VERSION 5.8 ;
BUSBITCHARS "[]" ;
DIVIDERCHAR "/" ;
UNITS
    DATABASE MICRONS 1000 ;
END UNITS

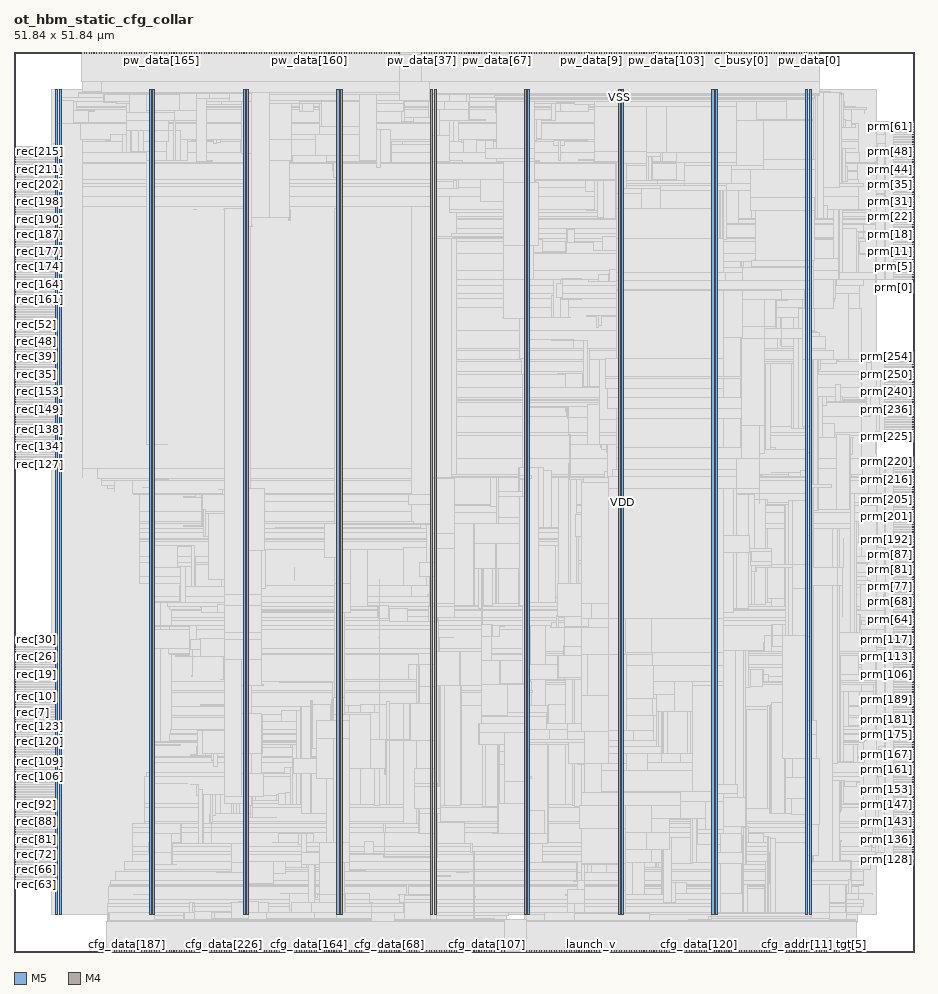
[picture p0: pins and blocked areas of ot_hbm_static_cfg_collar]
MACRO ot_hbm_static_cfg_collar
  FOREIGN ot_hbm_static_cfg_collar 0 0 ;
  CLASS BLOCK ;
  SIZE 51.84 BY 51.84 ;
  PIN active
    DIRECTION OUTPUT ;
    USE SIGNAL ;
    PORT
      LAYER M5 ;
        RECT  43.344 0 43.368 0.084 ;
    END
  END active
  PIN c_busy[0]
    DIRECTION INPUT ;
    USE SIGNAL ;
    PORT
      LAYER M5 ;
        RECT  41.904 51.756 41.928 51.84 ;
    END
  END c_busy[0]
  PIN c_busy[1]
    DIRECTION INPUT ;
    USE SIGNAL ;
    PORT
      LAYER M5 ;
        RECT  42.048 51.756 42.072 51.84 ;
    END
  END c_busy[1]
  PIN c_done
    DIRECTION INPUT ;
    USE SIGNAL ;
    PORT
      LAYER M5 ;
        RECT  42.192 51.756 42.216 51.84 ;
    END
  END c_done
  PIN c_fault[0]
    DIRECTION INPUT ;
    USE SIGNAL ;
    PORT
      LAYER M5 ;
        RECT  42.336 51.756 42.36 51.84 ;
    END
  END c_fault[0]
  PIN cfg_addr[0]
    DIRECTION INPUT ;
    USE SIGNAL ;
    PORT
      LAYER M5 ;
        RECT  43.488 0 43.512 0.084 ;
    END
  END cfg_addr[0]
  PIN cfg_addr[10]
    DIRECTION INPUT ;
    USE SIGNAL ;
    PORT
      LAYER M5 ;
        RECT  44.928 0 44.952 0.084 ;
    END
  END cfg_addr[10]
  PIN cfg_addr[11]
    DIRECTION INPUT ;
    USE SIGNAL ;
    PORT
      LAYER M5 ;
        RECT  45.072 0 45.096 0.084 ;
    END
  END cfg_addr[11]
  PIN cfg_addr[1]
    DIRECTION INPUT ;
    USE SIGNAL ;
    PORT
      LAYER M5 ;
        RECT  43.632 0 43.656 0.084 ;
    END
  END cfg_addr[1]
  PIN cfg_addr[2]
    DIRECTION INPUT ;
    USE SIGNAL ;
    PORT
      LAYER M5 ;
        RECT  43.776 0 43.8 0.084 ;
    END
  END cfg_addr[2]
  PIN cfg_addr[3]
    DIRECTION INPUT ;
    USE SIGNAL ;
    PORT
      LAYER M5 ;
        RECT  43.92 0 43.944 0.084 ;
    END
  END cfg_addr[3]
  PIN cfg_addr[4]
    DIRECTION INPUT ;
    USE SIGNAL ;
    PORT
      LAYER M5 ;
        RECT  44.064 0 44.088 0.084 ;
    END
  END cfg_addr[4]
  PIN cfg_addr[5]
    DIRECTION INPUT ;
    USE SIGNAL ;
    PORT
      LAYER M5 ;
        RECT  44.208 0 44.232 0.084 ;
    END
  END cfg_addr[5]
  PIN cfg_addr[6]
    DIRECTION INPUT ;
    USE SIGNAL ;
    PORT
      LAYER M5 ;
        RECT  44.352 0 44.376 0.084 ;
    END
  END cfg_addr[6]
  PIN cfg_addr[7]
    DIRECTION INPUT ;
    USE SIGNAL ;
    PORT
      LAYER M5 ;
        RECT  44.496 0 44.52 0.084 ;
    END
  END cfg_addr[7]
  PIN cfg_addr[8]
    DIRECTION INPUT ;
    USE SIGNAL ;
    PORT
      LAYER M5 ;
        RECT  44.64 0 44.664 0.084 ;
    END
  END cfg_addr[8]
  PIN cfg_addr[9]
    DIRECTION INPUT ;
    USE SIGNAL ;
    PORT
      LAYER M5 ;
        RECT  44.784 0 44.808 0.084 ;
    END
  END cfg_addr[9]
  PIN cfg_data[0]
    DIRECTION INPUT ;
    USE SIGNAL ;
    PORT
      LAYER M5 ;
        RECT  45.216 0 45.24 0.084 ;
    END
  END cfg_data[0]
  PIN cfg_data[100]
    DIRECTION INPUT ;
    USE SIGNAL ;
    PORT
      LAYER M5 ;
        RECT  26.208 0 26.232 0.084 ;
    END
  END cfg_data[100]
  PIN cfg_data[101]
    DIRECTION INPUT ;
    USE SIGNAL ;
    PORT
      LAYER M5 ;
        RECT  26.352 0 26.376 0.084 ;
    END
  END cfg_data[101]
  PIN cfg_data[102]
    DIRECTION INPUT ;
    USE SIGNAL ;
    PORT
      LAYER M5 ;
        RECT  26.496 0 26.52 0.084 ;
    END
  END cfg_data[102]
  PIN cfg_data[103]
    DIRECTION INPUT ;
    USE SIGNAL ;
    PORT
      LAYER M5 ;
        RECT  26.64 0 26.664 0.084 ;
    END
  END cfg_data[103]
  PIN cfg_data[104]
    DIRECTION INPUT ;
    USE SIGNAL ;
    PORT
      LAYER M5 ;
        RECT  26.784 0 26.808 0.084 ;
    END
  END cfg_data[104]
  PIN cfg_data[105]
    DIRECTION INPUT ;
    USE SIGNAL ;
    PORT
      LAYER M5 ;
        RECT  26.928 0 26.952 0.084 ;
    END
  END cfg_data[105]
  PIN cfg_data[106]
    DIRECTION INPUT ;
    USE SIGNAL ;
    PORT
      LAYER M5 ;
        RECT  27.072 0 27.096 0.084 ;
    END
  END cfg_data[106]
  PIN cfg_data[107]
    DIRECTION INPUT ;
    USE SIGNAL ;
    PORT
      LAYER M5 ;
        RECT  27.216 0 27.24 0.084 ;
    END
  END cfg_data[107]
  PIN cfg_data[108]
    DIRECTION INPUT ;
    USE SIGNAL ;
    PORT
      LAYER M5 ;
        RECT  27.36 0 27.384 0.084 ;
    END
  END cfg_data[108]
  PIN cfg_data[109]
    DIRECTION INPUT ;
    USE SIGNAL ;
    PORT
      LAYER M5 ;
        RECT  27.504 0 27.528 0.084 ;
    END
  END cfg_data[109]
  PIN cfg_data[10]
    DIRECTION INPUT ;
    USE SIGNAL ;
    PORT
      LAYER M5 ;
        RECT  46.656 0 46.68 0.084 ;
    END
  END cfg_data[10]
  PIN cfg_data[110]
    DIRECTION INPUT ;
    USE SIGNAL ;
    PORT
      LAYER M5 ;
        RECT  27.648 0 27.672 0.084 ;
    END
  END cfg_data[110]
  PIN cfg_data[111]
    DIRECTION INPUT ;
    USE SIGNAL ;
    PORT
      LAYER M5 ;
        RECT  27.792 0 27.816 0.084 ;
    END
  END cfg_data[111]
  PIN cfg_data[112]
    DIRECTION INPUT ;
    USE SIGNAL ;
    PORT
      LAYER M5 ;
        RECT  27.936 0 27.96 0.084 ;
    END
  END cfg_data[112]
  PIN cfg_data[113]
    DIRECTION INPUT ;
    USE SIGNAL ;
    PORT
      LAYER M5 ;
        RECT  28.08 0 28.104 0.084 ;
    END
  END cfg_data[113]
  PIN cfg_data[114]
    DIRECTION INPUT ;
    USE SIGNAL ;
    PORT
      LAYER M5 ;
        RECT  28.224 0 28.248 0.084 ;
    END
  END cfg_data[114]
  PIN cfg_data[115]
    DIRECTION INPUT ;
    USE SIGNAL ;
    PORT
      LAYER M5 ;
        RECT  38.736 0 38.76 0.084 ;
    END
  END cfg_data[115]
  PIN cfg_data[116]
    DIRECTION INPUT ;
    USE SIGNAL ;
    PORT
      LAYER M5 ;
        RECT  38.88 0 38.904 0.084 ;
    END
  END cfg_data[116]
  PIN cfg_data[117]
    DIRECTION INPUT ;
    USE SIGNAL ;
    PORT
      LAYER M5 ;
        RECT  39.024 0 39.048 0.084 ;
    END
  END cfg_data[117]
  PIN cfg_data[118]
    DIRECTION INPUT ;
    USE SIGNAL ;
    PORT
      LAYER M5 ;
        RECT  39.168 0 39.192 0.084 ;
    END
  END cfg_data[118]
  PIN cfg_data[119]
    DIRECTION INPUT ;
    USE SIGNAL ;
    PORT
      LAYER M5 ;
        RECT  39.312 0 39.336 0.084 ;
    END
  END cfg_data[119]
  PIN cfg_data[11]
    DIRECTION INPUT ;
    USE SIGNAL ;
    PORT
      LAYER M5 ;
        RECT  46.8 0 46.824 0.084 ;
    END
  END cfg_data[11]
  PIN cfg_data[120]
    DIRECTION INPUT ;
    USE SIGNAL ;
    PORT
      LAYER M5 ;
        RECT  39.456 0 39.48 0.084 ;
    END
  END cfg_data[120]
  PIN cfg_data[121]
    DIRECTION INPUT ;
    USE SIGNAL ;
    PORT
      LAYER M5 ;
        RECT  39.6 0 39.624 0.084 ;
    END
  END cfg_data[121]
  PIN cfg_data[122]
    DIRECTION INPUT ;
    USE SIGNAL ;
    PORT
      LAYER M5 ;
        RECT  39.744 0 39.768 0.084 ;
    END
  END cfg_data[122]
  PIN cfg_data[123]
    DIRECTION INPUT ;
    USE SIGNAL ;
    PORT
      LAYER M5 ;
        RECT  39.888 0 39.912 0.084 ;
    END
  END cfg_data[123]
  PIN cfg_data[124]
    DIRECTION INPUT ;
    USE SIGNAL ;
    PORT
      LAYER M5 ;
        RECT  40.032 0 40.056 0.084 ;
    END
  END cfg_data[124]
  PIN cfg_data[125]
    DIRECTION INPUT ;
    USE SIGNAL ;
    PORT
      LAYER M5 ;
        RECT  40.176 0 40.2 0.084 ;
    END
  END cfg_data[125]
  PIN cfg_data[126]
    DIRECTION INPUT ;
    USE SIGNAL ;
    PORT
      LAYER M5 ;
        RECT  40.32 0 40.344 0.084 ;
    END
  END cfg_data[126]
  PIN cfg_data[127]
    DIRECTION INPUT ;
    USE SIGNAL ;
    PORT
      LAYER M5 ;
        RECT  40.464 0 40.488 0.084 ;
    END
  END cfg_data[127]
  PIN cfg_data[128]
    DIRECTION INPUT ;
    USE SIGNAL ;
    PORT
      LAYER M5 ;
        RECT  40.608 0 40.632 0.084 ;
    END
  END cfg_data[128]
  PIN cfg_data[129]
    DIRECTION INPUT ;
    USE SIGNAL ;
    PORT
      LAYER M5 ;
        RECT  40.752 0 40.776 0.084 ;
    END
  END cfg_data[129]
  PIN cfg_data[12]
    DIRECTION INPUT ;
    USE SIGNAL ;
    PORT
      LAYER M5 ;
        RECT  46.944 0 46.968 0.084 ;
    END
  END cfg_data[12]
  PIN cfg_data[130]
    DIRECTION INPUT ;
    USE SIGNAL ;
    PORT
      LAYER M5 ;
        RECT  40.896 0 40.92 0.084 ;
    END
  END cfg_data[130]
  PIN cfg_data[131]
    DIRECTION INPUT ;
    USE SIGNAL ;
    PORT
      LAYER M5 ;
        RECT  41.04 0 41.064 0.084 ;
    END
  END cfg_data[131]
  PIN cfg_data[132]
    DIRECTION INPUT ;
    USE SIGNAL ;
    PORT
      LAYER M5 ;
        RECT  41.184 0 41.208 0.084 ;
    END
  END cfg_data[132]
  PIN cfg_data[133]
    DIRECTION INPUT ;
    USE SIGNAL ;
    PORT
      LAYER M5 ;
        RECT  41.328 0 41.352 0.084 ;
    END
  END cfg_data[133]
  PIN cfg_data[134]
    DIRECTION INPUT ;
    USE SIGNAL ;
    PORT
      LAYER M5 ;
        RECT  41.472 0 41.496 0.084 ;
    END
  END cfg_data[134]
  PIN cfg_data[135]
    DIRECTION INPUT ;
    USE SIGNAL ;
    PORT
      LAYER M5 ;
        RECT  41.616 0 41.64 0.084 ;
    END
  END cfg_data[135]
  PIN cfg_data[136]
    DIRECTION INPUT ;
    USE SIGNAL ;
    PORT
      LAYER M5 ;
        RECT  41.76 0 41.784 0.084 ;
    END
  END cfg_data[136]
  PIN cfg_data[137]
    DIRECTION INPUT ;
    USE SIGNAL ;
    PORT
      LAYER M5 ;
        RECT  41.904 0 41.928 0.084 ;
    END
  END cfg_data[137]
  PIN cfg_data[138]
    DIRECTION INPUT ;
    USE SIGNAL ;
    PORT
      LAYER M5 ;
        RECT  42.048 0 42.072 0.084 ;
    END
  END cfg_data[138]
  PIN cfg_data[139]
    DIRECTION INPUT ;
    USE SIGNAL ;
    PORT
      LAYER M5 ;
        RECT  42.192 0 42.216 0.084 ;
    END
  END cfg_data[139]
  PIN cfg_data[13]
    DIRECTION INPUT ;
    USE SIGNAL ;
    PORT
      LAYER M5 ;
        RECT  47.088 0 47.112 0.084 ;
    END
  END cfg_data[13]
  PIN cfg_data[140]
    DIRECTION INPUT ;
    USE SIGNAL ;
    PORT
      LAYER M5 ;
        RECT  42.336 0 42.36 0.084 ;
    END
  END cfg_data[140]
  PIN cfg_data[141]
    DIRECTION INPUT ;
    USE SIGNAL ;
    PORT
      LAYER M5 ;
        RECT  42.48 0 42.504 0.084 ;
    END
  END cfg_data[141]
  PIN cfg_data[142]
    DIRECTION INPUT ;
    USE SIGNAL ;
    PORT
      LAYER M5 ;
        RECT  42.624 0 42.648 0.084 ;
    END
  END cfg_data[142]
  PIN cfg_data[143]
    DIRECTION INPUT ;
    USE SIGNAL ;
    PORT
      LAYER M5 ;
        RECT  42.768 0 42.792 0.084 ;
    END
  END cfg_data[143]
  PIN cfg_data[144]
    DIRECTION INPUT ;
    USE SIGNAL ;
    PORT
      LAYER M5 ;
        RECT  42.912 0 42.936 0.084 ;
    END
  END cfg_data[144]
  PIN cfg_data[145]
    DIRECTION INPUT ;
    USE SIGNAL ;
    PORT
      LAYER M5 ;
        RECT  43.056 0 43.08 0.084 ;
    END
  END cfg_data[145]
  PIN cfg_data[146]
    DIRECTION INPUT ;
    USE SIGNAL ;
    PORT
      LAYER M5 ;
        RECT  43.2 0 43.224 0.084 ;
    END
  END cfg_data[146]
  PIN cfg_data[147]
    DIRECTION INPUT ;
    USE SIGNAL ;
    PORT
      LAYER M5 ;
        RECT  14.544 0 14.568 0.084 ;
    END
  END cfg_data[147]
  PIN cfg_data[148]
    DIRECTION INPUT ;
    USE SIGNAL ;
    PORT
      LAYER M5 ;
        RECT  14.688 0 14.712 0.084 ;
    END
  END cfg_data[148]
  PIN cfg_data[149]
    DIRECTION INPUT ;
    USE SIGNAL ;
    PORT
      LAYER M5 ;
        RECT  14.832 0 14.856 0.084 ;
    END
  END cfg_data[149]
  PIN cfg_data[14]
    DIRECTION INPUT ;
    USE SIGNAL ;
    PORT
      LAYER M5 ;
        RECT  47.232 0 47.256 0.084 ;
    END
  END cfg_data[14]
  PIN cfg_data[150]
    DIRECTION INPUT ;
    USE SIGNAL ;
    PORT
      LAYER M5 ;
        RECT  14.976 0 15 0.084 ;
    END
  END cfg_data[150]
  PIN cfg_data[151]
    DIRECTION INPUT ;
    USE SIGNAL ;
    PORT
      LAYER M5 ;
        RECT  15.12 0 15.144 0.084 ;
    END
  END cfg_data[151]
  PIN cfg_data[152]
    DIRECTION INPUT ;
    USE SIGNAL ;
    PORT
      LAYER M5 ;
        RECT  15.264 0 15.288 0.084 ;
    END
  END cfg_data[152]
  PIN cfg_data[153]
    DIRECTION INPUT ;
    USE SIGNAL ;
    PORT
      LAYER M5 ;
        RECT  15.408 0 15.432 0.084 ;
    END
  END cfg_data[153]
  PIN cfg_data[154]
    DIRECTION INPUT ;
    USE SIGNAL ;
    PORT
      LAYER M5 ;
        RECT  15.552 0 15.576 0.084 ;
    END
  END cfg_data[154]
  PIN cfg_data[155]
    DIRECTION INPUT ;
    USE SIGNAL ;
    PORT
      LAYER M5 ;
        RECT  15.696 0 15.72 0.084 ;
    END
  END cfg_data[155]
  PIN cfg_data[156]
    DIRECTION INPUT ;
    USE SIGNAL ;
    PORT
      LAYER M5 ;
        RECT  15.84 0 15.864 0.084 ;
    END
  END cfg_data[156]
  PIN cfg_data[157]
    DIRECTION INPUT ;
    USE SIGNAL ;
    PORT
      LAYER M5 ;
        RECT  15.984 0 16.008 0.084 ;
    END
  END cfg_data[157]
  PIN cfg_data[158]
    DIRECTION INPUT ;
    USE SIGNAL ;
    PORT
      LAYER M5 ;
        RECT  16.128 0 16.152 0.084 ;
    END
  END cfg_data[158]
  PIN cfg_data[159]
    DIRECTION INPUT ;
    USE SIGNAL ;
    PORT
      LAYER M5 ;
        RECT  16.272 0 16.296 0.084 ;
    END
  END cfg_data[159]
  PIN cfg_data[15]
    DIRECTION INPUT ;
    USE SIGNAL ;
    PORT
      LAYER M5 ;
        RECT  47.376 0 47.4 0.084 ;
    END
  END cfg_data[15]
  PIN cfg_data[160]
    DIRECTION INPUT ;
    USE SIGNAL ;
    PORT
      LAYER M5 ;
        RECT  16.416 0 16.44 0.084 ;
    END
  END cfg_data[160]
  PIN cfg_data[161]
    DIRECTION INPUT ;
    USE SIGNAL ;
    PORT
      LAYER M5 ;
        RECT  16.56 0 16.584 0.084 ;
    END
  END cfg_data[161]
  PIN cfg_data[162]
    DIRECTION INPUT ;
    USE SIGNAL ;
    PORT
      LAYER M5 ;
        RECT  16.704 0 16.728 0.084 ;
    END
  END cfg_data[162]
  PIN cfg_data[163]
    DIRECTION INPUT ;
    USE SIGNAL ;
    PORT
      LAYER M5 ;
        RECT  16.848 0 16.872 0.084 ;
    END
  END cfg_data[163]
  PIN cfg_data[164]
    DIRECTION INPUT ;
    USE SIGNAL ;
    PORT
      LAYER M5 ;
        RECT  16.992 0 17.016 0.084 ;
    END
  END cfg_data[164]
  PIN cfg_data[165]
    DIRECTION INPUT ;
    USE SIGNAL ;
    PORT
      LAYER M5 ;
        RECT  17.136 0 17.16 0.084 ;
    END
  END cfg_data[165]
  PIN cfg_data[166]
    DIRECTION INPUT ;
    USE SIGNAL ;
    PORT
      LAYER M5 ;
        RECT  17.28 0 17.304 0.084 ;
    END
  END cfg_data[166]
  PIN cfg_data[167]
    DIRECTION INPUT ;
    USE SIGNAL ;
    PORT
      LAYER M5 ;
        RECT  17.424 0 17.448 0.084 ;
    END
  END cfg_data[167]
  PIN cfg_data[168]
    DIRECTION INPUT ;
    USE SIGNAL ;
    PORT
      LAYER M5 ;
        RECT  17.568 0 17.592 0.084 ;
    END
  END cfg_data[168]
  PIN cfg_data[169]
    DIRECTION INPUT ;
    USE SIGNAL ;
    PORT
      LAYER M5 ;
        RECT  17.712 0 17.736 0.084 ;
    END
  END cfg_data[169]
  PIN cfg_data[16]
    DIRECTION INPUT ;
    USE SIGNAL ;
    PORT
      LAYER M5 ;
        RECT  47.52 0 47.544 0.084 ;
    END
  END cfg_data[16]
  PIN cfg_data[170]
    DIRECTION INPUT ;
    USE SIGNAL ;
    PORT
      LAYER M5 ;
        RECT  17.856 0 17.88 0.084 ;
    END
  END cfg_data[170]
  PIN cfg_data[171]
    DIRECTION INPUT ;
    USE SIGNAL ;
    PORT
      LAYER M5 ;
        RECT  18 0 18.024 0.084 ;
    END
  END cfg_data[171]
  PIN cfg_data[172]
    DIRECTION INPUT ;
    USE SIGNAL ;
    PORT
      LAYER M5 ;
        RECT  18.144 0 18.168 0.084 ;
    END
  END cfg_data[172]
  PIN cfg_data[173]
    DIRECTION INPUT ;
    USE SIGNAL ;
    PORT
      LAYER M5 ;
        RECT  18.288 0 18.312 0.084 ;
    END
  END cfg_data[173]
  PIN cfg_data[174]
    DIRECTION INPUT ;
    USE SIGNAL ;
    PORT
      LAYER M5 ;
        RECT  18.432 0 18.456 0.084 ;
    END
  END cfg_data[174]
  PIN cfg_data[175]
    DIRECTION INPUT ;
    USE SIGNAL ;
    PORT
      LAYER M5 ;
        RECT  18.576 0 18.6 0.084 ;
    END
  END cfg_data[175]
  PIN cfg_data[176]
    DIRECTION INPUT ;
    USE SIGNAL ;
    PORT
      LAYER M5 ;
        RECT  18.72 0 18.744 0.084 ;
    END
  END cfg_data[176]
  PIN cfg_data[177]
    DIRECTION INPUT ;
    USE SIGNAL ;
    PORT
      LAYER M5 ;
        RECT  18.864 0 18.888 0.084 ;
    END
  END cfg_data[177]
  PIN cfg_data[178]
    DIRECTION INPUT ;
    USE SIGNAL ;
    PORT
      LAYER M5 ;
        RECT  19.008 0 19.032 0.084 ;
    END
  END cfg_data[178]
  PIN cfg_data[179]
    DIRECTION INPUT ;
    USE SIGNAL ;
    PORT
      LAYER M5 ;
        RECT  5.328 0 5.352 0.084 ;
    END
  END cfg_data[179]
  PIN cfg_data[17]
    DIRECTION INPUT ;
    USE SIGNAL ;
    PORT
      LAYER M5 ;
        RECT  47.664 0 47.688 0.084 ;
    END
  END cfg_data[17]
  PIN cfg_data[180]
    DIRECTION INPUT ;
    USE SIGNAL ;
    PORT
      LAYER M5 ;
        RECT  5.472 0 5.496 0.084 ;
    END
  END cfg_data[180]
  PIN cfg_data[181]
    DIRECTION INPUT ;
    USE SIGNAL ;
    PORT
      LAYER M5 ;
        RECT  5.616 0 5.64 0.084 ;
    END
  END cfg_data[181]
  PIN cfg_data[182]
    DIRECTION INPUT ;
    USE SIGNAL ;
    PORT
      LAYER M5 ;
        RECT  5.76 0 5.784 0.084 ;
    END
  END cfg_data[182]
  PIN cfg_data[183]
    DIRECTION INPUT ;
    USE SIGNAL ;
    PORT
      LAYER M5 ;
        RECT  5.904 0 5.928 0.084 ;
    END
  END cfg_data[183]
  PIN cfg_data[184]
    DIRECTION INPUT ;
    USE SIGNAL ;
    PORT
      LAYER M5 ;
        RECT  6.048 0 6.072 0.084 ;
    END
  END cfg_data[184]
  PIN cfg_data[185]
    DIRECTION INPUT ;
    USE SIGNAL ;
    PORT
      LAYER M5 ;
        RECT  6.192 0 6.216 0.084 ;
    END
  END cfg_data[185]
  PIN cfg_data[186]
    DIRECTION INPUT ;
    USE SIGNAL ;
    PORT
      LAYER M5 ;
        RECT  6.336 0 6.36 0.084 ;
    END
  END cfg_data[186]
  PIN cfg_data[187]
    DIRECTION INPUT ;
    USE SIGNAL ;
    PORT
      LAYER M5 ;
        RECT  6.48 0 6.504 0.084 ;
    END
  END cfg_data[187]
  PIN cfg_data[188]
    DIRECTION INPUT ;
    USE SIGNAL ;
    PORT
      LAYER M5 ;
        RECT  6.624 0 6.648 0.084 ;
    END
  END cfg_data[188]
  PIN cfg_data[189]
    DIRECTION INPUT ;
    USE SIGNAL ;
    PORT
      LAYER M5 ;
        RECT  6.768 0 6.792 0.084 ;
    END
  END cfg_data[189]
  PIN cfg_data[18]
    DIRECTION INPUT ;
    USE SIGNAL ;
    PORT
      LAYER M5 ;
        RECT  47.808 0 47.832 0.084 ;
    END
  END cfg_data[18]
  PIN cfg_data[190]
    DIRECTION INPUT ;
    USE SIGNAL ;
    PORT
      LAYER M5 ;
        RECT  6.912 0 6.936 0.084 ;
    END
  END cfg_data[190]
  PIN cfg_data[191]
    DIRECTION INPUT ;
    USE SIGNAL ;
    PORT
      LAYER M5 ;
        RECT  7.056 0 7.08 0.084 ;
    END
  END cfg_data[191]
  PIN cfg_data[192]
    DIRECTION INPUT ;
    USE SIGNAL ;
    PORT
      LAYER M5 ;
        RECT  7.2 0 7.224 0.084 ;
    END
  END cfg_data[192]
  PIN cfg_data[193]
    DIRECTION INPUT ;
    USE SIGNAL ;
    PORT
      LAYER M5 ;
        RECT  7.344 0 7.368 0.084 ;
    END
  END cfg_data[193]
  PIN cfg_data[194]
    DIRECTION INPUT ;
    USE SIGNAL ;
    PORT
      LAYER M5 ;
        RECT  7.488 0 7.512 0.084 ;
    END
  END cfg_data[194]
  PIN cfg_data[195]
    DIRECTION INPUT ;
    USE SIGNAL ;
    PORT
      LAYER M5 ;
        RECT  7.632 0 7.656 0.084 ;
    END
  END cfg_data[195]
  PIN cfg_data[196]
    DIRECTION INPUT ;
    USE SIGNAL ;
    PORT
      LAYER M5 ;
        RECT  7.776 0 7.8 0.084 ;
    END
  END cfg_data[196]
  PIN cfg_data[197]
    DIRECTION INPUT ;
    USE SIGNAL ;
    PORT
      LAYER M5 ;
        RECT  7.92 0 7.944 0.084 ;
    END
  END cfg_data[197]
  PIN cfg_data[198]
    DIRECTION INPUT ;
    USE SIGNAL ;
    PORT
      LAYER M5 ;
        RECT  8.064 0 8.088 0.084 ;
    END
  END cfg_data[198]
  PIN cfg_data[199]
    DIRECTION INPUT ;
    USE SIGNAL ;
    PORT
      LAYER M5 ;
        RECT  8.208 0 8.232 0.084 ;
    END
  END cfg_data[199]
  PIN cfg_data[19]
    DIRECTION INPUT ;
    USE SIGNAL ;
    PORT
      LAYER M5 ;
        RECT  34.128 0 34.152 0.084 ;
    END
  END cfg_data[19]
  PIN cfg_data[1]
    DIRECTION INPUT ;
    USE SIGNAL ;
    PORT
      LAYER M5 ;
        RECT  45.36 0 45.384 0.084 ;
    END
  END cfg_data[1]
  PIN cfg_data[200]
    DIRECTION INPUT ;
    USE SIGNAL ;
    PORT
      LAYER M5 ;
        RECT  8.352 0 8.376 0.084 ;
    END
  END cfg_data[200]
  PIN cfg_data[201]
    DIRECTION INPUT ;
    USE SIGNAL ;
    PORT
      LAYER M5 ;
        RECT  8.496 0 8.52 0.084 ;
    END
  END cfg_data[201]
  PIN cfg_data[202]
    DIRECTION INPUT ;
    USE SIGNAL ;
    PORT
      LAYER M5 ;
        RECT  8.64 0 8.664 0.084 ;
    END
  END cfg_data[202]
  PIN cfg_data[203]
    DIRECTION INPUT ;
    USE SIGNAL ;
    PORT
      LAYER M5 ;
        RECT  8.784 0 8.808 0.084 ;
    END
  END cfg_data[203]
  PIN cfg_data[204]
    DIRECTION INPUT ;
    USE SIGNAL ;
    PORT
      LAYER M5 ;
        RECT  8.928 0 8.952 0.084 ;
    END
  END cfg_data[204]
  PIN cfg_data[205]
    DIRECTION INPUT ;
    USE SIGNAL ;
    PORT
      LAYER M5 ;
        RECT  9.072 0 9.096 0.084 ;
    END
  END cfg_data[205]
  PIN cfg_data[206]
    DIRECTION INPUT ;
    USE SIGNAL ;
    PORT
      LAYER M5 ;
        RECT  9.216 0 9.24 0.084 ;
    END
  END cfg_data[206]
  PIN cfg_data[207]
    DIRECTION INPUT ;
    USE SIGNAL ;
    PORT
      LAYER M5 ;
        RECT  9.36 0 9.384 0.084 ;
    END
  END cfg_data[207]
  PIN cfg_data[208]
    DIRECTION INPUT ;
    USE SIGNAL ;
    PORT
      LAYER M5 ;
        RECT  9.504 0 9.528 0.084 ;
    END
  END cfg_data[208]
  PIN cfg_data[209]
    DIRECTION INPUT ;
    USE SIGNAL ;
    PORT
      LAYER M5 ;
        RECT  9.648 0 9.672 0.084 ;
    END
  END cfg_data[209]
  PIN cfg_data[20]
    DIRECTION INPUT ;
    USE SIGNAL ;
    PORT
      LAYER M5 ;
        RECT  34.272 0 34.296 0.084 ;
    END
  END cfg_data[20]
  PIN cfg_data[210]
    DIRECTION INPUT ;
    USE SIGNAL ;
    PORT
      LAYER M5 ;
        RECT  9.792 0 9.816 0.084 ;
    END
  END cfg_data[210]
  PIN cfg_data[211]
    DIRECTION INPUT ;
    USE SIGNAL ;
    PORT
      LAYER M5 ;
        RECT  9.936 0 9.96 0.084 ;
    END
  END cfg_data[211]
  PIN cfg_data[212]
    DIRECTION INPUT ;
    USE SIGNAL ;
    PORT
      LAYER M5 ;
        RECT  10.08 0 10.104 0.084 ;
    END
  END cfg_data[212]
  PIN cfg_data[213]
    DIRECTION INPUT ;
    USE SIGNAL ;
    PORT
      LAYER M5 ;
        RECT  10.224 0 10.248 0.084 ;
    END
  END cfg_data[213]
  PIN cfg_data[214]
    DIRECTION INPUT ;
    USE SIGNAL ;
    PORT
      LAYER M5 ;
        RECT  10.368 0 10.392 0.084 ;
    END
  END cfg_data[214]
  PIN cfg_data[215]
    DIRECTION INPUT ;
    USE SIGNAL ;
    PORT
      LAYER M5 ;
        RECT  10.512 0 10.536 0.084 ;
    END
  END cfg_data[215]
  PIN cfg_data[216]
    DIRECTION INPUT ;
    USE SIGNAL ;
    PORT
      LAYER M5 ;
        RECT  10.656 0 10.68 0.084 ;
    END
  END cfg_data[216]
  PIN cfg_data[217]
    DIRECTION INPUT ;
    USE SIGNAL ;
    PORT
      LAYER M5 ;
        RECT  10.8 0 10.824 0.084 ;
    END
  END cfg_data[217]
  PIN cfg_data[218]
    DIRECTION INPUT ;
    USE SIGNAL ;
    PORT
      LAYER M5 ;
        RECT  10.944 0 10.968 0.084 ;
    END
  END cfg_data[218]
  PIN cfg_data[219]
    DIRECTION INPUT ;
    USE SIGNAL ;
    PORT
      LAYER M5 ;
        RECT  11.088 0 11.112 0.084 ;
    END
  END cfg_data[219]
  PIN cfg_data[21]
    DIRECTION INPUT ;
    USE SIGNAL ;
    PORT
      LAYER M5 ;
        RECT  34.416 0 34.44 0.084 ;
    END
  END cfg_data[21]
  PIN cfg_data[220]
    DIRECTION INPUT ;
    USE SIGNAL ;
    PORT
      LAYER M5 ;
        RECT  11.232 0 11.256 0.084 ;
    END
  END cfg_data[220]
  PIN cfg_data[221]
    DIRECTION INPUT ;
    USE SIGNAL ;
    PORT
      LAYER M5 ;
        RECT  11.376 0 11.4 0.084 ;
    END
  END cfg_data[221]
  PIN cfg_data[222]
    DIRECTION INPUT ;
    USE SIGNAL ;
    PORT
      LAYER M5 ;
        RECT  11.52 0 11.544 0.084 ;
    END
  END cfg_data[222]
  PIN cfg_data[223]
    DIRECTION INPUT ;
    USE SIGNAL ;
    PORT
      LAYER M5 ;
        RECT  11.664 0 11.688 0.084 ;
    END
  END cfg_data[223]
  PIN cfg_data[224]
    DIRECTION INPUT ;
    USE SIGNAL ;
    PORT
      LAYER M5 ;
        RECT  11.808 0 11.832 0.084 ;
    END
  END cfg_data[224]
  PIN cfg_data[225]
    DIRECTION INPUT ;
    USE SIGNAL ;
    PORT
      LAYER M5 ;
        RECT  11.952 0 11.976 0.084 ;
    END
  END cfg_data[225]
  PIN cfg_data[226]
    DIRECTION INPUT ;
    USE SIGNAL ;
    PORT
      LAYER M5 ;
        RECT  12.096 0 12.12 0.084 ;
    END
  END cfg_data[226]
  PIN cfg_data[227]
    DIRECTION INPUT ;
    USE SIGNAL ;
    PORT
      LAYER M5 ;
        RECT  12.24 0 12.264 0.084 ;
    END
  END cfg_data[227]
  PIN cfg_data[228]
    DIRECTION INPUT ;
    USE SIGNAL ;
    PORT
      LAYER M5 ;
        RECT  12.384 0 12.408 0.084 ;
    END
  END cfg_data[228]
  PIN cfg_data[229]
    DIRECTION INPUT ;
    USE SIGNAL ;
    PORT
      LAYER M5 ;
        RECT  12.528 0 12.552 0.084 ;
    END
  END cfg_data[229]
  PIN cfg_data[22]
    DIRECTION INPUT ;
    USE SIGNAL ;
    PORT
      LAYER M5 ;
        RECT  34.56 0 34.584 0.084 ;
    END
  END cfg_data[22]
  PIN cfg_data[230]
    DIRECTION INPUT ;
    USE SIGNAL ;
    PORT
      LAYER M5 ;
        RECT  12.672 0 12.696 0.084 ;
    END
  END cfg_data[230]
  PIN cfg_data[231]
    DIRECTION INPUT ;
    USE SIGNAL ;
    PORT
      LAYER M5 ;
        RECT  12.816 0 12.84 0.084 ;
    END
  END cfg_data[231]
  PIN cfg_data[232]
    DIRECTION INPUT ;
    USE SIGNAL ;
    PORT
      LAYER M5 ;
        RECT  12.96 0 12.984 0.084 ;
    END
  END cfg_data[232]
  PIN cfg_data[233]
    DIRECTION INPUT ;
    USE SIGNAL ;
    PORT
      LAYER M5 ;
        RECT  13.104 0 13.128 0.084 ;
    END
  END cfg_data[233]
  PIN cfg_data[234]
    DIRECTION INPUT ;
    USE SIGNAL ;
    PORT
      LAYER M5 ;
        RECT  13.248 0 13.272 0.084 ;
    END
  END cfg_data[234]
  PIN cfg_data[235]
    DIRECTION INPUT ;
    USE SIGNAL ;
    PORT
      LAYER M5 ;
        RECT  13.392 0 13.416 0.084 ;
    END
  END cfg_data[235]
  PIN cfg_data[236]
    DIRECTION INPUT ;
    USE SIGNAL ;
    PORT
      LAYER M5 ;
        RECT  13.536 0 13.56 0.084 ;
    END
  END cfg_data[236]
  PIN cfg_data[237]
    DIRECTION INPUT ;
    USE SIGNAL ;
    PORT
      LAYER M5 ;
        RECT  13.68 0 13.704 0.084 ;
    END
  END cfg_data[237]
  PIN cfg_data[238]
    DIRECTION INPUT ;
    USE SIGNAL ;
    PORT
      LAYER M5 ;
        RECT  13.824 0 13.848 0.084 ;
    END
  END cfg_data[238]
  PIN cfg_data[239]
    DIRECTION INPUT ;
    USE SIGNAL ;
    PORT
      LAYER M5 ;
        RECT  13.968 0 13.992 0.084 ;
    END
  END cfg_data[239]
  PIN cfg_data[23]
    DIRECTION INPUT ;
    USE SIGNAL ;
    PORT
      LAYER M5 ;
        RECT  34.704 0 34.728 0.084 ;
    END
  END cfg_data[23]
  PIN cfg_data[240]
    DIRECTION INPUT ;
    USE SIGNAL ;
    PORT
      LAYER M5 ;
        RECT  14.112 0 14.136 0.084 ;
    END
  END cfg_data[240]
  PIN cfg_data[241]
    DIRECTION INPUT ;
    USE SIGNAL ;
    PORT
      LAYER M5 ;
        RECT  14.256 0 14.28 0.084 ;
    END
  END cfg_data[241]
  PIN cfg_data[242]
    DIRECTION INPUT ;
    USE SIGNAL ;
    PORT
      LAYER M5 ;
        RECT  14.4 0 14.424 0.084 ;
    END
  END cfg_data[242]
  PIN cfg_data[243]
    DIRECTION INPUT ;
    USE SIGNAL ;
    PORT
      LAYER M5 ;
        RECT  29.52 0 29.544 0.084 ;
    END
  END cfg_data[243]
  PIN cfg_data[244]
    DIRECTION INPUT ;
    USE SIGNAL ;
    PORT
      LAYER M5 ;
        RECT  29.664 0 29.688 0.084 ;
    END
  END cfg_data[244]
  PIN cfg_data[245]
    DIRECTION INPUT ;
    USE SIGNAL ;
    PORT
      LAYER M5 ;
        RECT  29.808 0 29.832 0.084 ;
    END
  END cfg_data[245]
  PIN cfg_data[246]
    DIRECTION INPUT ;
    USE SIGNAL ;
    PORT
      LAYER M5 ;
        RECT  29.952 0 29.976 0.084 ;
    END
  END cfg_data[246]
  PIN cfg_data[247]
    DIRECTION INPUT ;
    USE SIGNAL ;
    PORT
      LAYER M5 ;
        RECT  30.096 0 30.12 0.084 ;
    END
  END cfg_data[247]
  PIN cfg_data[248]
    DIRECTION INPUT ;
    USE SIGNAL ;
    PORT
      LAYER M5 ;
        RECT  30.24 0 30.264 0.084 ;
    END
  END cfg_data[248]
  PIN cfg_data[249]
    DIRECTION INPUT ;
    USE SIGNAL ;
    PORT
      LAYER M5 ;
        RECT  30.384 0 30.408 0.084 ;
    END
  END cfg_data[249]
  PIN cfg_data[24]
    DIRECTION INPUT ;
    USE SIGNAL ;
    PORT
      LAYER M5 ;
        RECT  34.848 0 34.872 0.084 ;
    END
  END cfg_data[24]
  PIN cfg_data[250]
    DIRECTION INPUT ;
    USE SIGNAL ;
    PORT
      LAYER M5 ;
        RECT  30.528 0 30.552 0.084 ;
    END
  END cfg_data[250]
  PIN cfg_data[251]
    DIRECTION INPUT ;
    USE SIGNAL ;
    PORT
      LAYER M5 ;
        RECT  30.672 0 30.696 0.084 ;
    END
  END cfg_data[251]
  PIN cfg_data[252]
    DIRECTION INPUT ;
    USE SIGNAL ;
    PORT
      LAYER M5 ;
        RECT  30.816 0 30.84 0.084 ;
    END
  END cfg_data[252]
  PIN cfg_data[253]
    DIRECTION INPUT ;
    USE SIGNAL ;
    PORT
      LAYER M5 ;
        RECT  30.96 0 30.984 0.084 ;
    END
  END cfg_data[253]
  PIN cfg_data[254]
    DIRECTION INPUT ;
    USE SIGNAL ;
    PORT
      LAYER M5 ;
        RECT  31.104 0 31.128 0.084 ;
    END
  END cfg_data[254]
  PIN cfg_data[255]
    DIRECTION INPUT ;
    USE SIGNAL ;
    PORT
      LAYER M5 ;
        RECT  31.248 0 31.272 0.084 ;
    END
  END cfg_data[255]
  PIN cfg_data[25]
    DIRECTION INPUT ;
    USE SIGNAL ;
    PORT
      LAYER M5 ;
        RECT  34.992 0 35.016 0.084 ;
    END
  END cfg_data[25]
  PIN cfg_data[26]
    DIRECTION INPUT ;
    USE SIGNAL ;
    PORT
      LAYER M5 ;
        RECT  35.136 0 35.16 0.084 ;
    END
  END cfg_data[26]
  PIN cfg_data[27]
    DIRECTION INPUT ;
    USE SIGNAL ;
    PORT
      LAYER M5 ;
        RECT  35.28 0 35.304 0.084 ;
    END
  END cfg_data[27]
  PIN cfg_data[28]
    DIRECTION INPUT ;
    USE SIGNAL ;
    PORT
      LAYER M5 ;
        RECT  35.424 0 35.448 0.084 ;
    END
  END cfg_data[28]
  PIN cfg_data[29]
    DIRECTION INPUT ;
    USE SIGNAL ;
    PORT
      LAYER M5 ;
        RECT  35.568 0 35.592 0.084 ;
    END
  END cfg_data[29]
  PIN cfg_data[2]
    DIRECTION INPUT ;
    USE SIGNAL ;
    PORT
      LAYER M5 ;
        RECT  45.504 0 45.528 0.084 ;
    END
  END cfg_data[2]
  PIN cfg_data[30]
    DIRECTION INPUT ;
    USE SIGNAL ;
    PORT
      LAYER M5 ;
        RECT  35.712 0 35.736 0.084 ;
    END
  END cfg_data[30]
  PIN cfg_data[31]
    DIRECTION INPUT ;
    USE SIGNAL ;
    PORT
      LAYER M5 ;
        RECT  35.856 0 35.88 0.084 ;
    END
  END cfg_data[31]
  PIN cfg_data[32]
    DIRECTION INPUT ;
    USE SIGNAL ;
    PORT
      LAYER M5 ;
        RECT  36 0 36.024 0.084 ;
    END
  END cfg_data[32]
  PIN cfg_data[33]
    DIRECTION INPUT ;
    USE SIGNAL ;
    PORT
      LAYER M5 ;
        RECT  36.144 0 36.168 0.084 ;
    END
  END cfg_data[33]
  PIN cfg_data[34]
    DIRECTION INPUT ;
    USE SIGNAL ;
    PORT
      LAYER M5 ;
        RECT  36.288 0 36.312 0.084 ;
    END
  END cfg_data[34]
  PIN cfg_data[35]
    DIRECTION INPUT ;
    USE SIGNAL ;
    PORT
      LAYER M5 ;
        RECT  36.432 0 36.456 0.084 ;
    END
  END cfg_data[35]
  PIN cfg_data[36]
    DIRECTION INPUT ;
    USE SIGNAL ;
    PORT
      LAYER M5 ;
        RECT  36.576 0 36.6 0.084 ;
    END
  END cfg_data[36]
  PIN cfg_data[37]
    DIRECTION INPUT ;
    USE SIGNAL ;
    PORT
      LAYER M5 ;
        RECT  36.72 0 36.744 0.084 ;
    END
  END cfg_data[37]
  PIN cfg_data[38]
    DIRECTION INPUT ;
    USE SIGNAL ;
    PORT
      LAYER M5 ;
        RECT  36.864 0 36.888 0.084 ;
    END
  END cfg_data[38]
  PIN cfg_data[39]
    DIRECTION INPUT ;
    USE SIGNAL ;
    PORT
      LAYER M5 ;
        RECT  37.008 0 37.032 0.084 ;
    END
  END cfg_data[39]
  PIN cfg_data[3]
    DIRECTION INPUT ;
    USE SIGNAL ;
    PORT
      LAYER M5 ;
        RECT  45.648 0 45.672 0.084 ;
    END
  END cfg_data[3]
  PIN cfg_data[40]
    DIRECTION INPUT ;
    USE SIGNAL ;
    PORT
      LAYER M5 ;
        RECT  37.152 0 37.176 0.084 ;
    END
  END cfg_data[40]
  PIN cfg_data[41]
    DIRECTION INPUT ;
    USE SIGNAL ;
    PORT
      LAYER M5 ;
        RECT  37.296 0 37.32 0.084 ;
    END
  END cfg_data[41]
  PIN cfg_data[42]
    DIRECTION INPUT ;
    USE SIGNAL ;
    PORT
      LAYER M5 ;
        RECT  37.44 0 37.464 0.084 ;
    END
  END cfg_data[42]
  PIN cfg_data[43]
    DIRECTION INPUT ;
    USE SIGNAL ;
    PORT
      LAYER M5 ;
        RECT  37.584 0 37.608 0.084 ;
    END
  END cfg_data[43]
  PIN cfg_data[44]
    DIRECTION INPUT ;
    USE SIGNAL ;
    PORT
      LAYER M5 ;
        RECT  37.728 0 37.752 0.084 ;
    END
  END cfg_data[44]
  PIN cfg_data[45]
    DIRECTION INPUT ;
    USE SIGNAL ;
    PORT
      LAYER M5 ;
        RECT  37.872 0 37.896 0.084 ;
    END
  END cfg_data[45]
  PIN cfg_data[46]
    DIRECTION INPUT ;
    USE SIGNAL ;
    PORT
      LAYER M5 ;
        RECT  38.016 0 38.04 0.084 ;
    END
  END cfg_data[46]
  PIN cfg_data[47]
    DIRECTION INPUT ;
    USE SIGNAL ;
    PORT
      LAYER M5 ;
        RECT  38.16 0 38.184 0.084 ;
    END
  END cfg_data[47]
  PIN cfg_data[48]
    DIRECTION INPUT ;
    USE SIGNAL ;
    PORT
      LAYER M5 ;
        RECT  38.304 0 38.328 0.084 ;
    END
  END cfg_data[48]
  PIN cfg_data[49]
    DIRECTION INPUT ;
    USE SIGNAL ;
    PORT
      LAYER M5 ;
        RECT  38.448 0 38.472 0.084 ;
    END
  END cfg_data[49]
  PIN cfg_data[4]
    DIRECTION INPUT ;
    USE SIGNAL ;
    PORT
      LAYER M5 ;
        RECT  45.792 0 45.816 0.084 ;
    END
  END cfg_data[4]
  PIN cfg_data[50]
    DIRECTION INPUT ;
    USE SIGNAL ;
    PORT
      LAYER M5 ;
        RECT  38.592 0 38.616 0.084 ;
    END
  END cfg_data[50]
  PIN cfg_data[51]
    DIRECTION INPUT ;
    USE SIGNAL ;
    PORT
      LAYER M5 ;
        RECT  19.152 0 19.176 0.084 ;
    END
  END cfg_data[51]
  PIN cfg_data[52]
    DIRECTION INPUT ;
    USE SIGNAL ;
    PORT
      LAYER M5 ;
        RECT  19.296 0 19.32 0.084 ;
    END
  END cfg_data[52]
  PIN cfg_data[53]
    DIRECTION INPUT ;
    USE SIGNAL ;
    PORT
      LAYER M5 ;
        RECT  19.44 0 19.464 0.084 ;
    END
  END cfg_data[53]
  PIN cfg_data[54]
    DIRECTION INPUT ;
    USE SIGNAL ;
    PORT
      LAYER M5 ;
        RECT  19.584 0 19.608 0.084 ;
    END
  END cfg_data[54]
  PIN cfg_data[55]
    DIRECTION INPUT ;
    USE SIGNAL ;
    PORT
      LAYER M5 ;
        RECT  19.728 0 19.752 0.084 ;
    END
  END cfg_data[55]
  PIN cfg_data[56]
    DIRECTION INPUT ;
    USE SIGNAL ;
    PORT
      LAYER M5 ;
        RECT  19.872 0 19.896 0.084 ;
    END
  END cfg_data[56]
  PIN cfg_data[57]
    DIRECTION INPUT ;
    USE SIGNAL ;
    PORT
      LAYER M5 ;
        RECT  20.016 0 20.04 0.084 ;
    END
  END cfg_data[57]
  PIN cfg_data[58]
    DIRECTION INPUT ;
    USE SIGNAL ;
    PORT
      LAYER M5 ;
        RECT  20.16 0 20.184 0.084 ;
    END
  END cfg_data[58]
  PIN cfg_data[59]
    DIRECTION INPUT ;
    USE SIGNAL ;
    PORT
      LAYER M5 ;
        RECT  20.304 0 20.328 0.084 ;
    END
  END cfg_data[59]
  PIN cfg_data[5]
    DIRECTION INPUT ;
    USE SIGNAL ;
    PORT
      LAYER M5 ;
        RECT  45.936 0 45.96 0.084 ;
    END
  END cfg_data[5]
  PIN cfg_data[60]
    DIRECTION INPUT ;
    USE SIGNAL ;
    PORT
      LAYER M5 ;
        RECT  20.448 0 20.472 0.084 ;
    END
  END cfg_data[60]
  PIN cfg_data[61]
    DIRECTION INPUT ;
    USE SIGNAL ;
    PORT
      LAYER M5 ;
        RECT  20.592 0 20.616 0.084 ;
    END
  END cfg_data[61]
  PIN cfg_data[62]
    DIRECTION INPUT ;
    USE SIGNAL ;
    PORT
      LAYER M5 ;
        RECT  20.736 0 20.76 0.084 ;
    END
  END cfg_data[62]
  PIN cfg_data[63]
    DIRECTION INPUT ;
    USE SIGNAL ;
    PORT
      LAYER M5 ;
        RECT  20.88 0 20.904 0.084 ;
    END
  END cfg_data[63]
  PIN cfg_data[64]
    DIRECTION INPUT ;
    USE SIGNAL ;
    PORT
      LAYER M5 ;
        RECT  21.024 0 21.048 0.084 ;
    END
  END cfg_data[64]
  PIN cfg_data[65]
    DIRECTION INPUT ;
    USE SIGNAL ;
    PORT
      LAYER M5 ;
        RECT  21.168 0 21.192 0.084 ;
    END
  END cfg_data[65]
  PIN cfg_data[66]
    DIRECTION INPUT ;
    USE SIGNAL ;
    PORT
      LAYER M5 ;
        RECT  21.312 0 21.336 0.084 ;
    END
  END cfg_data[66]
  PIN cfg_data[67]
    DIRECTION INPUT ;
    USE SIGNAL ;
    PORT
      LAYER M5 ;
        RECT  21.456 0 21.48 0.084 ;
    END
  END cfg_data[67]
  PIN cfg_data[68]
    DIRECTION INPUT ;
    USE SIGNAL ;
    PORT
      LAYER M5 ;
        RECT  21.6 0 21.624 0.084 ;
    END
  END cfg_data[68]
  PIN cfg_data[69]
    DIRECTION INPUT ;
    USE SIGNAL ;
    PORT
      LAYER M5 ;
        RECT  21.744 0 21.768 0.084 ;
    END
  END cfg_data[69]
  PIN cfg_data[6]
    DIRECTION INPUT ;
    USE SIGNAL ;
    PORT
      LAYER M5 ;
        RECT  46.08 0 46.104 0.084 ;
    END
  END cfg_data[6]
  PIN cfg_data[70]
    DIRECTION INPUT ;
    USE SIGNAL ;
    PORT
      LAYER M5 ;
        RECT  21.888 0 21.912 0.084 ;
    END
  END cfg_data[70]
  PIN cfg_data[71]
    DIRECTION INPUT ;
    USE SIGNAL ;
    PORT
      LAYER M5 ;
        RECT  22.032 0 22.056 0.084 ;
    END
  END cfg_data[71]
  PIN cfg_data[72]
    DIRECTION INPUT ;
    USE SIGNAL ;
    PORT
      LAYER M5 ;
        RECT  22.176 0 22.2 0.084 ;
    END
  END cfg_data[72]
  PIN cfg_data[73]
    DIRECTION INPUT ;
    USE SIGNAL ;
    PORT
      LAYER M5 ;
        RECT  22.32 0 22.344 0.084 ;
    END
  END cfg_data[73]
  PIN cfg_data[74]
    DIRECTION INPUT ;
    USE SIGNAL ;
    PORT
      LAYER M5 ;
        RECT  22.464 0 22.488 0.084 ;
    END
  END cfg_data[74]
  PIN cfg_data[75]
    DIRECTION INPUT ;
    USE SIGNAL ;
    PORT
      LAYER M5 ;
        RECT  22.608 0 22.632 0.084 ;
    END
  END cfg_data[75]
  PIN cfg_data[76]
    DIRECTION INPUT ;
    USE SIGNAL ;
    PORT
      LAYER M5 ;
        RECT  22.752 0 22.776 0.084 ;
    END
  END cfg_data[76]
  PIN cfg_data[77]
    DIRECTION INPUT ;
    USE SIGNAL ;
    PORT
      LAYER M5 ;
        RECT  22.896 0 22.92 0.084 ;
    END
  END cfg_data[77]
  PIN cfg_data[78]
    DIRECTION INPUT ;
    USE SIGNAL ;
    PORT
      LAYER M5 ;
        RECT  23.04 0 23.064 0.084 ;
    END
  END cfg_data[78]
  PIN cfg_data[79]
    DIRECTION INPUT ;
    USE SIGNAL ;
    PORT
      LAYER M5 ;
        RECT  23.184 0 23.208 0.084 ;
    END
  END cfg_data[79]
  PIN cfg_data[7]
    DIRECTION INPUT ;
    USE SIGNAL ;
    PORT
      LAYER M5 ;
        RECT  46.224 0 46.248 0.084 ;
    END
  END cfg_data[7]
  PIN cfg_data[80]
    DIRECTION INPUT ;
    USE SIGNAL ;
    PORT
      LAYER M5 ;
        RECT  23.328 0 23.352 0.084 ;
    END
  END cfg_data[80]
  PIN cfg_data[81]
    DIRECTION INPUT ;
    USE SIGNAL ;
    PORT
      LAYER M5 ;
        RECT  23.472 0 23.496 0.084 ;
    END
  END cfg_data[81]
  PIN cfg_data[82]
    DIRECTION INPUT ;
    USE SIGNAL ;
    PORT
      LAYER M5 ;
        RECT  23.616 0 23.64 0.084 ;
    END
  END cfg_data[82]
  PIN cfg_data[83]
    DIRECTION INPUT ;
    USE SIGNAL ;
    PORT
      LAYER M5 ;
        RECT  23.76 0 23.784 0.084 ;
    END
  END cfg_data[83]
  PIN cfg_data[84]
    DIRECTION INPUT ;
    USE SIGNAL ;
    PORT
      LAYER M5 ;
        RECT  23.904 0 23.928 0.084 ;
    END
  END cfg_data[84]
  PIN cfg_data[85]
    DIRECTION INPUT ;
    USE SIGNAL ;
    PORT
      LAYER M5 ;
        RECT  24.048 0 24.072 0.084 ;
    END
  END cfg_data[85]
  PIN cfg_data[86]
    DIRECTION INPUT ;
    USE SIGNAL ;
    PORT
      LAYER M5 ;
        RECT  24.192 0 24.216 0.084 ;
    END
  END cfg_data[86]
  PIN cfg_data[87]
    DIRECTION INPUT ;
    USE SIGNAL ;
    PORT
      LAYER M5 ;
        RECT  24.336 0 24.36 0.084 ;
    END
  END cfg_data[87]
  PIN cfg_data[88]
    DIRECTION INPUT ;
    USE SIGNAL ;
    PORT
      LAYER M5 ;
        RECT  24.48 0 24.504 0.084 ;
    END
  END cfg_data[88]
  PIN cfg_data[89]
    DIRECTION INPUT ;
    USE SIGNAL ;
    PORT
      LAYER M5 ;
        RECT  24.624 0 24.648 0.084 ;
    END
  END cfg_data[89]
  PIN cfg_data[8]
    DIRECTION INPUT ;
    USE SIGNAL ;
    PORT
      LAYER M5 ;
        RECT  46.368 0 46.392 0.084 ;
    END
  END cfg_data[8]
  PIN cfg_data[90]
    DIRECTION INPUT ;
    USE SIGNAL ;
    PORT
      LAYER M5 ;
        RECT  24.768 0 24.792 0.084 ;
    END
  END cfg_data[90]
  PIN cfg_data[91]
    DIRECTION INPUT ;
    USE SIGNAL ;
    PORT
      LAYER M5 ;
        RECT  24.912 0 24.936 0.084 ;
    END
  END cfg_data[91]
  PIN cfg_data[92]
    DIRECTION INPUT ;
    USE SIGNAL ;
    PORT
      LAYER M5 ;
        RECT  25.056 0 25.08 0.084 ;
    END
  END cfg_data[92]
  PIN cfg_data[93]
    DIRECTION INPUT ;
    USE SIGNAL ;
    PORT
      LAYER M5 ;
        RECT  25.2 0 25.224 0.084 ;
    END
  END cfg_data[93]
  PIN cfg_data[94]
    DIRECTION INPUT ;
    USE SIGNAL ;
    PORT
      LAYER M5 ;
        RECT  25.344 0 25.368 0.084 ;
    END
  END cfg_data[94]
  PIN cfg_data[95]
    DIRECTION INPUT ;
    USE SIGNAL ;
    PORT
      LAYER M5 ;
        RECT  25.488 0 25.512 0.084 ;
    END
  END cfg_data[95]
  PIN cfg_data[96]
    DIRECTION INPUT ;
    USE SIGNAL ;
    PORT
      LAYER M5 ;
        RECT  25.632 0 25.656 0.084 ;
    END
  END cfg_data[96]
  PIN cfg_data[97]
    DIRECTION INPUT ;
    USE SIGNAL ;
    PORT
      LAYER M5 ;
        RECT  25.776 0 25.8 0.084 ;
    END
  END cfg_data[97]
  PIN cfg_data[98]
    DIRECTION INPUT ;
    USE SIGNAL ;
    PORT
      LAYER M5 ;
        RECT  25.92 0 25.944 0.084 ;
    END
  END cfg_data[98]
  PIN cfg_data[99]
    DIRECTION INPUT ;
    USE SIGNAL ;
    PORT
      LAYER M5 ;
        RECT  26.064 0 26.088 0.084 ;
    END
  END cfg_data[99]
  PIN cfg_data[9]
    DIRECTION INPUT ;
    USE SIGNAL ;
    PORT
      LAYER M5 ;
        RECT  46.512 0 46.536 0.084 ;
    END
  END cfg_data[9]
  PIN cfg_target[0]
    DIRECTION INPUT ;
    USE SIGNAL ;
    PORT
      LAYER M5 ;
        RECT  31.392 0 31.416 0.084 ;
    END
  END cfg_target[0]
  PIN cfg_target[1]
    DIRECTION INPUT ;
    USE SIGNAL ;
    PORT
      LAYER M5 ;
        RECT  31.536 0 31.56 0.084 ;
    END
  END cfg_target[1]
  PIN cfg_target[2]
    DIRECTION INPUT ;
    USE SIGNAL ;
    PORT
      LAYER M5 ;
        RECT  31.68 0 31.704 0.084 ;
    END
  END cfg_target[2]
  PIN cfg_target[3]
    DIRECTION INPUT ;
    USE SIGNAL ;
    PORT
      LAYER M5 ;
        RECT  31.824 0 31.848 0.084 ;
    END
  END cfg_target[3]
  PIN cfg_target[4]
    DIRECTION INPUT ;
    USE SIGNAL ;
    PORT
      LAYER M5 ;
        RECT  31.968 0 31.992 0.084 ;
    END
  END cfg_target[4]
  PIN cfg_target[5]
    DIRECTION INPUT ;
    USE SIGNAL ;
    PORT
      LAYER M5 ;
        RECT  32.112 0 32.136 0.084 ;
    END
  END cfg_target[5]
  PIN cfg_target[6]
    DIRECTION INPUT ;
    USE SIGNAL ;
    PORT
      LAYER M5 ;
        RECT  32.256 0 32.28 0.084 ;
    END
  END cfg_target[6]
  PIN cfg_target[7]
    DIRECTION INPUT ;
    USE SIGNAL ;
    PORT
      LAYER M5 ;
        RECT  32.4 0 32.424 0.084 ;
    END
  END cfg_target[7]
  PIN cfg_v
    DIRECTION INPUT ;
    USE SIGNAL ;
    PORT
      LAYER M5 ;
        RECT  32.544 0 32.568 0.084 ;
    END
  END cfg_v
  PIN clk
    DIRECTION INPUT ;
    USE SIGNAL ;
    PORT
      LAYER M5 ;
        RECT  32.688 0 32.712 0.084 ;
    END
  END clk
  PIN clk_in
    DIRECTION INPUT ;
    USE SIGNAL ;
    PORT
      LAYER M5 ;
        RECT  32.832 0 32.856 0.084 ;
    END
  END clk_in
  PIN desc_v
    DIRECTION INPUT ;
    USE SIGNAL ;
    PORT
      LAYER M5 ;
        RECT  32.976 0 33 0.084 ;
    END
  END desc_v
  PIN fault
    DIRECTION OUTPUT ;
    USE SIGNAL ;
    PORT
      LAYER M5 ;
        RECT  33.12 0 33.144 0.084 ;
    END
  END fault
  PIN go[0]
    DIRECTION OUTPUT ;
    USE SIGNAL ;
    PORT
      LAYER M4 ;
        RECT  0 13.104 0.084 13.128 ;
    END
  END go[0]
  PIN launch_v
    DIRECTION INPUT ;
    USE SIGNAL ;
    PORT
      LAYER M5 ;
        RECT  33.264 0 33.288 0.084 ;
    END
  END launch_v
  PIN prm[0]
    DIRECTION OUTPUT ;
    USE SIGNAL ;
    PORT
      LAYER M4 ;
        RECT  51.756 38.736 51.84 38.76 ;
    END
  END prm[0]
  PIN prm[100]
    DIRECTION OUTPUT ;
    USE SIGNAL ;
    PORT
      LAYER M4 ;
        RECT  51.756 15.12 51.84 15.144 ;
    END
  END prm[100]
  PIN prm[101]
    DIRECTION OUTPUT ;
    USE SIGNAL ;
    PORT
      LAYER M4 ;
        RECT  51.756 15.264 51.84 15.288 ;
    END
  END prm[101]
  PIN prm[102]
    DIRECTION OUTPUT ;
    USE SIGNAL ;
    PORT
      LAYER M4 ;
        RECT  51.756 15.408 51.84 15.432 ;
    END
  END prm[102]
  PIN prm[103]
    DIRECTION OUTPUT ;
    USE SIGNAL ;
    PORT
      LAYER M4 ;
        RECT  51.756 15.552 51.84 15.576 ;
    END
  END prm[103]
  PIN prm[104]
    DIRECTION OUTPUT ;
    USE SIGNAL ;
    PORT
      LAYER M4 ;
        RECT  51.756 15.696 51.84 15.72 ;
    END
  END prm[104]
  PIN prm[105]
    DIRECTION OUTPUT ;
    USE SIGNAL ;
    PORT
      LAYER M4 ;
        RECT  51.756 15.84 51.84 15.864 ;
    END
  END prm[105]
  PIN prm[106]
    DIRECTION OUTPUT ;
    USE SIGNAL ;
    PORT
      LAYER M4 ;
        RECT  51.756 15.984 51.84 16.008 ;
    END
  END prm[106]
  PIN prm[107]
    DIRECTION OUTPUT ;
    USE SIGNAL ;
    PORT
      LAYER M4 ;
        RECT  51.756 16.128 51.84 16.152 ;
    END
  END prm[107]
  PIN prm[108]
    DIRECTION OUTPUT ;
    USE SIGNAL ;
    PORT
      LAYER M4 ;
        RECT  51.756 16.272 51.84 16.296 ;
    END
  END prm[108]
  PIN prm[109]
    DIRECTION OUTPUT ;
    USE SIGNAL ;
    PORT
      LAYER M4 ;
        RECT  51.756 16.416 51.84 16.44 ;
    END
  END prm[109]
  PIN prm[10]
    DIRECTION OUTPUT ;
    USE SIGNAL ;
    PORT
      LAYER M4 ;
        RECT  51.756 40.176 51.84 40.2 ;
    END
  END prm[10]
  PIN prm[110]
    DIRECTION OUTPUT ;
    USE SIGNAL ;
    PORT
      LAYER M4 ;
        RECT  51.756 16.56 51.84 16.584 ;
    END
  END prm[110]
  PIN prm[111]
    DIRECTION OUTPUT ;
    USE SIGNAL ;
    PORT
      LAYER M4 ;
        RECT  51.756 16.704 51.84 16.728 ;
    END
  END prm[111]
  PIN prm[112]
    DIRECTION OUTPUT ;
    USE SIGNAL ;
    PORT
      LAYER M4 ;
        RECT  51.756 16.848 51.84 16.872 ;
    END
  END prm[112]
  PIN prm[113]
    DIRECTION OUTPUT ;
    USE SIGNAL ;
    PORT
      LAYER M4 ;
        RECT  51.756 16.992 51.84 17.016 ;
    END
  END prm[113]
  PIN prm[114]
    DIRECTION OUTPUT ;
    USE SIGNAL ;
    PORT
      LAYER M4 ;
        RECT  51.756 17.136 51.84 17.16 ;
    END
  END prm[114]
  PIN prm[115]
    DIRECTION OUTPUT ;
    USE SIGNAL ;
    PORT
      LAYER M4 ;
        RECT  51.756 17.28 51.84 17.304 ;
    END
  END prm[115]
  PIN prm[116]
    DIRECTION OUTPUT ;
    USE SIGNAL ;
    PORT
      LAYER M4 ;
        RECT  51.756 17.424 51.84 17.448 ;
    END
  END prm[116]
  PIN prm[117]
    DIRECTION OUTPUT ;
    USE SIGNAL ;
    PORT
      LAYER M4 ;
        RECT  51.756 17.568 51.84 17.592 ;
    END
  END prm[117]
  PIN prm[118]
    DIRECTION OUTPUT ;
    USE SIGNAL ;
    PORT
      LAYER M4 ;
        RECT  51.756 17.712 51.84 17.736 ;
    END
  END prm[118]
  PIN prm[119]
    DIRECTION OUTPUT ;
    USE SIGNAL ;
    PORT
      LAYER M4 ;
        RECT  51.756 17.856 51.84 17.88 ;
    END
  END prm[119]
  PIN prm[11]
    DIRECTION OUTPUT ;
    USE SIGNAL ;
    PORT
      LAYER M4 ;
        RECT  51.756 40.32 51.84 40.344 ;
    END
  END prm[11]
  PIN prm[120]
    DIRECTION OUTPUT ;
    USE SIGNAL ;
    PORT
      LAYER M4 ;
        RECT  51.756 18 51.84 18.024 ;
    END
  END prm[120]
  PIN prm[121]
    DIRECTION OUTPUT ;
    USE SIGNAL ;
    PORT
      LAYER M4 ;
        RECT  51.756 18.144 51.84 18.168 ;
    END
  END prm[121]
  PIN prm[122]
    DIRECTION OUTPUT ;
    USE SIGNAL ;
    PORT
      LAYER M4 ;
        RECT  51.756 18.288 51.84 18.312 ;
    END
  END prm[122]
  PIN prm[123]
    DIRECTION OUTPUT ;
    USE SIGNAL ;
    PORT
      LAYER M4 ;
        RECT  51.756 18.432 51.84 18.456 ;
    END
  END prm[123]
  PIN prm[124]
    DIRECTION OUTPUT ;
    USE SIGNAL ;
    PORT
      LAYER M4 ;
        RECT  51.756 18.576 51.84 18.6 ;
    END
  END prm[124]
  PIN prm[125]
    DIRECTION OUTPUT ;
    USE SIGNAL ;
    PORT
      LAYER M4 ;
        RECT  51.756 18.72 51.84 18.744 ;
    END
  END prm[125]
  PIN prm[126]
    DIRECTION OUTPUT ;
    USE SIGNAL ;
    PORT
      LAYER M4 ;
        RECT  51.756 18.864 51.84 18.888 ;
    END
  END prm[126]
  PIN prm[127]
    DIRECTION OUTPUT ;
    USE SIGNAL ;
    PORT
      LAYER M4 ;
        RECT  51.756 19.008 51.84 19.032 ;
    END
  END prm[127]
  PIN prm[128]
    DIRECTION OUTPUT ;
    USE SIGNAL ;
    PORT
      LAYER M4 ;
        RECT  51.756 5.328 51.84 5.352 ;
    END
  END prm[128]
  PIN prm[129]
    DIRECTION OUTPUT ;
    USE SIGNAL ;
    PORT
      LAYER M4 ;
        RECT  51.756 5.472 51.84 5.496 ;
    END
  END prm[129]
  PIN prm[12]
    DIRECTION OUTPUT ;
    USE SIGNAL ;
    PORT
      LAYER M4 ;
        RECT  51.756 40.464 51.84 40.488 ;
    END
  END prm[12]
  PIN prm[130]
    DIRECTION OUTPUT ;
    USE SIGNAL ;
    PORT
      LAYER M4 ;
        RECT  51.756 5.616 51.84 5.64 ;
    END
  END prm[130]
  PIN prm[131]
    DIRECTION OUTPUT ;
    USE SIGNAL ;
    PORT
      LAYER M4 ;
        RECT  51.756 5.76 51.84 5.784 ;
    END
  END prm[131]
  PIN prm[132]
    DIRECTION OUTPUT ;
    USE SIGNAL ;
    PORT
      LAYER M4 ;
        RECT  51.756 5.904 51.84 5.928 ;
    END
  END prm[132]
  PIN prm[133]
    DIRECTION OUTPUT ;
    USE SIGNAL ;
    PORT
      LAYER M4 ;
        RECT  51.756 6.048 51.84 6.072 ;
    END
  END prm[133]
  PIN prm[134]
    DIRECTION OUTPUT ;
    USE SIGNAL ;
    PORT
      LAYER M4 ;
        RECT  51.756 6.192 51.84 6.216 ;
    END
  END prm[134]
  PIN prm[135]
    DIRECTION OUTPUT ;
    USE SIGNAL ;
    PORT
      LAYER M4 ;
        RECT  51.756 6.336 51.84 6.36 ;
    END
  END prm[135]
  PIN prm[136]
    DIRECTION OUTPUT ;
    USE SIGNAL ;
    PORT
      LAYER M4 ;
        RECT  51.756 6.48 51.84 6.504 ;
    END
  END prm[136]
  PIN prm[137]
    DIRECTION OUTPUT ;
    USE SIGNAL ;
    PORT
      LAYER M4 ;
        RECT  51.756 6.624 51.84 6.648 ;
    END
  END prm[137]
  PIN prm[138]
    DIRECTION OUTPUT ;
    USE SIGNAL ;
    PORT
      LAYER M4 ;
        RECT  51.756 6.768 51.84 6.792 ;
    END
  END prm[138]
  PIN prm[139]
    DIRECTION OUTPUT ;
    USE SIGNAL ;
    PORT
      LAYER M4 ;
        RECT  51.756 6.912 51.84 6.936 ;
    END
  END prm[139]
  PIN prm[13]
    DIRECTION OUTPUT ;
    USE SIGNAL ;
    PORT
      LAYER M4 ;
        RECT  51.756 40.608 51.84 40.632 ;
    END
  END prm[13]
  PIN prm[140]
    DIRECTION OUTPUT ;
    USE SIGNAL ;
    PORT
      LAYER M4 ;
        RECT  51.756 7.056 51.84 7.08 ;
    END
  END prm[140]
  PIN prm[141]
    DIRECTION OUTPUT ;
    USE SIGNAL ;
    PORT
      LAYER M4 ;
        RECT  51.756 7.2 51.84 7.224 ;
    END
  END prm[141]
  PIN prm[142]
    DIRECTION OUTPUT ;
    USE SIGNAL ;
    PORT
      LAYER M4 ;
        RECT  51.756 7.344 51.84 7.368 ;
    END
  END prm[142]
  PIN prm[143]
    DIRECTION OUTPUT ;
    USE SIGNAL ;
    PORT
      LAYER M4 ;
        RECT  51.756 7.488 51.84 7.512 ;
    END
  END prm[143]
  PIN prm[144]
    DIRECTION OUTPUT ;
    USE SIGNAL ;
    PORT
      LAYER M4 ;
        RECT  51.756 7.632 51.84 7.656 ;
    END
  END prm[144]
  PIN prm[145]
    DIRECTION OUTPUT ;
    USE SIGNAL ;
    PORT
      LAYER M4 ;
        RECT  51.756 7.776 51.84 7.8 ;
    END
  END prm[145]
  PIN prm[146]
    DIRECTION OUTPUT ;
    USE SIGNAL ;
    PORT
      LAYER M4 ;
        RECT  51.756 7.92 51.84 7.944 ;
    END
  END prm[146]
  PIN prm[147]
    DIRECTION OUTPUT ;
    USE SIGNAL ;
    PORT
      LAYER M4 ;
        RECT  51.756 8.064 51.84 8.088 ;
    END
  END prm[147]
  PIN prm[148]
    DIRECTION OUTPUT ;
    USE SIGNAL ;
    PORT
      LAYER M4 ;
        RECT  51.756 8.208 51.84 8.232 ;
    END
  END prm[148]
  PIN prm[149]
    DIRECTION OUTPUT ;
    USE SIGNAL ;
    PORT
      LAYER M4 ;
        RECT  51.756 8.352 51.84 8.376 ;
    END
  END prm[149]
  PIN prm[14]
    DIRECTION OUTPUT ;
    USE SIGNAL ;
    PORT
      LAYER M4 ;
        RECT  51.756 40.752 51.84 40.776 ;
    END
  END prm[14]
  PIN prm[150]
    DIRECTION OUTPUT ;
    USE SIGNAL ;
    PORT
      LAYER M4 ;
        RECT  51.756 8.496 51.84 8.52 ;
    END
  END prm[150]
  PIN prm[151]
    DIRECTION OUTPUT ;
    USE SIGNAL ;
    PORT
      LAYER M4 ;
        RECT  51.756 8.64 51.84 8.664 ;
    END
  END prm[151]
  PIN prm[152]
    DIRECTION OUTPUT ;
    USE SIGNAL ;
    PORT
      LAYER M4 ;
        RECT  51.756 8.784 51.84 8.808 ;
    END
  END prm[152]
  PIN prm[153]
    DIRECTION OUTPUT ;
    USE SIGNAL ;
    PORT
      LAYER M4 ;
        RECT  51.756 8.928 51.84 8.952 ;
    END
  END prm[153]
  PIN prm[154]
    DIRECTION OUTPUT ;
    USE SIGNAL ;
    PORT
      LAYER M4 ;
        RECT  51.756 9.072 51.84 9.096 ;
    END
  END prm[154]
  PIN prm[155]
    DIRECTION OUTPUT ;
    USE SIGNAL ;
    PORT
      LAYER M4 ;
        RECT  51.756 9.216 51.84 9.24 ;
    END
  END prm[155]
  PIN prm[156]
    DIRECTION OUTPUT ;
    USE SIGNAL ;
    PORT
      LAYER M4 ;
        RECT  51.756 9.36 51.84 9.384 ;
    END
  END prm[156]
  PIN prm[157]
    DIRECTION OUTPUT ;
    USE SIGNAL ;
    PORT
      LAYER M4 ;
        RECT  51.756 9.504 51.84 9.528 ;
    END
  END prm[157]
  PIN prm[158]
    DIRECTION OUTPUT ;
    USE SIGNAL ;
    PORT
      LAYER M4 ;
        RECT  51.756 9.648 51.84 9.672 ;
    END
  END prm[158]
  PIN prm[159]
    DIRECTION OUTPUT ;
    USE SIGNAL ;
    PORT
      LAYER M4 ;
        RECT  51.756 9.792 51.84 9.816 ;
    END
  END prm[159]
  PIN prm[15]
    DIRECTION OUTPUT ;
    USE SIGNAL ;
    PORT
      LAYER M4 ;
        RECT  51.756 40.896 51.84 40.92 ;
    END
  END prm[15]
  PIN prm[160]
    DIRECTION OUTPUT ;
    USE SIGNAL ;
    PORT
      LAYER M4 ;
        RECT  51.756 9.936 51.84 9.96 ;
    END
  END prm[160]
  PIN prm[161]
    DIRECTION OUTPUT ;
    USE SIGNAL ;
    PORT
      LAYER M4 ;
        RECT  51.756 10.08 51.84 10.104 ;
    END
  END prm[161]
  PIN prm[162]
    DIRECTION OUTPUT ;
    USE SIGNAL ;
    PORT
      LAYER M4 ;
        RECT  51.756 10.224 51.84 10.248 ;
    END
  END prm[162]
  PIN prm[163]
    DIRECTION OUTPUT ;
    USE SIGNAL ;
    PORT
      LAYER M4 ;
        RECT  51.756 10.368 51.84 10.392 ;
    END
  END prm[163]
  PIN prm[164]
    DIRECTION OUTPUT ;
    USE SIGNAL ;
    PORT
      LAYER M4 ;
        RECT  51.756 10.512 51.84 10.536 ;
    END
  END prm[164]
  PIN prm[165]
    DIRECTION OUTPUT ;
    USE SIGNAL ;
    PORT
      LAYER M4 ;
        RECT  51.756 10.656 51.84 10.68 ;
    END
  END prm[165]
  PIN prm[166]
    DIRECTION OUTPUT ;
    USE SIGNAL ;
    PORT
      LAYER M4 ;
        RECT  51.756 10.8 51.84 10.824 ;
    END
  END prm[166]
  PIN prm[167]
    DIRECTION OUTPUT ;
    USE SIGNAL ;
    PORT
      LAYER M4 ;
        RECT  51.756 10.944 51.84 10.968 ;
    END
  END prm[167]
  PIN prm[168]
    DIRECTION OUTPUT ;
    USE SIGNAL ;
    PORT
      LAYER M4 ;
        RECT  51.756 11.088 51.84 11.112 ;
    END
  END prm[168]
  PIN prm[169]
    DIRECTION OUTPUT ;
    USE SIGNAL ;
    PORT
      LAYER M4 ;
        RECT  51.756 11.232 51.84 11.256 ;
    END
  END prm[169]
  PIN prm[16]
    DIRECTION OUTPUT ;
    USE SIGNAL ;
    PORT
      LAYER M4 ;
        RECT  51.756 41.04 51.84 41.064 ;
    END
  END prm[16]
  PIN prm[170]
    DIRECTION OUTPUT ;
    USE SIGNAL ;
    PORT
      LAYER M4 ;
        RECT  51.756 11.376 51.84 11.4 ;
    END
  END prm[170]
  PIN prm[171]
    DIRECTION OUTPUT ;
    USE SIGNAL ;
    PORT
      LAYER M4 ;
        RECT  51.756 11.52 51.84 11.544 ;
    END
  END prm[171]
  PIN prm[172]
    DIRECTION OUTPUT ;
    USE SIGNAL ;
    PORT
      LAYER M4 ;
        RECT  51.756 11.664 51.84 11.688 ;
    END
  END prm[172]
  PIN prm[173]
    DIRECTION OUTPUT ;
    USE SIGNAL ;
    PORT
      LAYER M4 ;
        RECT  51.756 11.808 51.84 11.832 ;
    END
  END prm[173]
  PIN prm[174]
    DIRECTION OUTPUT ;
    USE SIGNAL ;
    PORT
      LAYER M4 ;
        RECT  51.756 11.952 51.84 11.976 ;
    END
  END prm[174]
  PIN prm[175]
    DIRECTION OUTPUT ;
    USE SIGNAL ;
    PORT
      LAYER M4 ;
        RECT  51.756 12.096 51.84 12.12 ;
    END
  END prm[175]
  PIN prm[176]
    DIRECTION OUTPUT ;
    USE SIGNAL ;
    PORT
      LAYER M4 ;
        RECT  51.756 12.24 51.84 12.264 ;
    END
  END prm[176]
  PIN prm[177]
    DIRECTION OUTPUT ;
    USE SIGNAL ;
    PORT
      LAYER M4 ;
        RECT  51.756 12.384 51.84 12.408 ;
    END
  END prm[177]
  PIN prm[178]
    DIRECTION OUTPUT ;
    USE SIGNAL ;
    PORT
      LAYER M4 ;
        RECT  51.756 12.528 51.84 12.552 ;
    END
  END prm[178]
  PIN prm[179]
    DIRECTION OUTPUT ;
    USE SIGNAL ;
    PORT
      LAYER M4 ;
        RECT  51.756 12.672 51.84 12.696 ;
    END
  END prm[179]
  PIN prm[17]
    DIRECTION OUTPUT ;
    USE SIGNAL ;
    PORT
      LAYER M4 ;
        RECT  51.756 41.184 51.84 41.208 ;
    END
  END prm[17]
  PIN prm[180]
    DIRECTION OUTPUT ;
    USE SIGNAL ;
    PORT
      LAYER M4 ;
        RECT  51.756 12.816 51.84 12.84 ;
    END
  END prm[180]
  PIN prm[181]
    DIRECTION OUTPUT ;
    USE SIGNAL ;
    PORT
      LAYER M4 ;
        RECT  51.756 12.96 51.84 12.984 ;
    END
  END prm[181]
  PIN prm[182]
    DIRECTION OUTPUT ;
    USE SIGNAL ;
    PORT
      LAYER M4 ;
        RECT  51.756 13.104 51.84 13.128 ;
    END
  END prm[182]
  PIN prm[183]
    DIRECTION OUTPUT ;
    USE SIGNAL ;
    PORT
      LAYER M4 ;
        RECT  51.756 13.248 51.84 13.272 ;
    END
  END prm[183]
  PIN prm[184]
    DIRECTION OUTPUT ;
    USE SIGNAL ;
    PORT
      LAYER M4 ;
        RECT  51.756 13.392 51.84 13.416 ;
    END
  END prm[184]
  PIN prm[185]
    DIRECTION OUTPUT ;
    USE SIGNAL ;
    PORT
      LAYER M4 ;
        RECT  51.756 13.536 51.84 13.56 ;
    END
  END prm[185]
  PIN prm[186]
    DIRECTION OUTPUT ;
    USE SIGNAL ;
    PORT
      LAYER M4 ;
        RECT  51.756 13.68 51.84 13.704 ;
    END
  END prm[186]
  PIN prm[187]
    DIRECTION OUTPUT ;
    USE SIGNAL ;
    PORT
      LAYER M4 ;
        RECT  51.756 13.824 51.84 13.848 ;
    END
  END prm[187]
  PIN prm[188]
    DIRECTION OUTPUT ;
    USE SIGNAL ;
    PORT
      LAYER M4 ;
        RECT  51.756 13.968 51.84 13.992 ;
    END
  END prm[188]
  PIN prm[189]
    DIRECTION OUTPUT ;
    USE SIGNAL ;
    PORT
      LAYER M4 ;
        RECT  51.756 14.112 51.84 14.136 ;
    END
  END prm[189]
  PIN prm[18]
    DIRECTION OUTPUT ;
    USE SIGNAL ;
    PORT
      LAYER M4 ;
        RECT  51.756 41.328 51.84 41.352 ;
    END
  END prm[18]
  PIN prm[190]
    DIRECTION OUTPUT ;
    USE SIGNAL ;
    PORT
      LAYER M4 ;
        RECT  51.756 14.256 51.84 14.28 ;
    END
  END prm[190]
  PIN prm[191]
    DIRECTION OUTPUT ;
    USE SIGNAL ;
    PORT
      LAYER M4 ;
        RECT  51.756 14.4 51.84 14.424 ;
    END
  END prm[191]
  PIN prm[192]
    DIRECTION OUTPUT ;
    USE SIGNAL ;
    PORT
      LAYER M4 ;
        RECT  51.756 23.76 51.84 23.784 ;
    END
  END prm[192]
  PIN prm[193]
    DIRECTION OUTPUT ;
    USE SIGNAL ;
    PORT
      LAYER M4 ;
        RECT  51.756 23.904 51.84 23.928 ;
    END
  END prm[193]
  PIN prm[194]
    DIRECTION OUTPUT ;
    USE SIGNAL ;
    PORT
      LAYER M4 ;
        RECT  51.756 24.048 51.84 24.072 ;
    END
  END prm[194]
  PIN prm[195]
    DIRECTION OUTPUT ;
    USE SIGNAL ;
    PORT
      LAYER M4 ;
        RECT  51.756 24.192 51.84 24.216 ;
    END
  END prm[195]
  PIN prm[196]
    DIRECTION OUTPUT ;
    USE SIGNAL ;
    PORT
      LAYER M4 ;
        RECT  51.756 24.336 51.84 24.36 ;
    END
  END prm[196]
  PIN prm[197]
    DIRECTION OUTPUT ;
    USE SIGNAL ;
    PORT
      LAYER M4 ;
        RECT  51.756 24.48 51.84 24.504 ;
    END
  END prm[197]
  PIN prm[198]
    DIRECTION OUTPUT ;
    USE SIGNAL ;
    PORT
      LAYER M4 ;
        RECT  51.756 24.624 51.84 24.648 ;
    END
  END prm[198]
  PIN prm[199]
    DIRECTION OUTPUT ;
    USE SIGNAL ;
    PORT
      LAYER M4 ;
        RECT  51.756 24.768 51.84 24.792 ;
    END
  END prm[199]
  PIN prm[19]
    DIRECTION OUTPUT ;
    USE SIGNAL ;
    PORT
      LAYER M4 ;
        RECT  51.756 41.472 51.84 41.496 ;
    END
  END prm[19]
  PIN prm[1]
    DIRECTION OUTPUT ;
    USE SIGNAL ;
    PORT
      LAYER M4 ;
        RECT  51.756 38.88 51.84 38.904 ;
    END
  END prm[1]
  PIN prm[200]
    DIRECTION OUTPUT ;
    USE SIGNAL ;
    PORT
      LAYER M4 ;
        RECT  51.756 24.912 51.84 24.936 ;
    END
  END prm[200]
  PIN prm[201]
    DIRECTION OUTPUT ;
    USE SIGNAL ;
    PORT
      LAYER M4 ;
        RECT  51.756 25.056 51.84 25.08 ;
    END
  END prm[201]
  PIN prm[202]
    DIRECTION OUTPUT ;
    USE SIGNAL ;
    PORT
      LAYER M4 ;
        RECT  51.756 25.2 51.84 25.224 ;
    END
  END prm[202]
  PIN prm[203]
    DIRECTION OUTPUT ;
    USE SIGNAL ;
    PORT
      LAYER M4 ;
        RECT  51.756 25.344 51.84 25.368 ;
    END
  END prm[203]
  PIN prm[204]
    DIRECTION OUTPUT ;
    USE SIGNAL ;
    PORT
      LAYER M4 ;
        RECT  51.756 25.488 51.84 25.512 ;
    END
  END prm[204]
  PIN prm[205]
    DIRECTION OUTPUT ;
    USE SIGNAL ;
    PORT
      LAYER M4 ;
        RECT  51.756 25.632 51.84 25.656 ;
    END
  END prm[205]
  PIN prm[206]
    DIRECTION OUTPUT ;
    USE SIGNAL ;
    PORT
      LAYER M4 ;
        RECT  51.756 25.776 51.84 25.8 ;
    END
  END prm[206]
  PIN prm[207]
    DIRECTION OUTPUT ;
    USE SIGNAL ;
    PORT
      LAYER M4 ;
        RECT  51.756 25.92 51.84 25.944 ;
    END
  END prm[207]
  PIN prm[208]
    DIRECTION OUTPUT ;
    USE SIGNAL ;
    PORT
      LAYER M4 ;
        RECT  51.756 26.064 51.84 26.088 ;
    END
  END prm[208]
  PIN prm[209]
    DIRECTION OUTPUT ;
    USE SIGNAL ;
    PORT
      LAYER M4 ;
        RECT  51.756 26.208 51.84 26.232 ;
    END
  END prm[209]
  PIN prm[20]
    DIRECTION OUTPUT ;
    USE SIGNAL ;
    PORT
      LAYER M4 ;
        RECT  51.756 41.616 51.84 41.64 ;
    END
  END prm[20]
  PIN prm[210]
    DIRECTION OUTPUT ;
    USE SIGNAL ;
    PORT
      LAYER M4 ;
        RECT  51.756 26.352 51.84 26.376 ;
    END
  END prm[210]
  PIN prm[211]
    DIRECTION OUTPUT ;
    USE SIGNAL ;
    PORT
      LAYER M4 ;
        RECT  51.756 26.496 51.84 26.52 ;
    END
  END prm[211]
  PIN prm[212]
    DIRECTION OUTPUT ;
    USE SIGNAL ;
    PORT
      LAYER M4 ;
        RECT  51.756 26.64 51.84 26.664 ;
    END
  END prm[212]
  PIN prm[213]
    DIRECTION OUTPUT ;
    USE SIGNAL ;
    PORT
      LAYER M4 ;
        RECT  51.756 26.784 51.84 26.808 ;
    END
  END prm[213]
  PIN prm[214]
    DIRECTION OUTPUT ;
    USE SIGNAL ;
    PORT
      LAYER M4 ;
        RECT  51.756 26.928 51.84 26.952 ;
    END
  END prm[214]
  PIN prm[215]
    DIRECTION OUTPUT ;
    USE SIGNAL ;
    PORT
      LAYER M4 ;
        RECT  51.756 27.072 51.84 27.096 ;
    END
  END prm[215]
  PIN prm[216]
    DIRECTION OUTPUT ;
    USE SIGNAL ;
    PORT
      LAYER M4 ;
        RECT  51.756 27.216 51.84 27.24 ;
    END
  END prm[216]
  PIN prm[217]
    DIRECTION OUTPUT ;
    USE SIGNAL ;
    PORT
      LAYER M4 ;
        RECT  51.756 27.36 51.84 27.384 ;
    END
  END prm[217]
  PIN prm[218]
    DIRECTION OUTPUT ;
    USE SIGNAL ;
    PORT
      LAYER M4 ;
        RECT  51.756 27.504 51.84 27.528 ;
    END
  END prm[218]
  PIN prm[219]
    DIRECTION OUTPUT ;
    USE SIGNAL ;
    PORT
      LAYER M4 ;
        RECT  51.756 27.648 51.84 27.672 ;
    END
  END prm[219]
  PIN prm[21]
    DIRECTION OUTPUT ;
    USE SIGNAL ;
    PORT
      LAYER M4 ;
        RECT  51.756 41.76 51.84 41.784 ;
    END
  END prm[21]
  PIN prm[220]
    DIRECTION OUTPUT ;
    USE SIGNAL ;
    PORT
      LAYER M4 ;
        RECT  51.756 27.792 51.84 27.816 ;
    END
  END prm[220]
  PIN prm[221]
    DIRECTION OUTPUT ;
    USE SIGNAL ;
    PORT
      LAYER M4 ;
        RECT  51.756 27.936 51.84 27.96 ;
    END
  END prm[221]
  PIN prm[222]
    DIRECTION OUTPUT ;
    USE SIGNAL ;
    PORT
      LAYER M4 ;
        RECT  51.756 28.08 51.84 28.104 ;
    END
  END prm[222]
  PIN prm[223]
    DIRECTION OUTPUT ;
    USE SIGNAL ;
    PORT
      LAYER M4 ;
        RECT  51.756 28.224 51.84 28.248 ;
    END
  END prm[223]
  PIN prm[224]
    DIRECTION OUTPUT ;
    USE SIGNAL ;
    PORT
      LAYER M4 ;
        RECT  51.756 29.52 51.84 29.544 ;
    END
  END prm[224]
  PIN prm[225]
    DIRECTION OUTPUT ;
    USE SIGNAL ;
    PORT
      LAYER M4 ;
        RECT  51.756 29.664 51.84 29.688 ;
    END
  END prm[225]
  PIN prm[226]
    DIRECTION OUTPUT ;
    USE SIGNAL ;
    PORT
      LAYER M4 ;
        RECT  51.756 29.808 51.84 29.832 ;
    END
  END prm[226]
  PIN prm[227]
    DIRECTION OUTPUT ;
    USE SIGNAL ;
    PORT
      LAYER M4 ;
        RECT  51.756 29.952 51.84 29.976 ;
    END
  END prm[227]
  PIN prm[228]
    DIRECTION OUTPUT ;
    USE SIGNAL ;
    PORT
      LAYER M4 ;
        RECT  51.756 30.096 51.84 30.12 ;
    END
  END prm[228]
  PIN prm[229]
    DIRECTION OUTPUT ;
    USE SIGNAL ;
    PORT
      LAYER M4 ;
        RECT  51.756 30.24 51.84 30.264 ;
    END
  END prm[229]
  PIN prm[22]
    DIRECTION OUTPUT ;
    USE SIGNAL ;
    PORT
      LAYER M4 ;
        RECT  51.756 41.904 51.84 41.928 ;
    END
  END prm[22]
  PIN prm[230]
    DIRECTION OUTPUT ;
    USE SIGNAL ;
    PORT
      LAYER M4 ;
        RECT  51.756 30.384 51.84 30.408 ;
    END
  END prm[230]
  PIN prm[231]
    DIRECTION OUTPUT ;
    USE SIGNAL ;
    PORT
      LAYER M4 ;
        RECT  51.756 30.528 51.84 30.552 ;
    END
  END prm[231]
  PIN prm[232]
    DIRECTION OUTPUT ;
    USE SIGNAL ;
    PORT
      LAYER M4 ;
        RECT  51.756 30.672 51.84 30.696 ;
    END
  END prm[232]
  PIN prm[233]
    DIRECTION OUTPUT ;
    USE SIGNAL ;
    PORT
      LAYER M4 ;
        RECT  51.756 30.816 51.84 30.84 ;
    END
  END prm[233]
  PIN prm[234]
    DIRECTION OUTPUT ;
    USE SIGNAL ;
    PORT
      LAYER M4 ;
        RECT  51.756 30.96 51.84 30.984 ;
    END
  END prm[234]
  PIN prm[235]
    DIRECTION OUTPUT ;
    USE SIGNAL ;
    PORT
      LAYER M4 ;
        RECT  51.756 31.104 51.84 31.128 ;
    END
  END prm[235]
  PIN prm[236]
    DIRECTION OUTPUT ;
    USE SIGNAL ;
    PORT
      LAYER M4 ;
        RECT  51.756 31.248 51.84 31.272 ;
    END
  END prm[236]
  PIN prm[237]
    DIRECTION OUTPUT ;
    USE SIGNAL ;
    PORT
      LAYER M4 ;
        RECT  51.756 31.392 51.84 31.416 ;
    END
  END prm[237]
  PIN prm[238]
    DIRECTION OUTPUT ;
    USE SIGNAL ;
    PORT
      LAYER M4 ;
        RECT  51.756 31.536 51.84 31.56 ;
    END
  END prm[238]
  PIN prm[239]
    DIRECTION OUTPUT ;
    USE SIGNAL ;
    PORT
      LAYER M4 ;
        RECT  51.756 31.68 51.84 31.704 ;
    END
  END prm[239]
  PIN prm[23]
    DIRECTION OUTPUT ;
    USE SIGNAL ;
    PORT
      LAYER M4 ;
        RECT  51.756 42.048 51.84 42.072 ;
    END
  END prm[23]
  PIN prm[240]
    DIRECTION OUTPUT ;
    USE SIGNAL ;
    PORT
      LAYER M4 ;
        RECT  51.756 31.824 51.84 31.848 ;
    END
  END prm[240]
  PIN prm[241]
    DIRECTION OUTPUT ;
    USE SIGNAL ;
    PORT
      LAYER M4 ;
        RECT  51.756 31.968 51.84 31.992 ;
    END
  END prm[241]
  PIN prm[242]
    DIRECTION OUTPUT ;
    USE SIGNAL ;
    PORT
      LAYER M4 ;
        RECT  51.756 32.112 51.84 32.136 ;
    END
  END prm[242]
  PIN prm[243]
    DIRECTION OUTPUT ;
    USE SIGNAL ;
    PORT
      LAYER M4 ;
        RECT  51.756 32.256 51.84 32.28 ;
    END
  END prm[243]
  PIN prm[244]
    DIRECTION OUTPUT ;
    USE SIGNAL ;
    PORT
      LAYER M4 ;
        RECT  51.756 32.4 51.84 32.424 ;
    END
  END prm[244]
  PIN prm[245]
    DIRECTION OUTPUT ;
    USE SIGNAL ;
    PORT
      LAYER M4 ;
        RECT  51.756 32.544 51.84 32.568 ;
    END
  END prm[245]
  PIN prm[246]
    DIRECTION OUTPUT ;
    USE SIGNAL ;
    PORT
      LAYER M4 ;
        RECT  51.756 32.688 51.84 32.712 ;
    END
  END prm[246]
  PIN prm[247]
    DIRECTION OUTPUT ;
    USE SIGNAL ;
    PORT
      LAYER M4 ;
        RECT  51.756 32.832 51.84 32.856 ;
    END
  END prm[247]
  PIN prm[248]
    DIRECTION OUTPUT ;
    USE SIGNAL ;
    PORT
      LAYER M4 ;
        RECT  51.756 32.976 51.84 33 ;
    END
  END prm[248]
  PIN prm[249]
    DIRECTION OUTPUT ;
    USE SIGNAL ;
    PORT
      LAYER M4 ;
        RECT  51.756 33.12 51.84 33.144 ;
    END
  END prm[249]
  PIN prm[24]
    DIRECTION OUTPUT ;
    USE SIGNAL ;
    PORT
      LAYER M4 ;
        RECT  51.756 42.192 51.84 42.216 ;
    END
  END prm[24]
  PIN prm[250]
    DIRECTION OUTPUT ;
    USE SIGNAL ;
    PORT
      LAYER M4 ;
        RECT  51.756 33.264 51.84 33.288 ;
    END
  END prm[250]
  PIN prm[251]
    DIRECTION OUTPUT ;
    USE SIGNAL ;
    PORT
      LAYER M4 ;
        RECT  51.756 33.408 51.84 33.432 ;
    END
  END prm[251]
  PIN prm[252]
    DIRECTION OUTPUT ;
    USE SIGNAL ;
    PORT
      LAYER M4 ;
        RECT  51.756 33.552 51.84 33.576 ;
    END
  END prm[252]
  PIN prm[253]
    DIRECTION OUTPUT ;
    USE SIGNAL ;
    PORT
      LAYER M4 ;
        RECT  51.756 33.696 51.84 33.72 ;
    END
  END prm[253]
  PIN prm[254]
    DIRECTION OUTPUT ;
    USE SIGNAL ;
    PORT
      LAYER M4 ;
        RECT  51.756 33.84 51.84 33.864 ;
    END
  END prm[254]
  PIN prm[255]
    DIRECTION OUTPUT ;
    USE SIGNAL ;
    PORT
      LAYER M4 ;
        RECT  51.756 33.984 51.84 34.008 ;
    END
  END prm[255]
  PIN prm[25]
    DIRECTION OUTPUT ;
    USE SIGNAL ;
    PORT
      LAYER M4 ;
        RECT  51.756 42.336 51.84 42.36 ;
    END
  END prm[25]
  PIN prm[26]
    DIRECTION OUTPUT ;
    USE SIGNAL ;
    PORT
      LAYER M4 ;
        RECT  51.756 42.48 51.84 42.504 ;
    END
  END prm[26]
  PIN prm[27]
    DIRECTION OUTPUT ;
    USE SIGNAL ;
    PORT
      LAYER M4 ;
        RECT  51.756 42.624 51.84 42.648 ;
    END
  END prm[27]
  PIN prm[28]
    DIRECTION OUTPUT ;
    USE SIGNAL ;
    PORT
      LAYER M4 ;
        RECT  51.756 42.768 51.84 42.792 ;
    END
  END prm[28]
  PIN prm[29]
    DIRECTION OUTPUT ;
    USE SIGNAL ;
    PORT
      LAYER M4 ;
        RECT  51.756 42.912 51.84 42.936 ;
    END
  END prm[29]
  PIN prm[2]
    DIRECTION OUTPUT ;
    USE SIGNAL ;
    PORT
      LAYER M4 ;
        RECT  51.756 39.024 51.84 39.048 ;
    END
  END prm[2]
  PIN prm[30]
    DIRECTION OUTPUT ;
    USE SIGNAL ;
    PORT
      LAYER M4 ;
        RECT  51.756 43.056 51.84 43.08 ;
    END
  END prm[30]
  PIN prm[31]
    DIRECTION OUTPUT ;
    USE SIGNAL ;
    PORT
      LAYER M4 ;
        RECT  51.756 43.2 51.84 43.224 ;
    END
  END prm[31]
  PIN prm[32]
    DIRECTION OUTPUT ;
    USE SIGNAL ;
    PORT
      LAYER M4 ;
        RECT  51.756 43.344 51.84 43.368 ;
    END
  END prm[32]
  PIN prm[33]
    DIRECTION OUTPUT ;
    USE SIGNAL ;
    PORT
      LAYER M4 ;
        RECT  51.756 43.488 51.84 43.512 ;
    END
  END prm[33]
  PIN prm[34]
    DIRECTION OUTPUT ;
    USE SIGNAL ;
    PORT
      LAYER M4 ;
        RECT  51.756 43.632 51.84 43.656 ;
    END
  END prm[34]
  PIN prm[35]
    DIRECTION OUTPUT ;
    USE SIGNAL ;
    PORT
      LAYER M4 ;
        RECT  51.756 43.776 51.84 43.8 ;
    END
  END prm[35]
  PIN prm[36]
    DIRECTION OUTPUT ;
    USE SIGNAL ;
    PORT
      LAYER M4 ;
        RECT  51.756 43.92 51.84 43.944 ;
    END
  END prm[36]
  PIN prm[37]
    DIRECTION OUTPUT ;
    USE SIGNAL ;
    PORT
      LAYER M4 ;
        RECT  51.756 44.064 51.84 44.088 ;
    END
  END prm[37]
  PIN prm[38]
    DIRECTION OUTPUT ;
    USE SIGNAL ;
    PORT
      LAYER M4 ;
        RECT  51.756 44.208 51.84 44.232 ;
    END
  END prm[38]
  PIN prm[39]
    DIRECTION OUTPUT ;
    USE SIGNAL ;
    PORT
      LAYER M4 ;
        RECT  51.756 44.352 51.84 44.376 ;
    END
  END prm[39]
  PIN prm[3]
    DIRECTION OUTPUT ;
    USE SIGNAL ;
    PORT
      LAYER M4 ;
        RECT  51.756 39.168 51.84 39.192 ;
    END
  END prm[3]
  PIN prm[40]
    DIRECTION OUTPUT ;
    USE SIGNAL ;
    PORT
      LAYER M4 ;
        RECT  51.756 44.496 51.84 44.52 ;
    END
  END prm[40]
  PIN prm[41]
    DIRECTION OUTPUT ;
    USE SIGNAL ;
    PORT
      LAYER M4 ;
        RECT  51.756 44.64 51.84 44.664 ;
    END
  END prm[41]
  PIN prm[42]
    DIRECTION OUTPUT ;
    USE SIGNAL ;
    PORT
      LAYER M4 ;
        RECT  51.756 44.784 51.84 44.808 ;
    END
  END prm[42]
  PIN prm[43]
    DIRECTION OUTPUT ;
    USE SIGNAL ;
    PORT
      LAYER M4 ;
        RECT  51.756 44.928 51.84 44.952 ;
    END
  END prm[43]
  PIN prm[44]
    DIRECTION OUTPUT ;
    USE SIGNAL ;
    PORT
      LAYER M4 ;
        RECT  51.756 45.072 51.84 45.096 ;
    END
  END prm[44]
  PIN prm[45]
    DIRECTION OUTPUT ;
    USE SIGNAL ;
    PORT
      LAYER M4 ;
        RECT  51.756 45.216 51.84 45.24 ;
    END
  END prm[45]
  PIN prm[46]
    DIRECTION OUTPUT ;
    USE SIGNAL ;
    PORT
      LAYER M4 ;
        RECT  51.756 45.36 51.84 45.384 ;
    END
  END prm[46]
  PIN prm[47]
    DIRECTION OUTPUT ;
    USE SIGNAL ;
    PORT
      LAYER M4 ;
        RECT  51.756 45.504 51.84 45.528 ;
    END
  END prm[47]
  PIN prm[48]
    DIRECTION OUTPUT ;
    USE SIGNAL ;
    PORT
      LAYER M4 ;
        RECT  51.756 45.648 51.84 45.672 ;
    END
  END prm[48]
  PIN prm[49]
    DIRECTION OUTPUT ;
    USE SIGNAL ;
    PORT
      LAYER M4 ;
        RECT  51.756 45.792 51.84 45.816 ;
    END
  END prm[49]
  PIN prm[4]
    DIRECTION OUTPUT ;
    USE SIGNAL ;
    PORT
      LAYER M4 ;
        RECT  51.756 39.312 51.84 39.336 ;
    END
  END prm[4]
  PIN prm[50]
    DIRECTION OUTPUT ;
    USE SIGNAL ;
    PORT
      LAYER M4 ;
        RECT  51.756 45.936 51.84 45.96 ;
    END
  END prm[50]
  PIN prm[51]
    DIRECTION OUTPUT ;
    USE SIGNAL ;
    PORT
      LAYER M4 ;
        RECT  51.756 46.08 51.84 46.104 ;
    END
  END prm[51]
  PIN prm[52]
    DIRECTION OUTPUT ;
    USE SIGNAL ;
    PORT
      LAYER M4 ;
        RECT  51.756 46.224 51.84 46.248 ;
    END
  END prm[52]
  PIN prm[53]
    DIRECTION OUTPUT ;
    USE SIGNAL ;
    PORT
      LAYER M4 ;
        RECT  51.756 46.368 51.84 46.392 ;
    END
  END prm[53]
  PIN prm[54]
    DIRECTION OUTPUT ;
    USE SIGNAL ;
    PORT
      LAYER M4 ;
        RECT  51.756 46.512 51.84 46.536 ;
    END
  END prm[54]
  PIN prm[55]
    DIRECTION OUTPUT ;
    USE SIGNAL ;
    PORT
      LAYER M4 ;
        RECT  51.756 46.656 51.84 46.68 ;
    END
  END prm[55]
  PIN prm[56]
    DIRECTION OUTPUT ;
    USE SIGNAL ;
    PORT
      LAYER M4 ;
        RECT  51.756 46.8 51.84 46.824 ;
    END
  END prm[56]
  PIN prm[57]
    DIRECTION OUTPUT ;
    USE SIGNAL ;
    PORT
      LAYER M4 ;
        RECT  51.756 46.944 51.84 46.968 ;
    END
  END prm[57]
  PIN prm[58]
    DIRECTION OUTPUT ;
    USE SIGNAL ;
    PORT
      LAYER M4 ;
        RECT  51.756 47.088 51.84 47.112 ;
    END
  END prm[58]
  PIN prm[59]
    DIRECTION OUTPUT ;
    USE SIGNAL ;
    PORT
      LAYER M4 ;
        RECT  51.756 47.232 51.84 47.256 ;
    END
  END prm[59]
  PIN prm[5]
    DIRECTION OUTPUT ;
    USE SIGNAL ;
    PORT
      LAYER M4 ;
        RECT  51.756 39.456 51.84 39.48 ;
    END
  END prm[5]
  PIN prm[60]
    DIRECTION OUTPUT ;
    USE SIGNAL ;
    PORT
      LAYER M4 ;
        RECT  51.756 47.376 51.84 47.4 ;
    END
  END prm[60]
  PIN prm[61]
    DIRECTION OUTPUT ;
    USE SIGNAL ;
    PORT
      LAYER M4 ;
        RECT  51.756 47.52 51.84 47.544 ;
    END
  END prm[61]
  PIN prm[62]
    DIRECTION OUTPUT ;
    USE SIGNAL ;
    PORT
      LAYER M4 ;
        RECT  51.756 47.664 51.84 47.688 ;
    END
  END prm[62]
  PIN prm[63]
    DIRECTION OUTPUT ;
    USE SIGNAL ;
    PORT
      LAYER M4 ;
        RECT  51.756 47.808 51.84 47.832 ;
    END
  END prm[63]
  PIN prm[64]
    DIRECTION OUTPUT ;
    USE SIGNAL ;
    PORT
      LAYER M4 ;
        RECT  51.756 19.152 51.84 19.176 ;
    END
  END prm[64]
  PIN prm[65]
    DIRECTION OUTPUT ;
    USE SIGNAL ;
    PORT
      LAYER M4 ;
        RECT  51.756 19.296 51.84 19.32 ;
    END
  END prm[65]
  PIN prm[66]
    DIRECTION OUTPUT ;
    USE SIGNAL ;
    PORT
      LAYER M4 ;
        RECT  51.756 19.44 51.84 19.464 ;
    END
  END prm[66]
  PIN prm[67]
    DIRECTION OUTPUT ;
    USE SIGNAL ;
    PORT
      LAYER M4 ;
        RECT  51.756 19.584 51.84 19.608 ;
    END
  END prm[67]
  PIN prm[68]
    DIRECTION OUTPUT ;
    USE SIGNAL ;
    PORT
      LAYER M4 ;
        RECT  51.756 19.728 51.84 19.752 ;
    END
  END prm[68]
  PIN prm[69]
    DIRECTION OUTPUT ;
    USE SIGNAL ;
    PORT
      LAYER M4 ;
        RECT  51.756 19.872 51.84 19.896 ;
    END
  END prm[69]
  PIN prm[6]
    DIRECTION OUTPUT ;
    USE SIGNAL ;
    PORT
      LAYER M4 ;
        RECT  51.756 39.6 51.84 39.624 ;
    END
  END prm[6]
  PIN prm[70]
    DIRECTION OUTPUT ;
    USE SIGNAL ;
    PORT
      LAYER M4 ;
        RECT  51.756 20.016 51.84 20.04 ;
    END
  END prm[70]
  PIN prm[71]
    DIRECTION OUTPUT ;
    USE SIGNAL ;
    PORT
      LAYER M4 ;
        RECT  51.756 20.16 51.84 20.184 ;
    END
  END prm[71]
  PIN prm[72]
    DIRECTION OUTPUT ;
    USE SIGNAL ;
    PORT
      LAYER M4 ;
        RECT  51.756 20.304 51.84 20.328 ;
    END
  END prm[72]
  PIN prm[73]
    DIRECTION OUTPUT ;
    USE SIGNAL ;
    PORT
      LAYER M4 ;
        RECT  51.756 20.448 51.84 20.472 ;
    END
  END prm[73]
  PIN prm[74]
    DIRECTION OUTPUT ;
    USE SIGNAL ;
    PORT
      LAYER M4 ;
        RECT  51.756 20.592 51.84 20.616 ;
    END
  END prm[74]
  PIN prm[75]
    DIRECTION OUTPUT ;
    USE SIGNAL ;
    PORT
      LAYER M4 ;
        RECT  51.756 20.736 51.84 20.76 ;
    END
  END prm[75]
  PIN prm[76]
    DIRECTION OUTPUT ;
    USE SIGNAL ;
    PORT
      LAYER M4 ;
        RECT  51.756 20.88 51.84 20.904 ;
    END
  END prm[76]
  PIN prm[77]
    DIRECTION OUTPUT ;
    USE SIGNAL ;
    PORT
      LAYER M4 ;
        RECT  51.756 21.024 51.84 21.048 ;
    END
  END prm[77]
  PIN prm[78]
    DIRECTION OUTPUT ;
    USE SIGNAL ;
    PORT
      LAYER M4 ;
        RECT  51.756 21.168 51.84 21.192 ;
    END
  END prm[78]
  PIN prm[79]
    DIRECTION OUTPUT ;
    USE SIGNAL ;
    PORT
      LAYER M4 ;
        RECT  51.756 21.312 51.84 21.336 ;
    END
  END prm[79]
  PIN prm[7]
    DIRECTION OUTPUT ;
    USE SIGNAL ;
    PORT
      LAYER M4 ;
        RECT  51.756 39.744 51.84 39.768 ;
    END
  END prm[7]
  PIN prm[80]
    DIRECTION OUTPUT ;
    USE SIGNAL ;
    PORT
      LAYER M4 ;
        RECT  51.756 21.456 51.84 21.48 ;
    END
  END prm[80]
  PIN prm[81]
    DIRECTION OUTPUT ;
    USE SIGNAL ;
    PORT
      LAYER M4 ;
        RECT  51.756 21.6 51.84 21.624 ;
    END
  END prm[81]
  PIN prm[82]
    DIRECTION OUTPUT ;
    USE SIGNAL ;
    PORT
      LAYER M4 ;
        RECT  51.756 21.744 51.84 21.768 ;
    END
  END prm[82]
  PIN prm[83]
    DIRECTION OUTPUT ;
    USE SIGNAL ;
    PORT
      LAYER M4 ;
        RECT  51.756 21.888 51.84 21.912 ;
    END
  END prm[83]
  PIN prm[84]
    DIRECTION OUTPUT ;
    USE SIGNAL ;
    PORT
      LAYER M4 ;
        RECT  51.756 22.032 51.84 22.056 ;
    END
  END prm[84]
  PIN prm[85]
    DIRECTION OUTPUT ;
    USE SIGNAL ;
    PORT
      LAYER M4 ;
        RECT  51.756 22.176 51.84 22.2 ;
    END
  END prm[85]
  PIN prm[86]
    DIRECTION OUTPUT ;
    USE SIGNAL ;
    PORT
      LAYER M4 ;
        RECT  51.756 22.32 51.84 22.344 ;
    END
  END prm[86]
  PIN prm[87]
    DIRECTION OUTPUT ;
    USE SIGNAL ;
    PORT
      LAYER M4 ;
        RECT  51.756 22.464 51.84 22.488 ;
    END
  END prm[87]
  PIN prm[88]
    DIRECTION OUTPUT ;
    USE SIGNAL ;
    PORT
      LAYER M4 ;
        RECT  51.756 22.608 51.84 22.632 ;
    END
  END prm[88]
  PIN prm[89]
    DIRECTION OUTPUT ;
    USE SIGNAL ;
    PORT
      LAYER M4 ;
        RECT  51.756 22.752 51.84 22.776 ;
    END
  END prm[89]
  PIN prm[8]
    DIRECTION OUTPUT ;
    USE SIGNAL ;
    PORT
      LAYER M4 ;
        RECT  51.756 39.888 51.84 39.912 ;
    END
  END prm[8]
  PIN prm[90]
    DIRECTION OUTPUT ;
    USE SIGNAL ;
    PORT
      LAYER M4 ;
        RECT  51.756 22.896 51.84 22.92 ;
    END
  END prm[90]
  PIN prm[91]
    DIRECTION OUTPUT ;
    USE SIGNAL ;
    PORT
      LAYER M4 ;
        RECT  51.756 23.04 51.84 23.064 ;
    END
  END prm[91]
  PIN prm[92]
    DIRECTION OUTPUT ;
    USE SIGNAL ;
    PORT
      LAYER M4 ;
        RECT  51.756 23.184 51.84 23.208 ;
    END
  END prm[92]
  PIN prm[93]
    DIRECTION OUTPUT ;
    USE SIGNAL ;
    PORT
      LAYER M4 ;
        RECT  51.756 23.328 51.84 23.352 ;
    END
  END prm[93]
  PIN prm[94]
    DIRECTION OUTPUT ;
    USE SIGNAL ;
    PORT
      LAYER M4 ;
        RECT  51.756 23.472 51.84 23.496 ;
    END
  END prm[94]
  PIN prm[95]
    DIRECTION OUTPUT ;
    USE SIGNAL ;
    PORT
      LAYER M4 ;
        RECT  51.756 23.616 51.84 23.64 ;
    END
  END prm[95]
  PIN prm[96]
    DIRECTION OUTPUT ;
    USE SIGNAL ;
    PORT
      LAYER M4 ;
        RECT  51.756 14.544 51.84 14.568 ;
    END
  END prm[96]
  PIN prm[97]
    DIRECTION OUTPUT ;
    USE SIGNAL ;
    PORT
      LAYER M4 ;
        RECT  51.756 14.688 51.84 14.712 ;
    END
  END prm[97]
  PIN prm[98]
    DIRECTION OUTPUT ;
    USE SIGNAL ;
    PORT
      LAYER M4 ;
        RECT  51.756 14.832 51.84 14.856 ;
    END
  END prm[98]
  PIN prm[99]
    DIRECTION OUTPUT ;
    USE SIGNAL ;
    PORT
      LAYER M4 ;
        RECT  51.756 14.976 51.84 15 ;
    END
  END prm[99]
  PIN prm[9]
    DIRECTION OUTPUT ;
    USE SIGNAL ;
    PORT
      LAYER M4 ;
        RECT  51.756 40.032 51.84 40.056 ;
    END
  END prm[9]
  PIN pw_addr[0]
    DIRECTION OUTPUT ;
    USE SIGNAL ;
    PORT
      LAYER M5 ;
        RECT  42.48 51.756 42.504 51.84 ;
    END
  END pw_addr[0]
  PIN pw_addr[10]
    DIRECTION OUTPUT ;
    USE SIGNAL ;
    PORT
      LAYER M5 ;
        RECT  43.92 51.756 43.944 51.84 ;
    END
  END pw_addr[10]
  PIN pw_addr[11]
    DIRECTION OUTPUT ;
    USE SIGNAL ;
    PORT
      LAYER M5 ;
        RECT  44.064 51.756 44.088 51.84 ;
    END
  END pw_addr[11]
  PIN pw_addr[12]
    DIRECTION OUTPUT ;
    USE SIGNAL ;
    PORT
      LAYER M5 ;
        RECT  44.208 51.756 44.232 51.84 ;
    END
  END pw_addr[12]
  PIN pw_addr[13]
    DIRECTION OUTPUT ;
    USE SIGNAL ;
    PORT
      LAYER M5 ;
        RECT  44.352 51.756 44.376 51.84 ;
    END
  END pw_addr[13]
  PIN pw_addr[14]
    DIRECTION OUTPUT ;
    USE SIGNAL ;
    PORT
      LAYER M5 ;
        RECT  44.496 51.756 44.52 51.84 ;
    END
  END pw_addr[14]
  PIN pw_addr[15]
    DIRECTION OUTPUT ;
    USE SIGNAL ;
    PORT
      LAYER M5 ;
        RECT  44.64 51.756 44.664 51.84 ;
    END
  END pw_addr[15]
  PIN pw_addr[16]
    DIRECTION OUTPUT ;
    USE SIGNAL ;
    PORT
      LAYER M5 ;
        RECT  44.784 51.756 44.808 51.84 ;
    END
  END pw_addr[16]
  PIN pw_addr[17]
    DIRECTION OUTPUT ;
    USE SIGNAL ;
    PORT
      LAYER M5 ;
        RECT  44.928 51.756 44.952 51.84 ;
    END
  END pw_addr[17]
  PIN pw_addr[18]
    DIRECTION OUTPUT ;
    USE SIGNAL ;
    PORT
      LAYER M5 ;
        RECT  45.072 51.756 45.096 51.84 ;
    END
  END pw_addr[18]
  PIN pw_addr[19]
    DIRECTION OUTPUT ;
    USE SIGNAL ;
    PORT
      LAYER M5 ;
        RECT  45.216 51.756 45.24 51.84 ;
    END
  END pw_addr[19]
  PIN pw_addr[1]
    DIRECTION OUTPUT ;
    USE SIGNAL ;
    PORT
      LAYER M5 ;
        RECT  42.624 51.756 42.648 51.84 ;
    END
  END pw_addr[1]
  PIN pw_addr[20]
    DIRECTION OUTPUT ;
    USE SIGNAL ;
    PORT
      LAYER M5 ;
        RECT  45.36 51.756 45.384 51.84 ;
    END
  END pw_addr[20]
  PIN pw_addr[21]
    DIRECTION OUTPUT ;
    USE SIGNAL ;
    PORT
      LAYER M5 ;
        RECT  45.504 51.756 45.528 51.84 ;
    END
  END pw_addr[21]
  PIN pw_addr[22]
    DIRECTION OUTPUT ;
    USE SIGNAL ;
    PORT
      LAYER M5 ;
        RECT  45.648 51.756 45.672 51.84 ;
    END
  END pw_addr[22]
  PIN pw_addr[2]
    DIRECTION OUTPUT ;
    USE SIGNAL ;
    PORT
      LAYER M5 ;
        RECT  42.768 51.756 42.792 51.84 ;
    END
  END pw_addr[2]
  PIN pw_addr[3]
    DIRECTION OUTPUT ;
    USE SIGNAL ;
    PORT
      LAYER M5 ;
        RECT  42.912 51.756 42.936 51.84 ;
    END
  END pw_addr[3]
  PIN pw_addr[4]
    DIRECTION OUTPUT ;
    USE SIGNAL ;
    PORT
      LAYER M5 ;
        RECT  43.056 51.756 43.08 51.84 ;
    END
  END pw_addr[4]
  PIN pw_addr[5]
    DIRECTION OUTPUT ;
    USE SIGNAL ;
    PORT
      LAYER M5 ;
        RECT  43.2 51.756 43.224 51.84 ;
    END
  END pw_addr[5]
  PIN pw_addr[6]
    DIRECTION OUTPUT ;
    USE SIGNAL ;
    PORT
      LAYER M5 ;
        RECT  43.344 51.756 43.368 51.84 ;
    END
  END pw_addr[6]
  PIN pw_addr[7]
    DIRECTION OUTPUT ;
    USE SIGNAL ;
    PORT
      LAYER M5 ;
        RECT  43.488 51.756 43.512 51.84 ;
    END
  END pw_addr[7]
  PIN pw_addr[8]
    DIRECTION OUTPUT ;
    USE SIGNAL ;
    PORT
      LAYER M5 ;
        RECT  43.632 51.756 43.656 51.84 ;
    END
  END pw_addr[8]
  PIN pw_addr[9]
    DIRECTION OUTPUT ;
    USE SIGNAL ;
    PORT
      LAYER M5 ;
        RECT  43.776 51.756 43.8 51.84 ;
    END
  END pw_addr[9]
  PIN pw_data[0]
    DIRECTION OUTPUT ;
    USE SIGNAL ;
    PORT
      LAYER M5 ;
        RECT  45.792 51.756 45.816 51.84 ;
    END
  END pw_data[0]
  PIN pw_data[100]
    DIRECTION OUTPUT ;
    USE SIGNAL ;
    PORT
      LAYER M5 ;
        RECT  22.176 51.756 22.2 51.84 ;
    END
  END pw_data[100]
  PIN pw_data[101]
    DIRECTION OUTPUT ;
    USE SIGNAL ;
    PORT
      LAYER M5 ;
        RECT  37.296 51.756 37.32 51.84 ;
    END
  END pw_data[101]
  PIN pw_data[102]
    DIRECTION OUTPUT ;
    USE SIGNAL ;
    PORT
      LAYER M5 ;
        RECT  37.44 51.756 37.464 51.84 ;
    END
  END pw_data[102]
  PIN pw_data[103]
    DIRECTION OUTPUT ;
    USE SIGNAL ;
    PORT
      LAYER M5 ;
        RECT  37.584 51.756 37.608 51.84 ;
    END
  END pw_data[103]
  PIN pw_data[104]
    DIRECTION OUTPUT ;
    USE SIGNAL ;
    PORT
      LAYER M5 ;
        RECT  37.728 51.756 37.752 51.84 ;
    END
  END pw_data[104]
  PIN pw_data[105]
    DIRECTION OUTPUT ;
    USE SIGNAL ;
    PORT
      LAYER M5 ;
        RECT  37.872 51.756 37.896 51.84 ;
    END
  END pw_data[105]
  PIN pw_data[106]
    DIRECTION OUTPUT ;
    USE SIGNAL ;
    PORT
      LAYER M5 ;
        RECT  38.016 51.756 38.04 51.84 ;
    END
  END pw_data[106]
  PIN pw_data[107]
    DIRECTION OUTPUT ;
    USE SIGNAL ;
    PORT
      LAYER M5 ;
        RECT  38.16 51.756 38.184 51.84 ;
    END
  END pw_data[107]
  PIN pw_data[108]
    DIRECTION OUTPUT ;
    USE SIGNAL ;
    PORT
      LAYER M5 ;
        RECT  38.304 51.756 38.328 51.84 ;
    END
  END pw_data[108]
  PIN pw_data[109]
    DIRECTION OUTPUT ;
    USE SIGNAL ;
    PORT
      LAYER M5 ;
        RECT  38.448 51.756 38.472 51.84 ;
    END
  END pw_data[109]
  PIN pw_data[10]
    DIRECTION OUTPUT ;
    USE SIGNAL ;
    PORT
      LAYER M5 ;
        RECT  33.408 51.756 33.432 51.84 ;
    END
  END pw_data[10]
  PIN pw_data[110]
    DIRECTION OUTPUT ;
    USE SIGNAL ;
    PORT
      LAYER M5 ;
        RECT  38.592 51.756 38.616 51.84 ;
    END
  END pw_data[110]
  PIN pw_data[111]
    DIRECTION OUTPUT ;
    USE SIGNAL ;
    PORT
      LAYER M5 ;
        RECT  38.736 51.756 38.76 51.84 ;
    END
  END pw_data[111]
  PIN pw_data[112]
    DIRECTION OUTPUT ;
    USE SIGNAL ;
    PORT
      LAYER M5 ;
        RECT  38.88 51.756 38.904 51.84 ;
    END
  END pw_data[112]
  PIN pw_data[113]
    DIRECTION OUTPUT ;
    USE SIGNAL ;
    PORT
      LAYER M5 ;
        RECT  39.024 51.756 39.048 51.84 ;
    END
  END pw_data[113]
  PIN pw_data[114]
    DIRECTION OUTPUT ;
    USE SIGNAL ;
    PORT
      LAYER M5 ;
        RECT  39.168 51.756 39.192 51.84 ;
    END
  END pw_data[114]
  PIN pw_data[115]
    DIRECTION OUTPUT ;
    USE SIGNAL ;
    PORT
      LAYER M5 ;
        RECT  39.312 51.756 39.336 51.84 ;
    END
  END pw_data[115]
  PIN pw_data[116]
    DIRECTION OUTPUT ;
    USE SIGNAL ;
    PORT
      LAYER M5 ;
        RECT  39.456 51.756 39.48 51.84 ;
    END
  END pw_data[116]
  PIN pw_data[117]
    DIRECTION OUTPUT ;
    USE SIGNAL ;
    PORT
      LAYER M5 ;
        RECT  39.6 51.756 39.624 51.84 ;
    END
  END pw_data[117]
  PIN pw_data[118]
    DIRECTION OUTPUT ;
    USE SIGNAL ;
    PORT
      LAYER M5 ;
        RECT  39.744 51.756 39.768 51.84 ;
    END
  END pw_data[118]
  PIN pw_data[119]
    DIRECTION OUTPUT ;
    USE SIGNAL ;
    PORT
      LAYER M5 ;
        RECT  39.888 51.756 39.912 51.84 ;
    END
  END pw_data[119]
  PIN pw_data[11]
    DIRECTION OUTPUT ;
    USE SIGNAL ;
    PORT
      LAYER M5 ;
        RECT  33.552 51.756 33.576 51.84 ;
    END
  END pw_data[11]
  PIN pw_data[120]
    DIRECTION OUTPUT ;
    USE SIGNAL ;
    PORT
      LAYER M5 ;
        RECT  40.032 51.756 40.056 51.84 ;
    END
  END pw_data[120]
  PIN pw_data[121]
    DIRECTION OUTPUT ;
    USE SIGNAL ;
    PORT
      LAYER M5 ;
        RECT  40.176 51.756 40.2 51.84 ;
    END
  END pw_data[121]
  PIN pw_data[122]
    DIRECTION OUTPUT ;
    USE SIGNAL ;
    PORT
      LAYER M5 ;
        RECT  40.32 51.756 40.344 51.84 ;
    END
  END pw_data[122]
  PIN pw_data[123]
    DIRECTION OUTPUT ;
    USE SIGNAL ;
    PORT
      LAYER M5 ;
        RECT  40.464 51.756 40.488 51.84 ;
    END
  END pw_data[123]
  PIN pw_data[124]
    DIRECTION OUTPUT ;
    USE SIGNAL ;
    PORT
      LAYER M5 ;
        RECT  40.608 51.756 40.632 51.84 ;
    END
  END pw_data[124]
  PIN pw_data[125]
    DIRECTION OUTPUT ;
    USE SIGNAL ;
    PORT
      LAYER M5 ;
        RECT  40.752 51.756 40.776 51.84 ;
    END
  END pw_data[125]
  PIN pw_data[126]
    DIRECTION OUTPUT ;
    USE SIGNAL ;
    PORT
      LAYER M5 ;
        RECT  40.896 51.756 40.92 51.84 ;
    END
  END pw_data[126]
  PIN pw_data[127]
    DIRECTION OUTPUT ;
    USE SIGNAL ;
    PORT
      LAYER M5 ;
        RECT  41.04 51.756 41.064 51.84 ;
    END
  END pw_data[127]
  PIN pw_data[128]
    DIRECTION OUTPUT ;
    USE SIGNAL ;
    PORT
      LAYER M5 ;
        RECT  41.184 51.756 41.208 51.84 ;
    END
  END pw_data[128]
  PIN pw_data[129]
    DIRECTION OUTPUT ;
    USE SIGNAL ;
    PORT
      LAYER M5 ;
        RECT  41.328 51.756 41.352 51.84 ;
    END
  END pw_data[129]
  PIN pw_data[12]
    DIRECTION OUTPUT ;
    USE SIGNAL ;
    PORT
      LAYER M5 ;
        RECT  33.696 51.756 33.72 51.84 ;
    END
  END pw_data[12]
  PIN pw_data[130]
    DIRECTION OUTPUT ;
    USE SIGNAL ;
    PORT
      LAYER M5 ;
        RECT  41.472 51.756 41.496 51.84 ;
    END
  END pw_data[130]
  PIN pw_data[131]
    DIRECTION OUTPUT ;
    USE SIGNAL ;
    PORT
      LAYER M5 ;
        RECT  41.616 51.756 41.64 51.84 ;
    END
  END pw_data[131]
  PIN pw_data[132]
    DIRECTION OUTPUT ;
    USE SIGNAL ;
    PORT
      LAYER M5 ;
        RECT  41.76 51.756 41.784 51.84 ;
    END
  END pw_data[132]
  PIN pw_data[133]
    DIRECTION OUTPUT ;
    USE SIGNAL ;
    PORT
      LAYER M5 ;
        RECT  13.104 51.756 13.128 51.84 ;
    END
  END pw_data[133]
  PIN pw_data[134]
    DIRECTION OUTPUT ;
    USE SIGNAL ;
    PORT
      LAYER M5 ;
        RECT  13.248 51.756 13.272 51.84 ;
    END
  END pw_data[134]
  PIN pw_data[135]
    DIRECTION OUTPUT ;
    USE SIGNAL ;
    PORT
      LAYER M5 ;
        RECT  13.392 51.756 13.416 51.84 ;
    END
  END pw_data[135]
  PIN pw_data[136]
    DIRECTION OUTPUT ;
    USE SIGNAL ;
    PORT
      LAYER M5 ;
        RECT  13.536 51.756 13.56 51.84 ;
    END
  END pw_data[136]
  PIN pw_data[137]
    DIRECTION OUTPUT ;
    USE SIGNAL ;
    PORT
      LAYER M5 ;
        RECT  13.68 51.756 13.704 51.84 ;
    END
  END pw_data[137]
  PIN pw_data[138]
    DIRECTION OUTPUT ;
    USE SIGNAL ;
    PORT
      LAYER M5 ;
        RECT  13.824 51.756 13.848 51.84 ;
    END
  END pw_data[138]
  PIN pw_data[139]
    DIRECTION OUTPUT ;
    USE SIGNAL ;
    PORT
      LAYER M5 ;
        RECT  13.968 51.756 13.992 51.84 ;
    END
  END pw_data[139]
  PIN pw_data[13]
    DIRECTION OUTPUT ;
    USE SIGNAL ;
    PORT
      LAYER M5 ;
        RECT  33.84 51.756 33.864 51.84 ;
    END
  END pw_data[13]
  PIN pw_data[140]
    DIRECTION OUTPUT ;
    USE SIGNAL ;
    PORT
      LAYER M5 ;
        RECT  14.112 51.756 14.136 51.84 ;
    END
  END pw_data[140]
  PIN pw_data[141]
    DIRECTION OUTPUT ;
    USE SIGNAL ;
    PORT
      LAYER M5 ;
        RECT  14.256 51.756 14.28 51.84 ;
    END
  END pw_data[141]
  PIN pw_data[142]
    DIRECTION OUTPUT ;
    USE SIGNAL ;
    PORT
      LAYER M5 ;
        RECT  14.4 51.756 14.424 51.84 ;
    END
  END pw_data[142]
  PIN pw_data[143]
    DIRECTION OUTPUT ;
    USE SIGNAL ;
    PORT
      LAYER M5 ;
        RECT  14.544 51.756 14.568 51.84 ;
    END
  END pw_data[143]
  PIN pw_data[144]
    DIRECTION OUTPUT ;
    USE SIGNAL ;
    PORT
      LAYER M5 ;
        RECT  14.688 51.756 14.712 51.84 ;
    END
  END pw_data[144]
  PIN pw_data[145]
    DIRECTION OUTPUT ;
    USE SIGNAL ;
    PORT
      LAYER M5 ;
        RECT  14.832 51.756 14.856 51.84 ;
    END
  END pw_data[145]
  PIN pw_data[146]
    DIRECTION OUTPUT ;
    USE SIGNAL ;
    PORT
      LAYER M5 ;
        RECT  14.976 51.756 15 51.84 ;
    END
  END pw_data[146]
  PIN pw_data[147]
    DIRECTION OUTPUT ;
    USE SIGNAL ;
    PORT
      LAYER M5 ;
        RECT  15.12 51.756 15.144 51.84 ;
    END
  END pw_data[147]
  PIN pw_data[148]
    DIRECTION OUTPUT ;
    USE SIGNAL ;
    PORT
      LAYER M5 ;
        RECT  15.264 51.756 15.288 51.84 ;
    END
  END pw_data[148]
  PIN pw_data[149]
    DIRECTION OUTPUT ;
    USE SIGNAL ;
    PORT
      LAYER M5 ;
        RECT  15.408 51.756 15.432 51.84 ;
    END
  END pw_data[149]
  PIN pw_data[14]
    DIRECTION OUTPUT ;
    USE SIGNAL ;
    PORT
      LAYER M5 ;
        RECT  33.984 51.756 34.008 51.84 ;
    END
  END pw_data[14]
  PIN pw_data[150]
    DIRECTION OUTPUT ;
    USE SIGNAL ;
    PORT
      LAYER M5 ;
        RECT  15.552 51.756 15.576 51.84 ;
    END
  END pw_data[150]
  PIN pw_data[151]
    DIRECTION OUTPUT ;
    USE SIGNAL ;
    PORT
      LAYER M5 ;
        RECT  15.696 51.756 15.72 51.84 ;
    END
  END pw_data[151]
  PIN pw_data[152]
    DIRECTION OUTPUT ;
    USE SIGNAL ;
    PORT
      LAYER M5 ;
        RECT  15.84 51.756 15.864 51.84 ;
    END
  END pw_data[152]
  PIN pw_data[153]
    DIRECTION OUTPUT ;
    USE SIGNAL ;
    PORT
      LAYER M5 ;
        RECT  15.984 51.756 16.008 51.84 ;
    END
  END pw_data[153]
  PIN pw_data[154]
    DIRECTION OUTPUT ;
    USE SIGNAL ;
    PORT
      LAYER M5 ;
        RECT  16.128 51.756 16.152 51.84 ;
    END
  END pw_data[154]
  PIN pw_data[155]
    DIRECTION OUTPUT ;
    USE SIGNAL ;
    PORT
      LAYER M5 ;
        RECT  16.272 51.756 16.296 51.84 ;
    END
  END pw_data[155]
  PIN pw_data[156]
    DIRECTION OUTPUT ;
    USE SIGNAL ;
    PORT
      LAYER M5 ;
        RECT  16.416 51.756 16.44 51.84 ;
    END
  END pw_data[156]
  PIN pw_data[157]
    DIRECTION OUTPUT ;
    USE SIGNAL ;
    PORT
      LAYER M5 ;
        RECT  16.56 51.756 16.584 51.84 ;
    END
  END pw_data[157]
  PIN pw_data[158]
    DIRECTION OUTPUT ;
    USE SIGNAL ;
    PORT
      LAYER M5 ;
        RECT  16.704 51.756 16.728 51.84 ;
    END
  END pw_data[158]
  PIN pw_data[159]
    DIRECTION OUTPUT ;
    USE SIGNAL ;
    PORT
      LAYER M5 ;
        RECT  16.848 51.756 16.872 51.84 ;
    END
  END pw_data[159]
  PIN pw_data[15]
    DIRECTION OUTPUT ;
    USE SIGNAL ;
    PORT
      LAYER M5 ;
        RECT  34.128 51.756 34.152 51.84 ;
    END
  END pw_data[15]
  PIN pw_data[160]
    DIRECTION OUTPUT ;
    USE SIGNAL ;
    PORT
      LAYER M5 ;
        RECT  16.992 51.756 17.016 51.84 ;
    END
  END pw_data[160]
  PIN pw_data[161]
    DIRECTION OUTPUT ;
    USE SIGNAL ;
    PORT
      LAYER M5 ;
        RECT  17.136 51.756 17.16 51.84 ;
    END
  END pw_data[161]
  PIN pw_data[162]
    DIRECTION OUTPUT ;
    USE SIGNAL ;
    PORT
      LAYER M5 ;
        RECT  17.28 51.756 17.304 51.84 ;
    END
  END pw_data[162]
  PIN pw_data[163]
    DIRECTION OUTPUT ;
    USE SIGNAL ;
    PORT
      LAYER M5 ;
        RECT  17.424 51.756 17.448 51.84 ;
    END
  END pw_data[163]
  PIN pw_data[164]
    DIRECTION OUTPUT ;
    USE SIGNAL ;
    PORT
      LAYER M5 ;
        RECT  17.568 51.756 17.592 51.84 ;
    END
  END pw_data[164]
  PIN pw_data[165]
    DIRECTION OUTPUT ;
    USE SIGNAL ;
    PORT
      LAYER M5 ;
        RECT  8.496 51.756 8.52 51.84 ;
    END
  END pw_data[165]
  PIN pw_data[166]
    DIRECTION OUTPUT ;
    USE SIGNAL ;
    PORT
      LAYER M5 ;
        RECT  8.64 51.756 8.664 51.84 ;
    END
  END pw_data[166]
  PIN pw_data[167]
    DIRECTION OUTPUT ;
    USE SIGNAL ;
    PORT
      LAYER M5 ;
        RECT  8.784 51.756 8.808 51.84 ;
    END
  END pw_data[167]
  PIN pw_data[168]
    DIRECTION OUTPUT ;
    USE SIGNAL ;
    PORT
      LAYER M5 ;
        RECT  8.928 51.756 8.952 51.84 ;
    END
  END pw_data[168]
  PIN pw_data[169]
    DIRECTION OUTPUT ;
    USE SIGNAL ;
    PORT
      LAYER M5 ;
        RECT  9.072 51.756 9.096 51.84 ;
    END
  END pw_data[169]
  PIN pw_data[16]
    DIRECTION OUTPUT ;
    USE SIGNAL ;
    PORT
      LAYER M5 ;
        RECT  34.272 51.756 34.296 51.84 ;
    END
  END pw_data[16]
  PIN pw_data[170]
    DIRECTION OUTPUT ;
    USE SIGNAL ;
    PORT
      LAYER M5 ;
        RECT  9.216 51.756 9.24 51.84 ;
    END
  END pw_data[170]
  PIN pw_data[171]
    DIRECTION OUTPUT ;
    USE SIGNAL ;
    PORT
      LAYER M5 ;
        RECT  9.36 51.756 9.384 51.84 ;
    END
  END pw_data[171]
  PIN pw_data[172]
    DIRECTION OUTPUT ;
    USE SIGNAL ;
    PORT
      LAYER M5 ;
        RECT  9.504 51.756 9.528 51.84 ;
    END
  END pw_data[172]
  PIN pw_data[173]
    DIRECTION OUTPUT ;
    USE SIGNAL ;
    PORT
      LAYER M5 ;
        RECT  9.648 51.756 9.672 51.84 ;
    END
  END pw_data[173]
  PIN pw_data[174]
    DIRECTION OUTPUT ;
    USE SIGNAL ;
    PORT
      LAYER M5 ;
        RECT  9.792 51.756 9.816 51.84 ;
    END
  END pw_data[174]
  PIN pw_data[175]
    DIRECTION OUTPUT ;
    USE SIGNAL ;
    PORT
      LAYER M5 ;
        RECT  9.936 51.756 9.96 51.84 ;
    END
  END pw_data[175]
  PIN pw_data[176]
    DIRECTION OUTPUT ;
    USE SIGNAL ;
    PORT
      LAYER M5 ;
        RECT  10.08 51.756 10.104 51.84 ;
    END
  END pw_data[176]
  PIN pw_data[177]
    DIRECTION OUTPUT ;
    USE SIGNAL ;
    PORT
      LAYER M5 ;
        RECT  10.224 51.756 10.248 51.84 ;
    END
  END pw_data[177]
  PIN pw_data[178]
    DIRECTION OUTPUT ;
    USE SIGNAL ;
    PORT
      LAYER M5 ;
        RECT  10.368 51.756 10.392 51.84 ;
    END
  END pw_data[178]
  PIN pw_data[179]
    DIRECTION OUTPUT ;
    USE SIGNAL ;
    PORT
      LAYER M5 ;
        RECT  10.512 51.756 10.536 51.84 ;
    END
  END pw_data[179]
  PIN pw_data[17]
    DIRECTION OUTPUT ;
    USE SIGNAL ;
    PORT
      LAYER M5 ;
        RECT  34.416 51.756 34.44 51.84 ;
    END
  END pw_data[17]
  PIN pw_data[180]
    DIRECTION OUTPUT ;
    USE SIGNAL ;
    PORT
      LAYER M5 ;
        RECT  10.656 51.756 10.68 51.84 ;
    END
  END pw_data[180]
  PIN pw_data[181]
    DIRECTION OUTPUT ;
    USE SIGNAL ;
    PORT
      LAYER M5 ;
        RECT  10.8 51.756 10.824 51.84 ;
    END
  END pw_data[181]
  PIN pw_data[182]
    DIRECTION OUTPUT ;
    USE SIGNAL ;
    PORT
      LAYER M5 ;
        RECT  10.944 51.756 10.968 51.84 ;
    END
  END pw_data[182]
  PIN pw_data[183]
    DIRECTION OUTPUT ;
    USE SIGNAL ;
    PORT
      LAYER M5 ;
        RECT  11.088 51.756 11.112 51.84 ;
    END
  END pw_data[183]
  PIN pw_data[184]
    DIRECTION OUTPUT ;
    USE SIGNAL ;
    PORT
      LAYER M5 ;
        RECT  11.232 51.756 11.256 51.84 ;
    END
  END pw_data[184]
  PIN pw_data[185]
    DIRECTION OUTPUT ;
    USE SIGNAL ;
    PORT
      LAYER M5 ;
        RECT  11.376 51.756 11.4 51.84 ;
    END
  END pw_data[185]
  PIN pw_data[186]
    DIRECTION OUTPUT ;
    USE SIGNAL ;
    PORT
      LAYER M5 ;
        RECT  11.52 51.756 11.544 51.84 ;
    END
  END pw_data[186]
  PIN pw_data[187]
    DIRECTION OUTPUT ;
    USE SIGNAL ;
    PORT
      LAYER M5 ;
        RECT  11.664 51.756 11.688 51.84 ;
    END
  END pw_data[187]
  PIN pw_data[188]
    DIRECTION OUTPUT ;
    USE SIGNAL ;
    PORT
      LAYER M5 ;
        RECT  11.808 51.756 11.832 51.84 ;
    END
  END pw_data[188]
  PIN pw_data[189]
    DIRECTION OUTPUT ;
    USE SIGNAL ;
    PORT
      LAYER M5 ;
        RECT  11.952 51.756 11.976 51.84 ;
    END
  END pw_data[189]
  PIN pw_data[18]
    DIRECTION OUTPUT ;
    USE SIGNAL ;
    PORT
      LAYER M5 ;
        RECT  34.56 51.756 34.584 51.84 ;
    END
  END pw_data[18]
  PIN pw_data[190]
    DIRECTION OUTPUT ;
    USE SIGNAL ;
    PORT
      LAYER M5 ;
        RECT  12.096 51.756 12.12 51.84 ;
    END
  END pw_data[190]
  PIN pw_data[191]
    DIRECTION OUTPUT ;
    USE SIGNAL ;
    PORT
      LAYER M5 ;
        RECT  12.24 51.756 12.264 51.84 ;
    END
  END pw_data[191]
  PIN pw_data[192]
    DIRECTION OUTPUT ;
    USE SIGNAL ;
    PORT
      LAYER M5 ;
        RECT  12.384 51.756 12.408 51.84 ;
    END
  END pw_data[192]
  PIN pw_data[193]
    DIRECTION OUTPUT ;
    USE SIGNAL ;
    PORT
      LAYER M5 ;
        RECT  12.528 51.756 12.552 51.84 ;
    END
  END pw_data[193]
  PIN pw_data[194]
    DIRECTION OUTPUT ;
    USE SIGNAL ;
    PORT
      LAYER M5 ;
        RECT  12.672 51.756 12.696 51.84 ;
    END
  END pw_data[194]
  PIN pw_data[195]
    DIRECTION OUTPUT ;
    USE SIGNAL ;
    PORT
      LAYER M5 ;
        RECT  12.816 51.756 12.84 51.84 ;
    END
  END pw_data[195]
  PIN pw_data[196]
    DIRECTION OUTPUT ;
    USE SIGNAL ;
    PORT
      LAYER M5 ;
        RECT  12.96 51.756 12.984 51.84 ;
    END
  END pw_data[196]
  PIN pw_data[197]
    DIRECTION OUTPUT ;
    USE SIGNAL ;
    PORT
      LAYER M5 ;
        RECT  3.888 51.756 3.912 51.84 ;
    END
  END pw_data[197]
  PIN pw_data[198]
    DIRECTION OUTPUT ;
    USE SIGNAL ;
    PORT
      LAYER M5 ;
        RECT  4.032 51.756 4.056 51.84 ;
    END
  END pw_data[198]
  PIN pw_data[199]
    DIRECTION OUTPUT ;
    USE SIGNAL ;
    PORT
      LAYER M5 ;
        RECT  4.176 51.756 4.2 51.84 ;
    END
  END pw_data[199]
  PIN pw_data[19]
    DIRECTION OUTPUT ;
    USE SIGNAL ;
    PORT
      LAYER M5 ;
        RECT  34.704 51.756 34.728 51.84 ;
    END
  END pw_data[19]
  PIN pw_data[1]
    DIRECTION OUTPUT ;
    USE SIGNAL ;
    PORT
      LAYER M5 ;
        RECT  45.936 51.756 45.96 51.84 ;
    END
  END pw_data[1]
  PIN pw_data[200]
    DIRECTION OUTPUT ;
    USE SIGNAL ;
    PORT
      LAYER M5 ;
        RECT  4.32 51.756 4.344 51.84 ;
    END
  END pw_data[200]
  PIN pw_data[201]
    DIRECTION OUTPUT ;
    USE SIGNAL ;
    PORT
      LAYER M5 ;
        RECT  4.464 51.756 4.488 51.84 ;
    END
  END pw_data[201]
  PIN pw_data[202]
    DIRECTION OUTPUT ;
    USE SIGNAL ;
    PORT
      LAYER M5 ;
        RECT  4.608 51.756 4.632 51.84 ;
    END
  END pw_data[202]
  PIN pw_data[203]
    DIRECTION OUTPUT ;
    USE SIGNAL ;
    PORT
      LAYER M5 ;
        RECT  4.752 51.756 4.776 51.84 ;
    END
  END pw_data[203]
  PIN pw_data[204]
    DIRECTION OUTPUT ;
    USE SIGNAL ;
    PORT
      LAYER M5 ;
        RECT  4.896 51.756 4.92 51.84 ;
    END
  END pw_data[204]
  PIN pw_data[205]
    DIRECTION OUTPUT ;
    USE SIGNAL ;
    PORT
      LAYER M5 ;
        RECT  5.04 51.756 5.064 51.84 ;
    END
  END pw_data[205]
  PIN pw_data[206]
    DIRECTION OUTPUT ;
    USE SIGNAL ;
    PORT
      LAYER M5 ;
        RECT  5.184 51.756 5.208 51.84 ;
    END
  END pw_data[206]
  PIN pw_data[207]
    DIRECTION OUTPUT ;
    USE SIGNAL ;
    PORT
      LAYER M5 ;
        RECT  5.328 51.756 5.352 51.84 ;
    END
  END pw_data[207]
  PIN pw_data[208]
    DIRECTION OUTPUT ;
    USE SIGNAL ;
    PORT
      LAYER M5 ;
        RECT  5.472 51.756 5.496 51.84 ;
    END
  END pw_data[208]
  PIN pw_data[209]
    DIRECTION OUTPUT ;
    USE SIGNAL ;
    PORT
      LAYER M5 ;
        RECT  5.616 51.756 5.64 51.84 ;
    END
  END pw_data[209]
  PIN pw_data[20]
    DIRECTION OUTPUT ;
    USE SIGNAL ;
    PORT
      LAYER M5 ;
        RECT  34.848 51.756 34.872 51.84 ;
    END
  END pw_data[20]
  PIN pw_data[210]
    DIRECTION OUTPUT ;
    USE SIGNAL ;
    PORT
      LAYER M5 ;
        RECT  5.76 51.756 5.784 51.84 ;
    END
  END pw_data[210]
  PIN pw_data[211]
    DIRECTION OUTPUT ;
    USE SIGNAL ;
    PORT
      LAYER M5 ;
        RECT  5.904 51.756 5.928 51.84 ;
    END
  END pw_data[211]
  PIN pw_data[212]
    DIRECTION OUTPUT ;
    USE SIGNAL ;
    PORT
      LAYER M5 ;
        RECT  6.048 51.756 6.072 51.84 ;
    END
  END pw_data[212]
  PIN pw_data[213]
    DIRECTION OUTPUT ;
    USE SIGNAL ;
    PORT
      LAYER M5 ;
        RECT  6.192 51.756 6.216 51.84 ;
    END
  END pw_data[213]
  PIN pw_data[214]
    DIRECTION OUTPUT ;
    USE SIGNAL ;
    PORT
      LAYER M5 ;
        RECT  6.336 51.756 6.36 51.84 ;
    END
  END pw_data[214]
  PIN pw_data[215]
    DIRECTION OUTPUT ;
    USE SIGNAL ;
    PORT
      LAYER M5 ;
        RECT  6.48 51.756 6.504 51.84 ;
    END
  END pw_data[215]
  PIN pw_data[216]
    DIRECTION OUTPUT ;
    USE SIGNAL ;
    PORT
      LAYER M5 ;
        RECT  6.624 51.756 6.648 51.84 ;
    END
  END pw_data[216]
  PIN pw_data[217]
    DIRECTION OUTPUT ;
    USE SIGNAL ;
    PORT
      LAYER M5 ;
        RECT  6.768 51.756 6.792 51.84 ;
    END
  END pw_data[217]
  PIN pw_data[218]
    DIRECTION OUTPUT ;
    USE SIGNAL ;
    PORT
      LAYER M5 ;
        RECT  6.912 51.756 6.936 51.84 ;
    END
  END pw_data[218]
  PIN pw_data[219]
    DIRECTION OUTPUT ;
    USE SIGNAL ;
    PORT
      LAYER M5 ;
        RECT  7.056 51.756 7.08 51.84 ;
    END
  END pw_data[219]
  PIN pw_data[21]
    DIRECTION OUTPUT ;
    USE SIGNAL ;
    PORT
      LAYER M5 ;
        RECT  34.992 51.756 35.016 51.84 ;
    END
  END pw_data[21]
  PIN pw_data[220]
    DIRECTION OUTPUT ;
    USE SIGNAL ;
    PORT
      LAYER M5 ;
        RECT  7.2 51.756 7.224 51.84 ;
    END
  END pw_data[220]
  PIN pw_data[221]
    DIRECTION OUTPUT ;
    USE SIGNAL ;
    PORT
      LAYER M5 ;
        RECT  7.344 51.756 7.368 51.84 ;
    END
  END pw_data[221]
  PIN pw_data[222]
    DIRECTION OUTPUT ;
    USE SIGNAL ;
    PORT
      LAYER M5 ;
        RECT  7.488 51.756 7.512 51.84 ;
    END
  END pw_data[222]
  PIN pw_data[223]
    DIRECTION OUTPUT ;
    USE SIGNAL ;
    PORT
      LAYER M5 ;
        RECT  7.632 51.756 7.656 51.84 ;
    END
  END pw_data[223]
  PIN pw_data[224]
    DIRECTION OUTPUT ;
    USE SIGNAL ;
    PORT
      LAYER M5 ;
        RECT  7.776 51.756 7.8 51.84 ;
    END
  END pw_data[224]
  PIN pw_data[225]
    DIRECTION OUTPUT ;
    USE SIGNAL ;
    PORT
      LAYER M5 ;
        RECT  7.92 51.756 7.944 51.84 ;
    END
  END pw_data[225]
  PIN pw_data[226]
    DIRECTION OUTPUT ;
    USE SIGNAL ;
    PORT
      LAYER M5 ;
        RECT  8.064 51.756 8.088 51.84 ;
    END
  END pw_data[226]
  PIN pw_data[227]
    DIRECTION OUTPUT ;
    USE SIGNAL ;
    PORT
      LAYER M5 ;
        RECT  8.208 51.756 8.232 51.84 ;
    END
  END pw_data[227]
  PIN pw_data[228]
    DIRECTION OUTPUT ;
    USE SIGNAL ;
    PORT
      LAYER M5 ;
        RECT  8.352 51.756 8.376 51.84 ;
    END
  END pw_data[228]
  PIN pw_data[229]
    DIRECTION OUTPUT ;
    USE SIGNAL ;
    PORT
      LAYER M5 ;
        RECT  28.512 51.756 28.536 51.84 ;
    END
  END pw_data[229]
  PIN pw_data[22]
    DIRECTION OUTPUT ;
    USE SIGNAL ;
    PORT
      LAYER M5 ;
        RECT  35.136 51.756 35.16 51.84 ;
    END
  END pw_data[22]
  PIN pw_data[230]
    DIRECTION OUTPUT ;
    USE SIGNAL ;
    PORT
      LAYER M5 ;
        RECT  28.656 51.756 28.68 51.84 ;
    END
  END pw_data[230]
  PIN pw_data[231]
    DIRECTION OUTPUT ;
    USE SIGNAL ;
    PORT
      LAYER M5 ;
        RECT  28.8 51.756 28.824 51.84 ;
    END
  END pw_data[231]
  PIN pw_data[232]
    DIRECTION OUTPUT ;
    USE SIGNAL ;
    PORT
      LAYER M5 ;
        RECT  28.944 51.756 28.968 51.84 ;
    END
  END pw_data[232]
  PIN pw_data[233]
    DIRECTION OUTPUT ;
    USE SIGNAL ;
    PORT
      LAYER M5 ;
        RECT  29.088 51.756 29.112 51.84 ;
    END
  END pw_data[233]
  PIN pw_data[234]
    DIRECTION OUTPUT ;
    USE SIGNAL ;
    PORT
      LAYER M5 ;
        RECT  29.232 51.756 29.256 51.84 ;
    END
  END pw_data[234]
  PIN pw_data[235]
    DIRECTION OUTPUT ;
    USE SIGNAL ;
    PORT
      LAYER M5 ;
        RECT  29.376 51.756 29.4 51.84 ;
    END
  END pw_data[235]
  PIN pw_data[236]
    DIRECTION OUTPUT ;
    USE SIGNAL ;
    PORT
      LAYER M5 ;
        RECT  29.52 51.756 29.544 51.84 ;
    END
  END pw_data[236]
  PIN pw_data[237]
    DIRECTION OUTPUT ;
    USE SIGNAL ;
    PORT
      LAYER M5 ;
        RECT  29.664 51.756 29.688 51.84 ;
    END
  END pw_data[237]
  PIN pw_data[238]
    DIRECTION OUTPUT ;
    USE SIGNAL ;
    PORT
      LAYER M5 ;
        RECT  29.808 51.756 29.832 51.84 ;
    END
  END pw_data[238]
  PIN pw_data[239]
    DIRECTION OUTPUT ;
    USE SIGNAL ;
    PORT
      LAYER M5 ;
        RECT  29.952 51.756 29.976 51.84 ;
    END
  END pw_data[239]
  PIN pw_data[23]
    DIRECTION OUTPUT ;
    USE SIGNAL ;
    PORT
      LAYER M5 ;
        RECT  35.28 51.756 35.304 51.84 ;
    END
  END pw_data[23]
  PIN pw_data[240]
    DIRECTION OUTPUT ;
    USE SIGNAL ;
    PORT
      LAYER M5 ;
        RECT  30.096 51.756 30.12 51.84 ;
    END
  END pw_data[240]
  PIN pw_data[241]
    DIRECTION OUTPUT ;
    USE SIGNAL ;
    PORT
      LAYER M5 ;
        RECT  30.24 51.756 30.264 51.84 ;
    END
  END pw_data[241]
  PIN pw_data[242]
    DIRECTION OUTPUT ;
    USE SIGNAL ;
    PORT
      LAYER M5 ;
        RECT  30.384 51.756 30.408 51.84 ;
    END
  END pw_data[242]
  PIN pw_data[243]
    DIRECTION OUTPUT ;
    USE SIGNAL ;
    PORT
      LAYER M5 ;
        RECT  30.528 51.756 30.552 51.84 ;
    END
  END pw_data[243]
  PIN pw_data[244]
    DIRECTION OUTPUT ;
    USE SIGNAL ;
    PORT
      LAYER M5 ;
        RECT  30.672 51.756 30.696 51.84 ;
    END
  END pw_data[244]
  PIN pw_data[245]
    DIRECTION OUTPUT ;
    USE SIGNAL ;
    PORT
      LAYER M5 ;
        RECT  30.816 51.756 30.84 51.84 ;
    END
  END pw_data[245]
  PIN pw_data[246]
    DIRECTION OUTPUT ;
    USE SIGNAL ;
    PORT
      LAYER M5 ;
        RECT  30.96 51.756 30.984 51.84 ;
    END
  END pw_data[246]
  PIN pw_data[247]
    DIRECTION OUTPUT ;
    USE SIGNAL ;
    PORT
      LAYER M5 ;
        RECT  31.104 51.756 31.128 51.84 ;
    END
  END pw_data[247]
  PIN pw_data[248]
    DIRECTION OUTPUT ;
    USE SIGNAL ;
    PORT
      LAYER M5 ;
        RECT  31.248 51.756 31.272 51.84 ;
    END
  END pw_data[248]
  PIN pw_data[249]
    DIRECTION OUTPUT ;
    USE SIGNAL ;
    PORT
      LAYER M5 ;
        RECT  31.392 51.756 31.416 51.84 ;
    END
  END pw_data[249]
  PIN pw_data[24]
    DIRECTION OUTPUT ;
    USE SIGNAL ;
    PORT
      LAYER M5 ;
        RECT  35.424 51.756 35.448 51.84 ;
    END
  END pw_data[24]
  PIN pw_data[250]
    DIRECTION OUTPUT ;
    USE SIGNAL ;
    PORT
      LAYER M5 ;
        RECT  31.536 51.756 31.56 51.84 ;
    END
  END pw_data[250]
  PIN pw_data[251]
    DIRECTION OUTPUT ;
    USE SIGNAL ;
    PORT
      LAYER M5 ;
        RECT  31.68 51.756 31.704 51.84 ;
    END
  END pw_data[251]
  PIN pw_data[252]
    DIRECTION OUTPUT ;
    USE SIGNAL ;
    PORT
      LAYER M5 ;
        RECT  31.824 51.756 31.848 51.84 ;
    END
  END pw_data[252]
  PIN pw_data[253]
    DIRECTION OUTPUT ;
    USE SIGNAL ;
    PORT
      LAYER M5 ;
        RECT  31.968 51.756 31.992 51.84 ;
    END
  END pw_data[253]
  PIN pw_data[254]
    DIRECTION OUTPUT ;
    USE SIGNAL ;
    PORT
      LAYER M5 ;
        RECT  32.112 51.756 32.136 51.84 ;
    END
  END pw_data[254]
  PIN pw_data[255]
    DIRECTION OUTPUT ;
    USE SIGNAL ;
    PORT
      LAYER M5 ;
        RECT  32.256 51.756 32.28 51.84 ;
    END
  END pw_data[255]
  PIN pw_data[25]
    DIRECTION OUTPUT ;
    USE SIGNAL ;
    PORT
      LAYER M5 ;
        RECT  35.568 51.756 35.592 51.84 ;
    END
  END pw_data[25]
  PIN pw_data[26]
    DIRECTION OUTPUT ;
    USE SIGNAL ;
    PORT
      LAYER M5 ;
        RECT  35.712 51.756 35.736 51.84 ;
    END
  END pw_data[26]
  PIN pw_data[27]
    DIRECTION OUTPUT ;
    USE SIGNAL ;
    PORT
      LAYER M5 ;
        RECT  35.856 51.756 35.88 51.84 ;
    END
  END pw_data[27]
  PIN pw_data[28]
    DIRECTION OUTPUT ;
    USE SIGNAL ;
    PORT
      LAYER M5 ;
        RECT  36 51.756 36.024 51.84 ;
    END
  END pw_data[28]
  PIN pw_data[29]
    DIRECTION OUTPUT ;
    USE SIGNAL ;
    PORT
      LAYER M5 ;
        RECT  36.144 51.756 36.168 51.84 ;
    END
  END pw_data[29]
  PIN pw_data[2]
    DIRECTION OUTPUT ;
    USE SIGNAL ;
    PORT
      LAYER M5 ;
        RECT  46.08 51.756 46.104 51.84 ;
    END
  END pw_data[2]
  PIN pw_data[30]
    DIRECTION OUTPUT ;
    USE SIGNAL ;
    PORT
      LAYER M5 ;
        RECT  36.288 51.756 36.312 51.84 ;
    END
  END pw_data[30]
  PIN pw_data[31]
    DIRECTION OUTPUT ;
    USE SIGNAL ;
    PORT
      LAYER M5 ;
        RECT  36.432 51.756 36.456 51.84 ;
    END
  END pw_data[31]
  PIN pw_data[32]
    DIRECTION OUTPUT ;
    USE SIGNAL ;
    PORT
      LAYER M5 ;
        RECT  36.576 51.756 36.6 51.84 ;
    END
  END pw_data[32]
  PIN pw_data[33]
    DIRECTION OUTPUT ;
    USE SIGNAL ;
    PORT
      LAYER M5 ;
        RECT  36.72 51.756 36.744 51.84 ;
    END
  END pw_data[33]
  PIN pw_data[34]
    DIRECTION OUTPUT ;
    USE SIGNAL ;
    PORT
      LAYER M5 ;
        RECT  36.864 51.756 36.888 51.84 ;
    END
  END pw_data[34]
  PIN pw_data[35]
    DIRECTION OUTPUT ;
    USE SIGNAL ;
    PORT
      LAYER M5 ;
        RECT  37.008 51.756 37.032 51.84 ;
    END
  END pw_data[35]
  PIN pw_data[36]
    DIRECTION OUTPUT ;
    USE SIGNAL ;
    PORT
      LAYER M5 ;
        RECT  37.152 51.756 37.176 51.84 ;
    END
  END pw_data[36]
  PIN pw_data[37]
    DIRECTION OUTPUT ;
    USE SIGNAL ;
    PORT
      LAYER M5 ;
        RECT  23.472 51.756 23.496 51.84 ;
    END
  END pw_data[37]
  PIN pw_data[38]
    DIRECTION OUTPUT ;
    USE SIGNAL ;
    PORT
      LAYER M5 ;
        RECT  23.616 51.756 23.64 51.84 ;
    END
  END pw_data[38]
  PIN pw_data[39]
    DIRECTION OUTPUT ;
    USE SIGNAL ;
    PORT
      LAYER M5 ;
        RECT  23.76 51.756 23.784 51.84 ;
    END
  END pw_data[39]
  PIN pw_data[3]
    DIRECTION OUTPUT ;
    USE SIGNAL ;
    PORT
      LAYER M5 ;
        RECT  46.224 51.756 46.248 51.84 ;
    END
  END pw_data[3]
  PIN pw_data[40]
    DIRECTION OUTPUT ;
    USE SIGNAL ;
    PORT
      LAYER M5 ;
        RECT  23.904 51.756 23.928 51.84 ;
    END
  END pw_data[40]
  PIN pw_data[41]
    DIRECTION OUTPUT ;
    USE SIGNAL ;
    PORT
      LAYER M5 ;
        RECT  24.048 51.756 24.072 51.84 ;
    END
  END pw_data[41]
  PIN pw_data[42]
    DIRECTION OUTPUT ;
    USE SIGNAL ;
    PORT
      LAYER M5 ;
        RECT  24.192 51.756 24.216 51.84 ;
    END
  END pw_data[42]
  PIN pw_data[43]
    DIRECTION OUTPUT ;
    USE SIGNAL ;
    PORT
      LAYER M5 ;
        RECT  24.336 51.756 24.36 51.84 ;
    END
  END pw_data[43]
  PIN pw_data[44]
    DIRECTION OUTPUT ;
    USE SIGNAL ;
    PORT
      LAYER M5 ;
        RECT  24.48 51.756 24.504 51.84 ;
    END
  END pw_data[44]
  PIN pw_data[45]
    DIRECTION OUTPUT ;
    USE SIGNAL ;
    PORT
      LAYER M5 ;
        RECT  24.624 51.756 24.648 51.84 ;
    END
  END pw_data[45]
  PIN pw_data[46]
    DIRECTION OUTPUT ;
    USE SIGNAL ;
    PORT
      LAYER M5 ;
        RECT  24.768 51.756 24.792 51.84 ;
    END
  END pw_data[46]
  PIN pw_data[47]
    DIRECTION OUTPUT ;
    USE SIGNAL ;
    PORT
      LAYER M5 ;
        RECT  24.912 51.756 24.936 51.84 ;
    END
  END pw_data[47]
  PIN pw_data[48]
    DIRECTION OUTPUT ;
    USE SIGNAL ;
    PORT
      LAYER M5 ;
        RECT  25.056 51.756 25.08 51.84 ;
    END
  END pw_data[48]
  PIN pw_data[49]
    DIRECTION OUTPUT ;
    USE SIGNAL ;
    PORT
      LAYER M5 ;
        RECT  25.2 51.756 25.224 51.84 ;
    END
  END pw_data[49]
  PIN pw_data[4]
    DIRECTION OUTPUT ;
    USE SIGNAL ;
    PORT
      LAYER M5 ;
        RECT  46.368 51.756 46.392 51.84 ;
    END
  END pw_data[4]
  PIN pw_data[50]
    DIRECTION OUTPUT ;
    USE SIGNAL ;
    PORT
      LAYER M5 ;
        RECT  25.344 51.756 25.368 51.84 ;
    END
  END pw_data[50]
  PIN pw_data[51]
    DIRECTION OUTPUT ;
    USE SIGNAL ;
    PORT
      LAYER M5 ;
        RECT  25.488 51.756 25.512 51.84 ;
    END
  END pw_data[51]
  PIN pw_data[52]
    DIRECTION OUTPUT ;
    USE SIGNAL ;
    PORT
      LAYER M5 ;
        RECT  25.632 51.756 25.656 51.84 ;
    END
  END pw_data[52]
  PIN pw_data[53]
    DIRECTION OUTPUT ;
    USE SIGNAL ;
    PORT
      LAYER M5 ;
        RECT  25.776 51.756 25.8 51.84 ;
    END
  END pw_data[53]
  PIN pw_data[54]
    DIRECTION OUTPUT ;
    USE SIGNAL ;
    PORT
      LAYER M5 ;
        RECT  25.92 51.756 25.944 51.84 ;
    END
  END pw_data[54]
  PIN pw_data[55]
    DIRECTION OUTPUT ;
    USE SIGNAL ;
    PORT
      LAYER M5 ;
        RECT  26.064 51.756 26.088 51.84 ;
    END
  END pw_data[55]
  PIN pw_data[56]
    DIRECTION OUTPUT ;
    USE SIGNAL ;
    PORT
      LAYER M5 ;
        RECT  26.208 51.756 26.232 51.84 ;
    END
  END pw_data[56]
  PIN pw_data[57]
    DIRECTION OUTPUT ;
    USE SIGNAL ;
    PORT
      LAYER M5 ;
        RECT  26.352 51.756 26.376 51.84 ;
    END
  END pw_data[57]
  PIN pw_data[58]
    DIRECTION OUTPUT ;
    USE SIGNAL ;
    PORT
      LAYER M5 ;
        RECT  26.496 51.756 26.52 51.84 ;
    END
  END pw_data[58]
  PIN pw_data[59]
    DIRECTION OUTPUT ;
    USE SIGNAL ;
    PORT
      LAYER M5 ;
        RECT  26.64 51.756 26.664 51.84 ;
    END
  END pw_data[59]
  PIN pw_data[5]
    DIRECTION OUTPUT ;
    USE SIGNAL ;
    PORT
      LAYER M5 ;
        RECT  32.688 51.756 32.712 51.84 ;
    END
  END pw_data[5]
  PIN pw_data[60]
    DIRECTION OUTPUT ;
    USE SIGNAL ;
    PORT
      LAYER M5 ;
        RECT  26.784 51.756 26.808 51.84 ;
    END
  END pw_data[60]
  PIN pw_data[61]
    DIRECTION OUTPUT ;
    USE SIGNAL ;
    PORT
      LAYER M5 ;
        RECT  26.928 51.756 26.952 51.84 ;
    END
  END pw_data[61]
  PIN pw_data[62]
    DIRECTION OUTPUT ;
    USE SIGNAL ;
    PORT
      LAYER M5 ;
        RECT  27.072 51.756 27.096 51.84 ;
    END
  END pw_data[62]
  PIN pw_data[63]
    DIRECTION OUTPUT ;
    USE SIGNAL ;
    PORT
      LAYER M5 ;
        RECT  27.216 51.756 27.24 51.84 ;
    END
  END pw_data[63]
  PIN pw_data[64]
    DIRECTION OUTPUT ;
    USE SIGNAL ;
    PORT
      LAYER M5 ;
        RECT  27.36 51.756 27.384 51.84 ;
    END
  END pw_data[64]
  PIN pw_data[65]
    DIRECTION OUTPUT ;
    USE SIGNAL ;
    PORT
      LAYER M5 ;
        RECT  27.504 51.756 27.528 51.84 ;
    END
  END pw_data[65]
  PIN pw_data[66]
    DIRECTION OUTPUT ;
    USE SIGNAL ;
    PORT
      LAYER M5 ;
        RECT  27.648 51.756 27.672 51.84 ;
    END
  END pw_data[66]
  PIN pw_data[67]
    DIRECTION OUTPUT ;
    USE SIGNAL ;
    PORT
      LAYER M5 ;
        RECT  27.792 51.756 27.816 51.84 ;
    END
  END pw_data[67]
  PIN pw_data[68]
    DIRECTION OUTPUT ;
    USE SIGNAL ;
    PORT
      LAYER M5 ;
        RECT  27.936 51.756 27.96 51.84 ;
    END
  END pw_data[68]
  PIN pw_data[69]
    DIRECTION OUTPUT ;
    USE SIGNAL ;
    PORT
      LAYER M5 ;
        RECT  17.712 51.756 17.736 51.84 ;
    END
  END pw_data[69]
  PIN pw_data[6]
    DIRECTION OUTPUT ;
    USE SIGNAL ;
    PORT
      LAYER M5 ;
        RECT  32.832 51.756 32.856 51.84 ;
    END
  END pw_data[6]
  PIN pw_data[70]
    DIRECTION OUTPUT ;
    USE SIGNAL ;
    PORT
      LAYER M5 ;
        RECT  17.856 51.756 17.88 51.84 ;
    END
  END pw_data[70]
  PIN pw_data[71]
    DIRECTION OUTPUT ;
    USE SIGNAL ;
    PORT
      LAYER M5 ;
        RECT  18 51.756 18.024 51.84 ;
    END
  END pw_data[71]
  PIN pw_data[72]
    DIRECTION OUTPUT ;
    USE SIGNAL ;
    PORT
      LAYER M5 ;
        RECT  18.144 51.756 18.168 51.84 ;
    END
  END pw_data[72]
  PIN pw_data[73]
    DIRECTION OUTPUT ;
    USE SIGNAL ;
    PORT
      LAYER M5 ;
        RECT  18.288 51.756 18.312 51.84 ;
    END
  END pw_data[73]
  PIN pw_data[74]
    DIRECTION OUTPUT ;
    USE SIGNAL ;
    PORT
      LAYER M5 ;
        RECT  18.432 51.756 18.456 51.84 ;
    END
  END pw_data[74]
  PIN pw_data[75]
    DIRECTION OUTPUT ;
    USE SIGNAL ;
    PORT
      LAYER M5 ;
        RECT  18.576 51.756 18.6 51.84 ;
    END
  END pw_data[75]
  PIN pw_data[76]
    DIRECTION OUTPUT ;
    USE SIGNAL ;
    PORT
      LAYER M5 ;
        RECT  18.72 51.756 18.744 51.84 ;
    END
  END pw_data[76]
  PIN pw_data[77]
    DIRECTION OUTPUT ;
    USE SIGNAL ;
    PORT
      LAYER M5 ;
        RECT  18.864 51.756 18.888 51.84 ;
    END
  END pw_data[77]
  PIN pw_data[78]
    DIRECTION OUTPUT ;
    USE SIGNAL ;
    PORT
      LAYER M5 ;
        RECT  19.008 51.756 19.032 51.84 ;
    END
  END pw_data[78]
  PIN pw_data[79]
    DIRECTION OUTPUT ;
    USE SIGNAL ;
    PORT
      LAYER M5 ;
        RECT  19.152 51.756 19.176 51.84 ;
    END
  END pw_data[79]
  PIN pw_data[7]
    DIRECTION OUTPUT ;
    USE SIGNAL ;
    PORT
      LAYER M5 ;
        RECT  32.976 51.756 33 51.84 ;
    END
  END pw_data[7]
  PIN pw_data[80]
    DIRECTION OUTPUT ;
    USE SIGNAL ;
    PORT
      LAYER M5 ;
        RECT  19.296 51.756 19.32 51.84 ;
    END
  END pw_data[80]
  PIN pw_data[81]
    DIRECTION OUTPUT ;
    USE SIGNAL ;
    PORT
      LAYER M5 ;
        RECT  19.44 51.756 19.464 51.84 ;
    END
  END pw_data[81]
  PIN pw_data[82]
    DIRECTION OUTPUT ;
    USE SIGNAL ;
    PORT
      LAYER M5 ;
        RECT  19.584 51.756 19.608 51.84 ;
    END
  END pw_data[82]
  PIN pw_data[83]
    DIRECTION OUTPUT ;
    USE SIGNAL ;
    PORT
      LAYER M5 ;
        RECT  19.728 51.756 19.752 51.84 ;
    END
  END pw_data[83]
  PIN pw_data[84]
    DIRECTION OUTPUT ;
    USE SIGNAL ;
    PORT
      LAYER M5 ;
        RECT  19.872 51.756 19.896 51.84 ;
    END
  END pw_data[84]
  PIN pw_data[85]
    DIRECTION OUTPUT ;
    USE SIGNAL ;
    PORT
      LAYER M5 ;
        RECT  20.016 51.756 20.04 51.84 ;
    END
  END pw_data[85]
  PIN pw_data[86]
    DIRECTION OUTPUT ;
    USE SIGNAL ;
    PORT
      LAYER M5 ;
        RECT  20.16 51.756 20.184 51.84 ;
    END
  END pw_data[86]
  PIN pw_data[87]
    DIRECTION OUTPUT ;
    USE SIGNAL ;
    PORT
      LAYER M5 ;
        RECT  20.304 51.756 20.328 51.84 ;
    END
  END pw_data[87]
  PIN pw_data[88]
    DIRECTION OUTPUT ;
    USE SIGNAL ;
    PORT
      LAYER M5 ;
        RECT  20.448 51.756 20.472 51.84 ;
    END
  END pw_data[88]
  PIN pw_data[89]
    DIRECTION OUTPUT ;
    USE SIGNAL ;
    PORT
      LAYER M5 ;
        RECT  20.592 51.756 20.616 51.84 ;
    END
  END pw_data[89]
  PIN pw_data[8]
    DIRECTION OUTPUT ;
    USE SIGNAL ;
    PORT
      LAYER M5 ;
        RECT  33.12 51.756 33.144 51.84 ;
    END
  END pw_data[8]
  PIN pw_data[90]
    DIRECTION OUTPUT ;
    USE SIGNAL ;
    PORT
      LAYER M5 ;
        RECT  20.736 51.756 20.76 51.84 ;
    END
  END pw_data[90]
  PIN pw_data[91]
    DIRECTION OUTPUT ;
    USE SIGNAL ;
    PORT
      LAYER M5 ;
        RECT  20.88 51.756 20.904 51.84 ;
    END
  END pw_data[91]
  PIN pw_data[92]
    DIRECTION OUTPUT ;
    USE SIGNAL ;
    PORT
      LAYER M5 ;
        RECT  21.024 51.756 21.048 51.84 ;
    END
  END pw_data[92]
  PIN pw_data[93]
    DIRECTION OUTPUT ;
    USE SIGNAL ;
    PORT
      LAYER M5 ;
        RECT  21.168 51.756 21.192 51.84 ;
    END
  END pw_data[93]
  PIN pw_data[94]
    DIRECTION OUTPUT ;
    USE SIGNAL ;
    PORT
      LAYER M5 ;
        RECT  21.312 51.756 21.336 51.84 ;
    END
  END pw_data[94]
  PIN pw_data[95]
    DIRECTION OUTPUT ;
    USE SIGNAL ;
    PORT
      LAYER M5 ;
        RECT  21.456 51.756 21.48 51.84 ;
    END
  END pw_data[95]
  PIN pw_data[96]
    DIRECTION OUTPUT ;
    USE SIGNAL ;
    PORT
      LAYER M5 ;
        RECT  21.6 51.756 21.624 51.84 ;
    END
  END pw_data[96]
  PIN pw_data[97]
    DIRECTION OUTPUT ;
    USE SIGNAL ;
    PORT
      LAYER M5 ;
        RECT  21.744 51.756 21.768 51.84 ;
    END
  END pw_data[97]
  PIN pw_data[98]
    DIRECTION OUTPUT ;
    USE SIGNAL ;
    PORT
      LAYER M5 ;
        RECT  21.888 51.756 21.912 51.84 ;
    END
  END pw_data[98]
  PIN pw_data[99]
    DIRECTION OUTPUT ;
    USE SIGNAL ;
    PORT
      LAYER M5 ;
        RECT  22.032 51.756 22.056 51.84 ;
    END
  END pw_data[99]
  PIN pw_data[9]
    DIRECTION OUTPUT ;
    USE SIGNAL ;
    PORT
      LAYER M5 ;
        RECT  33.264 51.756 33.288 51.84 ;
    END
  END pw_data[9]
  PIN pw_we[0]
    DIRECTION OUTPUT ;
    USE SIGNAL ;
    PORT
      LAYER M5 ;
        RECT  32.4 51.756 32.424 51.84 ;
    END
  END pw_we[0]
  PIN ready
    DIRECTION OUTPUT ;
    USE SIGNAL ;
    PORT
      LAYER M5 ;
        RECT  33.408 0 33.432 0.084 ;
    END
  END ready
  PIN rec[0]
    DIRECTION OUTPUT ;
    USE SIGNAL ;
    PORT
      LAYER M4 ;
        RECT  0 13.248 0.084 13.272 ;
    END
  END rec[0]
  PIN rec[100]
    DIRECTION OUTPUT ;
    USE SIGNAL ;
    PORT
      LAYER M4 ;
        RECT  0 9.216 0.084 9.24 ;
    END
  END rec[100]
  PIN rec[101]
    DIRECTION OUTPUT ;
    USE SIGNAL ;
    PORT
      LAYER M4 ;
        RECT  0 9.36 0.084 9.384 ;
    END
  END rec[101]
  PIN rec[102]
    DIRECTION OUTPUT ;
    USE SIGNAL ;
    PORT
      LAYER M4 ;
        RECT  0 9.504 0.084 9.528 ;
    END
  END rec[102]
  PIN rec[103]
    DIRECTION OUTPUT ;
    USE SIGNAL ;
    PORT
      LAYER M4 ;
        RECT  0 9.648 0.084 9.672 ;
    END
  END rec[103]
  PIN rec[104]
    DIRECTION OUTPUT ;
    USE SIGNAL ;
    PORT
      LAYER M4 ;
        RECT  0 9.792 0.084 9.816 ;
    END
  END rec[104]
  PIN rec[105]
    DIRECTION OUTPUT ;
    USE SIGNAL ;
    PORT
      LAYER M4 ;
        RECT  0 9.936 0.084 9.96 ;
    END
  END rec[105]
  PIN rec[106]
    DIRECTION OUTPUT ;
    USE SIGNAL ;
    PORT
      LAYER M4 ;
        RECT  0 10.08 0.084 10.104 ;
    END
  END rec[106]
  PIN rec[107]
    DIRECTION OUTPUT ;
    USE SIGNAL ;
    PORT
      LAYER M4 ;
        RECT  0 10.224 0.084 10.248 ;
    END
  END rec[107]
  PIN rec[108]
    DIRECTION OUTPUT ;
    USE SIGNAL ;
    PORT
      LAYER M4 ;
        RECT  0 10.368 0.084 10.392 ;
    END
  END rec[108]
  PIN rec[109]
    DIRECTION OUTPUT ;
    USE SIGNAL ;
    PORT
      LAYER M4 ;
        RECT  0 10.512 0.084 10.536 ;
    END
  END rec[109]
  PIN rec[10]
    DIRECTION OUTPUT ;
    USE SIGNAL ;
    PORT
      LAYER M4 ;
        RECT  0 14.688 0.084 14.712 ;
    END
  END rec[10]
  PIN rec[110]
    DIRECTION OUTPUT ;
    USE SIGNAL ;
    PORT
      LAYER M4 ;
        RECT  0 10.656 0.084 10.68 ;
    END
  END rec[110]
  PIN rec[111]
    DIRECTION OUTPUT ;
    USE SIGNAL ;
    PORT
      LAYER M4 ;
        RECT  0 10.8 0.084 10.824 ;
    END
  END rec[111]
  PIN rec[112]
    DIRECTION OUTPUT ;
    USE SIGNAL ;
    PORT
      LAYER M4 ;
        RECT  0 10.944 0.084 10.968 ;
    END
  END rec[112]
  PIN rec[113]
    DIRECTION OUTPUT ;
    USE SIGNAL ;
    PORT
      LAYER M4 ;
        RECT  0 11.088 0.084 11.112 ;
    END
  END rec[113]
  PIN rec[114]
    DIRECTION OUTPUT ;
    USE SIGNAL ;
    PORT
      LAYER M4 ;
        RECT  0 11.232 0.084 11.256 ;
    END
  END rec[114]
  PIN rec[115]
    DIRECTION OUTPUT ;
    USE SIGNAL ;
    PORT
      LAYER M4 ;
        RECT  0 11.376 0.084 11.4 ;
    END
  END rec[115]
  PIN rec[116]
    DIRECTION OUTPUT ;
    USE SIGNAL ;
    PORT
      LAYER M4 ;
        RECT  0 11.52 0.084 11.544 ;
    END
  END rec[116]
  PIN rec[117]
    DIRECTION OUTPUT ;
    USE SIGNAL ;
    PORT
      LAYER M4 ;
        RECT  0 11.664 0.084 11.688 ;
    END
  END rec[117]
  PIN rec[118]
    DIRECTION OUTPUT ;
    USE SIGNAL ;
    PORT
      LAYER M4 ;
        RECT  0 11.808 0.084 11.832 ;
    END
  END rec[118]
  PIN rec[119]
    DIRECTION OUTPUT ;
    USE SIGNAL ;
    PORT
      LAYER M4 ;
        RECT  0 11.952 0.084 11.976 ;
    END
  END rec[119]
  PIN rec[11]
    DIRECTION OUTPUT ;
    USE SIGNAL ;
    PORT
      LAYER M4 ;
        RECT  0 14.832 0.084 14.856 ;
    END
  END rec[11]
  PIN rec[120]
    DIRECTION OUTPUT ;
    USE SIGNAL ;
    PORT
      LAYER M4 ;
        RECT  0 12.096 0.084 12.12 ;
    END
  END rec[120]
  PIN rec[121]
    DIRECTION OUTPUT ;
    USE SIGNAL ;
    PORT
      LAYER M4 ;
        RECT  0 12.24 0.084 12.264 ;
    END
  END rec[121]
  PIN rec[122]
    DIRECTION OUTPUT ;
    USE SIGNAL ;
    PORT
      LAYER M4 ;
        RECT  0 12.384 0.084 12.408 ;
    END
  END rec[122]
  PIN rec[123]
    DIRECTION OUTPUT ;
    USE SIGNAL ;
    PORT
      LAYER M4 ;
        RECT  0 12.528 0.084 12.552 ;
    END
  END rec[123]
  PIN rec[124]
    DIRECTION OUTPUT ;
    USE SIGNAL ;
    PORT
      LAYER M4 ;
        RECT  0 12.672 0.084 12.696 ;
    END
  END rec[124]
  PIN rec[125]
    DIRECTION OUTPUT ;
    USE SIGNAL ;
    PORT
      LAYER M4 ;
        RECT  0 12.816 0.084 12.84 ;
    END
  END rec[125]
  PIN rec[126]
    DIRECTION OUTPUT ;
    USE SIGNAL ;
    PORT
      LAYER M4 ;
        RECT  0 12.96 0.084 12.984 ;
    END
  END rec[126]
  PIN rec[127]
    DIRECTION OUTPUT ;
    USE SIGNAL ;
    PORT
      LAYER M4 ;
        RECT  0 28.08 0.084 28.104 ;
    END
  END rec[127]
  PIN rec[128]
    DIRECTION OUTPUT ;
    USE SIGNAL ;
    PORT
      LAYER M4 ;
        RECT  0 28.224 0.084 28.248 ;
    END
  END rec[128]
  PIN rec[129]
    DIRECTION OUTPUT ;
    USE SIGNAL ;
    PORT
      LAYER M4 ;
        RECT  0 28.368 0.084 28.392 ;
    END
  END rec[129]
  PIN rec[12]
    DIRECTION OUTPUT ;
    USE SIGNAL ;
    PORT
      LAYER M4 ;
        RECT  0 14.976 0.084 15 ;
    END
  END rec[12]
  PIN rec[130]
    DIRECTION OUTPUT ;
    USE SIGNAL ;
    PORT
      LAYER M4 ;
        RECT  0 28.512 0.084 28.536 ;
    END
  END rec[130]
  PIN rec[131]
    DIRECTION OUTPUT ;
    USE SIGNAL ;
    PORT
      LAYER M4 ;
        RECT  0 28.656 0.084 28.68 ;
    END
  END rec[131]
  PIN rec[132]
    DIRECTION OUTPUT ;
    USE SIGNAL ;
    PORT
      LAYER M4 ;
        RECT  0 28.8 0.084 28.824 ;
    END
  END rec[132]
  PIN rec[133]
    DIRECTION OUTPUT ;
    USE SIGNAL ;
    PORT
      LAYER M4 ;
        RECT  0 28.944 0.084 28.968 ;
    END
  END rec[133]
  PIN rec[134]
    DIRECTION OUTPUT ;
    USE SIGNAL ;
    PORT
      LAYER M4 ;
        RECT  0 29.088 0.084 29.112 ;
    END
  END rec[134]
  PIN rec[135]
    DIRECTION OUTPUT ;
    USE SIGNAL ;
    PORT
      LAYER M4 ;
        RECT  0 29.232 0.084 29.256 ;
    END
  END rec[135]
  PIN rec[136]
    DIRECTION OUTPUT ;
    USE SIGNAL ;
    PORT
      LAYER M4 ;
        RECT  0 29.376 0.084 29.4 ;
    END
  END rec[136]
  PIN rec[137]
    DIRECTION OUTPUT ;
    USE SIGNAL ;
    PORT
      LAYER M4 ;
        RECT  0 29.52 0.084 29.544 ;
    END
  END rec[137]
  PIN rec[138]
    DIRECTION OUTPUT ;
    USE SIGNAL ;
    PORT
      LAYER M4 ;
        RECT  0 29.664 0.084 29.688 ;
    END
  END rec[138]
  PIN rec[139]
    DIRECTION OUTPUT ;
    USE SIGNAL ;
    PORT
      LAYER M4 ;
        RECT  0 29.808 0.084 29.832 ;
    END
  END rec[139]
  PIN rec[13]
    DIRECTION OUTPUT ;
    USE SIGNAL ;
    PORT
      LAYER M4 ;
        RECT  0 15.12 0.084 15.144 ;
    END
  END rec[13]
  PIN rec[140]
    DIRECTION OUTPUT ;
    USE SIGNAL ;
    PORT
      LAYER M4 ;
        RECT  0 29.952 0.084 29.976 ;
    END
  END rec[140]
  PIN rec[141]
    DIRECTION OUTPUT ;
    USE SIGNAL ;
    PORT
      LAYER M4 ;
        RECT  0 30.096 0.084 30.12 ;
    END
  END rec[141]
  PIN rec[142]
    DIRECTION OUTPUT ;
    USE SIGNAL ;
    PORT
      LAYER M4 ;
        RECT  0 30.24 0.084 30.264 ;
    END
  END rec[142]
  PIN rec[143]
    DIRECTION OUTPUT ;
    USE SIGNAL ;
    PORT
      LAYER M4 ;
        RECT  0 30.384 0.084 30.408 ;
    END
  END rec[143]
  PIN rec[144]
    DIRECTION OUTPUT ;
    USE SIGNAL ;
    PORT
      LAYER M4 ;
        RECT  0 30.528 0.084 30.552 ;
    END
  END rec[144]
  PIN rec[145]
    DIRECTION OUTPUT ;
    USE SIGNAL ;
    PORT
      LAYER M4 ;
        RECT  0 30.672 0.084 30.696 ;
    END
  END rec[145]
  PIN rec[146]
    DIRECTION OUTPUT ;
    USE SIGNAL ;
    PORT
      LAYER M4 ;
        RECT  0 30.816 0.084 30.84 ;
    END
  END rec[146]
  PIN rec[147]
    DIRECTION OUTPUT ;
    USE SIGNAL ;
    PORT
      LAYER M4 ;
        RECT  0 30.96 0.084 30.984 ;
    END
  END rec[147]
  PIN rec[148]
    DIRECTION OUTPUT ;
    USE SIGNAL ;
    PORT
      LAYER M4 ;
        RECT  0 31.104 0.084 31.128 ;
    END
  END rec[148]
  PIN rec[149]
    DIRECTION OUTPUT ;
    USE SIGNAL ;
    PORT
      LAYER M4 ;
        RECT  0 31.248 0.084 31.272 ;
    END
  END rec[149]
  PIN rec[14]
    DIRECTION OUTPUT ;
    USE SIGNAL ;
    PORT
      LAYER M4 ;
        RECT  0 15.264 0.084 15.288 ;
    END
  END rec[14]
  PIN rec[150]
    DIRECTION OUTPUT ;
    USE SIGNAL ;
    PORT
      LAYER M4 ;
        RECT  0 31.392 0.084 31.416 ;
    END
  END rec[150]
  PIN rec[151]
    DIRECTION OUTPUT ;
    USE SIGNAL ;
    PORT
      LAYER M4 ;
        RECT  0 31.536 0.084 31.56 ;
    END
  END rec[151]
  PIN rec[152]
    DIRECTION OUTPUT ;
    USE SIGNAL ;
    PORT
      LAYER M4 ;
        RECT  0 31.68 0.084 31.704 ;
    END
  END rec[152]
  PIN rec[153]
    DIRECTION OUTPUT ;
    USE SIGNAL ;
    PORT
      LAYER M4 ;
        RECT  0 31.824 0.084 31.848 ;
    END
  END rec[153]
  PIN rec[154]
    DIRECTION OUTPUT ;
    USE SIGNAL ;
    PORT
      LAYER M4 ;
        RECT  0 31.968 0.084 31.992 ;
    END
  END rec[154]
  PIN rec[155]
    DIRECTION OUTPUT ;
    USE SIGNAL ;
    PORT
      LAYER M4 ;
        RECT  0 32.112 0.084 32.136 ;
    END
  END rec[155]
  PIN rec[156]
    DIRECTION OUTPUT ;
    USE SIGNAL ;
    PORT
      LAYER M4 ;
        RECT  0 32.256 0.084 32.28 ;
    END
  END rec[156]
  PIN rec[157]
    DIRECTION OUTPUT ;
    USE SIGNAL ;
    PORT
      LAYER M4 ;
        RECT  0 32.4 0.084 32.424 ;
    END
  END rec[157]
  PIN rec[158]
    DIRECTION OUTPUT ;
    USE SIGNAL ;
    PORT
      LAYER M4 ;
        RECT  0 32.544 0.084 32.568 ;
    END
  END rec[158]
  PIN rec[159]
    DIRECTION OUTPUT ;
    USE SIGNAL ;
    PORT
      LAYER M4 ;
        RECT  0 37.296 0.084 37.32 ;
    END
  END rec[159]
  PIN rec[15]
    DIRECTION OUTPUT ;
    USE SIGNAL ;
    PORT
      LAYER M4 ;
        RECT  0 15.408 0.084 15.432 ;
    END
  END rec[15]
  PIN rec[160]
    DIRECTION OUTPUT ;
    USE SIGNAL ;
    PORT
      LAYER M4 ;
        RECT  0 37.44 0.084 37.464 ;
    END
  END rec[160]
  PIN rec[161]
    DIRECTION OUTPUT ;
    USE SIGNAL ;
    PORT
      LAYER M4 ;
        RECT  0 37.584 0.084 37.608 ;
    END
  END rec[161]
  PIN rec[162]
    DIRECTION OUTPUT ;
    USE SIGNAL ;
    PORT
      LAYER M4 ;
        RECT  0 37.728 0.084 37.752 ;
    END
  END rec[162]
  PIN rec[163]
    DIRECTION OUTPUT ;
    USE SIGNAL ;
    PORT
      LAYER M4 ;
        RECT  0 37.872 0.084 37.896 ;
    END
  END rec[163]
  PIN rec[164]
    DIRECTION OUTPUT ;
    USE SIGNAL ;
    PORT
      LAYER M4 ;
        RECT  0 38.016 0.084 38.04 ;
    END
  END rec[164]
  PIN rec[165]
    DIRECTION OUTPUT ;
    USE SIGNAL ;
    PORT
      LAYER M4 ;
        RECT  0 38.16 0.084 38.184 ;
    END
  END rec[165]
  PIN rec[166]
    DIRECTION OUTPUT ;
    USE SIGNAL ;
    PORT
      LAYER M4 ;
        RECT  0 38.304 0.084 38.328 ;
    END
  END rec[166]
  PIN rec[167]
    DIRECTION OUTPUT ;
    USE SIGNAL ;
    PORT
      LAYER M4 ;
        RECT  0 38.448 0.084 38.472 ;
    END
  END rec[167]
  PIN rec[168]
    DIRECTION OUTPUT ;
    USE SIGNAL ;
    PORT
      LAYER M4 ;
        RECT  0 38.592 0.084 38.616 ;
    END
  END rec[168]
  PIN rec[169]
    DIRECTION OUTPUT ;
    USE SIGNAL ;
    PORT
      LAYER M4 ;
        RECT  0 38.736 0.084 38.76 ;
    END
  END rec[169]
  PIN rec[16]
    DIRECTION OUTPUT ;
    USE SIGNAL ;
    PORT
      LAYER M4 ;
        RECT  0 15.552 0.084 15.576 ;
    END
  END rec[16]
  PIN rec[170]
    DIRECTION OUTPUT ;
    USE SIGNAL ;
    PORT
      LAYER M4 ;
        RECT  0 38.88 0.084 38.904 ;
    END
  END rec[170]
  PIN rec[171]
    DIRECTION OUTPUT ;
    USE SIGNAL ;
    PORT
      LAYER M4 ;
        RECT  0 39.024 0.084 39.048 ;
    END
  END rec[171]
  PIN rec[172]
    DIRECTION OUTPUT ;
    USE SIGNAL ;
    PORT
      LAYER M4 ;
        RECT  0 39.168 0.084 39.192 ;
    END
  END rec[172]
  PIN rec[173]
    DIRECTION OUTPUT ;
    USE SIGNAL ;
    PORT
      LAYER M4 ;
        RECT  0 39.312 0.084 39.336 ;
    END
  END rec[173]
  PIN rec[174]
    DIRECTION OUTPUT ;
    USE SIGNAL ;
    PORT
      LAYER M4 ;
        RECT  0 39.456 0.084 39.48 ;
    END
  END rec[174]
  PIN rec[175]
    DIRECTION OUTPUT ;
    USE SIGNAL ;
    PORT
      LAYER M4 ;
        RECT  0 39.6 0.084 39.624 ;
    END
  END rec[175]
  PIN rec[176]
    DIRECTION OUTPUT ;
    USE SIGNAL ;
    PORT
      LAYER M4 ;
        RECT  0 39.744 0.084 39.768 ;
    END
  END rec[176]
  PIN rec[177]
    DIRECTION OUTPUT ;
    USE SIGNAL ;
    PORT
      LAYER M4 ;
        RECT  0 39.888 0.084 39.912 ;
    END
  END rec[177]
  PIN rec[178]
    DIRECTION OUTPUT ;
    USE SIGNAL ;
    PORT
      LAYER M4 ;
        RECT  0 40.032 0.084 40.056 ;
    END
  END rec[178]
  PIN rec[179]
    DIRECTION OUTPUT ;
    USE SIGNAL ;
    PORT
      LAYER M4 ;
        RECT  0 40.176 0.084 40.2 ;
    END
  END rec[179]
  PIN rec[17]
    DIRECTION OUTPUT ;
    USE SIGNAL ;
    PORT
      LAYER M4 ;
        RECT  0 15.696 0.084 15.72 ;
    END
  END rec[17]
  PIN rec[180]
    DIRECTION OUTPUT ;
    USE SIGNAL ;
    PORT
      LAYER M4 ;
        RECT  0 40.32 0.084 40.344 ;
    END
  END rec[180]
  PIN rec[181]
    DIRECTION OUTPUT ;
    USE SIGNAL ;
    PORT
      LAYER M4 ;
        RECT  0 40.464 0.084 40.488 ;
    END
  END rec[181]
  PIN rec[182]
    DIRECTION OUTPUT ;
    USE SIGNAL ;
    PORT
      LAYER M4 ;
        RECT  0 40.608 0.084 40.632 ;
    END
  END rec[182]
  PIN rec[183]
    DIRECTION OUTPUT ;
    USE SIGNAL ;
    PORT
      LAYER M4 ;
        RECT  0 40.752 0.084 40.776 ;
    END
  END rec[183]
  PIN rec[184]
    DIRECTION OUTPUT ;
    USE SIGNAL ;
    PORT
      LAYER M4 ;
        RECT  0 40.896 0.084 40.92 ;
    END
  END rec[184]
  PIN rec[185]
    DIRECTION OUTPUT ;
    USE SIGNAL ;
    PORT
      LAYER M4 ;
        RECT  0 41.04 0.084 41.064 ;
    END
  END rec[185]
  PIN rec[186]
    DIRECTION OUTPUT ;
    USE SIGNAL ;
    PORT
      LAYER M4 ;
        RECT  0 41.184 0.084 41.208 ;
    END
  END rec[186]
  PIN rec[187]
    DIRECTION OUTPUT ;
    USE SIGNAL ;
    PORT
      LAYER M4 ;
        RECT  0 41.328 0.084 41.352 ;
    END
  END rec[187]
  PIN rec[188]
    DIRECTION OUTPUT ;
    USE SIGNAL ;
    PORT
      LAYER M4 ;
        RECT  0 41.472 0.084 41.496 ;
    END
  END rec[188]
  PIN rec[189]
    DIRECTION OUTPUT ;
    USE SIGNAL ;
    PORT
      LAYER M4 ;
        RECT  0 41.616 0.084 41.64 ;
    END
  END rec[189]
  PIN rec[18]
    DIRECTION OUTPUT ;
    USE SIGNAL ;
    PORT
      LAYER M4 ;
        RECT  0 15.84 0.084 15.864 ;
    END
  END rec[18]
  PIN rec[190]
    DIRECTION OUTPUT ;
    USE SIGNAL ;
    PORT
      LAYER M4 ;
        RECT  0 41.76 0.084 41.784 ;
    END
  END rec[190]
  PIN rec[191]
    DIRECTION OUTPUT ;
    USE SIGNAL ;
    PORT
      LAYER M4 ;
        RECT  0 42.192 0.084 42.216 ;
    END
  END rec[191]
  PIN rec[192]
    DIRECTION OUTPUT ;
    USE SIGNAL ;
    PORT
      LAYER M4 ;
        RECT  0 42.336 0.084 42.36 ;
    END
  END rec[192]
  PIN rec[193]
    DIRECTION OUTPUT ;
    USE SIGNAL ;
    PORT
      LAYER M4 ;
        RECT  0 42.48 0.084 42.504 ;
    END
  END rec[193]
  PIN rec[194]
    DIRECTION OUTPUT ;
    USE SIGNAL ;
    PORT
      LAYER M4 ;
        RECT  0 42.624 0.084 42.648 ;
    END
  END rec[194]
  PIN rec[195]
    DIRECTION OUTPUT ;
    USE SIGNAL ;
    PORT
      LAYER M4 ;
        RECT  0 42.768 0.084 42.792 ;
    END
  END rec[195]
  PIN rec[196]
    DIRECTION OUTPUT ;
    USE SIGNAL ;
    PORT
      LAYER M4 ;
        RECT  0 42.912 0.084 42.936 ;
    END
  END rec[196]
  PIN rec[197]
    DIRECTION OUTPUT ;
    USE SIGNAL ;
    PORT
      LAYER M4 ;
        RECT  0 43.056 0.084 43.08 ;
    END
  END rec[197]
  PIN rec[198]
    DIRECTION OUTPUT ;
    USE SIGNAL ;
    PORT
      LAYER M4 ;
        RECT  0 43.2 0.084 43.224 ;
    END
  END rec[198]
  PIN rec[199]
    DIRECTION OUTPUT ;
    USE SIGNAL ;
    PORT
      LAYER M4 ;
        RECT  0 43.344 0.084 43.368 ;
    END
  END rec[199]
  PIN rec[19]
    DIRECTION OUTPUT ;
    USE SIGNAL ;
    PORT
      LAYER M4 ;
        RECT  0 15.984 0.084 16.008 ;
    END
  END rec[19]
  PIN rec[1]
    DIRECTION OUTPUT ;
    USE SIGNAL ;
    PORT
      LAYER M4 ;
        RECT  0 13.392 0.084 13.416 ;
    END
  END rec[1]
  PIN rec[200]
    DIRECTION OUTPUT ;
    USE SIGNAL ;
    PORT
      LAYER M4 ;
        RECT  0 43.488 0.084 43.512 ;
    END
  END rec[200]
  PIN rec[201]
    DIRECTION OUTPUT ;
    USE SIGNAL ;
    PORT
      LAYER M4 ;
        RECT  0 43.632 0.084 43.656 ;
    END
  END rec[201]
  PIN rec[202]
    DIRECTION OUTPUT ;
    USE SIGNAL ;
    PORT
      LAYER M4 ;
        RECT  0 43.776 0.084 43.8 ;
    END
  END rec[202]
  PIN rec[203]
    DIRECTION OUTPUT ;
    USE SIGNAL ;
    PORT
      LAYER M4 ;
        RECT  0 43.92 0.084 43.944 ;
    END
  END rec[203]
  PIN rec[204]
    DIRECTION OUTPUT ;
    USE SIGNAL ;
    PORT
      LAYER M4 ;
        RECT  0 44.064 0.084 44.088 ;
    END
  END rec[204]
  PIN rec[205]
    DIRECTION OUTPUT ;
    USE SIGNAL ;
    PORT
      LAYER M4 ;
        RECT  0 44.208 0.084 44.232 ;
    END
  END rec[205]
  PIN rec[206]
    DIRECTION OUTPUT ;
    USE SIGNAL ;
    PORT
      LAYER M4 ;
        RECT  0 44.352 0.084 44.376 ;
    END
  END rec[206]
  PIN rec[207]
    DIRECTION OUTPUT ;
    USE SIGNAL ;
    PORT
      LAYER M4 ;
        RECT  0 44.496 0.084 44.52 ;
    END
  END rec[207]
  PIN rec[208]
    DIRECTION OUTPUT ;
    USE SIGNAL ;
    PORT
      LAYER M4 ;
        RECT  0 44.64 0.084 44.664 ;
    END
  END rec[208]
  PIN rec[209]
    DIRECTION OUTPUT ;
    USE SIGNAL ;
    PORT
      LAYER M4 ;
        RECT  0 44.784 0.084 44.808 ;
    END
  END rec[209]
  PIN rec[20]
    DIRECTION OUTPUT ;
    USE SIGNAL ;
    PORT
      LAYER M4 ;
        RECT  0 16.128 0.084 16.152 ;
    END
  END rec[20]
  PIN rec[210]
    DIRECTION OUTPUT ;
    USE SIGNAL ;
    PORT
      LAYER M4 ;
        RECT  0 44.928 0.084 44.952 ;
    END
  END rec[210]
  PIN rec[211]
    DIRECTION OUTPUT ;
    USE SIGNAL ;
    PORT
      LAYER M4 ;
        RECT  0 45.072 0.084 45.096 ;
    END
  END rec[211]
  PIN rec[212]
    DIRECTION OUTPUT ;
    USE SIGNAL ;
    PORT
      LAYER M4 ;
        RECT  0 45.216 0.084 45.24 ;
    END
  END rec[212]
  PIN rec[213]
    DIRECTION OUTPUT ;
    USE SIGNAL ;
    PORT
      LAYER M4 ;
        RECT  0 45.36 0.084 45.384 ;
    END
  END rec[213]
  PIN rec[214]
    DIRECTION OUTPUT ;
    USE SIGNAL ;
    PORT
      LAYER M4 ;
        RECT  0 45.504 0.084 45.528 ;
    END
  END rec[214]
  PIN rec[215]
    DIRECTION OUTPUT ;
    USE SIGNAL ;
    PORT
      LAYER M4 ;
        RECT  0 45.648 0.084 45.672 ;
    END
  END rec[215]
  PIN rec[216]
    DIRECTION OUTPUT ;
    USE SIGNAL ;
    PORT
      LAYER M4 ;
        RECT  0 45.792 0.084 45.816 ;
    END
  END rec[216]
  PIN rec[217]
    DIRECTION OUTPUT ;
    USE SIGNAL ;
    PORT
      LAYER M4 ;
        RECT  0 45.936 0.084 45.96 ;
    END
  END rec[217]
  PIN rec[218]
    DIRECTION OUTPUT ;
    USE SIGNAL ;
    PORT
      LAYER M4 ;
        RECT  0 46.08 0.084 46.104 ;
    END
  END rec[218]
  PIN rec[219]
    DIRECTION OUTPUT ;
    USE SIGNAL ;
    PORT
      LAYER M4 ;
        RECT  0 46.224 0.084 46.248 ;
    END
  END rec[219]
  PIN rec[21]
    DIRECTION OUTPUT ;
    USE SIGNAL ;
    PORT
      LAYER M4 ;
        RECT  0 16.272 0.084 16.296 ;
    END
  END rec[21]
  PIN rec[220]
    DIRECTION OUTPUT ;
    USE SIGNAL ;
    PORT
      LAYER M4 ;
        RECT  0 46.368 0.084 46.392 ;
    END
  END rec[220]
  PIN rec[22]
    DIRECTION OUTPUT ;
    USE SIGNAL ;
    PORT
      LAYER M4 ;
        RECT  0 16.416 0.084 16.44 ;
    END
  END rec[22]
  PIN rec[23]
    DIRECTION OUTPUT ;
    USE SIGNAL ;
    PORT
      LAYER M4 ;
        RECT  0 16.56 0.084 16.584 ;
    END
  END rec[23]
  PIN rec[24]
    DIRECTION OUTPUT ;
    USE SIGNAL ;
    PORT
      LAYER M4 ;
        RECT  0 16.704 0.084 16.728 ;
    END
  END rec[24]
  PIN rec[25]
    DIRECTION OUTPUT ;
    USE SIGNAL ;
    PORT
      LAYER M4 ;
        RECT  0 16.848 0.084 16.872 ;
    END
  END rec[25]
  PIN rec[26]
    DIRECTION OUTPUT ;
    USE SIGNAL ;
    PORT
      LAYER M4 ;
        RECT  0 16.992 0.084 17.016 ;
    END
  END rec[26]
  PIN rec[27]
    DIRECTION OUTPUT ;
    USE SIGNAL ;
    PORT
      LAYER M4 ;
        RECT  0 17.136 0.084 17.16 ;
    END
  END rec[27]
  PIN rec[28]
    DIRECTION OUTPUT ;
    USE SIGNAL ;
    PORT
      LAYER M4 ;
        RECT  0 17.28 0.084 17.304 ;
    END
  END rec[28]
  PIN rec[29]
    DIRECTION OUTPUT ;
    USE SIGNAL ;
    PORT
      LAYER M4 ;
        RECT  0 17.424 0.084 17.448 ;
    END
  END rec[29]
  PIN rec[2]
    DIRECTION OUTPUT ;
    USE SIGNAL ;
    PORT
      LAYER M4 ;
        RECT  0 13.536 0.084 13.56 ;
    END
  END rec[2]
  PIN rec[30]
    DIRECTION OUTPUT ;
    USE SIGNAL ;
    PORT
      LAYER M4 ;
        RECT  0 17.568 0.084 17.592 ;
    END
  END rec[30]
  PIN rec[31]
    DIRECTION OUTPUT ;
    USE SIGNAL ;
    PORT
      LAYER M4 ;
        RECT  0 32.688 0.084 32.712 ;
    END
  END rec[31]
  PIN rec[32]
    DIRECTION OUTPUT ;
    USE SIGNAL ;
    PORT
      LAYER M4 ;
        RECT  0 32.832 0.084 32.856 ;
    END
  END rec[32]
  PIN rec[33]
    DIRECTION OUTPUT ;
    USE SIGNAL ;
    PORT
      LAYER M4 ;
        RECT  0 32.976 0.084 33 ;
    END
  END rec[33]
  PIN rec[34]
    DIRECTION OUTPUT ;
    USE SIGNAL ;
    PORT
      LAYER M4 ;
        RECT  0 33.12 0.084 33.144 ;
    END
  END rec[34]
  PIN rec[35]
    DIRECTION OUTPUT ;
    USE SIGNAL ;
    PORT
      LAYER M4 ;
        RECT  0 33.264 0.084 33.288 ;
    END
  END rec[35]
  PIN rec[36]
    DIRECTION OUTPUT ;
    USE SIGNAL ;
    PORT
      LAYER M4 ;
        RECT  0 33.408 0.084 33.432 ;
    END
  END rec[36]
  PIN rec[37]
    DIRECTION OUTPUT ;
    USE SIGNAL ;
    PORT
      LAYER M4 ;
        RECT  0 33.552 0.084 33.576 ;
    END
  END rec[37]
  PIN rec[38]
    DIRECTION OUTPUT ;
    USE SIGNAL ;
    PORT
      LAYER M4 ;
        RECT  0 33.696 0.084 33.72 ;
    END
  END rec[38]
  PIN rec[39]
    DIRECTION OUTPUT ;
    USE SIGNAL ;
    PORT
      LAYER M4 ;
        RECT  0 33.84 0.084 33.864 ;
    END
  END rec[39]
  PIN rec[3]
    DIRECTION OUTPUT ;
    USE SIGNAL ;
    PORT
      LAYER M4 ;
        RECT  0 13.68 0.084 13.704 ;
    END
  END rec[3]
  PIN rec[40]
    DIRECTION OUTPUT ;
    USE SIGNAL ;
    PORT
      LAYER M4 ;
        RECT  0 33.984 0.084 34.008 ;
    END
  END rec[40]
  PIN rec[41]
    DIRECTION OUTPUT ;
    USE SIGNAL ;
    PORT
      LAYER M4 ;
        RECT  0 34.128 0.084 34.152 ;
    END
  END rec[41]
  PIN rec[42]
    DIRECTION OUTPUT ;
    USE SIGNAL ;
    PORT
      LAYER M4 ;
        RECT  0 34.272 0.084 34.296 ;
    END
  END rec[42]
  PIN rec[43]
    DIRECTION OUTPUT ;
    USE SIGNAL ;
    PORT
      LAYER M4 ;
        RECT  0 34.416 0.084 34.44 ;
    END
  END rec[43]
  PIN rec[44]
    DIRECTION OUTPUT ;
    USE SIGNAL ;
    PORT
      LAYER M4 ;
        RECT  0 34.56 0.084 34.584 ;
    END
  END rec[44]
  PIN rec[45]
    DIRECTION OUTPUT ;
    USE SIGNAL ;
    PORT
      LAYER M4 ;
        RECT  0 34.704 0.084 34.728 ;
    END
  END rec[45]
  PIN rec[46]
    DIRECTION OUTPUT ;
    USE SIGNAL ;
    PORT
      LAYER M4 ;
        RECT  0 34.848 0.084 34.872 ;
    END
  END rec[46]
  PIN rec[47]
    DIRECTION OUTPUT ;
    USE SIGNAL ;
    PORT
      LAYER M4 ;
        RECT  0 34.992 0.084 35.016 ;
    END
  END rec[47]
  PIN rec[48]
    DIRECTION OUTPUT ;
    USE SIGNAL ;
    PORT
      LAYER M4 ;
        RECT  0 35.136 0.084 35.16 ;
    END
  END rec[48]
  PIN rec[49]
    DIRECTION OUTPUT ;
    USE SIGNAL ;
    PORT
      LAYER M4 ;
        RECT  0 35.28 0.084 35.304 ;
    END
  END rec[49]
  PIN rec[4]
    DIRECTION OUTPUT ;
    USE SIGNAL ;
    PORT
      LAYER M4 ;
        RECT  0 13.824 0.084 13.848 ;
    END
  END rec[4]
  PIN rec[50]
    DIRECTION OUTPUT ;
    USE SIGNAL ;
    PORT
      LAYER M4 ;
        RECT  0 35.424 0.084 35.448 ;
    END
  END rec[50]
  PIN rec[51]
    DIRECTION OUTPUT ;
    USE SIGNAL ;
    PORT
      LAYER M4 ;
        RECT  0 35.568 0.084 35.592 ;
    END
  END rec[51]
  PIN rec[52]
    DIRECTION OUTPUT ;
    USE SIGNAL ;
    PORT
      LAYER M4 ;
        RECT  0 35.712 0.084 35.736 ;
    END
  END rec[52]
  PIN rec[53]
    DIRECTION OUTPUT ;
    USE SIGNAL ;
    PORT
      LAYER M4 ;
        RECT  0 35.856 0.084 35.88 ;
    END
  END rec[53]
  PIN rec[54]
    DIRECTION OUTPUT ;
    USE SIGNAL ;
    PORT
      LAYER M4 ;
        RECT  0 36 0.084 36.024 ;
    END
  END rec[54]
  PIN rec[55]
    DIRECTION OUTPUT ;
    USE SIGNAL ;
    PORT
      LAYER M4 ;
        RECT  0 36.144 0.084 36.168 ;
    END
  END rec[55]
  PIN rec[56]
    DIRECTION OUTPUT ;
    USE SIGNAL ;
    PORT
      LAYER M4 ;
        RECT  0 36.288 0.084 36.312 ;
    END
  END rec[56]
  PIN rec[57]
    DIRECTION OUTPUT ;
    USE SIGNAL ;
    PORT
      LAYER M4 ;
        RECT  0 36.432 0.084 36.456 ;
    END
  END rec[57]
  PIN rec[58]
    DIRECTION OUTPUT ;
    USE SIGNAL ;
    PORT
      LAYER M4 ;
        RECT  0 36.576 0.084 36.6 ;
    END
  END rec[58]
  PIN rec[59]
    DIRECTION OUTPUT ;
    USE SIGNAL ;
    PORT
      LAYER M4 ;
        RECT  0 36.72 0.084 36.744 ;
    END
  END rec[59]
  PIN rec[5]
    DIRECTION OUTPUT ;
    USE SIGNAL ;
    PORT
      LAYER M4 ;
        RECT  0 13.968 0.084 13.992 ;
    END
  END rec[5]
  PIN rec[60]
    DIRECTION OUTPUT ;
    USE SIGNAL ;
    PORT
      LAYER M4 ;
        RECT  0 36.864 0.084 36.888 ;
    END
  END rec[60]
  PIN rec[61]
    DIRECTION OUTPUT ;
    USE SIGNAL ;
    PORT
      LAYER M4 ;
        RECT  0 37.008 0.084 37.032 ;
    END
  END rec[61]
  PIN rec[62]
    DIRECTION OUTPUT ;
    USE SIGNAL ;
    PORT
      LAYER M4 ;
        RECT  0 37.152 0.084 37.176 ;
    END
  END rec[62]
  PIN rec[63]
    DIRECTION OUTPUT ;
    USE SIGNAL ;
    PORT
      LAYER M4 ;
        RECT  0 3.888 0.084 3.912 ;
    END
  END rec[63]
  PIN rec[64]
    DIRECTION OUTPUT ;
    USE SIGNAL ;
    PORT
      LAYER M4 ;
        RECT  0 4.032 0.084 4.056 ;
    END
  END rec[64]
  PIN rec[65]
    DIRECTION OUTPUT ;
    USE SIGNAL ;
    PORT
      LAYER M4 ;
        RECT  0 4.176 0.084 4.2 ;
    END
  END rec[65]
  PIN rec[66]
    DIRECTION OUTPUT ;
    USE SIGNAL ;
    PORT
      LAYER M4 ;
        RECT  0 4.32 0.084 4.344 ;
    END
  END rec[66]
  PIN rec[67]
    DIRECTION OUTPUT ;
    USE SIGNAL ;
    PORT
      LAYER M4 ;
        RECT  0 4.464 0.084 4.488 ;
    END
  END rec[67]
  PIN rec[68]
    DIRECTION OUTPUT ;
    USE SIGNAL ;
    PORT
      LAYER M4 ;
        RECT  0 4.608 0.084 4.632 ;
    END
  END rec[68]
  PIN rec[69]
    DIRECTION OUTPUT ;
    USE SIGNAL ;
    PORT
      LAYER M4 ;
        RECT  0 4.752 0.084 4.776 ;
    END
  END rec[69]
  PIN rec[6]
    DIRECTION OUTPUT ;
    USE SIGNAL ;
    PORT
      LAYER M4 ;
        RECT  0 14.112 0.084 14.136 ;
    END
  END rec[6]
  PIN rec[70]
    DIRECTION OUTPUT ;
    USE SIGNAL ;
    PORT
      LAYER M4 ;
        RECT  0 4.896 0.084 4.92 ;
    END
  END rec[70]
  PIN rec[71]
    DIRECTION OUTPUT ;
    USE SIGNAL ;
    PORT
      LAYER M4 ;
        RECT  0 5.04 0.084 5.064 ;
    END
  END rec[71]
  PIN rec[72]
    DIRECTION OUTPUT ;
    USE SIGNAL ;
    PORT
      LAYER M4 ;
        RECT  0 5.184 0.084 5.208 ;
    END
  END rec[72]
  PIN rec[73]
    DIRECTION OUTPUT ;
    USE SIGNAL ;
    PORT
      LAYER M4 ;
        RECT  0 5.328 0.084 5.352 ;
    END
  END rec[73]
  PIN rec[74]
    DIRECTION OUTPUT ;
    USE SIGNAL ;
    PORT
      LAYER M4 ;
        RECT  0 5.472 0.084 5.496 ;
    END
  END rec[74]
  PIN rec[75]
    DIRECTION OUTPUT ;
    USE SIGNAL ;
    PORT
      LAYER M4 ;
        RECT  0 5.616 0.084 5.64 ;
    END
  END rec[75]
  PIN rec[76]
    DIRECTION OUTPUT ;
    USE SIGNAL ;
    PORT
      LAYER M4 ;
        RECT  0 5.76 0.084 5.784 ;
    END
  END rec[76]
  PIN rec[77]
    DIRECTION OUTPUT ;
    USE SIGNAL ;
    PORT
      LAYER M4 ;
        RECT  0 5.904 0.084 5.928 ;
    END
  END rec[77]
  PIN rec[78]
    DIRECTION OUTPUT ;
    USE SIGNAL ;
    PORT
      LAYER M4 ;
        RECT  0 6.048 0.084 6.072 ;
    END
  END rec[78]
  PIN rec[79]
    DIRECTION OUTPUT ;
    USE SIGNAL ;
    PORT
      LAYER M4 ;
        RECT  0 6.192 0.084 6.216 ;
    END
  END rec[79]
  PIN rec[7]
    DIRECTION OUTPUT ;
    USE SIGNAL ;
    PORT
      LAYER M4 ;
        RECT  0 14.256 0.084 14.28 ;
    END
  END rec[7]
  PIN rec[80]
    DIRECTION OUTPUT ;
    USE SIGNAL ;
    PORT
      LAYER M4 ;
        RECT  0 6.336 0.084 6.36 ;
    END
  END rec[80]
  PIN rec[81]
    DIRECTION OUTPUT ;
    USE SIGNAL ;
    PORT
      LAYER M4 ;
        RECT  0 6.48 0.084 6.504 ;
    END
  END rec[81]
  PIN rec[82]
    DIRECTION OUTPUT ;
    USE SIGNAL ;
    PORT
      LAYER M4 ;
        RECT  0 6.624 0.084 6.648 ;
    END
  END rec[82]
  PIN rec[83]
    DIRECTION OUTPUT ;
    USE SIGNAL ;
    PORT
      LAYER M4 ;
        RECT  0 6.768 0.084 6.792 ;
    END
  END rec[83]
  PIN rec[84]
    DIRECTION OUTPUT ;
    USE SIGNAL ;
    PORT
      LAYER M4 ;
        RECT  0 6.912 0.084 6.936 ;
    END
  END rec[84]
  PIN rec[85]
    DIRECTION OUTPUT ;
    USE SIGNAL ;
    PORT
      LAYER M4 ;
        RECT  0 7.056 0.084 7.08 ;
    END
  END rec[85]
  PIN rec[86]
    DIRECTION OUTPUT ;
    USE SIGNAL ;
    PORT
      LAYER M4 ;
        RECT  0 7.2 0.084 7.224 ;
    END
  END rec[86]
  PIN rec[87]
    DIRECTION OUTPUT ;
    USE SIGNAL ;
    PORT
      LAYER M4 ;
        RECT  0 7.344 0.084 7.368 ;
    END
  END rec[87]
  PIN rec[88]
    DIRECTION OUTPUT ;
    USE SIGNAL ;
    PORT
      LAYER M4 ;
        RECT  0 7.488 0.084 7.512 ;
    END
  END rec[88]
  PIN rec[89]
    DIRECTION OUTPUT ;
    USE SIGNAL ;
    PORT
      LAYER M4 ;
        RECT  0 7.632 0.084 7.656 ;
    END
  END rec[89]
  PIN rec[8]
    DIRECTION OUTPUT ;
    USE SIGNAL ;
    PORT
      LAYER M4 ;
        RECT  0 14.4 0.084 14.424 ;
    END
  END rec[8]
  PIN rec[90]
    DIRECTION OUTPUT ;
    USE SIGNAL ;
    PORT
      LAYER M4 ;
        RECT  0 7.776 0.084 7.8 ;
    END
  END rec[90]
  PIN rec[91]
    DIRECTION OUTPUT ;
    USE SIGNAL ;
    PORT
      LAYER M4 ;
        RECT  0 7.92 0.084 7.944 ;
    END
  END rec[91]
  PIN rec[92]
    DIRECTION OUTPUT ;
    USE SIGNAL ;
    PORT
      LAYER M4 ;
        RECT  0 8.064 0.084 8.088 ;
    END
  END rec[92]
  PIN rec[93]
    DIRECTION OUTPUT ;
    USE SIGNAL ;
    PORT
      LAYER M4 ;
        RECT  0 8.208 0.084 8.232 ;
    END
  END rec[93]
  PIN rec[94]
    DIRECTION OUTPUT ;
    USE SIGNAL ;
    PORT
      LAYER M4 ;
        RECT  0 8.352 0.084 8.376 ;
    END
  END rec[94]
  PIN rec[95]
    DIRECTION OUTPUT ;
    USE SIGNAL ;
    PORT
      LAYER M4 ;
        RECT  0 8.496 0.084 8.52 ;
    END
  END rec[95]
  PIN rec[96]
    DIRECTION OUTPUT ;
    USE SIGNAL ;
    PORT
      LAYER M4 ;
        RECT  0 8.64 0.084 8.664 ;
    END
  END rec[96]
  PIN rec[97]
    DIRECTION OUTPUT ;
    USE SIGNAL ;
    PORT
      LAYER M4 ;
        RECT  0 8.784 0.084 8.808 ;
    END
  END rec[97]
  PIN rec[98]
    DIRECTION OUTPUT ;
    USE SIGNAL ;
    PORT
      LAYER M4 ;
        RECT  0 8.928 0.084 8.952 ;
    END
  END rec[98]
  PIN rec[99]
    DIRECTION OUTPUT ;
    USE SIGNAL ;
    PORT
      LAYER M4 ;
        RECT  0 9.072 0.084 9.096 ;
    END
  END rec[99]
  PIN rec[9]
    DIRECTION OUTPUT ;
    USE SIGNAL ;
    PORT
      LAYER M4 ;
        RECT  0 14.544 0.084 14.568 ;
    END
  END rec[9]
  PIN rst_n
    DIRECTION INPUT ;
    USE SIGNAL ;
    PORT
      LAYER M5 ;
        RECT  33.552 0 33.576 0.084 ;
    END
  END rst_n
  PIN start_v
    DIRECTION OUTPUT ;
    USE SIGNAL ;
    PORT
      LAYER M5 ;
        RECT  32.544 51.756 32.568 51.84 ;
    END
  END start_v
  PIN tgt[0]
    DIRECTION INPUT ;
    USE SIGNAL ;
    PORT
      LAYER M5 ;
        RECT  33.696 0 33.72 0.084 ;
    END
  END tgt[0]
  PIN tgt[1]
    DIRECTION INPUT ;
    USE SIGNAL ;
    PORT
      LAYER M5 ;
        RECT  33.84 0 33.864 0.084 ;
    END
  END tgt[1]
  PIN tgt[2]
    DIRECTION INPUT ;
    USE SIGNAL ;
    PORT
      LAYER M5 ;
        RECT  33.984 0 34.008 0.084 ;
    END
  END tgt[2]
  PIN tgt[3]
    DIRECTION INPUT ;
    USE SIGNAL ;
    PORT
      LAYER M5 ;
        RECT  47.952 0 47.976 0.084 ;
    END
  END tgt[3]
  PIN tgt[4]
    DIRECTION INPUT ;
    USE SIGNAL ;
    PORT
      LAYER M5 ;
        RECT  48.096 0 48.12 0.084 ;
    END
  END tgt[4]
  PIN tgt[5]
    DIRECTION INPUT ;
    USE SIGNAL ;
    PORT
      LAYER M5 ;
        RECT  48.24 0 48.264 0.084 ;
    END
  END tgt[5]
  PIN tgt[6]
    DIRECTION INPUT ;
    USE SIGNAL ;
    PORT
      LAYER M5 ;
        RECT  48.384 0 48.408 0.084 ;
    END
  END tgt[6]
  PIN tgt[7]
    DIRECTION INPUT ;
    USE SIGNAL ;
    PORT
      LAYER M5 ;
        RECT  48.528 0 48.552 0.084 ;
    END
  END tgt[7]
  PIN VDD
    DIRECTION INOUT ;
    USE POWER ;
    PORT
      LAYER M5 ;
        RECT  45.792 2.151 45.912 49.689 ;
        RECT  40.392 2.151 40.512 49.689 ;
        RECT  34.992 2.151 35.112 49.689 ;
        RECT  29.592 2.151 29.712 49.689 ;
        RECT  24.192 2.151 24.312 49.689 ;
        RECT  18.792 2.151 18.912 49.689 ;
        RECT  13.392 2.151 13.512 49.689 ;
        RECT  7.992 2.151 8.112 49.689 ;
        RECT  2.592 2.151 2.712 49.689 ;
    END
  END VDD
  PIN VSS
    DIRECTION INOUT ;
    USE GROUND ;
    PORT
      LAYER M5 ;
        RECT  45.6 2.137 45.72 49.703 ;
        RECT  40.2 2.137 40.32 49.703 ;
        RECT  34.8 2.137 34.92 49.703 ;
        RECT  29.4 2.137 29.52 49.703 ;
        RECT  24 2.137 24.12 49.703 ;
        RECT  18.6 2.137 18.72 49.703 ;
        RECT  13.2 2.137 13.32 49.703 ;
        RECT  7.8 2.137 7.92 49.703 ;
        RECT  2.4 2.137 2.52 49.703 ;
    END
  END VSS
  # OT_OBS_CLOSED layer=M5 d_um=1.536 added=184
  OBS
    LAYER RVTN ;
     RECT  2.16 2.16 49.68 2.295 ;
     RECT  2.16 2.565 49.68 2.835 ;
     RECT  2.16 3.105 49.68 3.375 ;
     RECT  2.16 3.645 49.68 3.915 ;
     RECT  2.16 4.185 49.68 4.455 ;
     RECT  2.16 4.725 49.68 4.995 ;
     RECT  2.16 5.265 49.68 5.535 ;
     RECT  2.16 5.805 49.68 6.075 ;
     RECT  2.16 6.345 49.68 6.615 ;
     RECT  2.16 6.885 49.68 7.155 ;
     RECT  2.16 7.425 49.68 7.695 ;
     RECT  2.16 7.965 49.68 8.235 ;
     RECT  2.16 8.505 49.68 8.775 ;
     RECT  2.16 9.045 49.68 9.315 ;
     RECT  2.16 9.585 49.68 9.855 ;
     RECT  2.16 10.125 49.68 10.395 ;
     RECT  2.16 10.665 49.68 10.935 ;
     RECT  2.16 11.205 49.68 11.475 ;
     RECT  2.16 11.745 49.68 12.015 ;
     RECT  2.16 12.285 49.68 12.555 ;
     RECT  2.16 12.825 49.68 13.095 ;
     RECT  2.16 13.365 49.68 13.635 ;
     RECT  2.16 13.905 49.68 14.175 ;
     RECT  2.16 14.445 49.68 14.715 ;
     RECT  2.16 14.985 49.68 15.255 ;
     RECT  2.16 15.525 49.68 15.795 ;
     RECT  2.16 16.065 49.68 16.335 ;
     RECT  2.16 16.605 49.68 16.875 ;
     RECT  2.16 17.145 49.68 17.415 ;
     RECT  2.16 17.685 49.68 17.955 ;
     RECT  2.16 18.225 49.68 18.495 ;
     RECT  2.16 18.765 49.68 19.035 ;
     RECT  2.16 19.305 49.68 19.575 ;
     RECT  2.16 19.845 49.68 20.115 ;
     RECT  2.16 20.385 49.68 20.655 ;
     RECT  2.16 20.925 49.68 21.195 ;
     RECT  2.16 21.465 49.68 21.735 ;
     RECT  2.16 22.005 49.68 22.275 ;
     RECT  2.16 22.545 49.68 22.815 ;
     RECT  2.16 23.085 49.68 23.355 ;
     RECT  2.16 23.625 49.68 23.895 ;
     RECT  2.16 24.165 49.68 24.435 ;
     RECT  2.16 24.705 49.68 24.975 ;
     RECT  2.16 25.245 49.68 25.515 ;
     RECT  2.16 25.785 49.68 26.055 ;
     RECT  2.16 26.325 49.68 26.595 ;
     RECT  2.16 26.865 49.68 27.135 ;
     RECT  2.16 27.405 49.68 27.675 ;
     RECT  2.16 27.945 49.68 28.215 ;
     RECT  2.16 28.485 49.68 28.755 ;
     RECT  2.16 29.025 49.68 29.295 ;
     RECT  2.16 29.565 49.68 29.835 ;
     RECT  2.16 30.105 49.68 30.375 ;
     RECT  2.16 30.645 49.68 30.915 ;
     RECT  2.16 31.185 49.68 31.455 ;
     RECT  2.16 31.725 49.68 31.995 ;
     RECT  2.16 32.265 49.68 32.535 ;
     RECT  2.16 32.805 49.68 33.075 ;
     RECT  2.16 33.345 49.68 33.615 ;
     RECT  2.16 33.885 49.68 34.155 ;
     RECT  2.16 34.425 49.68 34.695 ;
     RECT  2.16 34.965 49.68 35.235 ;
     RECT  2.16 35.505 49.68 35.775 ;
     RECT  2.16 36.045 49.68 36.315 ;
     RECT  2.16 36.585 49.68 36.855 ;
     RECT  2.16 37.125 49.68 37.395 ;
     RECT  2.16 37.665 49.68 37.935 ;
     RECT  2.16 38.205 49.68 38.475 ;
     RECT  2.16 38.745 49.68 39.015 ;
     RECT  2.16 39.285 49.68 39.555 ;
     RECT  2.16 39.825 49.68 40.095 ;
     RECT  2.16 40.365 49.68 40.635 ;
     RECT  2.16 40.905 49.68 41.175 ;
     RECT  2.16 41.445 49.68 41.715 ;
     RECT  2.16 41.985 49.68 42.255 ;
     RECT  2.16 42.525 49.68 42.795 ;
     RECT  2.16 43.065 49.68 43.335 ;
     RECT  2.16 43.605 49.68 43.875 ;
     RECT  2.16 44.145 49.68 44.415 ;
     RECT  2.16 44.685 49.68 44.955 ;
     RECT  2.16 45.225 49.68 45.495 ;
     RECT  2.16 45.765 49.68 46.035 ;
     RECT  2.16 46.305 49.68 46.575 ;
     RECT  2.16 46.845 49.68 47.115 ;
     RECT  2.16 47.385 49.68 47.655 ;
     RECT  2.16 47.925 49.68 48.195 ;
     RECT  2.16 48.465 49.68 48.735 ;
     RECT  2.16 49.005 49.68 49.275 ;
     RECT  2.16 49.545 49.68 49.68 ;
    LAYER RVTP ;
     RECT  2.16 2.295 49.68 2.565 ;
     RECT  2.16 2.835 49.68 3.105 ;
     RECT  2.16 3.375 49.68 3.645 ;
     RECT  2.16 3.915 49.68 4.185 ;
     RECT  2.16 4.455 49.68 4.725 ;
     RECT  2.16 4.995 49.68 5.265 ;
     RECT  2.16 5.535 49.68 5.805 ;
     RECT  2.16 6.075 49.68 6.345 ;
     RECT  2.16 6.615 49.68 6.885 ;
     RECT  2.16 7.155 49.68 7.425 ;
     RECT  2.16 7.695 49.68 7.965 ;
     RECT  2.16 8.235 49.68 8.505 ;
     RECT  2.16 8.775 49.68 9.045 ;
     RECT  2.16 9.315 49.68 9.585 ;
     RECT  2.16 9.855 49.68 10.125 ;
     RECT  2.16 10.395 49.68 10.665 ;
     RECT  2.16 10.935 49.68 11.205 ;
     RECT  2.16 11.475 49.68 11.745 ;
     RECT  2.16 12.015 49.68 12.285 ;
     RECT  2.16 12.555 49.68 12.825 ;
     RECT  2.16 13.095 49.68 13.365 ;
     RECT  2.16 13.635 49.68 13.905 ;
     RECT  2.16 14.175 49.68 14.445 ;
     RECT  2.16 14.715 49.68 14.985 ;
     RECT  2.16 15.255 49.68 15.525 ;
     RECT  2.16 15.795 49.68 16.065 ;
     RECT  2.16 16.335 49.68 16.605 ;
     RECT  2.16 16.875 49.68 17.145 ;
     RECT  2.16 17.415 49.68 17.685 ;
     RECT  2.16 17.955 49.68 18.225 ;
     RECT  2.16 18.495 49.68 18.765 ;
     RECT  2.16 19.035 49.68 19.305 ;
     RECT  2.16 19.575 49.68 19.845 ;
     RECT  2.16 20.115 49.68 20.385 ;
     RECT  2.16 20.655 49.68 20.925 ;
     RECT  2.16 21.195 49.68 21.465 ;
     RECT  2.16 21.735 49.68 22.005 ;
     RECT  2.16 22.275 49.68 22.545 ;
     RECT  2.16 22.815 49.68 23.085 ;
     RECT  2.16 23.355 49.68 23.625 ;
     RECT  2.16 23.895 49.68 24.165 ;
     RECT  2.16 24.435 49.68 24.705 ;
     RECT  2.16 24.975 49.68 25.245 ;
     RECT  2.16 25.515 49.68 25.785 ;
     RECT  2.16 26.055 49.68 26.325 ;
     RECT  2.16 26.595 49.68 26.865 ;
     RECT  2.16 27.135 49.68 27.405 ;
     RECT  2.16 27.675 49.68 27.945 ;
     RECT  2.16 28.215 49.68 28.485 ;
     RECT  2.16 28.755 49.68 29.025 ;
     RECT  2.16 29.295 49.68 29.565 ;
     RECT  2.16 29.835 49.68 30.105 ;
     RECT  2.16 30.375 49.68 30.645 ;
     RECT  2.16 30.915 49.68 31.185 ;
     RECT  2.16 31.455 49.68 31.725 ;
     RECT  2.16 31.995 49.68 32.265 ;
     RECT  2.16 32.535 49.68 32.805 ;
     RECT  2.16 33.075 49.68 33.345 ;
     RECT  2.16 33.615 49.68 33.885 ;
     RECT  2.16 34.155 49.68 34.425 ;
     RECT  2.16 34.695 49.68 34.965 ;
     RECT  2.16 35.235 49.68 35.505 ;
     RECT  2.16 35.775 49.68 36.045 ;
     RECT  2.16 36.315 49.68 36.585 ;
     RECT  2.16 36.855 49.68 37.125 ;
     RECT  2.16 37.395 49.68 37.665 ;
     RECT  2.16 37.935 49.68 38.205 ;
     RECT  2.16 38.475 49.68 38.745 ;
     RECT  2.16 39.015 49.68 39.285 ;
     RECT  2.16 39.555 49.68 39.825 ;
     RECT  2.16 40.095 49.68 40.365 ;
     RECT  2.16 40.635 49.68 40.905 ;
     RECT  2.16 41.175 49.68 41.445 ;
     RECT  2.16 41.715 49.68 41.985 ;
     RECT  2.16 42.255 49.68 42.525 ;
     RECT  2.16 42.795 49.68 43.065 ;
     RECT  2.16 43.335 49.68 43.605 ;
     RECT  2.16 43.875 49.68 44.145 ;
     RECT  2.16 44.415 49.68 44.685 ;
     RECT  2.16 44.955 49.68 45.225 ;
     RECT  2.16 45.495 49.68 45.765 ;
     RECT  2.16 46.035 49.68 46.305 ;
     RECT  2.16 46.575 49.68 46.845 ;
     RECT  2.16 47.115 49.68 47.385 ;
     RECT  2.16 47.655 49.68 47.925 ;
     RECT  2.16 48.195 49.68 48.465 ;
     RECT  2.16 48.735 49.68 49.005 ;
     RECT  2.16 49.275 49.68 49.545 ;
    LAYER M1 ;
     RECT  2.16 2.151 49.68 49.689 ;
    LAYER M2 ;
     RECT  0.103 31.662 0.139 31.68 ;
     RECT  0.103 32.436 0.139 33.534 ;
     RECT  0.103 29.034 0.535 29.52 ;
     RECT  0.103 42.156 0.535 44.334 ;
     RECT  0.103 3.96 2.16 3.978 ;
     RECT  0.103 6.822 2.16 8.532 ;
     RECT  0.103 9.522 2.16 9.54 ;
     RECT  0.103 11.376 2.16 14.238 ;
     RECT  0.103 15.84 2.16 17.1 ;
     RECT  0.535 28.296 2.16 29.52 ;
     RECT  0.139 31.662 2.16 33.534 ;
     RECT  0.103 37.602 2.16 37.854 ;
     RECT  0.103 39.222 2.16 40.464 ;
     RECT  0.535 42.066 2.16 44.334 ;
     RECT  2.16 2.151 8.095 49.689 ;
     RECT  8.095 2.106 8.411 49.689 ;
     RECT  8.995 50.706 9.095 50.724 ;
     RECT  8.411 2.151 13.963 49.689 ;
     RECT  13.963 2.106 14.711 49.689 ;
     RECT  14.711 2.151 19.039 49.689 ;
     RECT  19.039 2.106 19.463 49.689 ;
     RECT  19.463 2.151 22.135 49.689 ;
     RECT  22.135 2.106 22.631 49.689 ;
     RECT  23.791 50.706 23.891 50.724 ;
     RECT  22.631 2.151 27.643 49.689 ;
     RECT  27.643 2.106 28.499 49.689 ;
     RECT  28.499 2.151 49.68 49.689 ;
     RECT  49.68 29.466 49.883 33.984 ;
     RECT  49.68 5.436 50.171 28.404 ;
     RECT  49.883 29.466 50.171 33.804 ;
     RECT  49.68 38.718 50.171 47.844 ;
     RECT  50.171 7.866 50.207 24.354 ;
     RECT  50.171 29.736 50.207 33.804 ;
     RECT  50.171 38.718 50.207 47.754 ;
     RECT  50.207 17.73 50.243 22.644 ;
     RECT  50.171 5.544 50.711 7.074 ;
     RECT  50.207 7.866 50.711 16.794 ;
     RECT  50.243 18.126 50.711 22.464 ;
     RECT  50.207 23.526 50.711 24.354 ;
     RECT  50.171 25.416 50.711 28.134 ;
     RECT  50.207 29.736 50.711 32.904 ;
     RECT  50.207 33.786 50.711 33.804 ;
     RECT  50.207 38.718 50.711 42.984 ;
     RECT  50.207 43.848 50.711 47.754 ;
     RECT  50.711 8.01 50.747 8.604 ;
     RECT  50.711 12.06 50.747 12.078 ;
     RECT  50.711 13.41 50.747 13.734 ;
     RECT  50.711 14.49 50.747 15.282 ;
     RECT  50.711 16.038 50.747 16.524 ;
     RECT  50.711 18.936 50.747 19.638 ;
     RECT  50.711 20.628 50.747 21.528 ;
     RECT  50.711 22.356 50.747 22.374 ;
     RECT  50.711 26.226 50.747 27.234 ;
     RECT  50.711 31.77 50.747 31.788 ;
     RECT  50.711 38.718 50.747 41.004 ;
     RECT  50.711 41.994 50.747 42.984 ;
     RECT  50.711 44.316 50.747 45.594 ;
     RECT  50.711 46.656 50.747 47.304 ;
     RECT  50.747 8.442 50.783 8.46 ;
     RECT  50.747 14.49 50.783 15.084 ;
     RECT  50.747 39.996 50.783 40.392 ;
     RECT  50.747 42.534 50.783 42.75 ;
     RECT  50.783 39.996 51.719 40.284 ;
     RECT  50.711 5.544 51.755 5.904 ;
     RECT  50.711 9.936 51.755 11.034 ;
     RECT  50.747 13.41 51.755 13.428 ;
     RECT  50.783 14.49 51.755 14.508 ;
     RECT  50.747 16.074 51.755 16.092 ;
     RECT  50.747 19.62 51.755 19.638 ;
     RECT  50.747 21.096 51.755 21.528 ;
     RECT  50.747 26.226 51.755 26.784 ;
     RECT  50.711 32.886 51.755 32.904 ;
     RECT  50.747 38.718 51.755 38.736 ;
     RECT  51.719 39.996 51.755 40.014 ;
     RECT  50.783 42.732 51.755 42.75 ;
    LAYER M3 ;
     RECT  42.156 0.091 42.174 0.571 ;
     RECT  33.516 0.091 33.534 1.099 ;
     RECT  14.688 0.571 14.706 1.723 ;
     RECT  19.44 0.571 19.458 1.723 ;
     RECT  22.608 0.571 22.626 1.723 ;
     RECT  32.508 0.571 32.526 1.723 ;
     RECT  33.408 1.099 33.534 1.723 ;
     RECT  42.156 0.571 42.822 1.723 ;
     RECT  43.668 0.091 43.686 1.723 ;
     RECT  5.364 1.723 28.242 1.819 ;
     RECT  5.364 1.819 28.386 2.101 ;
     RECT  29.556 1.723 48.582 2.143 ;
     RECT  5.364 2.101 28.494 2.263 ;
     RECT  29.415 2.143 48.582 2.263 ;
     RECT  2.415 2.143 2.505 2.413 ;
     RECT  5.364 2.263 48.798 2.641 ;
     RECT  5.364 2.641 48.906 2.795 ;
     RECT  5.436 2.795 48.906 3.029 ;
     RECT  49.428 3.307 49.446 3.389 ;
     RECT  5.436 3.029 48.618 3.749 ;
     RECT  5.508 3.749 48.618 3.847 ;
     RECT  5.508 3.847 48.906 3.875 ;
     RECT  0.108 3.955 0.126 4.061 ;
     RECT  5.544 3.875 48.906 4.145 ;
     RECT  2.415 2.413 2.697 4.315 ;
     RECT  5.868 4.145 48.906 4.649 ;
     RECT  2.304 4.315 2.697 4.747 ;
     RECT  6.372 4.649 48.906 4.765 ;
     RECT  2.304 4.747 2.718 4.829 ;
     RECT  6.372 4.765 49.338 5.225 ;
     RECT  50.148 5.323 50.166 5.459 ;
     RECT  6.804 5.225 49.338 5.611 ;
     RECT  6.804 5.611 49.626 5.789 ;
     RECT  51.732 5.467 51.75 5.909 ;
     RECT  6.804 5.789 49.41 6.077 ;
     RECT  50.688 5.809 50.742 6.187 ;
     RECT  50.148 6.187 50.742 6.269 ;
     RECT  50.688 6.269 50.742 6.365 ;
     RECT  6.804 6.077 49.338 6.907 ;
     RECT  50.688 6.365 50.706 7.088 ;
     RECT  6.804 6.907 49.626 7.195 ;
     RECT  6.804 7.195 50.166 7.385 ;
     RECT  7.488 7.385 50.166 7.517 ;
     RECT  2.304 4.829 2.697 7.805 ;
     RECT  50.148 7.517 50.166 7.808 ;
     RECT  50.688 7.861 50.706 8.005 ;
     RECT  7.488 7.517 49.05 8.347 ;
     RECT  50.688 8.005 50.742 8.437 ;
     RECT  7.488 8.347 49.806 8.537 ;
     RECT  0.108 6.817 0.126 8.669 ;
     RECT  2.34 7.805 2.697 9.211 ;
     RECT  50.688 8.437 50.778 9.245 ;
     RECT  49.788 8.537 49.806 9.781 ;
     RECT  50.688 9.245 50.706 9.781 ;
     RECT  0.108 9.517 0.126 9.821 ;
     RECT  49.788 9.781 50.706 10.075 ;
     RECT  7.488 8.537 48.906 10.121 ;
     RECT  49.716 10.075 50.706 10.229 ;
     RECT  7.632 10.121 48.906 10.355 ;
     RECT  50.148 10.229 50.706 10.589 ;
     RECT  50.688 10.589 50.706 10.795 ;
     RECT  7.815 10.355 48.906 10.891 ;
     RECT  50.688 10.795 50.742 10.967 ;
     RECT  51.732 9.643 51.75 11.039 ;
     RECT  7.815 10.891 48.978 11.209 ;
     RECT  7.815 11.209 49.59 11.261 ;
     RECT  2.304 9.211 2.697 11.371 ;
     RECT  50.688 10.967 50.706 11.371 ;
     RECT  2.232 11.371 2.697 11.471 ;
     RECT  49.788 11.371 50.706 11.849 ;
     RECT  50.148 11.849 50.706 11.981 ;
     RECT  50.184 11.981 50.706 12.055 ;
     RECT  7.815 11.261 48.906 12.091 ;
     RECT  7.815 12.091 49.014 12.119 ;
     RECT  50.184 12.055 50.742 12.125 ;
     RECT  8.928 12.119 49.014 12.181 ;
     RECT  8.928 12.181 49.122 12.515 ;
     RECT  0.108 11.371 0.126 12.523 ;
     RECT  50.184 12.125 50.706 12.557 ;
     RECT  9 12.515 49.122 12.587 ;
     RECT  9 12.587 48.834 12.821 ;
     RECT  49.608 12.901 49.626 13.133 ;
     RECT  0.108 12.523 0.162 13.277 ;
     RECT  50.688 12.557 50.706 13.387 ;
     RECT  51.732 12.667 51.75 13.433 ;
     RECT  9.072 12.821 48.834 13.531 ;
     RECT  9.072 13.531 49.158 13.631 ;
     RECT  50.652 13.387 50.706 13.711 ;
     RECT  50.652 13.711 50.742 13.801 ;
     RECT  50.184 13.801 50.742 13.853 ;
     RECT  50.184 13.853 50.706 13.963 ;
     RECT  9.072 13.631 48.834 14.141 ;
     RECT  0.108 13.277 0.126 14.285 ;
     RECT  50.148 13.963 50.706 14.285 ;
     RECT  50.148 14.285 50.166 14.449 ;
     RECT  51.732 14.395 51.75 14.513 ;
     RECT  49.608 14.449 50.166 14.639 ;
     RECT  49.608 14.639 49.626 14.683 ;
     RECT  9.072 14.141 29.79 14.953 ;
     RECT  9.072 14.953 29.862 15.053 ;
     RECT  30.636 14.141 48.834 15.403 ;
     RECT  49.572 14.683 49.626 15.403 ;
     RECT  30.636 15.403 49.626 15.529 ;
     RECT  50.688 15.061 50.778 15.529 ;
     RECT  9.072 15.053 29.79 15.593 ;
     RECT  30.636 15.529 50.778 15.629 ;
     RECT  51.732 15.835 51.75 16.097 ;
     RECT  49.608 15.629 50.778 16.157 ;
     RECT  2.304 11.471 2.697 16.231 ;
     RECT  2.304 16.231 2.718 16.301 ;
     RECT  49.608 16.157 50.742 16.301 ;
     RECT  30.636 15.629 48.834 16.411 ;
     RECT  30.564 16.411 48.834 16.541 ;
     RECT  50.688 16.301 50.742 16.589 ;
     RECT  50.688 16.589 50.706 16.877 ;
     RECT  49.608 16.301 49.662 16.915 ;
     RECT  30.636 16.541 48.834 17.083 ;
     RECT  49.572 16.915 49.662 17.083 ;
     RECT  9.072 15.593 29.754 17.149 ;
     RECT  0.108 15.835 0.126 17.165 ;
     RECT  8.964 17.149 29.754 17.221 ;
     RECT  30.636 17.083 49.662 17.221 ;
     RECT  30.636 17.221 50.202 17.309 ;
     RECT  2.304 16.301 2.697 17.419 ;
     RECT  2.304 17.419 2.754 17.483 ;
     RECT  7.815 12.119 8.097 17.491 ;
     RECT  8.892 17.221 29.754 17.491 ;
     RECT  49.68 17.309 50.202 17.519 ;
     RECT  2.304 17.483 2.697 17.645 ;
     RECT  50.148 17.519 50.202 17.725 ;
     RECT  50.148 17.725 50.238 18.121 ;
     RECT  50.148 18.121 50.706 18.461 ;
     RECT  7.815 17.491 29.754 18.599 ;
     RECT  8.964 18.599 29.754 18.797 ;
     RECT  9.072 18.797 29.754 18.805 ;
     RECT  30.636 17.309 48.834 18.805 ;
     RECT  50.688 18.461 50.706 18.931 ;
     RECT  50.688 18.931 50.742 19.037 ;
     RECT  9.072 18.805 48.834 19.111 ;
     RECT  49.608 18.565 49.626 19.111 ;
     RECT  9.072 19.111 49.626 19.273 ;
     RECT  50.688 19.037 50.706 19.273 ;
     RECT  9.072 19.273 50.706 19.643 ;
     RECT  51.732 19.579 51.75 19.643 ;
     RECT  9.072 19.643 48.762 19.741 ;
     RECT  8.964 19.741 48.762 19.877 ;
     RECT  8.964 19.877 43.614 19.921 ;
     RECT  49.608 19.643 50.706 20.045 ;
     RECT  7.815 18.599 8.097 20.155 ;
     RECT  8.82 19.921 43.614 20.155 ;
     RECT  7.815 20.155 43.614 20.453 ;
     RECT  23.832 20.453 43.614 20.579 ;
     RECT  50.112 20.045 50.706 20.623 ;
     RECT  50.112 20.623 50.742 20.651 ;
     RECT  50.148 20.651 50.742 20.909 ;
     RECT  23.904 20.579 43.614 21.001 ;
     RECT  44.388 19.877 48.762 21.001 ;
     RECT  23.904 21.001 48.762 21.163 ;
     RECT  7.815 20.453 22.914 21.235 ;
     RECT  23.904 21.163 49.338 21.389 ;
     RECT  51.732 21.019 51.75 21.533 ;
     RECT  7.2 21.235 22.914 21.643 ;
     RECT  23.904 21.389 49.158 21.643 ;
     RECT  50.184 20.909 50.742 22.171 ;
     RECT  7.2 21.643 49.158 22.441 ;
     RECT  50.148 22.171 50.742 22.493 ;
     RECT  7.2 22.441 49.302 22.775 ;
     RECT  50.148 22.493 50.238 23.279 ;
     RECT  7.2 22.775 48.798 23.656 ;
     RECT  7.2 23.656 48.834 23.755 ;
     RECT  7.2 23.755 49.014 23.791 ;
     RECT  49.752 23.323 49.77 23.791 ;
     RECT  7.2 23.791 49.77 24.187 ;
     RECT  50.688 23.467 50.706 24.187 ;
     RECT  7.2 24.187 50.706 24.368 ;
     RECT  7.2 24.368 50.166 24.665 ;
     RECT  7.2 24.665 22.986 24.809 ;
     RECT  24.015 24.665 50.166 25.339 ;
     RECT  7.2 24.809 22.914 25.349 ;
     RECT  24.015 25.339 50.706 25.709 ;
     RECT  24.015 25.709 50.166 25.889 ;
     RECT  24.015 25.889 24.462 25.951 ;
     RECT  23.904 25.951 24.462 25.997 ;
     RECT  7.2 25.349 22.878 26.329 ;
     RECT  6.876 26.329 22.878 26.401 ;
     RECT  25.488 25.889 50.166 26.429 ;
     RECT  50.148 26.429 50.166 26.485 ;
     RECT  5.76 26.527 5.778 26.671 ;
     RECT  51.732 26.059 51.75 26.813 ;
     RECT  5.4 26.671 5.778 26.869 ;
     RECT  24.015 25.997 24.462 26.897 ;
     RECT  25.488 26.429 49.194 27.131 ;
     RECT  6.804 26.401 22.878 27.139 ;
     RECT  5.04 26.869 5.778 27.175 ;
     RECT  6.552 27.139 22.878 27.175 ;
     RECT  5.04 27.175 22.878 27.301 ;
     RECT  25.488 27.131 49.122 27.329 ;
     RECT  50.148 26.485 50.742 27.389 ;
     RECT  25.488 27.329 48.87 27.409 ;
     RECT  50.148 27.389 50.706 27.499 ;
     RECT  25.092 27.409 48.87 27.509 ;
     RECT  3.924 27.337 3.942 27.841 ;
     RECT  4.788 27.301 22.878 27.841 ;
     RECT  2.415 17.645 2.697 28.075 ;
     RECT  49.86 27.499 50.706 28.075 ;
     RECT  49.824 28.075 50.706 28.139 ;
     RECT  49.824 28.139 50.166 28.409 ;
     RECT  25.488 27.509 48.87 28.445 ;
     RECT  0.54 28.291 0.558 28.541 ;
     RECT  2.304 28.075 2.697 29.405 ;
     RECT  49.608 28.723 49.626 29.461 ;
     RECT  49.608 29.461 50.166 29.549 ;
     RECT  0.108 29.029 0.126 29.693 ;
     RECT  25.488 28.445 48.834 29.767 ;
     RECT  49.608 29.549 49.662 29.767 ;
     RECT  25.488 29.767 49.662 29.939 ;
     RECT  49.644 29.939 49.662 29.981 ;
     RECT  2.34 29.405 2.697 30.235 ;
     RECT  49.86 30.379 49.878 30.667 ;
     RECT  50.688 29.731 50.706 30.667 ;
     RECT  49.86 30.667 50.706 30.713 ;
     RECT  25.488 29.939 48.798 30.847 ;
     RECT  25.488 30.847 49.338 31.675 ;
     RECT  50.112 30.713 50.706 31.675 ;
     RECT  25.488 31.675 50.706 31.765 ;
     RECT  25.488 31.765 50.742 31.829 ;
     RECT  0.108 31.657 0.126 31.891 ;
     RECT  25.488 31.829 49.41 31.919 ;
     RECT  0.108 31.891 0.162 32.141 ;
     RECT  50.184 31.829 50.742 32.141 ;
     RECT  50.184 32.141 50.706 32.459 ;
     RECT  25.488 31.919 49.194 32.495 ;
     RECT  50.184 32.459 50.202 32.573 ;
     RECT  51.732 32.827 51.75 32.909 ;
     RECT  2.304 30.235 2.697 32.971 ;
     RECT  0.108 32.141 0.126 33.007 ;
     RECT  2.304 32.971 2.718 33.008 ;
     RECT  2.34 33.008 2.718 33.071 ;
     RECT  25.488 32.495 48.798 33.259 ;
     RECT  50.148 32.683 50.166 33.403 ;
     RECT  0.108 33.007 0.162 33.437 ;
     RECT  25.488 33.259 49.41 33.449 ;
     RECT  50.148 33.403 50.202 33.611 ;
     RECT  0.108 33.437 0.126 33.725 ;
     RECT  50.688 33.691 50.706 33.809 ;
     RECT  2.34 33.071 2.697 33.961 ;
     RECT  49.86 33.835 49.878 33.989 ;
     RECT  25.488 33.449 49.122 34.013 ;
     RECT  25.488 34.013 48.798 34.115 ;
     RECT  25.488 34.115 47.214 34.619 ;
     RECT  25.488 34.619 47.07 34.655 ;
     RECT  25.488 34.655 46.746 34.763 ;
     RECT  43.956 34.763 46.746 35.429 ;
     RECT  43.956 35.429 46.386 35.699 ;
     RECT  43.956 35.699 46.242 35.735 ;
     RECT  25.488 34.763 43.146 35.815 ;
     RECT  43.956 35.735 46.134 35.815 ;
     RECT  48.06 34.115 48.798 37.085 ;
     RECT  25.488 35.815 46.134 37.129 ;
     RECT  47.16 37.051 47.178 37.471 ;
     RECT  47.088 37.471 47.286 37.627 ;
     RECT  25.488 37.129 46.242 37.633 ;
     RECT  47.088 37.627 47.322 37.633 ;
     RECT  25.488 37.633 47.322 37.939 ;
     RECT  48.06 37.085 48.69 37.939 ;
     RECT  2.304 33.961 2.697 38.045 ;
     RECT  0.108 37.597 0.126 38.333 ;
     RECT  25.488 37.939 48.69 38.371 ;
     RECT  25.488 38.371 48.906 38.749 ;
     RECT  49.644 38.551 49.662 38.749 ;
     RECT  2.34 38.045 2.697 38.875 ;
     RECT  25.488 38.749 49.662 39.253 ;
     RECT  50.724 39.181 50.742 39.253 ;
     RECT  25.488 39.253 50.742 39.281 ;
     RECT  50.148 39.281 50.742 39.341 ;
     RECT  2.304 38.875 2.697 39.551 ;
     RECT  51.732 38.713 51.75 39.739 ;
     RECT  51.696 39.739 51.75 40.019 ;
     RECT  25.488 39.281 49.374 40.205 ;
     RECT  51.696 40.019 51.714 40.289 ;
     RECT  50.724 39.341 50.742 40.369 ;
     RECT  49.716 40.315 49.734 40.469 ;
     RECT  0.108 39.217 0.126 40.493 ;
     RECT  50.724 40.369 50.778 40.637 ;
     RECT  50.724 40.637 50.742 40.711 ;
     RECT  50.148 40.711 50.742 40.781 ;
     RECT  25.488 40.205 48.69 40.925 ;
     RECT  25.488 40.925 35.622 40.937 ;
     RECT  36.648 40.925 48.69 40.945 ;
     RECT  2.34 39.551 2.697 41.035 ;
     RECT  50.184 40.781 50.742 41.069 ;
     RECT  25.488 40.937 35.334 41.071 ;
     RECT  36.648 40.945 49.05 41.099 ;
     RECT  36.648 41.099 48.906 41.135 ;
     RECT  25.2 41.071 35.334 41.369 ;
     RECT  25.488 41.369 35.334 41.683 ;
     RECT  2.304 41.035 2.697 41.711 ;
     RECT  2.34 41.711 2.697 41.755 ;
     RECT  50.184 41.069 50.706 41.755 ;
     RECT  2.34 41.755 2.79 41.792 ;
     RECT  36.72 41.135 48.906 41.917 ;
     RECT  50.148 41.755 50.706 41.917 ;
     RECT  36.72 41.917 50.706 41.989 ;
     RECT  0.54 42.061 0.558 42.151 ;
     RECT  25.488 41.683 35.478 42.187 ;
     RECT  36.72 41.989 50.742 42.187 ;
     RECT  25.488 42.187 35.658 42.223 ;
     RECT  25.488 42.223 35.694 42.235 ;
     RECT  36.684 42.187 50.742 42.235 ;
     RECT  25.488 42.235 50.742 42.365 ;
     RECT  0.108 42.151 0.558 42.509 ;
     RECT  50.184 42.365 50.742 42.529 ;
     RECT  2.34 41.792 2.697 42.601 ;
     RECT  25.488 42.365 49.338 42.601 ;
     RECT  25.092 42.601 49.338 42.755 ;
     RECT  51.732 42.727 51.75 42.797 ;
     RECT  50.184 42.529 50.778 42.941 ;
     RECT  3.924 27.841 22.878 42.961 ;
     RECT  24.015 26.897 24.297 42.961 ;
     RECT  50.184 42.941 50.742 43.229 ;
     RECT  50.184 43.229 50.706 43.231 ;
     RECT  3.924 42.961 24.297 43.537 ;
     RECT  25.092 42.755 48.654 43.537 ;
     RECT  50.148 43.231 50.706 43.627 ;
     RECT  49.68 43.627 50.706 43.709 ;
     RECT  2.304 42.601 2.697 43.771 ;
     RECT  0.108 42.509 0.126 43.807 ;
     RECT  2.304 43.771 2.718 43.871 ;
     RECT  0.108 43.807 0.162 44.093 ;
     RECT  3.924 43.537 48.654 44.113 ;
     RECT  3.924 44.113 48.942 44.249 ;
     RECT  50.148 43.709 50.706 44.311 ;
     RECT  49.392 44.311 49.41 44.411 ;
     RECT  3.924 44.249 48.654 44.519 ;
     RECT  0.108 44.093 0.126 44.525 ;
     RECT  50.148 44.311 50.742 44.779 ;
     RECT  49.752 44.779 50.742 45.301 ;
     RECT  3.924 44.519 48.582 45.391 ;
     RECT  49.608 45.301 50.742 45.391 ;
     RECT  3.924 45.391 50.742 45.491 ;
     RECT  49.608 45.491 50.742 45.533 ;
     RECT  49.68 45.533 50.742 45.677 ;
     RECT  49.68 45.677 50.706 45.869 ;
     RECT  3.924 45.491 48.69 46.067 ;
     RECT  49.752 45.869 50.706 46.541 ;
     RECT  2.304 43.871 2.697 46.571 ;
     RECT  50.688 46.541 50.706 46.651 ;
     RECT  3.924 46.067 48.654 46.679 ;
     RECT  3.924 46.679 48.618 46.813 ;
     RECT  49.68 47.083 49.698 47.155 ;
     RECT  49.644 47.155 49.698 47.261 ;
     RECT  50.688 46.651 50.742 47.405 ;
     RECT  50.688 47.405 50.706 47.515 ;
     RECT  3.816 46.813 48.618 47.723 ;
     RECT  2.415 46.571 2.697 47.731 ;
     RECT  3.816 47.723 48.222 47.731 ;
     RECT  2.415 47.731 48.222 47.789 ;
     RECT  50.148 47.515 50.706 47.837 ;
     RECT  50.148 47.837 50.166 47.849 ;
     RECT  2.415 47.789 2.862 48.119 ;
     RECT  3.6 47.789 48.222 48.541 ;
     RECT  48.996 48.271 49.014 48.541 ;
     RECT  3.6 48.541 49.086 48.659 ;
     RECT  3.6 48.659 48.474 48.695 ;
     RECT  3.6 48.695 47.826 49.001 ;
     RECT  2.415 48.119 2.697 49.003 ;
     RECT  3.6 49.001 47.79 49.003 ;
     RECT  2.415 49.003 47.79 49.199 ;
     RECT  2.415 49.199 2.97 49.235 ;
     RECT  2.415 49.235 2.697 49.427 ;
     RECT  3.708 49.199 47.79 49.469 ;
     RECT  3.708 49.469 47.682 49.505 ;
     RECT  3.924 49.505 21.618 49.517 ;
     RECT  23.364 49.505 47.538 49.517 ;
     RECT  3.924 49.517 19.638 49.565 ;
     RECT  20.376 49.517 21.618 49.565 ;
     RECT  23.364 49.517 47.034 49.565 ;
     RECT  7.056 49.565 19.638 49.577 ;
     RECT  42.3 49.565 47.034 49.577 ;
     RECT  7.056 49.577 17.514 49.613 ;
     RECT  20.376 49.565 20.394 49.613 ;
     RECT  2.415 49.427 2.505 49.697 ;
     RECT  23.724 49.565 41.418 49.697 ;
     RECT  42.3 49.577 46.17 49.697 ;
     RECT  18.504 49.577 19.638 49.805 ;
     RECT  18.504 49.805 18.594 49.853 ;
     RECT  7.2 49.613 17.262 50.141 ;
     RECT  23.724 49.697 34.326 50.141 ;
     RECT  35.136 49.697 41.418 50.141 ;
     RECT  3.924 49.565 6.174 50.189 ;
     RECT  7.2 50.141 16.182 50.189 ;
     RECT  16.992 50.141 17.262 50.189 ;
     RECT  19.62 49.805 19.638 50.189 ;
     RECT  23.724 50.141 25.326 50.189 ;
     RECT  26.064 50.141 30.978 50.189 ;
     RECT  35.136 50.141 35.586 50.189 ;
     RECT  36.432 50.141 41.418 50.189 ;
     RECT  42.3 49.697 45.018 50.189 ;
     RECT  46.152 49.697 46.17 50.189 ;
     RECT  27.072 50.189 30.978 50.237 ;
     RECT  40.356 50.189 41.31 50.237 ;
     RECT  29.844 50.237 30.978 50.621 ;
     RECT  5.796 50.189 5.814 50.717 ;
     RECT  8.856 50.189 16.182 50.717 ;
     RECT  18.504 49.853 18.522 50.717 ;
     RECT  23.796 50.189 25.326 50.717 ;
     RECT  26.064 50.189 26.082 50.717 ;
     RECT  27.072 50.237 29.07 50.717 ;
     RECT  29.844 50.621 30.942 50.717 ;
     RECT  31.896 50.141 33.822 50.717 ;
     RECT  35.568 50.189 35.586 50.717 ;
     RECT  36.756 50.189 36.882 50.717 ;
     RECT  37.836 50.189 38.466 50.717 ;
     RECT  42.3 50.189 42.39 50.717 ;
     RECT  43.308 50.189 43.326 50.717 ;
     RECT  44.064 50.189 45.018 50.717 ;
     RECT  8.856 50.717 9.09 50.729 ;
     RECT  4.14 50.189 4.986 50.765 ;
     RECT  7.2 50.189 7.218 50.765 ;
     RECT  9.972 50.717 10.602 50.765 ;
     RECT  12.06 50.717 12.69 50.765 ;
     RECT  13.716 50.717 14.418 50.765 ;
     RECT  15.264 50.717 15.282 50.765 ;
     RECT  23.796 50.717 25.218 50.765 ;
     RECT  29.052 50.717 29.07 50.765 ;
     RECT  29.844 50.717 30.042 50.765 ;
     RECT  33.804 50.717 33.822 50.765 ;
     RECT  37.836 50.717 37.854 50.765 ;
     RECT  39.528 50.189 39.546 50.765 ;
     RECT  42.372 50.717 42.39 50.765 ;
     RECT  9.972 50.765 9.99 50.813 ;
     RECT  14.4 50.765 14.418 50.813 ;
     RECT  16.128 50.717 16.146 50.813 ;
     RECT  12.06 50.765 12.078 50.861 ;
     RECT  8.856 50.729 9.018 51.677 ;
     RECT  23.796 50.765 25.038 51.677 ;
     RECT  29.844 50.765 29.97 51.677 ;
     RECT  35.28 51.547 35.298 51.677 ;
     RECT  4.464 50.765 4.986 51.725 ;
     RECT  8.856 51.677 8.874 51.725 ;
     RECT  16.992 50.189 17.01 51.725 ;
     RECT  23.796 51.677 24.858 51.725 ;
     RECT  27.72 50.717 28.314 51.725 ;
     RECT  29.952 51.677 29.97 51.725 ;
     RECT  31.896 50.717 31.914 51.725 ;
     RECT  32.652 50.717 32.886 51.725 ;
     RECT  36.864 50.717 36.882 51.725 ;
     RECT  40.356 50.237 40.77 51.725 ;
     RECT  45 50.717 45.018 51.725 ;
    LAYER M4 ;
     RECT  0.084 3.888 2.408 3.912 ;
     RECT  0.06 3.912 2.408 4.032 ;
     RECT  0.084 4.032 2.408 4.056 ;
     RECT  0.06 4.056 2.408 4.176 ;
     RECT  0.084 4.176 2.408 4.2 ;
     RECT  0.06 4.2 2.408 4.32 ;
     RECT  0.084 4.32 2.408 4.344 ;
     RECT  0.06 4.344 2.408 4.464 ;
     RECT  0.084 4.464 2.408 4.488 ;
     RECT  0.06 4.488 2.408 4.608 ;
     RECT  0.084 4.608 2.408 4.632 ;
     RECT  0.06 4.632 2.408 4.752 ;
     RECT  0.084 4.752 2.408 4.776 ;
     RECT  0.06 4.776 2.408 4.896 ;
     RECT  0.084 4.896 2.408 4.92 ;
     RECT  0.06 4.92 2.408 5.04 ;
     RECT  0.084 5.04 2.408 5.064 ;
     RECT  0.06 5.064 2.408 5.184 ;
     RECT  0.084 5.184 2.408 5.208 ;
     RECT  0.06 5.208 2.408 5.328 ;
     RECT  0.084 5.328 2.408 5.352 ;
     RECT  0.06 5.352 2.408 5.472 ;
     RECT  0.084 5.472 2.408 5.496 ;
     RECT  0.06 5.496 2.408 5.616 ;
     RECT  0.084 5.616 2.408 5.64 ;
     RECT  0.06 5.64 2.408 5.76 ;
     RECT  0.084 5.76 2.408 5.784 ;
     RECT  0.06 5.784 2.408 5.904 ;
     RECT  0.084 5.904 2.408 5.928 ;
     RECT  0.06 5.928 2.408 6.048 ;
     RECT  0.084 6.048 2.408 6.072 ;
     RECT  0.06 6.072 2.408 6.192 ;
     RECT  0.084 6.192 2.408 6.216 ;
     RECT  0.06 6.216 2.408 6.336 ;
     RECT  0.084 6.336 2.408 6.36 ;
     RECT  0.06 6.36 2.408 6.48 ;
     RECT  0.084 6.48 2.408 6.504 ;
     RECT  0.06 6.504 2.408 6.624 ;
     RECT  0.084 6.624 2.408 6.648 ;
     RECT  0.06 6.648 2.408 6.768 ;
     RECT  0.084 6.768 2.408 6.792 ;
     RECT  0.06 6.792 2.408 6.912 ;
     RECT  0.084 6.912 2.408 6.936 ;
     RECT  0.06 6.936 2.408 7.056 ;
     RECT  0.084 7.056 2.408 7.08 ;
     RECT  0.06 7.08 2.408 7.2 ;
     RECT  0.084 7.2 2.408 7.224 ;
     RECT  0.06 7.224 2.408 7.344 ;
     RECT  0.084 7.344 2.408 7.368 ;
     RECT  0.06 7.368 2.408 7.488 ;
     RECT  0.084 7.488 2.408 7.512 ;
     RECT  0.06 7.512 2.408 7.632 ;
     RECT  0.084 7.632 2.408 7.656 ;
     RECT  0.06 7.656 2.408 7.776 ;
     RECT  0.084 7.776 2.408 7.8 ;
     RECT  0.06 7.8 2.408 7.92 ;
     RECT  0.084 7.92 2.408 7.944 ;
     RECT  0.06 7.944 2.408 8.064 ;
     RECT  0.084 8.064 2.408 8.088 ;
     RECT  0.06 8.088 2.408 8.208 ;
     RECT  0.084 8.208 2.408 8.232 ;
     RECT  0.06 8.232 2.408 8.352 ;
     RECT  0.084 8.352 2.408 8.376 ;
     RECT  0.06 8.376 2.408 8.496 ;
     RECT  0.084 8.496 2.408 8.52 ;
     RECT  0.06 8.52 2.408 8.64 ;
     RECT  0.084 8.64 2.408 8.664 ;
     RECT  0.06 8.664 2.408 8.784 ;
     RECT  0.084 8.784 2.408 8.808 ;
     RECT  0.06 8.808 2.408 8.928 ;
     RECT  0.084 8.928 2.408 8.952 ;
     RECT  0.06 8.952 2.408 9.072 ;
     RECT  0.084 9.072 2.408 9.096 ;
     RECT  0.06 9.096 2.408 9.216 ;
     RECT  0.084 9.216 2.408 9.24 ;
     RECT  0.06 9.24 2.408 9.36 ;
     RECT  0.084 9.36 2.408 9.384 ;
     RECT  0.06 9.384 2.408 9.504 ;
     RECT  0.084 9.504 2.408 9.528 ;
     RECT  0.06 9.528 2.408 9.648 ;
     RECT  0.084 9.648 2.408 9.672 ;
     RECT  0.06 9.672 2.408 9.792 ;
     RECT  0.084 9.792 2.408 9.816 ;
     RECT  0.06 9.816 2.408 9.936 ;
     RECT  0.084 9.936 2.408 9.96 ;
     RECT  0.06 9.96 2.408 10.08 ;
     RECT  0.084 10.08 2.408 10.104 ;
     RECT  0.06 10.104 2.408 10.224 ;
     RECT  0.084 10.224 2.408 10.248 ;
     RECT  0.06 10.248 2.408 10.368 ;
     RECT  0.084 10.368 2.408 10.392 ;
     RECT  0.06 10.392 2.408 10.512 ;
     RECT  0.084 10.512 2.408 10.536 ;
     RECT  0.06 10.536 2.408 10.656 ;
     RECT  0.084 10.656 2.408 10.68 ;
     RECT  0.06 10.68 2.408 10.8 ;
     RECT  0.084 10.8 2.408 10.824 ;
     RECT  0.06 10.824 2.408 10.944 ;
     RECT  0.084 10.944 2.408 10.968 ;
     RECT  0.06 10.968 2.408 11.088 ;
     RECT  0.084 11.088 2.408 11.112 ;
     RECT  0.06 11.112 2.408 11.232 ;
     RECT  0.084 11.232 2.408 11.256 ;
     RECT  0.06 11.256 2.408 11.376 ;
     RECT  0.084 11.376 2.408 11.4 ;
     RECT  0.06 11.4 2.408 11.52 ;
     RECT  0.084 11.52 2.408 11.544 ;
     RECT  0.06 11.544 2.408 11.664 ;
     RECT  0.084 11.664 2.408 11.688 ;
     RECT  0.06 11.688 2.408 11.808 ;
     RECT  0.084 11.808 2.408 11.832 ;
     RECT  0.06 11.832 2.408 11.952 ;
     RECT  0.084 11.952 2.408 11.976 ;
     RECT  0.06 11.976 2.408 12.096 ;
     RECT  0.084 12.096 2.408 12.12 ;
     RECT  0.06 12.12 2.408 12.24 ;
     RECT  0.084 12.24 2.408 12.264 ;
     RECT  0.06 12.264 2.408 12.384 ;
     RECT  0.084 12.384 2.408 12.408 ;
     RECT  0.06 12.408 2.408 12.528 ;
     RECT  0.084 12.528 2.408 12.552 ;
     RECT  0.06 12.552 2.408 12.672 ;
     RECT  0.084 12.672 2.408 12.696 ;
     RECT  0.06 12.696 2.408 12.816 ;
     RECT  0.084 12.816 2.408 12.84 ;
     RECT  0.06 12.84 2.408 12.96 ;
     RECT  0.084 12.96 2.408 12.984 ;
     RECT  0.06 12.984 2.408 13.104 ;
     RECT  0.084 13.104 2.408 13.128 ;
     RECT  0.06 13.128 2.408 13.248 ;
     RECT  0.084 13.248 2.408 13.272 ;
     RECT  0.06 13.272 2.408 13.392 ;
     RECT  0.084 13.392 2.408 13.416 ;
     RECT  0.06 13.416 2.408 13.536 ;
     RECT  0.084 13.536 2.408 13.56 ;
     RECT  0.06 13.56 2.408 13.68 ;
     RECT  0.084 13.68 2.408 13.704 ;
     RECT  0.06 13.704 2.408 13.824 ;
     RECT  0.084 13.824 2.408 13.848 ;
     RECT  0.06 13.848 2.408 13.968 ;
     RECT  0.084 13.968 2.408 13.992 ;
     RECT  0.06 13.992 2.408 14.112 ;
     RECT  0.084 14.112 2.408 14.136 ;
     RECT  0.06 14.136 2.408 14.256 ;
     RECT  0.084 14.256 2.408 14.28 ;
     RECT  0.06 14.28 2.408 14.4 ;
     RECT  0.084 14.4 2.408 14.424 ;
     RECT  0.06 14.424 2.408 14.544 ;
     RECT  0.084 14.544 2.408 14.568 ;
     RECT  0.06 14.568 2.408 14.688 ;
     RECT  0.084 14.688 2.408 14.712 ;
     RECT  0.06 14.712 2.408 14.832 ;
     RECT  0.084 14.832 2.408 14.856 ;
     RECT  0.06 14.856 2.408 14.976 ;
     RECT  0.084 14.976 2.408 15 ;
     RECT  0.06 15 2.408 15.12 ;
     RECT  0.084 15.12 2.408 15.144 ;
     RECT  0.06 15.144 2.408 15.264 ;
     RECT  0.084 15.264 2.408 15.288 ;
     RECT  0.06 15.288 2.408 15.408 ;
     RECT  0.084 15.408 2.408 15.432 ;
     RECT  0.06 15.432 2.408 15.552 ;
     RECT  0.084 15.552 2.408 15.576 ;
     RECT  0.06 15.576 2.408 15.696 ;
     RECT  0.084 15.696 2.408 15.72 ;
     RECT  0.06 15.72 2.408 15.84 ;
     RECT  0.084 15.84 2.408 15.864 ;
     RECT  0.06 15.864 2.408 15.984 ;
     RECT  0.084 15.984 2.408 16.008 ;
     RECT  0.06 16.008 2.408 16.128 ;
     RECT  0.084 16.128 2.408 16.152 ;
     RECT  0.06 16.152 2.408 16.272 ;
     RECT  0.084 16.272 2.408 16.296 ;
     RECT  0.06 16.296 2.408 16.416 ;
     RECT  0.084 16.416 2.408 16.44 ;
     RECT  0.06 16.44 2.408 16.56 ;
     RECT  0.084 16.56 2.408 16.584 ;
     RECT  0.06 16.584 2.408 16.704 ;
     RECT  0.084 16.704 2.408 16.728 ;
     RECT  0.06 16.728 2.408 16.848 ;
     RECT  0.084 16.848 2.408 16.872 ;
     RECT  0.06 16.872 2.408 16.992 ;
     RECT  0.084 16.992 2.408 17.016 ;
     RECT  0.06 17.016 2.408 17.136 ;
     RECT  0.084 17.136 2.408 17.16 ;
     RECT  0.06 17.16 2.408 17.28 ;
     RECT  0.084 17.28 2.408 17.304 ;
     RECT  0.06 17.304 2.408 17.424 ;
     RECT  0.084 17.424 2.408 17.448 ;
     RECT  0.06 17.448 2.408 17.568 ;
     RECT  0.084 17.568 2.408 17.592 ;
     RECT  0.084 28.08 2.408 28.104 ;
     RECT  0.06 28.104 2.408 28.224 ;
     RECT  0.084 28.224 2.408 28.248 ;
     RECT  0.06 28.248 2.408 28.368 ;
     RECT  0.084 28.368 2.408 28.392 ;
     RECT  0.06 28.392 2.408 28.512 ;
     RECT  0.084 28.512 2.408 28.536 ;
     RECT  0.06 28.536 2.408 28.656 ;
     RECT  0.084 28.656 2.408 28.68 ;
     RECT  0.06 28.68 2.408 28.8 ;
     RECT  0.084 28.8 2.408 28.824 ;
     RECT  0.06 28.824 2.408 28.944 ;
     RECT  0.084 28.944 2.408 28.968 ;
     RECT  0.06 28.968 2.408 29.088 ;
     RECT  0.084 29.088 2.408 29.112 ;
     RECT  0.06 29.112 2.408 29.232 ;
     RECT  0.084 29.232 2.408 29.256 ;
     RECT  0.06 29.256 2.408 29.376 ;
     RECT  0.084 29.376 2.408 29.4 ;
     RECT  0.06 29.4 2.408 29.52 ;
     RECT  0.084 29.52 2.408 29.544 ;
     RECT  0.06 29.544 2.408 29.664 ;
     RECT  0.084 29.664 2.408 29.688 ;
     RECT  0.06 29.688 2.408 29.808 ;
     RECT  0.084 29.808 2.408 29.832 ;
     RECT  0.06 29.832 2.408 29.952 ;
     RECT  0.084 29.952 2.408 29.976 ;
     RECT  0.06 29.976 2.408 30.096 ;
     RECT  0.084 30.096 2.408 30.12 ;
     RECT  0.06 30.12 2.408 30.24 ;
     RECT  0.084 30.24 2.408 30.264 ;
     RECT  0.06 30.264 2.408 30.384 ;
     RECT  0.084 30.384 2.408 30.408 ;
     RECT  0.06 30.408 2.408 30.528 ;
     RECT  0.084 30.528 2.408 30.552 ;
     RECT  0.06 30.552 2.408 30.672 ;
     RECT  0.084 30.672 2.408 30.696 ;
     RECT  0.06 30.696 2.408 30.816 ;
     RECT  0.084 30.816 2.408 30.84 ;
     RECT  0.06 30.84 2.408 30.96 ;
     RECT  0.084 30.96 2.408 30.984 ;
     RECT  0.06 30.984 2.408 31.104 ;
     RECT  0.084 31.104 2.408 31.128 ;
     RECT  0.06 31.128 2.408 31.248 ;
     RECT  0.084 31.248 2.408 31.272 ;
     RECT  0.06 31.272 2.408 31.392 ;
     RECT  0.084 31.392 2.408 31.416 ;
     RECT  0.06 31.416 2.408 31.536 ;
     RECT  0.084 31.536 2.408 31.56 ;
     RECT  0.06 31.56 2.408 31.68 ;
     RECT  0.084 31.68 2.408 31.704 ;
     RECT  0.06 31.704 2.408 31.824 ;
     RECT  0.084 31.824 2.408 31.848 ;
     RECT  0.06 31.848 2.408 31.968 ;
     RECT  0.084 31.968 2.408 31.992 ;
     RECT  0.06 31.992 2.408 32.112 ;
     RECT  0.084 32.112 2.408 32.136 ;
     RECT  0.06 32.136 2.408 32.256 ;
     RECT  0.084 32.256 2.408 32.28 ;
     RECT  0.06 32.28 2.408 32.4 ;
     RECT  0.084 32.4 2.408 32.424 ;
     RECT  0.06 32.424 2.408 32.544 ;
     RECT  0.084 32.544 2.408 32.568 ;
     RECT  0.06 32.568 2.408 32.688 ;
     RECT  0.084 32.688 2.408 32.712 ;
     RECT  0.06 32.712 2.408 32.832 ;
     RECT  0.084 32.832 2.408 32.856 ;
     RECT  0.06 32.856 2.408 32.976 ;
     RECT  0.084 32.976 2.408 33 ;
     RECT  0.06 33 2.408 33.12 ;
     RECT  0.084 33.12 2.408 33.144 ;
     RECT  0.06 33.144 2.408 33.264 ;
     RECT  0.084 33.264 2.408 33.288 ;
     RECT  0.06 33.288 2.408 33.408 ;
     RECT  0.084 33.408 2.408 33.432 ;
     RECT  0.06 33.432 2.408 33.552 ;
     RECT  0.084 33.552 2.408 33.576 ;
     RECT  0.06 33.576 2.408 33.696 ;
     RECT  0.084 33.696 2.408 33.72 ;
     RECT  0.06 33.72 2.408 33.84 ;
     RECT  0.084 33.84 2.408 33.864 ;
     RECT  0.06 33.864 2.408 33.984 ;
     RECT  0.084 33.984 2.408 34.008 ;
     RECT  0.06 34.008 2.408 34.128 ;
     RECT  0.084 34.128 2.408 34.152 ;
     RECT  0.06 34.152 2.408 34.272 ;
     RECT  0.084 34.272 2.408 34.296 ;
     RECT  0.06 34.296 2.408 34.416 ;
     RECT  0.084 34.416 2.408 34.44 ;
     RECT  0.06 34.44 2.408 34.56 ;
     RECT  0.084 34.56 2.408 34.584 ;
     RECT  0.06 34.584 2.408 34.704 ;
     RECT  0.084 34.704 2.408 34.728 ;
     RECT  0.06 34.728 2.408 34.848 ;
     RECT  0.084 34.848 2.408 34.872 ;
     RECT  0.06 34.872 2.408 34.992 ;
     RECT  0.084 34.992 2.408 35.016 ;
     RECT  0.06 35.016 2.408 35.136 ;
     RECT  0.084 35.136 2.408 35.16 ;
     RECT  0.06 35.16 2.408 35.28 ;
     RECT  0.084 35.28 2.408 35.304 ;
     RECT  0.06 35.304 2.408 35.424 ;
     RECT  0.084 35.424 2.408 35.448 ;
     RECT  0.06 35.448 2.408 35.568 ;
     RECT  0.084 35.568 2.408 35.592 ;
     RECT  0.06 35.592 2.408 35.712 ;
     RECT  0.084 35.712 2.408 35.736 ;
     RECT  0.06 35.736 2.408 35.856 ;
     RECT  0.084 35.856 2.408 35.88 ;
     RECT  0.06 35.88 2.408 36 ;
     RECT  0.084 36 2.408 36.024 ;
     RECT  0.06 36.024 2.408 36.144 ;
     RECT  0.084 36.144 2.408 36.168 ;
     RECT  0.06 36.168 2.408 36.288 ;
     RECT  0.084 36.288 2.408 36.312 ;
     RECT  0.06 36.312 2.408 36.432 ;
     RECT  0.084 36.432 2.408 36.456 ;
     RECT  0.06 36.456 2.408 36.576 ;
     RECT  0.084 36.576 2.408 36.6 ;
     RECT  0.06 36.6 2.408 36.72 ;
     RECT  0.084 36.72 2.408 36.744 ;
     RECT  0.06 36.744 2.408 36.864 ;
     RECT  0.084 36.864 2.408 36.888 ;
     RECT  0.06 36.888 2.408 37.008 ;
     RECT  0.084 37.008 2.408 37.032 ;
     RECT  0.06 37.032 2.408 37.152 ;
     RECT  0.084 37.152 2.408 37.176 ;
     RECT  0.06 37.176 2.408 37.296 ;
     RECT  0.084 37.296 2.408 37.32 ;
     RECT  0.06 37.32 2.408 37.44 ;
     RECT  0.084 37.44 2.408 37.464 ;
     RECT  0.06 37.464 2.408 37.584 ;
     RECT  0.084 37.584 2.408 37.608 ;
     RECT  0.06 37.608 2.408 37.728 ;
     RECT  0.084 37.728 2.408 37.752 ;
     RECT  0.06 37.752 2.408 37.872 ;
     RECT  0.084 37.872 2.408 37.896 ;
     RECT  0.06 37.896 2.408 38.016 ;
     RECT  0.084 38.016 2.408 38.04 ;
     RECT  0.06 38.04 2.408 38.16 ;
     RECT  0.084 38.16 2.408 38.184 ;
     RECT  0.06 38.184 2.408 38.304 ;
     RECT  0.084 38.304 2.408 38.328 ;
     RECT  0.06 38.328 2.408 38.448 ;
     RECT  0.084 38.448 2.408 38.472 ;
     RECT  0.06 38.472 2.408 38.592 ;
     RECT  0.084 38.592 2.408 38.616 ;
     RECT  0.06 38.616 2.408 38.736 ;
     RECT  0.084 38.736 2.408 38.76 ;
     RECT  0.06 38.76 2.408 38.88 ;
     RECT  0.084 38.88 2.408 38.904 ;
     RECT  0.06 38.904 2.408 39.024 ;
     RECT  0.084 39.024 2.408 39.048 ;
     RECT  0.06 39.048 2.408 39.168 ;
     RECT  0.084 39.168 2.408 39.192 ;
     RECT  0.06 39.192 2.408 39.312 ;
     RECT  0.084 39.312 2.408 39.336 ;
     RECT  0.06 39.336 2.408 39.456 ;
     RECT  0.084 39.456 2.408 39.48 ;
     RECT  0.06 39.48 2.408 39.6 ;
     RECT  0.084 39.6 2.408 39.624 ;
     RECT  0.06 39.624 2.408 39.744 ;
     RECT  0.084 39.744 2.408 39.768 ;
     RECT  0.06 39.768 2.408 39.888 ;
     RECT  0.084 39.888 2.408 39.912 ;
     RECT  0.06 39.912 2.408 40.032 ;
     RECT  0.084 40.032 2.408 40.056 ;
     RECT  0.06 40.056 2.408 40.176 ;
     RECT  0.084 40.176 2.408 40.2 ;
     RECT  0.06 40.2 2.408 40.32 ;
     RECT  0.084 40.32 2.408 40.344 ;
     RECT  0.06 40.344 2.408 40.464 ;
     RECT  0.084 40.464 2.408 40.488 ;
     RECT  0.06 40.488 2.408 40.608 ;
     RECT  0.084 40.608 2.408 40.632 ;
     RECT  0.06 40.632 2.408 40.752 ;
     RECT  0.084 40.752 2.408 40.776 ;
     RECT  0.06 40.776 2.408 40.896 ;
     RECT  0.084 40.896 2.408 40.92 ;
     RECT  0.06 40.92 2.408 41.04 ;
     RECT  0.084 41.04 2.408 41.064 ;
     RECT  0.06 41.064 2.408 41.184 ;
     RECT  0.084 41.184 2.408 41.208 ;
     RECT  0.06 41.208 2.408 41.328 ;
     RECT  0.084 41.328 2.408 41.352 ;
     RECT  0.06 41.352 2.408 41.472 ;
     RECT  0.084 41.472 2.408 41.496 ;
     RECT  0.06 41.496 2.408 41.616 ;
     RECT  0.084 41.616 2.408 41.64 ;
     RECT  0.06 41.64 2.408 41.76 ;
     RECT  0.084 41.76 2.408 41.784 ;
     RECT  0.06 41.784 2.408 42.192 ;
     RECT  0.084 42.192 2.408 42.216 ;
     RECT  0.06 42.216 2.408 42.336 ;
     RECT  0.084 42.336 2.408 42.36 ;
     RECT  0.06 42.36 2.408 42.48 ;
     RECT  0.084 42.48 2.408 42.504 ;
     RECT  0.06 42.504 2.408 42.624 ;
     RECT  0.084 42.624 2.408 42.648 ;
     RECT  0.06 42.648 2.408 42.768 ;
     RECT  0.084 42.768 2.408 42.792 ;
     RECT  0.06 42.792 2.408 42.912 ;
     RECT  0.084 42.912 2.408 42.936 ;
     RECT  0.06 42.936 2.408 43.056 ;
     RECT  0.084 43.056 2.408 43.08 ;
     RECT  0.06 43.08 2.408 43.2 ;
     RECT  0.084 43.2 2.408 43.224 ;
     RECT  0.06 43.224 2.408 43.344 ;
     RECT  0.084 43.344 2.408 43.368 ;
     RECT  0.06 43.368 2.408 43.488 ;
     RECT  0.084 43.488 2.408 43.512 ;
     RECT  0.06 43.512 2.408 43.632 ;
     RECT  0.084 43.632 2.408 43.656 ;
     RECT  0.06 43.656 2.408 43.776 ;
     RECT  0.084 43.776 2.408 43.8 ;
     RECT  0.06 43.8 2.408 43.92 ;
     RECT  0.084 43.92 2.408 43.944 ;
     RECT  0.06 43.944 2.408 44.064 ;
     RECT  0.084 44.064 2.408 44.088 ;
     RECT  0.06 44.088 2.408 44.208 ;
     RECT  0.084 44.208 2.408 44.232 ;
     RECT  0.06 44.232 2.408 44.352 ;
     RECT  0.084 44.352 2.408 44.376 ;
     RECT  0.06 44.376 2.408 44.496 ;
     RECT  0.084 44.496 2.408 44.52 ;
     RECT  0.06 44.52 2.408 44.64 ;
     RECT  0.084 44.64 2.408 44.664 ;
     RECT  0.06 44.664 2.408 44.784 ;
     RECT  0.084 44.784 2.408 44.808 ;
     RECT  0.06 44.808 2.408 44.928 ;
     RECT  0.084 44.928 2.408 44.952 ;
     RECT  0.06 44.952 2.408 45.072 ;
     RECT  0.084 45.072 2.408 45.096 ;
     RECT  0.06 45.096 2.408 45.216 ;
     RECT  0.084 45.216 2.408 45.24 ;
     RECT  0.06 45.24 2.408 45.36 ;
     RECT  0.084 45.36 2.408 45.384 ;
     RECT  0.06 45.384 2.408 45.504 ;
     RECT  0.084 45.504 2.408 45.528 ;
     RECT  0.06 45.528 2.408 45.648 ;
     RECT  0.084 45.648 2.408 45.672 ;
     RECT  0.06 45.672 2.408 45.792 ;
     RECT  0.084 45.792 2.408 45.816 ;
     RECT  0.06 45.816 2.408 45.936 ;
     RECT  0.084 45.936 2.408 45.96 ;
     RECT  0.06 45.96 2.408 46.08 ;
     RECT  0.084 46.08 2.408 46.104 ;
     RECT  0.06 46.104 2.408 46.224 ;
     RECT  0.084 46.224 2.408 46.248 ;
     RECT  0.06 46.248 2.408 46.368 ;
     RECT  0.084 46.368 2.408 46.392 ;
     RECT  2.408 2.148 2.512 49.692 ;
     RECT  2.512 2.418 2.704 49.422 ;
     RECT  2.704 4.752 2.729 4.776 ;
     RECT  2.704 16.272 2.729 16.296 ;
     RECT  2.704 17.424 2.765 17.448 ;
     RECT  2.704 41.76 2.801 41.784 ;
     RECT  2.704 47.76 3.443 49.032 ;
     RECT  3.877 50.16 4.124 50.184 ;
     RECT  4.124 50.16 4.309 50.76 ;
     RECT  3.443 47.76 4.313 48.456 ;
     RECT  4.313 48.432 4.637 48.456 ;
     RECT  4.309 50.16 4.787 51.72 ;
     RECT  4.787 51.696 4.997 51.72 ;
     RECT  4.787 50.16 5.029 50.712 ;
     RECT  5.029 49.488 5.132 50.712 ;
     RECT  5.309 1.728 5.42 1.752 ;
     RECT  5.281 46.704 5.533 46.728 ;
     RECT  5.132 48.96 5.825 50.712 ;
     RECT  5.825 48.96 5.893 50.184 ;
     RECT  5.893 48.864 6.221 50.184 ;
     RECT  6.221 48.96 6.227 50.184 ;
     RECT  5.533 46.704 6.253 47.064 ;
     RECT  6.253 46.08 6.469 47.064 ;
     RECT  6.469 46.08 6.685 47.352 ;
     RECT  6.685 46.08 6.761 47.592 ;
     RECT  6.761 46.128 7.196 47.592 ;
     RECT  6.227 48.96 7.196 49.608 ;
     RECT  7.148 50.736 7.235 50.76 ;
     RECT  7.196 46.128 7.477 49.608 ;
     RECT  7.729 5.76 7.765 5.784 ;
     RECT  5.42 1.728 7.808 2.28 ;
     RECT  6.865 3.312 7.808 3.336 ;
     RECT  7.765 5.76 7.808 6.312 ;
     RECT  7.405 26.736 7.808 26.76 ;
     RECT  7.621 29.232 7.808 29.256 ;
     RECT  7.477 46.128 7.808 50.184 ;
     RECT  7.808 1.728 8.104 50.184 ;
     RECT  8.104 48.384 8.453 50.184 ;
     RECT  8.453 48.384 8.533 49.56 ;
     RECT  8.533 48.384 8.633 49.224 ;
     RECT  8.104 29.232 8.849 29.256 ;
     RECT  8.629 51.696 8.884 51.72 ;
     RECT  8.884 51.648 8.885 51.72 ;
     RECT  8.104 27.168 8.921 27.192 ;
     RECT  8.885 51.648 9.029 51.672 ;
     RECT  8.104 5.04 9.107 6.312 ;
     RECT  8.633 48.384 9.148 49.032 ;
     RECT  8.104 45.6 9.205 47.304 ;
     RECT  9.148 48.384 9.205 48.504 ;
     RECT  9.205 45.6 9.292 48.504 ;
     RECT  9.107 5.04 9.353 5.064 ;
     RECT  8.104 1.728 9.457 1.8 ;
     RECT  8.104 20.16 9.529 20.184 ;
     RECT  9.292 48.384 9.539 48.504 ;
     RECT  9.107 6.24 9.565 6.312 ;
     RECT  8.104 7.392 9.565 7.416 ;
     RECT  9.529 20.16 9.565 21.096 ;
     RECT  9.377 22.176 9.565 22.2 ;
     RECT  8.104 11.904 9.569 11.928 ;
     RECT  9.292 45.6 9.605 47.304 ;
     RECT  9.565 6.24 9.649 7.416 ;
     RECT  9.457 1.728 9.74 1.848 ;
     RECT  9.539 48.384 9.785 48.408 ;
     RECT  9.565 20.16 9.857 22.2 ;
     RECT  9.605 45.6 9.965 46.776 ;
     RECT  9.637 50.688 9.965 50.808 ;
     RECT  8.104 9.696 10.001 9.72 ;
     RECT  9.965 45.6 10.001 45.72 ;
     RECT  9.74 1.728 10.105 2.28 ;
     RECT  9.965 50.736 10.115 50.808 ;
     RECT  9.277 17.04 10.133 17.064 ;
     RECT  8.104 18.768 10.133 18.792 ;
     RECT  9.925 49.536 10.213 49.56 ;
     RECT  9.965 46.704 10.217 46.776 ;
     RECT  9.857 21.072 10.249 22.2 ;
     RECT  9.397 23.376 10.249 23.4 ;
     RECT  10.105 1.728 10.259 2.856 ;
     RECT  10.22 15.888 10.307 15.912 ;
     RECT  10.249 21.072 10.397 23.4 ;
     RECT  10.259 2.832 10.403 2.856 ;
     RECT  9.745 26.208 10.465 26.232 ;
     RECT  10.397 21.072 10.469 22.776 ;
     RECT  10.133 17.04 10.505 18.792 ;
     RECT  10.357 42.768 10.505 42.792 ;
     RECT  10.177 9.648 10.537 9.672 ;
     RECT  10.177 11.328 10.537 11.352 ;
     RECT  10.537 11.328 10.573 11.832 ;
     RECT  9.649 7.392 10.609 7.416 ;
     RECT  10.537 9.024 10.609 9.672 ;
     RECT  9.649 6.24 10.645 6.264 ;
     RECT  10.609 7.392 10.645 9.672 ;
     RECT  10.645 6.24 10.649 9.672 ;
     RECT  10.213 49.44 10.681 49.56 ;
     RECT  10.115 50.736 10.691 50.76 ;
     RECT  10.717 19.872 10.789 19.896 ;
     RECT  9.745 24.528 10.825 24.552 ;
     RECT  10.465 26.208 10.825 26.328 ;
     RECT  10.649 6.24 10.829 9.336 ;
     RECT  10.825 24.528 10.829 26.328 ;
     RECT  10.829 24.528 10.897 25.464 ;
     RECT  10.829 6.24 10.901 9.048 ;
     RECT  10.505 17.04 10.937 18.024 ;
     RECT  10.573 11.328 11.009 12.744 ;
     RECT  10.897 23.952 11.009 25.464 ;
     RECT  10.681 48.528 11.009 49.56 ;
     RECT  11.009 23.952 11.267 25.272 ;
     RECT  10.901 7.392 11.315 9.048 ;
     RECT  10.259 1.728 11.324 1.848 ;
     RECT  11.009 11.328 11.401 12.216 ;
     RECT  11.324 1.728 11.411 2.328 ;
     RECT  11.315 7.44 11.411 9.048 ;
     RECT  11.267 23.952 11.441 24.552 ;
     RECT  10.501 45.552 11.441 45.576 ;
     RECT  11.401 11.04 11.473 12.216 ;
     RECT  10.217 46.752 11.473 46.776 ;
     RECT  11.441 23.952 11.549 23.976 ;
     RECT  11.411 7.872 11.585 9.048 ;
     RECT  11.473 46.56 11.657 46.776 ;
     RECT  11.473 10.704 11.693 12.216 ;
     RECT  10.789 19.584 11.725 19.896 ;
     RECT  11.585 7.968 11.905 9.048 ;
     RECT  11.657 46.656 11.909 46.776 ;
     RECT  11.009 48.816 11.941 49.56 ;
     RECT  11.693 11.424 11.981 12.216 ;
     RECT  10.469 21.072 11.987 22.344 ;
     RECT  11.411 1.728 11.989 2.28 ;
     RECT  11.981 11.808 12.013 12.216 ;
     RECT  11.761 26.64 12.013 26.664 ;
     RECT  10.933 50.688 12.044 50.712 ;
     RECT  11.869 15.696 12.049 15.72 ;
     RECT  12.044 50.688 12.049 50.76 ;
     RECT  12.049 15.696 12.085 16.104 ;
     RECT  10.937 17.136 12.085 18.024 ;
     RECT  12.049 42.768 12.133 42.792 ;
     RECT  12.049 50.688 12.275 50.856 ;
     RECT  12.013 11.808 12.301 12.552 ;
     RECT  12.013 26.352 12.337 26.664 ;
     RECT  11.653 4.56 12.517 4.584 ;
     RECT  12.085 15.696 12.517 18.024 ;
     RECT  11.905 7.968 12.553 9.096 ;
     RECT  12.553 7.968 12.661 9.384 ;
     RECT  12.301 11.808 12.733 12.936 ;
     RECT  12.661 7.968 12.841 10.056 ;
     RECT  12.733 11.808 12.841 13.08 ;
     RECT  11.987 21.12 12.841 22.344 ;
     RECT  12.373 23.328 12.841 23.352 ;
     RECT  12.841 11.808 12.877 13.128 ;
     RECT  10.717 14.208 12.877 14.232 ;
     RECT  12.445 2.832 12.913 2.856 ;
     RECT  12.841 7.968 12.985 10.44 ;
     RECT  12.877 11.808 12.985 14.232 ;
     RECT  11.725 19.584 13.013 19.992 ;
     RECT  12.841 21.12 13.013 23.352 ;
     RECT  11.909 46.704 13.052 46.776 ;
     RECT  12.517 15.696 13.057 18.408 ;
     RECT  13.013 19.584 13.057 23.352 ;
     RECT  13.052 46.032 13.093 46.776 ;
     RECT  11.941 48.816 13.093 49.656 ;
     RECT  12.275 50.688 13.093 50.76 ;
     RECT  11.989 1.728 13.208 1.8 ;
     RECT  12.913 2.832 13.208 2.904 ;
     RECT  12.517 4.56 13.208 5.208 ;
     RECT  10.901 6.24 13.208 6.264 ;
     RECT  12.985 7.968 13.208 14.232 ;
     RECT  13.057 15.696 13.208 23.352 ;
     RECT  12.337 25.2 13.208 25.224 ;
     RECT  12.337 26.208 13.208 26.664 ;
     RECT  13.093 46.032 13.208 47.736 ;
     RECT  13.093 48.816 13.208 50.76 ;
     RECT  13.208 1.728 13.504 50.76 ;
     RECT  13.504 7.728 13.619 13.752 ;
     RECT  13.504 15.36 13.637 16.008 ;
     RECT  13.504 41.616 13.645 41.832 ;
     RECT  13.504 19.392 13.667 19.608 ;
     RECT  13.645 41.808 13.709 41.832 ;
     RECT  13.619 7.728 13.745 10.296 ;
     RECT  13.619 11.424 13.745 13.752 ;
     RECT  13.504 45.312 13.889 45.48 ;
     RECT  13.745 8.736 13.925 10.296 ;
     RECT  13.504 24.672 13.925 26.664 ;
     RECT  13.504 20.928 13.997 23.256 ;
     RECT  13.925 25.2 13.997 26.664 ;
     RECT  13.504 1.728 14.105 2.904 ;
     RECT  13.504 49.008 14.141 50.76 ;
     RECT  13.745 11.424 14.291 13.704 ;
     RECT  14.141 50.16 14.348 50.76 ;
     RECT  13.637 15.36 14.393 15.384 ;
     RECT  13.997 25.968 14.435 26.664 ;
     RECT  14.348 50.16 14.435 50.808 ;
     RECT  13.997 20.928 14.465 23.16 ;
     RECT  14.141 49.008 14.497 49.176 ;
     RECT  14.435 50.16 14.579 50.76 ;
     RECT  14.105 1.728 14.681 2.856 ;
     RECT  14.677 0.576 14.761 0.6 ;
     RECT  13.889 45.456 14.857 45.48 ;
     RECT  14.857 45.456 14.933 45.768 ;
     RECT  13.504 3.936 14.969 5.208 ;
     RECT  14.497 48.96 14.969 49.176 ;
     RECT  14.969 49.056 15.109 49.176 ;
     RECT  13.745 7.728 15.113 7.752 ;
     RECT  13.925 8.736 15.145 9 ;
     RECT  14.893 6.288 15.217 6.312 ;
     RECT  15.145 8.736 15.217 9.096 ;
     RECT  15.217 8.736 15.253 9.144 ;
     RECT  14.933 45.552 15.253 45.768 ;
     RECT  13.504 47.04 15.253 47.064 ;
     RECT  15.109 49.056 15.257 49.56 ;
     RECT  15.253 47.04 15.301 47.208 ;
     RECT  15.301 46.992 15.347 47.208 ;
     RECT  14.291 13.296 15.397 13.704 ;
     RECT  13.925 10.272 15.577 10.296 ;
     RECT  14.677 42.336 15.577 42.36 ;
     RECT  14.969 4.512 15.617 5.208 ;
     RECT  15.253 8.496 15.649 9.144 ;
     RECT  15.253 45.552 15.649 45.912 ;
     RECT  15.347 46.992 15.649 47.064 ;
     RECT  14.579 50.688 15.685 50.76 ;
     RECT  15.577 42.336 15.821 42.792 ;
     RECT  15.685 50.112 15.829 50.76 ;
     RECT  14.681 1.728 15.865 2.28 ;
     RECT  15.361 3.36 15.865 3.384 ;
     RECT  15.649 8.496 15.901 9.192 ;
     RECT  15.577 10.272 15.901 10.632 ;
     RECT  15.821 42.144 15.905 42.792 ;
     RECT  14.291 11.808 15.937 11.976 ;
     RECT  15.905 42.768 15.941 42.792 ;
     RECT  15.649 45.552 16.019 47.064 ;
     RECT  16.019 45.84 16.06 47.064 ;
     RECT  15.901 8.496 16.069 10.632 ;
     RECT  15.937 11.76 16.069 11.976 ;
     RECT  15.257 49.056 16.261 49.128 ;
     RECT  15.829 50.112 16.261 51.672 ;
     RECT  16.069 8.496 16.297 11.976 ;
     RECT  15.397 13.296 16.297 13.896 ;
     RECT  16.261 49.056 16.369 51.672 ;
     RECT  15.217 6.288 16.405 6.84 ;
     RECT  16.369 48.864 16.441 51.672 ;
     RECT  16.297 8.496 16.477 13.896 ;
     RECT  15.617 4.896 16.549 5.208 ;
     RECT  16.405 6.192 16.549 6.84 ;
     RECT  16.477 8.496 16.585 14.136 ;
     RECT  16.441 48.432 16.595 51.672 ;
     RECT  16.549 4.896 16.841 6.84 ;
     RECT  15.865 1.728 16.981 3.384 ;
     RECT  16.841 4.896 16.981 5.256 ;
     RECT  16.693 51.696 17.021 51.72 ;
     RECT  16.585 7.968 17.053 14.136 ;
     RECT  17.053 7.968 17.129 14.472 ;
     RECT  17.129 11.712 17.201 14.472 ;
     RECT  16.841 6.288 17.233 6.84 ;
     RECT  16.595 48.432 17.273 50.184 ;
     RECT  16.981 1.728 17.315 5.256 ;
     RECT  17.315 3.12 17.345 5.256 ;
     RECT  16.06 46.176 17.365 47.064 ;
     RECT  17.345 3.12 17.489 3.384 ;
     RECT  17.365 45.888 17.605 47.064 ;
     RECT  15.073 24.432 17.893 24.456 ;
     RECT  17.605 45.888 17.989 47.88 ;
     RECT  17.233 6.288 18.025 6.888 ;
     RECT  17.129 7.968 18.025 10.632 ;
     RECT  17.201 11.712 18.205 14.28 ;
     RECT  18.205 11.664 18.313 14.28 ;
     RECT  17.989 45.504 18.349 47.88 ;
     RECT  17.273 48.96 18.349 49.608 ;
     RECT  18.313 11.664 18.373 14.52 ;
     RECT  15.289 15.552 18.373 15.576 ;
     RECT  18.349 45.024 18.385 47.88 ;
     RECT  18.349 48.864 18.385 49.608 ;
     RECT  18.385 45.024 18.421 49.608 ;
     RECT  18.421 44.64 18.469 49.608 ;
     RECT  18.277 50.688 18.469 50.712 ;
     RECT  18.469 44.64 18.533 50.712 ;
     RECT  17.345 4.896 18.565 5.256 ;
     RECT  18.025 6.288 18.565 10.632 ;
     RECT  18.373 11.664 18.565 15.576 ;
     RECT  17.315 1.728 18.608 1.896 ;
     RECT  17.489 3.312 18.608 3.384 ;
     RECT  18.565 4.896 18.608 15.576 ;
     RECT  13.667 19.584 18.608 19.608 ;
     RECT  14.465 21.12 18.608 23.16 ;
     RECT  17.893 24.432 18.608 24.648 ;
     RECT  14.435 25.968 18.608 26.376 ;
     RECT  18.449 42.768 18.608 42.792 ;
     RECT  18.533 44.64 18.608 50.184 ;
     RECT  18.608 1.728 18.904 50.184 ;
     RECT  18.904 4.656 19.037 5.88 ;
     RECT  18.904 1.728 19.073 3.384 ;
     RECT  18.904 7.392 19.253 14.184 ;
     RECT  18.904 45.552 19.325 50.184 ;
     RECT  19.037 4.656 19.331 5.688 ;
     RECT  18.904 19.584 19.379 23.16 ;
     RECT  19.325 48.768 19.397 50.184 ;
     RECT  19.429 0.576 19.513 0.6 ;
     RECT  19.397 48.96 19.649 50.184 ;
     RECT  19.253 8.496 19.969 14.184 ;
     RECT  19.331 5.664 20.185 5.688 ;
     RECT  19.073 1.728 20.195 2.28 ;
     RECT  19.331 4.656 20.261 4.68 ;
     RECT  19.379 19.92 20.369 23.16 ;
     RECT  19.073 3.36 20.473 3.384 ;
     RECT  20.473 2.832 20.477 3.384 ;
     RECT  19.649 48.96 20.483 49.608 ;
     RECT  20.195 1.728 20.513 1.8 ;
     RECT  20.477 2.832 20.627 2.856 ;
     RECT  20.185 5.664 20.693 6.36 ;
     RECT  19.325 45.552 20.693 47.448 ;
     RECT  19.969 8.496 20.761 14.28 ;
     RECT  20.693 45.552 20.905 47.352 ;
     RECT  20.369 19.92 20.941 19.944 ;
     RECT  20.941 19.296 21.013 19.944 ;
     RECT  20.761 8.448 21.053 14.28 ;
     RECT  20.972 18.096 21.059 18.12 ;
     RECT  20.905 45.216 21.089 47.352 ;
     RECT  20.693 5.664 21.301 5.688 ;
     RECT  19.253 7.392 21.301 7.416 ;
     RECT  21.301 5.472 21.347 5.688 ;
     RECT  21.301 6.864 21.385 7.416 ;
     RECT  21.053 8.496 21.445 14.28 ;
     RECT  21.013 19.2 21.557 19.944 ;
     RECT  20.483 48.96 21.581 49.56 ;
     RECT  21.557 19.2 21.625 19.8 ;
     RECT  21.445 8.496 21.629 14.424 ;
     RECT  21.089 45.456 21.701 47.352 ;
     RECT  21.701 45.456 21.737 46.68 ;
     RECT  20.513 1.728 21.836 1.752 ;
     RECT  21.581 48.912 21.841 49.56 ;
     RECT  21.737 45.456 21.845 45.48 ;
     RECT  21.836 1.728 21.923 2.28 ;
     RECT  22.129 3.264 22.201 3.288 ;
     RECT  21.841 48.672 22.345 49.56 ;
     RECT  21.737 46.512 22.349 46.68 ;
     RECT  21.385 7.392 22.417 7.416 ;
     RECT  21.629 8.496 22.417 14.328 ;
     RECT  20.369 21.12 22.453 23.16 ;
     RECT  22.345 47.856 22.493 49.56 ;
     RECT  22.201 2.832 22.499 3.288 ;
     RECT  22.493 49.104 22.529 49.56 ;
     RECT  22.499 3.264 22.597 3.288 ;
     RECT  21.625 19.056 22.637 19.8 ;
     RECT  22.597 0.576 22.681 0.6 ;
     RECT  18.904 15.696 22.705 15.72 ;
     RECT  18.904 25.968 22.705 26.376 ;
     RECT  22.597 3.264 22.745 3.912 ;
     RECT  21.923 1.728 23.021 1.752 ;
     RECT  22.493 47.856 23.033 48.072 ;
     RECT  23.021 1.728 23.165 1.8 ;
     RECT  22.417 7.392 23.209 14.328 ;
     RECT  22.705 15.696 23.209 16.536 ;
     RECT  23.209 7.392 23.281 16.536 ;
     RECT  23.281 7.392 23.317 17.208 ;
     RECT  18.904 24.432 23.389 24.648 ;
     RECT  22.529 49.536 23.461 49.56 ;
     RECT  23.461 49.536 23.605 50.184 ;
     RECT  22.453 21.12 23.785 23.304 ;
     RECT  23.389 24.384 23.785 24.648 ;
     RECT  22.637 19.056 23.852 19.32 ;
     RECT  23.033 48.048 23.852 48.072 ;
     RECT  23.605 49.536 23.852 50.664 ;
     RECT  23.165 1.728 23.965 1.848 ;
     RECT  22.745 3.264 23.965 3.288 ;
     RECT  23.965 1.728 24.008 3.288 ;
     RECT  21.347 5.472 24.008 5.496 ;
     RECT  23.317 6.816 24.008 17.208 ;
     RECT  23.852 19.056 24.008 19.944 ;
     RECT  23.785 21.12 24.008 24.648 ;
     RECT  22.705 25.776 24.008 26.376 ;
     RECT  22.349 46.512 24.008 46.536 ;
     RECT  23.852 48.048 24.008 50.664 ;
     RECT  24.008 1.728 24.037 50.664 ;
     RECT  24.037 1.728 24.304 50.712 ;
     RECT  24.304 2.88 24.401 2.904 ;
     RECT  24.304 5.472 24.419 5.64 ;
     RECT  24.304 45.504 24.419 50.712 ;
     RECT  24.419 5.616 24.445 5.64 ;
     RECT  24.304 7.968 24.473 20.088 ;
     RECT  24.473 7.968 24.509 18.12 ;
     RECT  24.419 46.608 24.509 50.712 ;
     RECT  24.509 46.608 24.515 49.56 ;
     RECT  24.509 7.968 24.563 16.68 ;
     RECT  24.304 21.12 24.725 24.648 ;
     RECT  24.563 8.448 24.797 16.68 ;
     RECT  24.509 50.688 24.868 50.712 ;
     RECT  23.741 51.696 24.868 51.72 ;
     RECT  24.868 50.688 24.869 51.72 ;
     RECT  24.304 1.728 24.905 1.848 ;
     RECT  24.869 50.688 25.049 51.672 ;
     RECT  24.304 4.368 25.121 4.392 ;
     RECT  24.304 41.088 25.273 41.208 ;
     RECT  24.509 18.096 25.301 18.12 ;
     RECT  24.304 43.968 25.333 44.376 ;
     RECT  24.725 21.12 25.337 23.304 ;
     RECT  24.515 46.704 25.337 49.56 ;
     RECT  24.473 19.296 25.379 20.088 ;
     RECT  25.333 43.968 25.477 44.424 ;
     RECT  25.337 46.704 25.589 47.928 ;
     RECT  25.477 43.968 25.625 44.52 ;
     RECT  25.049 50.688 25.667 50.76 ;
     RECT  24.797 8.448 25.697 16.248 ;
     RECT  25.697 8.496 25.715 16.248 ;
     RECT  25.337 49.008 25.757 49.56 ;
     RECT  25.667 50.688 25.757 50.712 ;
     RECT  25.379 19.968 25.765 20.088 ;
     RECT  25.337 21.12 25.765 23.16 ;
     RECT  25.589 46.704 25.765 46.776 ;
     RECT  25.715 8.496 25.769 15.72 ;
     RECT  24.419 45.504 25.805 45.576 ;
     RECT  24.304 6.816 25.873 6.84 ;
     RECT  25.873 6.816 25.909 7.464 ;
     RECT  25.765 46.656 25.909 46.776 ;
     RECT  25.909 6.24 25.949 7.464 ;
     RECT  25.949 7.44 25.957 7.464 ;
     RECT  24.905 1.728 26.045 1.8 ;
     RECT  25.757 49.008 26.093 50.712 ;
     RECT  26.093 49.008 26.099 50.184 ;
     RECT  25.769 15.36 26.129 15.72 ;
     RECT  24.725 24.384 26.161 24.648 ;
     RECT  25.669 17.28 26.165 17.304 ;
     RECT  25.477 4.608 26.201 4.632 ;
     RECT  25.949 6.24 26.269 6.264 ;
     RECT  26.161 24.336 26.305 24.648 ;
     RECT  26.269 5.712 26.417 6.264 ;
     RECT  26.417 5.712 26.531 5.736 ;
     RECT  26.305 24.288 26.531 24.648 ;
     RECT  26.485 3.168 26.572 3.192 ;
     RECT  26.099 49.44 26.597 50.184 ;
     RECT  26.045 1.728 26.629 1.848 ;
     RECT  25.909 46.08 26.633 46.776 ;
     RECT  26.531 24.288 26.669 24.456 ;
     RECT  26.597 49.44 26.675 49.656 ;
     RECT  25.765 19.968 26.773 23.16 ;
     RECT  25.625 44.064 26.881 44.52 ;
     RECT  26.773 19.776 26.953 23.16 ;
     RECT  26.953 18.816 26.963 23.16 ;
     RECT  25.769 8.496 26.989 14.184 ;
     RECT  26.963 19.968 27.061 23.16 ;
     RECT  26.675 49.44 27.065 49.56 ;
     RECT  26.989 8.4 27.133 14.184 ;
     RECT  25.589 47.904 27.137 47.928 ;
     RECT  27.061 50.688 27.145 50.712 ;
     RECT  26.633 46.08 27.157 46.728 ;
     RECT  27.065 49.44 27.172 49.512 ;
     RECT  24.304 25.776 27.457 27.336 ;
     RECT  26.963 18.816 27.493 18.84 ;
     RECT  27.493 18.192 27.539 18.84 ;
     RECT  27.061 19.968 27.569 23.352 ;
     RECT  26.129 15.696 27.601 15.72 ;
     RECT  27.172 49.392 27.637 49.512 ;
     RECT  27.157 45.696 27.641 46.728 ;
     RECT  26.629 1.728 27.713 1.896 ;
     RECT  27.569 20.064 27.733 23.352 ;
     RECT  26.669 24.336 27.733 24.456 ;
     RECT  27.637 49.248 27.745 49.512 ;
     RECT  27.641 45.696 27.781 45.72 ;
     RECT  27.733 20.064 27.817 24.456 ;
     RECT  27.457 25.68 27.817 27.336 ;
     RECT  27.565 6.816 27.877 6.84 ;
     RECT  27.133 8.4 27.877 14.424 ;
     RECT  27.877 6.816 27.923 14.424 ;
     RECT  27.817 20.064 27.923 27.336 ;
     RECT  27.923 6.864 27.964 14.424 ;
     RECT  27.539 18.192 27.965 18.792 ;
     RECT  27.932 16.752 28.019 16.776 ;
     RECT  25.273 41.184 28.211 41.208 ;
     RECT  27.641 46.704 28.211 46.728 ;
     RECT  26.881 43.248 28.217 44.52 ;
     RECT  27.713 1.728 28.253 1.848 ;
     RECT  27.965 18.768 28.253 18.792 ;
     RECT  27.964 6.864 28.289 6.888 ;
     RECT  27.781 45.552 28.289 45.72 ;
     RECT  27.349 51.696 28.325 51.72 ;
     RECT  28.289 45.696 28.355 45.72 ;
     RECT  28.253 1.824 28.397 1.848 ;
     RECT  27.745 48.384 28.645 49.512 ;
     RECT  28.501 50.688 28.645 50.712 ;
     RECT  28.645 48.384 29.036 50.712 ;
     RECT  27.923 20.064 29.077 24.504 ;
     RECT  27.923 25.68 29.077 27.336 ;
     RECT  29.077 19.968 29.125 24.504 ;
     RECT  29.077 25.68 29.125 27.912 ;
     RECT  29.105 34.176 29.221 34.2 ;
     RECT  28.789 45.936 29.221 45.96 ;
     RECT  29.221 33.264 29.269 34.2 ;
     RECT  28.165 36.528 29.269 36.552 ;
     RECT  29.221 45.936 29.269 46.2 ;
     RECT  27.964 8.496 29.408 14.424 ;
     RECT  27.601 15.408 29.408 15.72 ;
     RECT  29.125 19.968 29.408 27.912 ;
     RECT  29.269 33.264 29.408 35.496 ;
     RECT  29.269 36.528 29.408 37.08 ;
     RECT  28.217 43.872 29.408 44.52 ;
     RECT  29.269 45.936 29.408 46.728 ;
     RECT  29.036 48.384 29.408 51.672 ;
     RECT  29.408 2.148 29.501 51.672 ;
     RECT  29.501 1.728 29.653 51.672 ;
     RECT  29.653 1.728 29.704 51.72 ;
     RECT  29.704 38.736 29.939 38.76 ;
     RECT  29.704 49.008 29.981 51.72 ;
     RECT  29.704 44.064 30.053 44.472 ;
     RECT  29.704 46.752 30.089 47.928 ;
     RECT  29.981 49.008 30.131 50.76 ;
     RECT  29.704 20.16 30.233 27.912 ;
     RECT  29.704 45.552 30.269 45.576 ;
     RECT  30.089 46.848 30.377 47.928 ;
     RECT  29.704 40.32 30.413 41.064 ;
     RECT  30.233 24.432 30.485 27.912 ;
     RECT  29.704 1.728 30.563 2.28 ;
     RECT  29.704 6.24 30.755 14.184 ;
     RECT  30.755 6.288 30.773 14.184 ;
     RECT  30.773 8.496 30.805 14.184 ;
     RECT  30.877 18.72 30.949 18.744 ;
     RECT  30.377 47.904 30.949 47.928 ;
     RECT  30.131 49.008 30.949 50.712 ;
     RECT  30.485 24.432 30.953 27.72 ;
     RECT  30.949 47.904 30.953 50.712 ;
     RECT  29.704 35.28 30.985 35.304 ;
     RECT  29.704 36.528 30.985 36.552 ;
     RECT  30.949 37.776 30.985 37.8 ;
     RECT  30.985 36.528 31.093 37.8 ;
     RECT  30.953 47.904 31.169 50.616 ;
     RECT  30.233 20.16 31.205 23.4 ;
     RECT  30.949 18.72 31.265 18.984 ;
     RECT  29.704 15.696 31.333 16.536 ;
     RECT  31.205 20.4 31.345 23.4 ;
     RECT  30.953 24.432 31.345 27.336 ;
     RECT  31.265 18.72 31.349 19.368 ;
     RECT  31.333 15.696 31.379 17.064 ;
     RECT  31.093 46.464 31.381 46.728 ;
     RECT  31.093 36.528 31.493 38.76 ;
     RECT  31.381 45.6 31.493 46.728 ;
     RECT  31.169 48.432 31.493 50.616 ;
     RECT  31.493 38.736 31.561 38.76 ;
     RECT  31.379 17.04 31.676 17.064 ;
     RECT  31.379 15.696 31.709 15.864 ;
     RECT  31.493 46.464 31.709 46.728 ;
     RECT  30.805 8.496 31.741 14.232 ;
     RECT  31.709 15.696 31.741 15.72 ;
     RECT  29.704 31.392 31.741 31.416 ;
     RECT  31.309 33.312 31.741 33.336 ;
     RECT  31.676 17.04 31.763 17.64 ;
     RECT  30.413 40.32 31.772 40.344 ;
     RECT  31.741 31.152 31.813 31.416 ;
     RECT  31.772 40.32 31.813 40.872 ;
     RECT  31.813 40.32 31.817 41.64 ;
     RECT  31.817 40.848 31.859 41.64 ;
     RECT  31.777 3.264 31.861 3.288 ;
     RECT  31.813 30.912 31.877 31.416 ;
     RECT  31.877 30.72 31.921 31.416 ;
     RECT  31.493 36.528 31.925 37.608 ;
     RECT  31.921 29.76 31.961 31.416 ;
     RECT  31.345 20.4 31.964 27.336 ;
     RECT  30.563 1.728 31.993 1.8 ;
     RECT  31.861 2.832 31.993 3.576 ;
     RECT  31.961 29.76 32.005 29.784 ;
     RECT  31.925 36.528 32.033 36.552 ;
     RECT  31.964 20.4 32.051 28.152 ;
     RECT  32.005 29.232 32.051 29.784 ;
     RECT  31.993 1.728 32.069 3.576 ;
     RECT  31.741 8.496 32.173 15.72 ;
     RECT  30.985 35.232 32.209 35.304 ;
     RECT  32.209 34.752 32.249 35.304 ;
     RECT  32.173 8.448 32.281 15.72 ;
     RECT  31.859 40.896 32.285 41.64 ;
     RECT  32.051 20.4 32.387 27.336 ;
     RECT  32.209 4.08 32.389 4.104 ;
     RECT  29.704 5.184 32.389 5.208 ;
     RECT  32.069 1.728 32.483 3.048 ;
     RECT  32.389 4.08 32.483 5.208 ;
     RECT  32.497 0.576 32.581 0.6 ;
     RECT  32.483 1.728 32.681 2.856 ;
     RECT  31.925 37.584 32.681 37.608 ;
     RECT  31.561 38.736 32.681 38.808 ;
     RECT  31.741 32.496 32.717 33.336 ;
     RECT  31.349 18.72 32.749 18.984 ;
     RECT  32.387 20.4 32.749 24.504 ;
     RECT  32.387 25.776 32.819 27.336 ;
     RECT  32.717 32.592 32.821 33.336 ;
     RECT  32.249 34.752 32.821 35.208 ;
     RECT  31.525 51.696 32.897 51.72 ;
     RECT  30.053 44.064 32.929 44.424 ;
     RECT  31.763 17.04 32.965 17.064 ;
     RECT  31.709 46.704 32.965 46.728 ;
     RECT  32.821 32.592 33.005 35.208 ;
     RECT  32.965 46.704 33.005 46.824 ;
     RECT  32.281 8.4 33.013 15.72 ;
     RECT  32.051 29.232 33.037 29.256 ;
     RECT  31.961 30.816 33.037 31.416 ;
     RECT  33.013 8.4 33.059 15.864 ;
     RECT  32.965 17.04 33.059 17.112 ;
     RECT  32.483 4.56 33.061 5.208 ;
     RECT  30.773 6.288 33.061 7.416 ;
     RECT  32.681 38.736 33.073 38.76 ;
     RECT  31.493 48.432 33.077 49.224 ;
     RECT  32.749 18.72 33.107 24.504 ;
     RECT  33.077 48.912 33.109 49.224 ;
     RECT  31.957 50.688 33.109 50.712 ;
     RECT  33.005 32.592 33.149 34.776 ;
     RECT  33.059 15.696 33.221 15.864 ;
     RECT  33.061 4.56 33.253 7.416 ;
     RECT  33.059 8.4 33.253 14.28 ;
     RECT  32.285 40.896 33.361 40.92 ;
     RECT  32.681 1.728 33.397 2.28 ;
     RECT  32.533 45.6 33.397 45.624 ;
     RECT  33.001 42.72 33.433 42.744 ;
     RECT  32.929 43.824 33.433 44.424 ;
     RECT  33.059 17.04 33.437 17.064 ;
     RECT  33.397 45.552 33.505 45.624 ;
     RECT  33.109 0.096 33.545 0.12 ;
     RECT  33.001 36.624 33.577 36.648 ;
     RECT  33.433 42.72 33.613 44.424 ;
     RECT  33.073 38.64 33.649 38.76 ;
     RECT  33.005 46.8 33.653 46.824 ;
     RECT  33.577 35.952 33.689 36.648 ;
     RECT  33.037 29.232 33.721 31.512 ;
     RECT  33.149 32.592 33.721 34.152 ;
     RECT  33.721 29.232 33.725 34.152 ;
     RECT  33.397 1.104 33.731 2.28 ;
     RECT  33.725 29.232 33.757 29.256 ;
     RECT  33.109 48.912 33.788 50.712 ;
     RECT  33.757 29.04 33.829 29.256 ;
     RECT  33.689 36.096 33.833 36.648 ;
     RECT  33.107 18.912 33.865 24.504 ;
     RECT  33.788 48.912 33.875 50.76 ;
     RECT  33.221 15.84 33.901 15.864 ;
     RECT  33.361 40.416 33.901 40.92 ;
     RECT  33.613 42.288 33.973 44.424 ;
     RECT  32.819 25.776 34.009 27.24 ;
     RECT  33.875 48.912 34.019 50.184 ;
     RECT  33.253 4.56 34.117 14.28 ;
     RECT  33.505 45.552 34.117 45.816 ;
     RECT  33.865 18.912 34.153 24.792 ;
     RECT  33.829 28.944 34.153 29.256 ;
     RECT  34.009 25.776 34.189 27.672 ;
     RECT  34.153 28.752 34.189 29.256 ;
     RECT  33.649 38.64 34.225 39.048 ;
     RECT  34.225 38.64 34.297 39.096 ;
     RECT  33.973 42.24 34.621 44.424 ;
     RECT  34.117 45.552 34.621 46.152 ;
     RECT  33.725 30.672 34.693 34.152 ;
     RECT  34.621 42.24 34.693 46.344 ;
     RECT  34.153 47.856 34.693 47.88 ;
     RECT  33.833 36.624 34.765 36.648 ;
     RECT  33.731 1.728 34.808 2.28 ;
     RECT  34.117 4.56 34.808 14.52 ;
     RECT  33.901 15.84 34.808 16.536 ;
     RECT  34.153 18.816 34.808 24.792 ;
     RECT  34.189 25.776 34.808 29.256 ;
     RECT  34.693 30.624 34.808 34.152 ;
     RECT  34.765 36.624 34.808 37.368 ;
     RECT  34.297 38.64 34.808 39.336 ;
     RECT  33.901 40.416 34.808 41.208 ;
     RECT  34.693 42.24 34.808 47.88 ;
     RECT  34.019 48.912 34.808 50.136 ;
     RECT  34.808 1.728 34.981 50.136 ;
     RECT  34.981 1.728 35.104 50.184 ;
     RECT  35.104 47.136 35.129 50.184 ;
     RECT  35.129 48.432 35.173 50.184 ;
     RECT  34.837 51.648 35.173 51.672 ;
     RECT  35.173 48.432 35.212 51.672 ;
     RECT  35.104 20.112 35.27 37.08 ;
     RECT  35.27 20.112 35.309 36.984 ;
     RECT  35.104 17.04 35.315 17.112 ;
     RECT  35.104 38.736 35.345 46.008 ;
     RECT  35.212 50.112 35.353 51.672 ;
     RECT  35.309 25.776 35.381 36.984 ;
     RECT  35.345 41.904 35.381 45.816 ;
     RECT  35.381 36.336 35.417 36.984 ;
     RECT  35.309 20.112 35.453 24.648 ;
     RECT  35.381 43.776 35.453 45.816 ;
     RECT  35.129 47.136 35.561 47.352 ;
     RECT  35.104 3.312 35.597 16.008 ;
     RECT  35.353 50.112 35.641 50.712 ;
     RECT  35.597 8.448 35.705 16.008 ;
     RECT  35.381 25.776 35.705 35.352 ;
     RECT  35.561 47.136 35.705 47.16 ;
     RECT  35.705 25.776 35.74 35.256 ;
     RECT  35.345 38.736 35.891 40.92 ;
     RECT  35.891 38.736 35.993 39.864 ;
     RECT  35.104 18.96 36.085 19.032 ;
     RECT  35.453 20.112 36.085 24.456 ;
     RECT  35.597 3.312 36.317 7.416 ;
     RECT  35.453 43.776 36.421 44.424 ;
     RECT  35.453 45.408 36.421 45.816 ;
     RECT  35.417 36.336 36.425 36.648 ;
     RECT  35.381 41.904 36.529 42.792 ;
     RECT  36.421 43.776 36.529 45.816 ;
     RECT  35.212 48.432 36.533 49.032 ;
     RECT  35.74 25.776 36.605 34.152 ;
     RECT  35.104 1.728 36.611 2.28 ;
     RECT  35.641 50.112 36.701 50.184 ;
     RECT  35.315 17.04 36.709 17.064 ;
     RECT  35.891 40.896 36.709 40.92 ;
     RECT  36.529 41.904 36.709 45.816 ;
     RECT  35.705 8.448 36.737 15.864 ;
     RECT  36.709 17.04 36.737 17.304 ;
     RECT  36.709 40.896 36.749 45.816 ;
     RECT  36.085 18.96 36.757 24.456 ;
     RECT  36.605 28.752 36.757 34.152 ;
     RECT  35.74 35.232 36.757 35.256 ;
     RECT  36.701 50.112 36.785 50.712 ;
     RECT  36.757 18.96 36.803 24.648 ;
     RECT  36.533 48.72 36.853 49.032 ;
     RECT  36.785 50.112 36.853 50.184 ;
     RECT  36.565 51.696 36.893 51.72 ;
     RECT  36.803 19.728 36.901 24.648 ;
     RECT  36.605 25.776 36.901 27.336 ;
     RECT  36.317 4.896 36.925 7.416 ;
     RECT  36.737 8.448 36.925 17.304 ;
     RECT  36.611 1.728 36.929 1.8 ;
     RECT  36.425 36.48 36.997 36.648 ;
     RECT  35.993 38.736 36.997 39.624 ;
     RECT  36.749 40.896 36.997 44.424 ;
     RECT  36.925 4.896 37.033 17.304 ;
     RECT  36.997 36.48 37.033 37.512 ;
     RECT  36.997 38.736 37.033 44.424 ;
     RECT  37.033 4.896 37.141 17.496 ;
     RECT  36.901 19.728 37.187 27.336 ;
     RECT  36.749 45.552 37.213 45.816 ;
     RECT  37.033 36.48 37.253 44.424 ;
     RECT  36.853 48.72 37.253 50.184 ;
     RECT  36.317 3.312 37.285 3.672 ;
     RECT  37.141 4.896 37.285 17.64 ;
     RECT  37.213 45.552 37.325 46.776 ;
     RECT  37.285 3.312 37.333 17.64 ;
     RECT  37.333 3.312 37.393 18.504 ;
     RECT  37.393 2.832 37.433 18.504 ;
     RECT  37.253 50.16 37.433 50.184 ;
     RECT  36.757 28.752 37.465 35.256 ;
     RECT  37.253 36.48 37.465 37.512 ;
     RECT  37.253 48.72 37.475 49.032 ;
     RECT  37.433 7.632 37.619 18.504 ;
     RECT  37.465 28.752 37.757 37.512 ;
     RECT  37.717 48.432 37.829 48.456 ;
     RECT  37.433 2.832 37.865 6.6 ;
     RECT  36.929 1.728 37.997 1.752 ;
     RECT  37.187 19.776 38.041 27.336 ;
     RECT  37.757 28.752 38.041 29.4 ;
     RECT  38.041 19.776 38.044 29.4 ;
     RECT  37.865 2.832 38.081 4.008 ;
     RECT  38.044 19.776 38.125 28.968 ;
     RECT  37.325 45.552 38.149 46.68 ;
     RECT  37.825 50.688 38.293 50.76 ;
     RECT  37.757 30.48 38.297 37.512 ;
     RECT  38.149 45.504 38.365 46.68 ;
     RECT  38.297 30.48 38.513 36.984 ;
     RECT  38.293 50.688 38.521 51.672 ;
     RECT  37.253 38.736 38.549 44.424 ;
     RECT  38.549 38.736 38.579 42.6 ;
     RECT  38.521 51.648 38.579 51.672 ;
     RECT  38.579 38.736 38.581 39.336 ;
     RECT  38.549 43.584 38.581 44.424 ;
     RECT  38.365 45.408 38.581 47.304 ;
     RECT  37.619 17.328 38.617 18.504 ;
     RECT  38.125 19.776 38.621 27.336 ;
     RECT  38.581 43.584 38.689 47.304 ;
     RECT  38.081 3.36 38.729 4.008 ;
     RECT  38.581 49.008 38.771 49.56 ;
     RECT  38.513 30.48 38.773 35.448 ;
     RECT  38.773 30.048 38.801 35.448 ;
     RECT  37.619 7.632 38.821 16.296 ;
     RECT  38.617 17.328 38.821 18.792 ;
     RECT  37.997 1.728 38.869 1.8 ;
     RECT  37.865 5.088 38.977 6.6 ;
     RECT  38.821 7.632 38.977 18.792 ;
     RECT  38.689 43.584 39.017 47.928 ;
     RECT  38.977 5.088 39.053 18.792 ;
     RECT  38.801 30.048 39.157 34.152 ;
     RECT  39.013 49.584 39.203 50.184 ;
     RECT  39.053 5.184 39.337 18.792 ;
     RECT  38.621 19.776 39.337 27.24 ;
     RECT  38.125 28.752 39.337 28.968 ;
     RECT  39.157 29.952 39.337 34.152 ;
     RECT  39.203 50.112 39.517 50.184 ;
     RECT  39.337 28.752 39.769 34.152 ;
     RECT  38.801 35.424 39.769 35.448 ;
     RECT  39.517 50.112 39.923 50.76 ;
     RECT  38.513 36.432 39.949 36.984 ;
     RECT  38.581 38.16 39.98 39.336 ;
     RECT  38.579 40.416 39.98 42.6 ;
     RECT  38.869 1.728 39.985 1.848 ;
     RECT  39.017 43.584 40.021 45.576 ;
     RECT  39.017 46.608 40.021 47.928 ;
     RECT  39.769 28.752 40.069 35.448 ;
     RECT  39.949 36.432 40.069 37.08 ;
     RECT  39.337 5.184 40.165 27.24 ;
     RECT  40.069 51.648 40.165 51.672 ;
     RECT  39.985 1.728 40.208 2.04 ;
     RECT  38.729 3.36 40.208 3.672 ;
     RECT  40.165 5.04 40.208 27.24 ;
     RECT  40.069 28.752 40.208 37.08 ;
     RECT  39.98 38.16 40.208 42.6 ;
     RECT  40.021 43.584 40.208 47.928 ;
     RECT  39.923 50.112 40.208 50.184 ;
     RECT  40.165 51.648 40.355 51.72 ;
     RECT  40.208 1.728 40.504 50.184 ;
     RECT  40.504 35.424 40.643 50.184 ;
     RECT  40.504 18.48 40.673 18.504 ;
     RECT  40.643 41.04 40.709 50.184 ;
     RECT  40.709 41.04 40.781 46.632 ;
     RECT  40.355 51.696 40.781 51.72 ;
     RECT  40.781 41.04 40.889 46.296 ;
     RECT  40.889 41.04 41.033 46.056 ;
     RECT  40.709 47.904 41.276 50.184 ;
     RECT  40.504 19.536 41.465 34.248 ;
     RECT  40.504 1.728 41.569 3.672 ;
     RECT  40.504 4.752 41.569 17.352 ;
     RECT  41.465 19.776 41.603 34.248 ;
     RECT  41.603 27.888 41.645 30.072 ;
     RECT  41.603 31.344 41.681 34.248 ;
     RECT  41.033 41.952 41.717 46.056 ;
     RECT  40.643 35.424 41.845 39.768 ;
     RECT  41.276 47.904 41.857 50.232 ;
     RECT  41.681 31.392 41.893 34.248 ;
     RECT  41.845 35.376 41.893 39.768 ;
     RECT  41.569 1.728 42.005 17.352 ;
     RECT  41.893 31.392 42.033 39.768 ;
     RECT  42.005 5.04 42.113 17.352 ;
     RECT  42.113 5.04 42.185 13.944 ;
     RECT  42.033 31.392 42.221 34.968 ;
     RECT  42.145 0.096 42.229 0.12 ;
     RECT  42.005 1.728 42.257 3.864 ;
     RECT  41.857 47.664 42.289 50.232 ;
     RECT  41.603 19.776 42.293 26.376 ;
     RECT  42.185 6.288 42.329 7.224 ;
     RECT  42.113 15.264 42.329 17.352 ;
     RECT  42.289 47.664 42.361 50.712 ;
     RECT  42.329 15.264 42.437 16.296 ;
     RECT  42.033 36.048 42.469 39.768 ;
     RECT  41.717 42.24 42.469 46.056 ;
     RECT  42.361 47.664 42.515 50.76 ;
     RECT  41.645 27.888 42.613 29.784 ;
     RECT  42.613 27.456 42.617 29.784 ;
     RECT  42.469 36.048 42.649 39.816 ;
     RECT  42.293 20.016 42.653 26.376 ;
     RECT  42.649 36.048 42.709 39.864 ;
     RECT  42.617 28.752 42.721 29.784 ;
     RECT  42.221 31.392 42.721 31.416 ;
     RECT  42.709 36.048 42.833 40.152 ;
     RECT  42.757 0.576 42.844 0.6 ;
     RECT  42.833 36.048 42.905 39.912 ;
     RECT  42.221 32.448 42.941 34.968 ;
     RECT  42.515 47.664 43.013 50.712 ;
     RECT  42.437 15.312 43.085 16.296 ;
     RECT  42.617 27.456 43.121 27.48 ;
     RECT  43.013 47.664 43.181 48.984 ;
     RECT  42.329 17.328 43.189 17.352 ;
     RECT  42.329 6.288 43.193 6.84 ;
     RECT  43.085 15.6 43.193 16.296 ;
     RECT  42.905 38.688 43.193 39.912 ;
     RECT  42.257 1.728 43.225 3.672 ;
     RECT  43.189 17.328 43.225 17.832 ;
     RECT  42.721 28.752 43.235 31.416 ;
     RECT  43.225 1.728 43.297 3.864 ;
     RECT  42.185 5.04 43.297 5.208 ;
     RECT  43.235 28.944 43.297 31.416 ;
     RECT  42.941 32.448 43.297 33.912 ;
     RECT  42.653 20.016 43.301 26.088 ;
     RECT  43.301 20.16 43.373 24.408 ;
     RECT  43.301 25.776 43.373 26.088 ;
     RECT  43.181 47.328 43.379 48.984 ;
     RECT  43.297 1.728 43.405 5.208 ;
     RECT  43.193 6.288 43.405 6.648 ;
     RECT  42.185 8.256 43.405 13.944 ;
     RECT  43.405 1.728 43.445 6.648 ;
     RECT  42.469 42.24 43.445 46.2 ;
     RECT  43.193 15.6 43.481 16.008 ;
     RECT  43.405 8.256 43.513 14.184 ;
     RECT  43.445 42.24 43.513 45.432 ;
     RECT  43.513 7.968 43.549 14.184 ;
     RECT  43.297 28.944 43.553 33.912 ;
     RECT  43.513 41.616 43.585 45.432 ;
     RECT  43.445 1.728 43.589 6.6 ;
     RECT  43.549 7.968 43.621 14.232 ;
     RECT  43.225 17.328 43.657 18.216 ;
     RECT  43.333 0.096 43.697 0.12 ;
     RECT  43.589 1.728 43.841 6.552 ;
     RECT  42.905 36.048 43.873 37.608 ;
     RECT  43.553 28.944 43.877 29.064 ;
     RECT  43.873 35.904 43.913 37.608 ;
     RECT  43.379 48.624 44.012 48.984 ;
     RECT  43.013 50.112 44.021 50.712 ;
     RECT  43.193 38.688 44.099 39.864 ;
     RECT  43.913 35.904 44.125 36.552 ;
     RECT  44.125 34.944 44.233 36.552 ;
     RECT  43.657 17.328 44.269 18.84 ;
     RECT  43.585 41.52 44.269 45.432 ;
     RECT  43.621 7.968 44.377 14.376 ;
     RECT  43.481 15.6 44.377 15.864 ;
     RECT  43.373 20.352 44.377 24.408 ;
     RECT  43.373 25.776 44.377 25.8 ;
     RECT  43.913 37.536 44.377 37.608 ;
     RECT  43.379 47.328 44.377 47.352 ;
     RECT  44.012 48.624 44.377 49.032 ;
     RECT  44.269 41.088 44.413 45.432 ;
     RECT  44.021 50.688 44.425 50.712 ;
     RECT  44.269 16.896 44.449 18.84 ;
     RECT  44.377 20.352 44.449 25.8 ;
     RECT  44.377 7.968 44.453 15.864 ;
     RECT  44.377 37.536 44.525 38.184 ;
     RECT  44.413 40.992 44.557 46.104 ;
     RECT  44.377 47.328 44.557 49.032 ;
     RECT  44.449 16.896 44.593 25.8 ;
     RECT  43.657 27.6 44.629 27.624 ;
     RECT  44.557 40.992 44.629 49.032 ;
     RECT  43.553 30.288 44.773 33.912 ;
     RECT  44.453 7.968 44.809 8.856 ;
     RECT  44.453 10.08 44.845 15.864 ;
     RECT  44.593 16.896 44.845 25.992 ;
     RECT  44.773 30.144 44.917 33.912 ;
     RECT  44.233 34.896 44.917 36.552 ;
     RECT  44.629 51.696 45.029 51.72 ;
     RECT  44.917 30.144 45.205 36.552 ;
     RECT  44.629 27.408 45.277 27.624 ;
     RECT  44.629 40.992 45.313 49.56 ;
     RECT  45.205 30.144 45.493 37.08 ;
     RECT  44.525 38.16 45.493 38.184 ;
     RECT  43.841 1.728 45.608 6.312 ;
     RECT  44.809 7.92 45.608 8.856 ;
     RECT  44.845 10.08 45.608 25.992 ;
     RECT  45.277 27.408 45.608 27.72 ;
     RECT  43.877 28.944 45.608 28.968 ;
     RECT  45.493 30.144 45.608 38.184 ;
     RECT  44.099 39.36 45.608 39.864 ;
     RECT  45.313 40.992 45.608 49.608 ;
     RECT  45.608 1.728 45.637 49.692 ;
     RECT  45.637 1.728 45.904 50.184 ;
     RECT  45.781 51.648 45.925 51.672 ;
     RECT  45.904 5.184 45.965 34.104 ;
     RECT  45.925 51.552 46.019 51.672 ;
     RECT  45.904 37.056 46.067 41.064 ;
     RECT  46.019 51.552 46.067 51.576 ;
     RECT  45.965 5.232 46.073 34.104 ;
     RECT  46.067 39.84 46.115 41.064 ;
     RECT  45.904 42.24 46.181 50.184 ;
     RECT  46.073 25.44 46.289 34.104 ;
     RECT  46.181 42.24 46.289 49.56 ;
     RECT  46.289 25.44 46.325 31.992 ;
     RECT  46.289 33.312 46.361 34.104 ;
     RECT  46.361 33.552 46.433 34.104 ;
     RECT  46.325 29.616 46.541 31.992 ;
     RECT  46.289 42.24 46.613 49.512 ;
     RECT  46.541 31.488 46.793 31.992 ;
     RECT  46.613 42.24 46.829 42.984 ;
     RECT  45.904 1.728 46.979 3.864 ;
     RECT  46.073 5.232 47.117 24.408 ;
     RECT  46.115 39.936 47.185 41.064 ;
     RECT  46.829 42.24 47.185 42.792 ;
     RECT  46.067 37.056 47.189 38.712 ;
     RECT  46.541 29.616 47.261 30.456 ;
     RECT  46.793 31.728 47.329 31.992 ;
     RECT  47.189 37.632 47.333 38.712 ;
     RECT  46.433 33.888 47.369 34.104 ;
     RECT  47.333 38.4 47.369 38.712 ;
     RECT  46.325 25.488 47.401 27.864 ;
     RECT  47.261 29.616 47.401 29.784 ;
     RECT  47.117 10.848 47.405 24.408 ;
     RECT  47.437 38.736 47.468 38.76 ;
     RECT  47.185 39.936 47.468 42.792 ;
     RECT  47.369 34.08 47.513 34.104 ;
     RECT  47.117 5.232 47.549 9.864 ;
     RECT  47.405 10.992 47.549 24.408 ;
     RECT  46.613 44.064 47.549 49.512 ;
     RECT  47.468 38.736 47.555 42.792 ;
     RECT  47.329 31.728 47.585 32.664 ;
     RECT  47.549 5.232 47.621 6.408 ;
     RECT  47.549 8.016 47.621 9.864 ;
     RECT  47.549 10.992 47.621 17.064 ;
     RECT  47.621 6.384 47.657 6.408 ;
     RECT  47.621 8.16 47.657 9.864 ;
     RECT  47.549 44.256 47.657 49.368 ;
     RECT  47.585 31.728 47.693 31.992 ;
     RECT  47.657 44.256 47.693 46.296 ;
     RECT  47.555 39.168 47.729 42.792 ;
     RECT  47.657 8.496 47.765 9.864 ;
     RECT  47.621 10.992 47.765 15 ;
     RECT  47.657 47.472 47.765 49.368 ;
     RECT  47.765 49.344 47.801 49.368 ;
     RECT  47.765 9.552 47.837 9.864 ;
     RECT  47.693 44.4 47.909 46.296 ;
     RECT  47.765 47.472 47.909 47.928 ;
     RECT  47.729 42.72 47.945 42.792 ;
     RECT  46.979 2.832 47.98 3.864 ;
     RECT  47.909 44.4 47.981 45.24 ;
     RECT  47.981 44.976 48.017 45.24 ;
     RECT  47.98 3.36 48.085 3.864 ;
     RECT  47.765 13.008 48.089 15 ;
     RECT  47.401 25.488 48.125 29.784 ;
     RECT  48.125 25.488 48.161 29.64 ;
     RECT  47.549 18.384 48.193 24.408 ;
     RECT  48.161 25.488 48.193 27.432 ;
     RECT  48.193 18.384 48.197 27.432 ;
     RECT  47.621 5.232 48.227 5.256 ;
     RECT  48.197 27.408 48.233 27.432 ;
     RECT  47.909 47.472 48.233 47.88 ;
     RECT  48.085 3.36 48.268 4.152 ;
     RECT  48.161 28.656 48.305 29.64 ;
     RECT  48.305 29.616 48.341 29.64 ;
     RECT  46.979 1.728 48.365 1.8 ;
     RECT  47.765 10.992 48.373 11.976 ;
     RECT  48.197 18.384 48.413 26.424 ;
     RECT  48.365 1.728 48.449 1.848 ;
     RECT  48.233 47.472 48.449 47.688 ;
     RECT  47.909 46.272 48.485 46.296 ;
     RECT  48.449 47.664 48.485 47.688 ;
     RECT  47.837 9.552 48.521 9.816 ;
     RECT  48.413 18.384 48.521 24.792 ;
     RECT  47.729 39.168 48.521 41.688 ;
     RECT  48.449 1.728 48.593 1.752 ;
     RECT  48.373 10.896 48.593 11.976 ;
     RECT  48.521 20.592 48.593 20.616 ;
     RECT  48.017 44.976 48.593 45 ;
     RECT  48.593 11.952 48.629 11.976 ;
     RECT  47.621 15.984 48.629 17.064 ;
     RECT  48.521 23.616 48.665 24.792 ;
     RECT  48.413 26.4 48.665 26.424 ;
     RECT  48.521 39.168 48.665 41.496 ;
     RECT  47.765 8.496 48.701 8.52 ;
     RECT  48.521 9.792 48.701 9.816 ;
     RECT  48.089 14.208 48.701 15 ;
     RECT  48.521 18.384 48.701 19.464 ;
     RECT  48.089 13.008 48.737 13.032 ;
     RECT  48.701 18.576 48.737 19.464 ;
     RECT  48.629 16.848 48.949 17.064 ;
     RECT  48.593 10.896 48.989 10.92 ;
     RECT  48.949 16.848 49.021 17.112 ;
     RECT  47.693 31.728 49.021 31.752 ;
     RECT  47.945 42.72 49.025 42.744 ;
     RECT  49.021 31.728 49.093 32.28 ;
     RECT  48.521 21.888 49.097 22.392 ;
     RECT  49.093 31.392 49.309 32.28 ;
     RECT  49.309 6.768 49.381 6.792 ;
     RECT  49.093 33.984 49.381 34.008 ;
     RECT  49.381 6.048 49.453 6.792 ;
     RECT  48.268 3.36 49.457 3.384 ;
     RECT  48.701 14.688 49.489 15 ;
     RECT  49.453 6.048 49.597 7.368 ;
     RECT  49.453 8.352 49.597 8.376 ;
     RECT  49.489 14.688 49.597 15.432 ;
     RECT  49.021 16.848 49.597 17.304 ;
     RECT  48.665 39.168 49.597 40.2 ;
     RECT  48.665 41.472 49.597 41.496 ;
     RECT  49.597 29.664 49.633 29.688 ;
     RECT  49.597 39.024 49.633 40.2 ;
     RECT  49.597 14.688 49.669 17.304 ;
     RECT  48.665 23.664 49.669 24.792 ;
     RECT  49.381 25.92 49.669 25.944 ;
     RECT  49.597 45.504 49.669 45.528 ;
     RECT  49.633 47.232 49.669 47.256 ;
     RECT  49.633 38.736 49.705 40.2 ;
     RECT  49.669 23.664 49.741 25.944 ;
     RECT  49.669 45.504 49.741 45.816 ;
     RECT  49.597 5.76 49.777 8.376 ;
     RECT  49.705 10.08 49.777 10.104 ;
     RECT  49.561 11.232 49.777 11.256 ;
     RECT  49.813 28.08 49.849 28.104 ;
     RECT  49.633 29.664 49.849 29.976 ;
     RECT  49.309 30.96 49.849 32.28 ;
     RECT  49.597 20.016 50.101 20.04 ;
     RECT  49.777 5.76 50.137 8.52 ;
     RECT  49.777 9.504 50.137 10.104 ;
     RECT  49.777 11.232 50.137 11.688 ;
     RECT  49.129 13.104 50.137 13.56 ;
     RECT  49.669 14.688 50.137 17.448 ;
     RECT  48.737 18.576 50.137 18.888 ;
     RECT  50.101 20.016 50.137 20.616 ;
     RECT  49.097 21.888 50.137 21.912 ;
     RECT  49.741 23.328 50.137 26.232 ;
     RECT  49.849 27.504 50.137 28.104 ;
     RECT  49.849 29.664 50.137 32.28 ;
     RECT  49.381 33.264 50.137 34.008 ;
     RECT  49.705 38.736 50.137 40.344 ;
     RECT  49.597 41.472 50.137 42.36 ;
     RECT  49.669 43.632 50.137 43.656 ;
     RECT  49.741 44.784 50.137 45.816 ;
     RECT  49.669 47.088 50.137 47.256 ;
     RECT  50.137 9.504 50.173 11.976 ;
     RECT  50.137 13.104 50.173 20.904 ;
     RECT  50.137 21.888 50.173 28.248 ;
     RECT  50.137 38.736 50.173 42.36 ;
     RECT  50.137 43.488 50.173 45.816 ;
     RECT  50.137 47.088 50.173 47.544 ;
     RECT  50.137 5.328 50.677 8.52 ;
     RECT  50.173 9.504 50.677 28.248 ;
     RECT  50.173 38.736 50.677 47.544 ;
     RECT  50.677 5.328 51.756 5.352 ;
     RECT  50.677 5.352 51.804 5.472 ;
     RECT  50.677 5.472 51.756 5.496 ;
     RECT  50.677 5.496 51.804 5.616 ;
     RECT  50.677 5.616 51.756 5.64 ;
     RECT  50.677 5.64 51.804 5.76 ;
     RECT  50.677 5.76 51.756 5.784 ;
     RECT  50.677 5.784 51.804 5.904 ;
     RECT  50.677 5.904 51.756 5.928 ;
     RECT  50.677 5.928 51.804 6.048 ;
     RECT  50.677 6.048 51.756 6.072 ;
     RECT  50.677 6.072 51.804 6.192 ;
     RECT  50.677 6.192 51.756 6.216 ;
     RECT  50.677 6.216 51.804 6.336 ;
     RECT  50.677 6.336 51.756 6.36 ;
     RECT  50.677 6.36 51.804 6.48 ;
     RECT  50.677 6.48 51.756 6.504 ;
     RECT  50.677 6.504 51.804 6.624 ;
     RECT  50.677 6.624 51.756 6.648 ;
     RECT  50.677 6.648 51.804 6.768 ;
     RECT  50.677 6.768 51.756 6.792 ;
     RECT  50.677 6.792 51.804 6.912 ;
     RECT  50.677 6.912 51.756 6.936 ;
     RECT  50.677 6.936 51.804 7.056 ;
     RECT  50.677 7.056 51.756 7.08 ;
     RECT  50.677 7.08 51.804 7.2 ;
     RECT  50.677 7.2 51.756 7.224 ;
     RECT  50.677 7.224 51.804 7.344 ;
     RECT  50.677 7.344 51.756 7.368 ;
     RECT  50.677 7.368 51.804 7.488 ;
     RECT  50.677 7.488 51.756 7.512 ;
     RECT  50.677 7.512 51.804 7.632 ;
     RECT  50.677 7.632 51.756 7.656 ;
     RECT  50.677 7.656 51.804 7.776 ;
     RECT  50.677 7.776 51.756 7.8 ;
     RECT  50.677 7.8 51.804 7.92 ;
     RECT  50.677 7.92 51.756 7.944 ;
     RECT  50.677 7.944 51.804 8.064 ;
     RECT  50.677 8.064 51.756 8.088 ;
     RECT  50.677 8.088 51.804 8.208 ;
     RECT  50.677 8.208 51.756 8.232 ;
     RECT  50.677 8.232 51.804 8.352 ;
     RECT  50.677 8.352 51.756 8.376 ;
     RECT  50.677 8.376 51.804 8.496 ;
     RECT  50.677 8.496 51.756 8.52 ;
     RECT  50.677 8.52 51.804 8.64 ;
     RECT  50.677 8.64 51.756 8.664 ;
     RECT  50.677 8.664 51.804 8.784 ;
     RECT  50.677 8.784 51.756 8.808 ;
     RECT  50.677 8.808 51.804 8.928 ;
     RECT  50.677 8.928 51.756 8.952 ;
     RECT  50.677 8.952 51.804 9.072 ;
     RECT  50.677 9.072 51.756 9.096 ;
     RECT  50.677 9.096 51.804 9.216 ;
     RECT  50.677 9.216 51.756 9.24 ;
     RECT  50.677 9.24 51.804 9.36 ;
     RECT  50.677 9.36 51.756 9.384 ;
     RECT  50.677 9.384 51.804 9.504 ;
     RECT  50.677 9.504 51.756 9.528 ;
     RECT  50.677 9.528 51.804 9.648 ;
     RECT  50.677 9.648 51.756 9.672 ;
     RECT  50.677 9.672 51.804 9.792 ;
     RECT  50.677 9.792 51.756 9.816 ;
     RECT  50.677 9.816 51.804 9.936 ;
     RECT  50.677 9.936 51.756 9.96 ;
     RECT  50.677 9.96 51.804 10.08 ;
     RECT  50.677 10.08 51.756 10.104 ;
     RECT  50.677 10.104 51.804 10.224 ;
     RECT  50.677 10.224 51.756 10.248 ;
     RECT  50.677 10.248 51.804 10.368 ;
     RECT  50.677 10.368 51.756 10.392 ;
     RECT  50.677 10.392 51.804 10.512 ;
     RECT  50.677 10.512 51.756 10.536 ;
     RECT  50.677 10.536 51.804 10.656 ;
     RECT  50.677 10.656 51.756 10.68 ;
     RECT  50.677 10.68 51.804 10.8 ;
     RECT  50.677 10.8 51.756 10.824 ;
     RECT  50.677 10.824 51.804 10.944 ;
     RECT  50.677 10.944 51.756 10.968 ;
     RECT  50.677 10.968 51.804 11.088 ;
     RECT  50.677 11.088 51.756 11.112 ;
     RECT  50.677 11.112 51.804 11.232 ;
     RECT  50.677 11.232 51.756 11.256 ;
     RECT  50.677 11.256 51.804 11.376 ;
     RECT  50.677 11.376 51.756 11.4 ;
     RECT  50.677 11.4 51.804 11.52 ;
     RECT  50.677 11.52 51.756 11.544 ;
     RECT  50.677 11.544 51.804 11.664 ;
     RECT  50.677 11.664 51.756 11.688 ;
     RECT  50.677 11.688 51.804 11.808 ;
     RECT  50.677 11.808 51.756 11.832 ;
     RECT  50.677 11.832 51.804 11.952 ;
     RECT  50.677 11.952 51.756 11.976 ;
     RECT  50.677 11.976 51.804 12.096 ;
     RECT  50.677 12.096 51.756 12.12 ;
     RECT  50.677 12.12 51.804 12.24 ;
     RECT  50.677 12.24 51.756 12.264 ;
     RECT  50.677 12.264 51.804 12.384 ;
     RECT  50.677 12.384 51.756 12.408 ;
     RECT  50.677 12.408 51.804 12.528 ;
     RECT  50.677 12.528 51.756 12.552 ;
     RECT  50.677 12.552 51.804 12.672 ;
     RECT  50.677 12.672 51.756 12.696 ;
     RECT  50.677 12.696 51.804 12.816 ;
     RECT  50.677 12.816 51.756 12.84 ;
     RECT  50.677 12.84 51.804 12.96 ;
     RECT  50.677 12.96 51.756 12.984 ;
     RECT  50.677 12.984 51.804 13.104 ;
     RECT  50.677 13.104 51.756 13.128 ;
     RECT  50.677 13.128 51.804 13.248 ;
     RECT  50.677 13.248 51.756 13.272 ;
     RECT  50.677 13.272 51.804 13.392 ;
     RECT  50.677 13.392 51.756 13.416 ;
     RECT  50.677 13.416 51.804 13.536 ;
     RECT  50.677 13.536 51.756 13.56 ;
     RECT  50.677 13.56 51.804 13.68 ;
     RECT  50.677 13.68 51.756 13.704 ;
     RECT  50.677 13.704 51.804 13.824 ;
     RECT  50.677 13.824 51.756 13.848 ;
     RECT  50.677 13.848 51.804 13.968 ;
     RECT  50.677 13.968 51.756 13.992 ;
     RECT  50.677 13.992 51.804 14.112 ;
     RECT  50.677 14.112 51.756 14.136 ;
     RECT  50.677 14.136 51.804 14.256 ;
     RECT  50.677 14.256 51.756 14.28 ;
     RECT  50.677 14.28 51.804 14.4 ;
     RECT  50.677 14.4 51.756 14.424 ;
     RECT  50.677 14.424 51.804 14.544 ;
     RECT  50.677 14.544 51.756 14.568 ;
     RECT  50.677 14.568 51.804 14.688 ;
     RECT  50.677 14.688 51.756 14.712 ;
     RECT  50.677 14.712 51.804 14.832 ;
     RECT  50.677 14.832 51.756 14.856 ;
     RECT  50.677 14.856 51.804 14.976 ;
     RECT  50.677 14.976 51.756 15 ;
     RECT  50.677 15 51.804 15.12 ;
     RECT  50.677 15.12 51.756 15.144 ;
     RECT  50.677 15.144 51.804 15.264 ;
     RECT  50.677 15.264 51.756 15.288 ;
     RECT  50.677 15.288 51.804 15.408 ;
     RECT  50.677 15.408 51.756 15.432 ;
     RECT  50.677 15.432 51.804 15.552 ;
     RECT  50.677 15.552 51.756 15.576 ;
     RECT  50.677 15.576 51.804 15.696 ;
     RECT  50.677 15.696 51.756 15.72 ;
     RECT  50.677 15.72 51.804 15.84 ;
     RECT  50.677 15.84 51.756 15.864 ;
     RECT  50.677 15.864 51.804 15.984 ;
     RECT  50.677 15.984 51.756 16.008 ;
     RECT  50.677 16.008 51.804 16.128 ;
     RECT  50.677 16.128 51.756 16.152 ;
     RECT  50.677 16.152 51.804 16.272 ;
     RECT  50.677 16.272 51.756 16.296 ;
     RECT  50.677 16.296 51.804 16.416 ;
     RECT  50.677 16.416 51.756 16.44 ;
     RECT  50.677 16.44 51.804 16.56 ;
     RECT  50.677 16.56 51.756 16.584 ;
     RECT  50.677 16.584 51.804 16.704 ;
     RECT  50.677 16.704 51.756 16.728 ;
     RECT  50.677 16.728 51.804 16.848 ;
     RECT  50.677 16.848 51.756 16.872 ;
     RECT  50.677 16.872 51.804 16.992 ;
     RECT  50.677 16.992 51.756 17.016 ;
     RECT  50.677 17.016 51.804 17.136 ;
     RECT  50.677 17.136 51.756 17.16 ;
     RECT  50.677 17.16 51.804 17.28 ;
     RECT  50.677 17.28 51.756 17.304 ;
     RECT  50.677 17.304 51.804 17.424 ;
     RECT  50.677 17.424 51.756 17.448 ;
     RECT  50.677 17.448 51.804 17.568 ;
     RECT  50.677 17.568 51.756 17.592 ;
     RECT  50.677 17.592 51.804 17.712 ;
     RECT  50.677 17.712 51.756 17.736 ;
     RECT  50.677 17.736 51.804 17.856 ;
     RECT  50.677 17.856 51.756 17.88 ;
     RECT  50.677 17.88 51.804 18 ;
     RECT  50.677 18 51.756 18.024 ;
     RECT  50.677 18.024 51.804 18.144 ;
     RECT  50.677 18.144 51.756 18.168 ;
     RECT  50.677 18.168 51.804 18.288 ;
     RECT  50.677 18.288 51.756 18.312 ;
     RECT  50.677 18.312 51.804 18.432 ;
     RECT  50.677 18.432 51.756 18.456 ;
     RECT  50.677 18.456 51.804 18.576 ;
     RECT  50.677 18.576 51.756 18.6 ;
     RECT  50.677 18.6 51.804 18.72 ;
     RECT  50.677 18.72 51.756 18.744 ;
     RECT  50.677 18.744 51.804 18.864 ;
     RECT  50.677 18.864 51.756 18.888 ;
     RECT  50.677 18.888 51.804 19.008 ;
     RECT  50.677 19.008 51.756 19.032 ;
     RECT  50.677 19.032 51.804 19.152 ;
     RECT  50.677 19.152 51.756 19.176 ;
     RECT  50.677 19.176 51.804 19.296 ;
     RECT  50.677 19.296 51.756 19.32 ;
     RECT  50.677 19.32 51.804 19.44 ;
     RECT  50.677 19.44 51.756 19.464 ;
     RECT  50.677 19.464 51.804 19.584 ;
     RECT  50.677 19.584 51.756 19.608 ;
     RECT  50.677 19.608 51.804 19.728 ;
     RECT  50.677 19.728 51.756 19.752 ;
     RECT  50.677 19.752 51.804 19.872 ;
     RECT  50.677 19.872 51.756 19.896 ;
     RECT  50.677 19.896 51.804 20.016 ;
     RECT  50.677 20.016 51.756 20.04 ;
     RECT  50.677 20.04 51.804 20.16 ;
     RECT  50.677 20.16 51.756 20.184 ;
     RECT  50.677 20.184 51.804 20.304 ;
     RECT  50.677 20.304 51.756 20.328 ;
     RECT  50.677 20.328 51.804 20.448 ;
     RECT  50.677 20.448 51.756 20.472 ;
     RECT  50.677 20.472 51.804 20.592 ;
     RECT  50.677 20.592 51.756 20.616 ;
     RECT  50.677 20.616 51.804 20.736 ;
     RECT  50.677 20.736 51.756 20.76 ;
     RECT  50.677 20.76 51.804 20.88 ;
     RECT  50.677 20.88 51.756 20.904 ;
     RECT  50.677 20.904 51.804 21.024 ;
     RECT  50.677 21.024 51.756 21.048 ;
     RECT  50.677 21.048 51.804 21.168 ;
     RECT  50.677 21.168 51.756 21.192 ;
     RECT  50.677 21.192 51.804 21.312 ;
     RECT  50.677 21.312 51.756 21.336 ;
     RECT  50.677 21.336 51.804 21.456 ;
     RECT  50.677 21.456 51.756 21.48 ;
     RECT  50.677 21.48 51.804 21.6 ;
     RECT  50.677 21.6 51.756 21.624 ;
     RECT  50.677 21.624 51.804 21.744 ;
     RECT  50.677 21.744 51.756 21.768 ;
     RECT  50.677 21.768 51.804 21.888 ;
     RECT  50.677 21.888 51.756 21.912 ;
     RECT  50.677 21.912 51.804 22.032 ;
     RECT  50.677 22.032 51.756 22.056 ;
     RECT  50.677 22.056 51.804 22.176 ;
     RECT  50.677 22.176 51.756 22.2 ;
     RECT  50.677 22.2 51.804 22.32 ;
     RECT  50.677 22.32 51.756 22.344 ;
     RECT  50.677 22.344 51.804 22.464 ;
     RECT  50.677 22.464 51.756 22.488 ;
     RECT  50.677 22.488 51.804 22.608 ;
     RECT  50.677 22.608 51.756 22.632 ;
     RECT  50.677 22.632 51.804 22.752 ;
     RECT  50.677 22.752 51.756 22.776 ;
     RECT  50.677 22.776 51.804 22.896 ;
     RECT  50.677 22.896 51.756 22.92 ;
     RECT  50.677 22.92 51.804 23.04 ;
     RECT  50.677 23.04 51.756 23.064 ;
     RECT  50.677 23.064 51.804 23.184 ;
     RECT  50.677 23.184 51.756 23.208 ;
     RECT  50.677 23.208 51.804 23.328 ;
     RECT  50.677 23.328 51.756 23.352 ;
     RECT  50.677 23.352 51.804 23.472 ;
     RECT  50.677 23.472 51.756 23.496 ;
     RECT  50.677 23.496 51.804 23.616 ;
     RECT  50.677 23.616 51.756 23.64 ;
     RECT  50.677 23.64 51.804 23.76 ;
     RECT  50.677 23.76 51.756 23.784 ;
     RECT  50.677 23.784 51.804 23.904 ;
     RECT  50.677 23.904 51.756 23.928 ;
     RECT  50.677 23.928 51.804 24.048 ;
     RECT  50.677 24.048 51.756 24.072 ;
     RECT  50.677 24.072 51.804 24.192 ;
     RECT  50.677 24.192 51.756 24.216 ;
     RECT  50.677 24.216 51.804 24.336 ;
     RECT  50.677 24.336 51.756 24.36 ;
     RECT  50.677 24.36 51.804 24.48 ;
     RECT  50.677 24.48 51.756 24.504 ;
     RECT  50.677 24.504 51.804 24.624 ;
     RECT  50.677 24.624 51.756 24.648 ;
     RECT  50.677 24.648 51.804 24.768 ;
     RECT  50.677 24.768 51.756 24.792 ;
     RECT  50.677 24.792 51.804 24.912 ;
     RECT  50.677 24.912 51.756 24.936 ;
     RECT  50.677 24.936 51.804 25.056 ;
     RECT  50.677 25.056 51.756 25.08 ;
     RECT  50.677 25.08 51.804 25.2 ;
     RECT  50.677 25.2 51.756 25.224 ;
     RECT  50.677 25.224 51.804 25.344 ;
     RECT  50.677 25.344 51.756 25.368 ;
     RECT  50.677 25.368 51.804 25.488 ;
     RECT  50.677 25.488 51.756 25.512 ;
     RECT  50.677 25.512 51.804 25.632 ;
     RECT  50.677 25.632 51.756 25.656 ;
     RECT  50.677 25.656 51.804 25.776 ;
     RECT  50.677 25.776 51.756 25.8 ;
     RECT  50.677 25.8 51.804 25.92 ;
     RECT  50.677 25.92 51.756 25.944 ;
     RECT  50.677 25.944 51.804 26.064 ;
     RECT  50.677 26.064 51.756 26.088 ;
     RECT  50.677 26.088 51.804 26.208 ;
     RECT  50.677 26.208 51.756 26.232 ;
     RECT  50.677 26.232 51.804 26.352 ;
     RECT  50.677 26.352 51.756 26.376 ;
     RECT  50.677 26.376 51.804 26.496 ;
     RECT  50.677 26.496 51.756 26.52 ;
     RECT  50.677 26.52 51.804 26.64 ;
     RECT  50.677 26.64 51.756 26.664 ;
     RECT  50.677 26.664 51.804 26.784 ;
     RECT  50.677 26.784 51.756 26.808 ;
     RECT  50.677 26.808 51.804 26.928 ;
     RECT  50.677 26.928 51.756 26.952 ;
     RECT  50.677 26.952 51.804 27.072 ;
     RECT  50.677 27.072 51.756 27.096 ;
     RECT  50.677 27.096 51.804 27.216 ;
     RECT  50.677 27.216 51.756 27.24 ;
     RECT  50.677 27.24 51.804 27.36 ;
     RECT  50.677 27.36 51.756 27.384 ;
     RECT  50.677 27.384 51.804 27.504 ;
     RECT  50.677 27.504 51.756 27.528 ;
     RECT  50.677 27.528 51.804 27.648 ;
     RECT  50.677 27.648 51.756 27.672 ;
     RECT  50.677 27.672 51.804 27.792 ;
     RECT  50.677 27.792 51.756 27.816 ;
     RECT  50.677 27.816 51.804 27.936 ;
     RECT  50.677 27.936 51.756 27.96 ;
     RECT  50.677 27.96 51.804 28.08 ;
     RECT  50.677 28.08 51.756 28.104 ;
     RECT  50.677 28.104 51.804 28.224 ;
     RECT  50.677 28.224 51.756 28.248 ;
     RECT  50.137 29.52 51.756 29.544 ;
     RECT  50.137 29.544 51.804 29.664 ;
     RECT  50.137 29.664 51.756 29.688 ;
     RECT  50.137 29.688 51.804 29.808 ;
     RECT  50.137 29.808 51.756 29.832 ;
     RECT  50.137 29.832 51.804 29.952 ;
     RECT  50.137 29.952 51.756 29.976 ;
     RECT  50.137 29.976 51.804 30.096 ;
     RECT  50.137 30.096 51.756 30.12 ;
     RECT  50.137 30.12 51.804 30.24 ;
     RECT  50.137 30.24 51.756 30.264 ;
     RECT  50.137 30.264 51.804 30.384 ;
     RECT  50.137 30.384 51.756 30.408 ;
     RECT  50.137 30.408 51.804 30.528 ;
     RECT  50.137 30.528 51.756 30.552 ;
     RECT  50.137 30.552 51.804 30.672 ;
     RECT  50.137 30.672 51.756 30.696 ;
     RECT  50.137 30.696 51.804 30.816 ;
     RECT  50.137 30.816 51.756 30.84 ;
     RECT  50.137 30.84 51.804 30.96 ;
     RECT  50.137 30.96 51.756 30.984 ;
     RECT  50.137 30.984 51.804 31.104 ;
     RECT  50.137 31.104 51.756 31.128 ;
     RECT  50.137 31.128 51.804 31.248 ;
     RECT  50.137 31.248 51.756 31.272 ;
     RECT  50.137 31.272 51.804 31.392 ;
     RECT  50.137 31.392 51.756 31.416 ;
     RECT  50.137 31.416 51.804 31.536 ;
     RECT  50.137 31.536 51.756 31.56 ;
     RECT  50.137 31.56 51.804 31.68 ;
     RECT  50.137 31.68 51.756 31.704 ;
     RECT  50.137 31.704 51.804 31.824 ;
     RECT  50.137 31.824 51.756 31.848 ;
     RECT  50.137 31.848 51.804 31.968 ;
     RECT  50.137 31.968 51.756 31.992 ;
     RECT  50.137 31.992 51.804 32.112 ;
     RECT  50.137 32.112 51.756 32.136 ;
     RECT  50.137 32.136 51.804 32.256 ;
     RECT  50.137 32.256 51.756 32.28 ;
     RECT  50.137 32.28 51.804 32.4 ;
     RECT  50.137 32.4 51.756 32.424 ;
     RECT  50.137 32.424 51.804 32.544 ;
     RECT  50.137 32.544 51.756 32.568 ;
     RECT  50.137 32.568 51.804 32.688 ;
     RECT  50.137 32.688 51.756 32.712 ;
     RECT  50.137 32.712 51.804 32.832 ;
     RECT  50.137 32.832 51.756 32.856 ;
     RECT  50.137 32.856 51.804 32.976 ;
     RECT  50.137 32.976 51.756 33 ;
     RECT  50.137 33 51.804 33.12 ;
     RECT  50.137 33.12 51.756 33.144 ;
     RECT  50.137 33.144 51.804 33.264 ;
     RECT  50.137 33.264 51.756 33.288 ;
     RECT  50.137 33.288 51.804 33.408 ;
     RECT  50.137 33.408 51.756 33.432 ;
     RECT  50.137 33.432 51.804 33.552 ;
     RECT  50.137 33.552 51.756 33.576 ;
     RECT  50.137 33.576 51.804 33.696 ;
     RECT  50.137 33.696 51.756 33.72 ;
     RECT  50.137 33.72 51.804 33.84 ;
     RECT  50.137 33.84 51.756 33.864 ;
     RECT  50.137 33.864 51.804 33.984 ;
     RECT  50.137 33.984 51.756 34.008 ;
     RECT  50.677 38.736 51.756 38.76 ;
     RECT  50.677 38.76 51.804 38.88 ;
     RECT  50.677 38.88 51.756 38.904 ;
     RECT  50.677 38.904 51.804 39.024 ;
     RECT  50.677 39.024 51.756 39.048 ;
     RECT  50.677 39.048 51.804 39.168 ;
     RECT  50.677 39.168 51.756 39.192 ;
     RECT  50.677 39.192 51.804 39.312 ;
     RECT  50.677 39.312 51.756 39.336 ;
     RECT  50.677 39.336 51.804 39.456 ;
     RECT  50.677 39.456 51.756 39.48 ;
     RECT  50.677 39.48 51.804 39.6 ;
     RECT  50.677 39.6 51.756 39.624 ;
     RECT  50.677 39.624 51.804 39.744 ;
     RECT  50.677 39.744 51.756 39.768 ;
     RECT  50.677 39.768 51.804 39.888 ;
     RECT  50.677 39.888 51.756 39.912 ;
     RECT  50.677 39.912 51.804 40.032 ;
     RECT  50.677 40.032 51.756 40.056 ;
     RECT  50.677 40.056 51.804 40.176 ;
     RECT  50.677 40.176 51.756 40.2 ;
     RECT  50.677 40.2 51.804 40.32 ;
     RECT  50.677 40.32 51.756 40.344 ;
     RECT  50.677 40.344 51.804 40.464 ;
     RECT  50.677 40.464 51.756 40.488 ;
     RECT  50.677 40.488 51.804 40.608 ;
     RECT  50.677 40.608 51.756 40.632 ;
     RECT  50.677 40.632 51.804 40.752 ;
     RECT  50.677 40.752 51.756 40.776 ;
     RECT  50.677 40.776 51.804 40.896 ;
     RECT  50.677 40.896 51.756 40.92 ;
     RECT  50.677 40.92 51.804 41.04 ;
     RECT  50.677 41.04 51.756 41.064 ;
     RECT  50.677 41.064 51.804 41.184 ;
     RECT  50.677 41.184 51.756 41.208 ;
     RECT  50.677 41.208 51.804 41.328 ;
     RECT  50.677 41.328 51.756 41.352 ;
     RECT  50.677 41.352 51.804 41.472 ;
     RECT  50.677 41.472 51.756 41.496 ;
     RECT  50.677 41.496 51.804 41.616 ;
     RECT  50.677 41.616 51.756 41.64 ;
     RECT  50.677 41.64 51.804 41.76 ;
     RECT  50.677 41.76 51.756 41.784 ;
     RECT  50.677 41.784 51.804 41.904 ;
     RECT  50.677 41.904 51.756 41.928 ;
     RECT  50.677 41.928 51.804 42.048 ;
     RECT  50.677 42.048 51.756 42.072 ;
     RECT  50.677 42.072 51.804 42.192 ;
     RECT  50.677 42.192 51.756 42.216 ;
     RECT  50.677 42.216 51.804 42.336 ;
     RECT  50.677 42.336 51.756 42.36 ;
     RECT  50.677 42.36 51.804 42.48 ;
     RECT  50.677 42.48 51.756 42.504 ;
     RECT  50.677 42.504 51.804 42.624 ;
     RECT  50.677 42.624 51.756 42.648 ;
     RECT  50.677 42.648 51.804 42.768 ;
     RECT  50.677 42.768 51.756 42.792 ;
     RECT  50.677 42.792 51.804 42.912 ;
     RECT  50.677 42.912 51.756 42.936 ;
     RECT  50.677 42.936 51.804 43.056 ;
     RECT  50.677 43.056 51.756 43.08 ;
     RECT  50.677 43.08 51.804 43.2 ;
     RECT  50.677 43.2 51.756 43.224 ;
     RECT  50.677 43.224 51.804 43.344 ;
     RECT  50.677 43.344 51.756 43.368 ;
     RECT  50.677 43.368 51.804 43.488 ;
     RECT  50.677 43.488 51.756 43.512 ;
     RECT  50.677 43.512 51.804 43.632 ;
     RECT  50.677 43.632 51.756 43.656 ;
     RECT  50.677 43.656 51.804 43.776 ;
     RECT  50.677 43.776 51.756 43.8 ;
     RECT  50.677 43.8 51.804 43.92 ;
     RECT  50.677 43.92 51.756 43.944 ;
     RECT  50.677 43.944 51.804 44.064 ;
     RECT  50.677 44.064 51.756 44.088 ;
     RECT  50.677 44.088 51.804 44.208 ;
     RECT  50.677 44.208 51.756 44.232 ;
     RECT  50.677 44.232 51.804 44.352 ;
     RECT  50.677 44.352 51.756 44.376 ;
     RECT  50.677 44.376 51.804 44.496 ;
     RECT  50.677 44.496 51.756 44.52 ;
     RECT  50.677 44.52 51.804 44.64 ;
     RECT  50.677 44.64 51.756 44.664 ;
     RECT  50.677 44.664 51.804 44.784 ;
     RECT  50.677 44.784 51.756 44.808 ;
     RECT  50.677 44.808 51.804 44.928 ;
     RECT  50.677 44.928 51.756 44.952 ;
     RECT  50.677 44.952 51.804 45.072 ;
     RECT  50.677 45.072 51.756 45.096 ;
     RECT  50.677 45.096 51.804 45.216 ;
     RECT  50.677 45.216 51.756 45.24 ;
     RECT  50.677 45.24 51.804 45.36 ;
     RECT  50.677 45.36 51.756 45.384 ;
     RECT  50.677 45.384 51.804 45.504 ;
     RECT  50.677 45.504 51.756 45.528 ;
     RECT  50.677 45.528 51.804 45.648 ;
     RECT  50.677 45.648 51.756 45.672 ;
     RECT  50.677 45.672 51.804 45.792 ;
     RECT  50.677 45.792 51.756 45.816 ;
     RECT  50.677 45.816 51.804 45.936 ;
     RECT  50.677 45.936 51.756 45.96 ;
     RECT  50.677 45.96 51.804 46.08 ;
     RECT  50.677 46.08 51.756 46.104 ;
     RECT  50.677 46.104 51.804 46.224 ;
     RECT  50.677 46.224 51.756 46.248 ;
     RECT  50.677 46.248 51.804 46.368 ;
     RECT  50.677 46.368 51.756 46.392 ;
     RECT  50.677 46.392 51.804 46.512 ;
     RECT  50.677 46.512 51.756 46.536 ;
     RECT  50.677 46.536 51.804 46.656 ;
     RECT  50.677 46.656 51.756 46.68 ;
     RECT  50.677 46.68 51.804 46.8 ;
     RECT  50.677 46.8 51.756 46.824 ;
     RECT  50.677 46.824 51.804 46.944 ;
     RECT  50.677 46.944 51.756 46.968 ;
     RECT  50.677 46.968 51.804 47.088 ;
     RECT  50.677 47.088 51.756 47.112 ;
     RECT  50.677 47.112 51.804 47.232 ;
     RECT  50.677 47.232 51.756 47.256 ;
     RECT  50.677 47.256 51.804 47.376 ;
     RECT  50.677 47.376 51.756 47.4 ;
     RECT  50.677 47.4 51.804 47.52 ;
     RECT  50.677 47.52 51.756 47.544 ;
     RECT  50.677 47.544 51.804 47.664 ;
     RECT  50.677 47.664 51.756 47.688 ;
     RECT  50.677 47.688 51.804 47.808 ;
     RECT  50.677 47.808 51.756 47.832 ;
    LAYER M5 ;
     RECT  5.352 0.016 5.472 0.084 ;
     RECT  5.496 0.016 5.616 0.084 ;
     RECT  5.64 0.016 5.76 0.084 ;
     RECT  5.784 0.016 5.904 0.084 ;
     RECT  5.928 0.016 6.048 0.084 ;
     RECT  6.072 0.016 6.192 0.084 ;
     RECT  6.216 0.016 6.336 0.084 ;
     RECT  6.36 0.016 6.48 0.084 ;
     RECT  6.504 0.016 6.624 0.084 ;
     RECT  6.648 0.016 6.768 0.084 ;
     RECT  6.792 0.016 6.912 0.084 ;
     RECT  6.936 0.016 7.056 0.084 ;
     RECT  7.08 0.016 7.2 0.084 ;
     RECT  7.224 0.016 7.344 0.084 ;
     RECT  7.368 0.016 7.488 0.084 ;
     RECT  7.512 0.016 7.632 0.084 ;
     RECT  7.656 0.016 7.776 0.084 ;
     RECT  7.8 0.016 7.92 0.084 ;
     RECT  7.944 0.016 8.064 0.084 ;
     RECT  8.088 0.016 8.208 0.084 ;
     RECT  8.232 0.016 8.352 0.084 ;
     RECT  8.376 0.016 8.496 0.084 ;
     RECT  8.52 0.016 8.64 0.084 ;
     RECT  8.664 0.016 8.784 0.084 ;
     RECT  8.808 0.016 8.928 0.084 ;
     RECT  8.952 0.016 9.072 0.084 ;
     RECT  9.096 0.016 9.216 0.084 ;
     RECT  9.24 0.016 9.36 0.084 ;
     RECT  9.384 0.016 9.504 0.084 ;
     RECT  9.528 0.016 9.648 0.084 ;
     RECT  9.672 0.016 9.792 0.084 ;
     RECT  9.816 0.016 9.936 0.084 ;
     RECT  9.96 0.016 10.08 0.084 ;
     RECT  10.104 0.016 10.224 0.084 ;
     RECT  10.248 0.016 10.368 0.084 ;
     RECT  10.392 0.016 10.512 0.084 ;
     RECT  10.536 0.016 10.656 0.084 ;
     RECT  10.68 0.016 10.8 0.084 ;
     RECT  10.824 0.016 10.944 0.084 ;
     RECT  10.968 0.016 11.088 0.084 ;
     RECT  11.112 0.016 11.232 0.084 ;
     RECT  11.256 0.016 11.376 0.084 ;
     RECT  11.4 0.016 11.52 0.084 ;
     RECT  11.544 0.016 11.664 0.084 ;
     RECT  11.688 0.016 11.808 0.084 ;
     RECT  11.832 0.016 11.952 0.084 ;
     RECT  11.976 0.016 12.096 0.084 ;
     RECT  12.12 0.016 12.24 0.084 ;
     RECT  12.264 0.016 12.384 0.084 ;
     RECT  12.408 0.016 12.528 0.084 ;
     RECT  12.552 0.016 12.672 0.084 ;
     RECT  12.696 0.016 12.816 0.084 ;
     RECT  12.84 0.016 12.96 0.084 ;
     RECT  12.984 0.016 13.104 0.084 ;
     RECT  13.128 0.016 13.248 0.084 ;
     RECT  13.272 0.016 13.392 0.084 ;
     RECT  13.416 0.016 13.536 0.084 ;
     RECT  13.56 0.016 13.68 0.084 ;
     RECT  13.704 0.016 13.824 0.084 ;
     RECT  13.848 0.016 13.968 0.084 ;
     RECT  13.992 0.016 14.112 0.084 ;
     RECT  14.136 0.016 14.256 0.084 ;
     RECT  14.28 0.016 14.4 0.084 ;
     RECT  14.424 0.016 14.544 0.084 ;
     RECT  14.568 0.016 14.688 0.084 ;
     RECT  14.712 0.016 14.832 0.084 ;
     RECT  14.856 0.016 14.976 0.084 ;
     RECT  15 0.016 15.12 0.084 ;
     RECT  15.144 0.016 15.264 0.084 ;
     RECT  15.288 0.016 15.408 0.084 ;
     RECT  15.432 0.016 15.552 0.084 ;
     RECT  15.576 0.016 15.696 0.084 ;
     RECT  15.72 0.016 15.84 0.084 ;
     RECT  15.864 0.016 15.984 0.084 ;
     RECT  16.008 0.016 16.128 0.084 ;
     RECT  16.152 0.016 16.272 0.084 ;
     RECT  16.296 0.016 16.416 0.084 ;
     RECT  16.44 0.016 16.56 0.084 ;
     RECT  16.584 0.016 16.704 0.084 ;
     RECT  16.728 0.016 16.848 0.084 ;
     RECT  16.872 0.016 16.992 0.084 ;
     RECT  17.016 0.016 17.136 0.084 ;
     RECT  17.16 0.016 17.28 0.084 ;
     RECT  17.304 0.016 17.424 0.084 ;
     RECT  17.448 0.016 17.568 0.084 ;
     RECT  17.592 0.016 17.712 0.084 ;
     RECT  17.736 0.016 17.856 0.084 ;
     RECT  17.88 0.016 18 0.084 ;
     RECT  18.024 0.016 18.144 0.084 ;
     RECT  18.168 0.016 18.288 0.084 ;
     RECT  18.312 0.016 18.432 0.084 ;
     RECT  18.456 0.016 18.576 0.084 ;
     RECT  18.6 0.016 18.72 0.084 ;
     RECT  18.744 0.016 18.864 0.084 ;
     RECT  18.888 0.016 19.008 0.084 ;
     RECT  19.032 0.016 19.152 0.084 ;
     RECT  19.176 0.016 19.296 0.084 ;
     RECT  19.32 0.016 19.44 0.084 ;
     RECT  19.464 0.016 19.584 0.084 ;
     RECT  19.608 0.016 19.728 0.084 ;
     RECT  19.752 0.016 19.872 0.084 ;
     RECT  19.896 0.016 20.016 0.084 ;
     RECT  20.04 0.016 20.16 0.084 ;
     RECT  20.184 0.016 20.304 0.084 ;
     RECT  20.328 0.016 20.448 0.084 ;
     RECT  20.472 0.016 20.592 0.084 ;
     RECT  20.616 0.016 20.736 0.084 ;
     RECT  20.76 0.016 20.88 0.084 ;
     RECT  20.904 0.016 21.024 0.084 ;
     RECT  21.048 0.016 21.168 0.084 ;
     RECT  21.192 0.016 21.312 0.084 ;
     RECT  21.336 0.016 21.456 0.084 ;
     RECT  21.48 0.016 21.6 0.084 ;
     RECT  21.624 0.016 21.744 0.084 ;
     RECT  21.768 0.016 21.888 0.084 ;
     RECT  21.912 0.016 22.032 0.084 ;
     RECT  22.056 0.016 22.176 0.084 ;
     RECT  22.2 0.016 22.32 0.084 ;
     RECT  22.344 0.016 22.464 0.084 ;
     RECT  22.488 0.016 22.608 0.084 ;
     RECT  22.632 0.016 22.752 0.084 ;
     RECT  22.776 0.016 22.896 0.084 ;
     RECT  22.92 0.016 23.04 0.084 ;
     RECT  23.064 0.016 23.184 0.084 ;
     RECT  23.208 0.016 23.328 0.084 ;
     RECT  23.352 0.016 23.472 0.084 ;
     RECT  23.496 0.016 23.616 0.084 ;
     RECT  23.64 0.016 23.76 0.084 ;
     RECT  23.784 0.016 23.904 0.084 ;
     RECT  23.928 0.016 24.048 0.084 ;
     RECT  24.072 0.016 24.192 0.084 ;
     RECT  24.216 0.016 24.336 0.084 ;
     RECT  24.36 0.016 24.48 0.084 ;
     RECT  24.504 0.016 24.624 0.084 ;
     RECT  24.648 0.016 24.768 0.084 ;
     RECT  24.792 0.016 24.912 0.084 ;
     RECT  24.936 0.016 25.056 0.084 ;
     RECT  25.08 0.016 25.2 0.084 ;
     RECT  25.224 0.016 25.344 0.084 ;
     RECT  25.368 0.016 25.488 0.084 ;
     RECT  25.512 0.016 25.632 0.084 ;
     RECT  25.656 0.016 25.776 0.084 ;
     RECT  25.8 0.016 25.92 0.084 ;
     RECT  25.944 0.016 26.064 0.084 ;
     RECT  26.088 0.016 26.208 0.084 ;
     RECT  26.232 0.016 26.352 0.084 ;
     RECT  26.376 0.016 26.496 0.084 ;
     RECT  26.52 0.016 26.64 0.084 ;
     RECT  26.664 0.016 26.784 0.084 ;
     RECT  26.808 0.016 26.928 0.084 ;
     RECT  26.952 0.016 27.072 0.084 ;
     RECT  27.096 0.016 27.216 0.084 ;
     RECT  27.24 0.016 27.36 0.084 ;
     RECT  27.384 0.016 27.504 0.084 ;
     RECT  27.528 0.016 27.648 0.084 ;
     RECT  27.672 0.016 27.792 0.084 ;
     RECT  27.816 0.016 27.936 0.084 ;
     RECT  27.96 0.016 28.08 0.084 ;
     RECT  28.104 0.016 28.224 0.084 ;
     RECT  5.328 0.084 28.248 1.763 ;
     RECT  29.544 0.016 29.664 0.084 ;
     RECT  29.688 0.016 29.808 0.084 ;
     RECT  29.832 0.016 29.952 0.084 ;
     RECT  29.976 0.016 30.096 0.084 ;
     RECT  30.12 0.016 30.24 0.084 ;
     RECT  30.264 0.016 30.384 0.084 ;
     RECT  30.408 0.016 30.528 0.084 ;
     RECT  30.552 0.016 30.672 0.084 ;
     RECT  30.696 0.016 30.816 0.084 ;
     RECT  30.84 0.016 30.96 0.084 ;
     RECT  30.984 0.016 31.104 0.084 ;
     RECT  31.128 0.016 31.248 0.084 ;
     RECT  31.272 0.016 31.392 0.084 ;
     RECT  31.416 0.016 31.536 0.084 ;
     RECT  31.56 0.016 31.68 0.084 ;
     RECT  31.704 0.016 31.824 0.084 ;
     RECT  31.848 0.016 31.968 0.084 ;
     RECT  31.992 0.016 32.112 0.084 ;
     RECT  32.136 0.016 32.256 0.084 ;
     RECT  32.28 0.016 32.4 0.084 ;
     RECT  32.424 0.016 32.544 0.084 ;
     RECT  32.568 0.016 32.688 0.084 ;
     RECT  32.712 0.016 32.832 0.084 ;
     RECT  32.856 0.016 32.976 0.084 ;
     RECT  33 0.016 33.12 0.084 ;
     RECT  33.144 0.016 33.264 0.084 ;
     RECT  33.288 0.016 33.408 0.084 ;
     RECT  33.432 0.016 33.552 0.084 ;
     RECT  33.576 0.016 33.696 0.084 ;
     RECT  33.72 0.016 33.84 0.084 ;
     RECT  33.864 0.016 33.984 0.084 ;
     RECT  34.008 0.016 34.128 0.084 ;
     RECT  34.152 0.016 34.272 0.084 ;
     RECT  34.296 0.016 34.416 0.084 ;
     RECT  34.44 0.016 34.56 0.084 ;
     RECT  34.584 0.016 34.704 0.084 ;
     RECT  34.728 0.016 34.848 0.084 ;
     RECT  34.872 0.016 34.992 0.084 ;
     RECT  35.016 0.016 35.136 0.084 ;
     RECT  35.16 0.016 35.28 0.084 ;
     RECT  35.304 0.016 35.424 0.084 ;
     RECT  35.448 0.016 35.568 0.084 ;
     RECT  35.592 0.016 35.712 0.084 ;
     RECT  35.736 0.016 35.856 0.084 ;
     RECT  35.88 0.016 36 0.084 ;
     RECT  36.024 0.016 36.144 0.084 ;
     RECT  36.168 0.016 36.288 0.084 ;
     RECT  36.312 0.016 36.432 0.084 ;
     RECT  36.456 0.016 36.576 0.084 ;
     RECT  36.6 0.016 36.72 0.084 ;
     RECT  36.744 0.016 36.864 0.084 ;
     RECT  36.888 0.016 37.008 0.084 ;
     RECT  37.032 0.016 37.152 0.084 ;
     RECT  37.176 0.016 37.296 0.084 ;
     RECT  37.32 0.016 37.44 0.084 ;
     RECT  37.464 0.016 37.584 0.084 ;
     RECT  37.608 0.016 37.728 0.084 ;
     RECT  37.752 0.016 37.872 0.084 ;
     RECT  37.896 0.016 38.016 0.084 ;
     RECT  38.04 0.016 38.16 0.084 ;
     RECT  38.184 0.016 38.304 0.084 ;
     RECT  38.328 0.016 38.448 0.084 ;
     RECT  38.472 0.016 38.592 0.084 ;
     RECT  38.616 0.016 38.736 0.084 ;
     RECT  38.76 0.016 38.88 0.084 ;
     RECT  38.904 0.016 39.024 0.084 ;
     RECT  39.048 0.016 39.168 0.084 ;
     RECT  39.192 0.016 39.312 0.084 ;
     RECT  39.336 0.016 39.456 0.084 ;
     RECT  39.48 0.016 39.6 0.084 ;
     RECT  39.624 0.016 39.744 0.084 ;
     RECT  39.768 0.016 39.888 0.084 ;
     RECT  39.912 0.016 40.032 0.084 ;
     RECT  40.056 0.016 40.176 0.084 ;
     RECT  40.2 0.016 40.32 0.084 ;
     RECT  40.344 0.016 40.464 0.084 ;
     RECT  40.488 0.016 40.608 0.084 ;
     RECT  40.632 0.016 40.752 0.084 ;
     RECT  40.776 0.016 40.896 0.084 ;
     RECT  40.92 0.016 41.04 0.084 ;
     RECT  41.064 0.016 41.184 0.084 ;
     RECT  41.208 0.016 41.328 0.084 ;
     RECT  41.352 0.016 41.472 0.084 ;
     RECT  41.496 0.016 41.616 0.084 ;
     RECT  41.64 0.016 41.76 0.084 ;
     RECT  41.784 0.016 41.904 0.084 ;
     RECT  41.928 0.016 42.048 0.084 ;
     RECT  42.072 0.016 42.192 0.084 ;
     RECT  42.216 0.016 42.336 0.084 ;
     RECT  42.36 0.016 42.48 0.084 ;
     RECT  42.504 0.016 42.624 0.084 ;
     RECT  42.648 0.016 42.768 0.084 ;
     RECT  42.792 0.016 42.912 0.084 ;
     RECT  42.936 0.016 43.056 0.084 ;
     RECT  43.08 0.016 43.2 0.084 ;
     RECT  43.224 0.016 43.344 0.084 ;
     RECT  43.368 0.016 43.488 0.084 ;
     RECT  43.512 0.016 43.632 0.084 ;
     RECT  43.656 0.016 43.776 0.084 ;
     RECT  43.8 0.016 43.92 0.084 ;
     RECT  43.944 0.016 44.064 0.084 ;
     RECT  44.088 0.016 44.208 0.084 ;
     RECT  44.232 0.016 44.352 0.084 ;
     RECT  44.376 0.016 44.496 0.084 ;
     RECT  44.52 0.016 44.64 0.084 ;
     RECT  44.664 0.016 44.784 0.084 ;
     RECT  44.808 0.016 44.928 0.084 ;
     RECT  44.952 0.016 45.072 0.084 ;
     RECT  45.096 0.016 45.216 0.084 ;
     RECT  45.24 0.016 45.36 0.084 ;
     RECT  45.384 0.016 45.504 0.084 ;
     RECT  45.528 0.016 45.648 0.084 ;
     RECT  45.672 0.016 45.792 0.084 ;
     RECT  45.816 0.016 45.936 0.084 ;
     RECT  45.96 0.016 46.08 0.084 ;
     RECT  46.104 0.016 46.224 0.084 ;
     RECT  46.248 0.016 46.368 0.084 ;
     RECT  46.392 0.016 46.512 0.084 ;
     RECT  46.536 0.016 46.656 0.084 ;
     RECT  46.68 0.016 46.8 0.084 ;
     RECT  46.824 0.016 46.944 0.084 ;
     RECT  46.968 0.016 47.088 0.084 ;
     RECT  47.112 0.016 47.232 0.084 ;
     RECT  47.256 0.016 47.376 0.084 ;
     RECT  47.4 0.016 47.52 0.084 ;
     RECT  47.544 0.016 47.664 0.084 ;
     RECT  47.688 0.016 47.808 0.084 ;
     RECT  47.832 0.016 47.952 0.084 ;
     RECT  47.976 0.016 48.096 0.084 ;
     RECT  48.12 0.016 48.24 0.084 ;
     RECT  48.264 0.016 48.384 0.084 ;
     RECT  48.408 0.016 48.528 0.084 ;
     RECT  29.52 0.084 48.552 1.763 ;
     RECT  5.472 1.763 20.616 1.811 ;
     RECT  21.888 1.763 28.248 1.811 ;
     RECT  29.52 1.763 36.888 1.811 ;
     RECT  38.016 1.763 48.408 1.811 ;
     RECT  9.504 1.811 20.616 1.859 ;
     RECT  21.888 1.811 24.792 1.859 ;
     RECT  26.064 1.811 28.248 1.859 ;
     RECT  38.88 1.811 39.192 1.859 ;
     RECT  48.384 1.811 48.408 1.859 ;
     RECT  11.376 1.859 13.512 1.907 ;
     RECT  14.544 1.859 20.616 1.907 ;
     RECT  26.64 1.859 27.672 1.907 ;
     RECT  40.176 1.811 46.968 1.907 ;
     RECT  40.176 1.907 45.912 2.051 ;
     RECT  29.52 1.811 30.552 2.137 ;
     RECT  2.4 2.137 2.52 2.151 ;
     RECT  32.256 1.811 36.6 2.195 ;
     RECT  40.2 2.051 45.912 2.243 ;
     RECT  5.472 1.811 8.112 2.291 ;
     RECT  9.792 1.859 10.392 2.291 ;
     RECT  11.376 1.907 11.544 2.291 ;
     RECT  14.544 1.907 17.304 2.291 ;
     RECT  18.6 1.907 20.616 2.291 ;
     RECT  21.888 1.859 22.488 2.291 ;
     RECT  29.4 2.137 30.552 2.291 ;
     RECT  32.256 2.195 36.456 2.291 ;
     RECT  40.2 2.243 43.656 2.291 ;
     RECT  44.64 2.243 45.912 2.291 ;
     RECT  46.944 1.907 46.968 2.291 ;
     RECT  11.376 2.291 11.4 2.339 ;
     RECT  32.256 2.291 32.856 2.821 ;
     RECT  10.368 2.291 10.392 2.867 ;
     RECT  12.528 1.907 13.512 2.867 ;
     RECT  15.984 2.291 16.008 2.867 ;
     RECT  17.136 2.291 17.16 2.867 ;
     RECT  20.592 2.291 20.616 2.867 ;
     RECT  22.464 2.291 22.488 2.867 ;
     RECT  18.6 2.291 19.032 3.301 ;
     RECT  41.952 2.291 41.976 3.397 ;
     RECT  34.8 2.291 35.112 3.541 ;
     RECT  31.872 2.821 32.856 3.587 ;
     RECT  47.904 2.821 47.928 3.827 ;
     RECT  32.448 3.587 32.856 4.115 ;
     RECT  7.8 2.291 8.112 5.029 ;
     RECT  32.688 4.115 32.856 5.029 ;
     RECT  32.688 5.029 33.624 5.077 ;
     RECT  34.8 3.541 35.208 5.077 ;
     RECT  40.2 2.291 40.68 5.077 ;
     RECT  41.904 3.397 41.976 5.077 ;
     RECT  13.2 2.867 13.512 5.173 ;
     RECT  17.616 3.301 19.032 5.173 ;
     RECT  29.4 2.291 29.712 5.173 ;
     RECT  37.296 4.405 37.32 5.173 ;
     RECT  48.192 4.117 48.216 5.267 ;
     RECT  24 1.859 24.312 5.461 ;
     RECT  45.6 2.291 45.912 5.557 ;
     RECT  7.8 5.029 9.096 5.747 ;
     RECT  16.56 5.029 16.584 5.747 ;
     RECT  26.496 3.157 26.52 5.747 ;
     RECT  40.2 5.077 41.976 5.747 ;
     RECT  43.536 3.925 43.56 5.747 ;
     RECT  36.72 5.173 37.32 5.893 ;
     RECT  40.2 5.747 40.68 6.181 ;
     RECT  29.4 5.173 30.456 6.229 ;
     RECT  12.528 5.173 13.512 6.275 ;
     RECT  17.616 5.173 19.32 6.323 ;
     RECT  41.904 5.747 41.976 6.709 ;
     RECT  24 5.461 24.408 6.805 ;
     RECT  39.36 6.181 40.68 6.805 ;
     RECT  29.4 6.229 30.744 6.851 ;
     RECT  21.312 5.461 21.336 6.899 ;
     RECT  36.432 5.893 37.752 6.899 ;
     RECT  39.36 6.805 40.872 7.043 ;
     RECT  32.688 5.077 35.208 7.093 ;
     RECT  41.904 6.709 42.024 7.189 ;
     RECT  41.904 7.189 42.168 7.235 ;
     RECT  45.6 5.557 46.344 7.333 ;
     RECT  11.376 6.229 11.4 7.381 ;
     RECT  9.6 6.805 9.624 7.427 ;
     RECT  11.28 7.381 11.4 7.475 ;
     RECT  25.92 6.229 25.944 7.475 ;
     RECT  36.72 6.899 37.752 7.717 ;
     RECT  11.28 7.475 11.304 7.907 ;
     RECT  13.2 6.275 13.512 7.957 ;
     RECT  23.328 6.805 24.408 7.957 ;
     RECT  29.4 6.851 30.552 8.147 ;
     RECT  23.328 7.957 24.552 8.293 ;
     RECT  32.592 7.093 35.208 8.435 ;
     RECT  13.2 7.957 13.608 8.437 ;
     RECT  32.688 8.435 35.208 8.437 ;
     RECT  36.72 7.717 38.376 8.437 ;
     RECT  27.888 6.805 27.912 8.579 ;
     RECT  39.84 7.043 40.872 8.675 ;
     RECT  42.144 7.235 42.168 8.915 ;
     RECT  13.2 8.437 13.656 8.965 ;
     RECT  40.2 8.675 40.872 9.109 ;
     RECT  32.688 8.437 38.376 9.203 ;
     RECT  33.84 9.203 38.376 9.253 ;
     RECT  23.088 8.293 24.552 9.539 ;
     RECT  40.2 9.109 41.688 9.635 ;
     RECT  23.088 9.539 24.408 9.731 ;
     RECT  29.4 8.147 29.712 9.973 ;
     RECT  29.4 9.973 29.832 10.115 ;
     RECT  13.104 8.965 14.376 10.307 ;
     RECT  33.84 9.253 39.096 10.451 ;
     RECT  23.088 9.731 24.312 10.595 ;
     RECT  21.36 10.213 21.384 10.597 ;
     RECT  28.224 9.829 28.248 10.789 ;
     RECT  32.688 9.203 32.856 10.789 ;
     RECT  32.448 10.789 32.856 10.837 ;
     RECT  33.84 10.451 35.304 10.883 ;
     RECT  43.584 9.925 43.608 10.883 ;
     RECT  36.48 10.451 39.096 10.931 ;
     RECT  16.08 10.261 16.104 11.171 ;
     RECT  45.6 7.333 46.392 11.171 ;
     RECT  13.104 10.307 13.656 11.413 ;
     RECT  34.224 10.883 35.304 11.413 ;
     RECT  36.48 10.931 37.32 11.413 ;
     RECT  38.4 10.931 39.096 11.459 ;
     RECT  27.936 10.789 28.248 11.555 ;
     RECT  34.224 11.413 37.32 11.843 ;
     RECT  29.4 10.115 29.712 11.941 ;
     RECT  29.4 11.941 30.648 12.085 ;
     RECT  31.92 10.837 32.856 12.085 ;
     RECT  23.184 10.595 24.312 12.179 ;
     RECT  34.224 11.843 37.032 12.179 ;
     RECT  20.544 10.597 21.384 12.227 ;
     RECT  29.4 12.085 32.856 12.227 ;
     RECT  17.424 9.973 17.448 12.325 ;
     RECT  18.432 6.323 19.32 12.325 ;
     RECT  45.6 11.171 45.912 12.517 ;
     RECT  28.224 11.555 28.248 12.659 ;
     RECT  31.872 12.227 32.856 12.707 ;
     RECT  10.848 11.413 10.872 12.755 ;
     RECT  34.224 12.179 35.688 12.755 ;
     RECT  29.4 12.227 30.84 12.803 ;
     RECT  26.784 11.941 26.808 13.139 ;
     RECT  31.872 12.707 32.712 13.139 ;
     RECT  17.424 12.325 19.32 13.331 ;
     RECT  45.6 12.517 46.2 13.331 ;
     RECT  29.4 12.803 30.648 13.573 ;
     RECT  36.816 12.179 37.032 13.621 ;
     RECT  18.384 13.331 19.32 13.667 ;
     RECT  13.104 11.413 14.28 13.715 ;
     RECT  20.544 12.227 21.048 13.811 ;
     RECT  28.416 13.573 30.648 13.811 ;
     RECT  22.8 12.181 22.824 14.339 ;
     RECT  36.768 13.621 37.032 14.627 ;
     RECT  18.384 13.667 19.032 14.675 ;
     RECT  32.688 13.139 32.712 14.773 ;
     RECT  36.816 14.627 37.032 14.821 ;
     RECT  38.016 13.861 38.04 14.821 ;
     RECT  24 12.179 24.312 15.301 ;
     RECT  13.104 13.715 13.656 15.349 ;
     RECT  39.072 11.459 39.096 15.349 ;
     RECT  40.2 9.635 40.872 15.349 ;
     RECT  28.416 13.811 29.712 15.397 ;
     RECT  27.984 15.397 29.712 15.443 ;
     RECT  36.816 14.821 38.04 15.589 ;
     RECT  39.072 15.349 40.872 15.589 ;
     RECT  36.816 15.589 40.872 16.501 ;
     RECT  23.376 15.301 24.312 16.547 ;
     RECT  27.984 15.443 28.008 16.787 ;
     RECT  13.104 15.349 14.28 16.835 ;
     RECT  10.272 15.877 10.296 17.029 ;
     RECT  31.344 15.829 31.368 17.075 ;
     RECT  32.688 14.773 33.048 17.123 ;
     RECT  34.224 12.755 35.304 17.123 ;
     RECT  48.96 16.837 48.984 17.123 ;
     RECT  36.768 16.501 40.872 17.269 ;
     RECT  25.68 15.349 25.704 17.315 ;
     RECT  10.272 17.029 10.728 17.413 ;
     RECT  32.688 17.123 32.712 17.605 ;
     RECT  44.256 11.125 44.28 17.605 ;
     RECT  10.176 17.413 10.728 17.987 ;
     RECT  12.096 8.581 12.12 17.989 ;
     RECT  13.2 16.835 14.28 17.989 ;
     RECT  10.704 17.987 10.728 18.035 ;
     RECT  26.928 13.621 26.952 18.181 ;
     RECT  45.6 13.331 45.912 18.181 ;
     RECT  43.68 17.605 44.28 18.227 ;
     RECT  12.096 17.989 14.28 18.419 ;
     RECT  31.728 17.605 32.712 18.709 ;
     RECT  31.728 18.709 33.096 18.755 ;
     RECT  26.928 18.181 27.528 18.851 ;
     RECT  43.68 18.227 43.704 18.851 ;
     RECT  24 16.547 24.312 19.045 ;
     RECT  32.688 18.755 33.096 19.237 ;
     RECT  34.224 17.123 35.208 19.237 ;
     RECT  36.72 17.269 40.872 19.237 ;
     RECT  24 19.045 24.408 19.285 ;
     RECT  18.48 14.675 19.032 19.573 ;
     RECT  26.928 18.851 26.952 19.811 ;
     RECT  24 19.285 25.368 19.909 ;
     RECT  12.096 18.419 12.12 19.957 ;
     RECT  13.2 18.419 14.28 19.957 ;
     RECT  29.28 15.443 29.712 19.957 ;
     RECT  23.904 19.909 25.368 20.099 ;
     RECT  32.688 19.237 33.24 20.099 ;
     RECT  12.096 19.957 14.28 20.579 ;
     RECT  45.6 18.181 46.008 20.965 ;
     RECT  12.096 20.579 12.12 21.061 ;
     RECT  47.712 19.333 47.736 21.109 ;
     RECT  18.48 19.573 19.368 21.203 ;
     RECT  31.296 19.333 31.32 21.203 ;
     RECT  42.48 20.005 42.504 21.203 ;
     RECT  21.024 13.811 21.048 21.443 ;
     RECT  11.952 21.061 12.12 21.445 ;
     RECT  23.904 20.099 24.312 21.637 ;
     RECT  16.128 21.397 16.152 22.163 ;
     RECT  47.424 21.109 47.736 22.163 ;
     RECT  42.72 21.925 42.744 22.165 ;
     RECT  42.72 22.165 43.656 22.261 ;
     RECT  44.832 20.965 46.008 22.307 ;
     RECT  32.688 20.099 32.712 22.405 ;
     RECT  23.376 21.637 24.312 22.451 ;
     RECT  42.432 22.261 43.656 22.499 ;
     RECT  32.496 22.405 32.712 22.547 ;
     RECT  18.48 21.203 18.912 22.741 ;
     RECT  42.432 22.499 42.456 23.029 ;
     RECT  42.336 23.029 42.456 23.075 ;
     RECT  13.2 20.579 14.28 23.125 ;
     RECT  43.632 22.499 43.656 23.267 ;
     RECT  24 22.451 24.312 23.269 ;
     RECT  25.344 20.099 25.368 23.269 ;
     RECT  9.408 22.165 9.432 23.411 ;
     RECT  27.744 22.117 27.768 23.555 ;
     RECT  47.76 22.165 47.784 23.843 ;
     RECT  32.688 22.547 32.712 23.941 ;
     RECT  42.336 23.075 42.36 23.987 ;
     RECT  45.6 22.307 46.008 23.987 ;
     RECT  24 23.269 25.368 24.131 ;
     RECT  17.904 22.741 18.912 24.659 ;
     RECT  26.496 19.957 26.52 24.659 ;
     RECT  32.352 23.941 32.712 25.187 ;
     RECT  11.232 21.445 12.12 25.283 ;
     RECT  29.088 19.957 29.712 26.243 ;
     RECT  27.888 25.045 27.912 26.531 ;
     RECT  13.2 23.125 14.424 26.675 ;
     RECT  34.224 19.237 40.872 26.725 ;
     RECT  47.088 26.773 47.112 26.915 ;
     RECT  32.688 25.187 32.712 27.061 ;
     RECT  29.28 26.243 29.712 27.205 ;
     RECT  32.688 27.061 32.808 27.205 ;
     RECT  24 24.131 24.312 27.301 ;
     RECT  25.344 24.131 25.368 27.301 ;
     RECT  29.088 27.205 29.712 27.301 ;
     RECT  24 27.301 25.368 27.347 ;
     RECT  32.016 27.205 32.808 27.347 ;
     RECT  34.224 26.725 41.592 27.395 ;
     RECT  29.088 27.301 29.832 27.443 ;
     RECT  34.464 27.395 41.592 27.779 ;
     RECT  29.088 27.443 29.712 27.923 ;
     RECT  34.704 27.779 41.592 28.453 ;
     RECT  42.912 25.861 42.936 28.741 ;
     RECT  45.6 23.987 45.912 28.789 ;
     RECT  34.704 28.453 41.88 29.075 ;
     RECT  7.8 5.747 8.112 29.221 ;
     RECT  32.016 27.347 32.04 29.795 ;
     RECT  45.6 28.789 46.008 30.277 ;
     RECT  42.912 28.741 43.224 30.323 ;
     RECT  34.704 29.075 40.872 30.757 ;
     RECT  41.856 29.075 41.88 30.757 ;
     RECT  31.92 30.709 31.944 31.187 ;
     RECT  34.704 30.757 41.88 31.285 ;
     RECT  34.176 31.285 41.88 31.955 ;
     RECT  34.176 31.955 40.872 32.437 ;
     RECT  34.08 32.437 40.872 33.013 ;
     RECT  41.856 31.955 41.88 33.013 ;
     RECT  34.08 33.013 41.88 33.155 ;
     RECT  29.28 27.923 29.712 33.253 ;
     RECT  45.408 30.277 46.008 34.115 ;
     RECT  34.08 33.155 40.872 34.163 ;
     RECT  29.232 33.253 29.712 34.165 ;
     RECT  41.856 33.155 41.88 35.365 ;
     RECT  43.2 30.323 43.224 35.365 ;
     RECT  41.856 35.365 41.976 35.411 ;
     RECT  43.2 35.365 44.184 35.939 ;
     RECT  41.952 35.411 41.976 36.037 ;
     RECT  43.2 35.939 43.224 36.037 ;
     RECT  29.136 34.165 29.712 36.517 ;
     RECT  45.408 34.115 45.912 37.091 ;
     RECT  41.952 36.037 43.224 37.573 ;
     RECT  31.584 37.573 31.608 37.717 ;
     RECT  34.704 34.163 40.872 38.101 ;
     RECT  41.952 37.573 44.184 38.101 ;
     RECT  34.704 38.101 44.184 38.149 ;
     RECT  45.504 37.091 45.912 38.149 ;
     RECT  31.248 37.717 31.608 38.483 ;
     RECT  34.704 38.149 45.912 38.675 ;
     RECT  28.176 36.517 29.712 38.725 ;
     RECT  31.584 38.483 31.608 38.819 ;
     RECT  34.704 38.675 40.968 39.155 ;
     RECT  41.952 38.675 45.912 39.443 ;
     RECT  47.52 38.725 47.544 39.443 ;
     RECT  42.48 39.443 45.912 39.493 ;
     RECT  42.48 39.493 46.056 39.827 ;
     RECT  42.72 39.827 46.056 39.829 ;
     RECT  28.176 38.725 29.928 40.693 ;
     RECT  34.704 39.155 40.872 41.075 ;
     RECT  24 27.347 25.224 41.123 ;
     RECT  31.824 40.837 31.848 41.651 ;
     RECT  13.2 26.675 13.608 41.797 ;
     RECT  42.72 39.829 46.104 42.709 ;
     RECT  12.096 25.283 12.12 42.803 ;
     RECT  18.48 24.659 18.912 42.803 ;
     RECT  34.704 41.075 40.512 42.851 ;
     RECT  42.432 42.709 46.104 43.477 ;
     RECT  34.704 42.851 36.168 43.667 ;
     RECT  37.248 42.851 40.512 43.861 ;
     RECT  34.8 43.667 36.168 43.955 ;
     RECT  37.248 43.861 41.016 44.147 ;
     RECT  38.592 44.147 41.016 44.245 ;
     RECT  28.176 40.693 30.216 44.339 ;
     RECT  37.056 44.245 37.08 44.435 ;
     RECT  18.6 42.803 18.912 44.629 ;
     RECT  42.432 43.477 46.152 45.059 ;
     RECT  38.592 44.245 41.352 45.301 ;
     RECT  34.8 43.955 35.304 45.397 ;
     RECT  36.432 45.301 36.456 45.397 ;
     RECT  18.432 44.629 18.912 45.493 ;
     RECT  38.592 45.301 41.64 45.493 ;
     RECT  15.84 42.133 15.864 45.541 ;
     RECT  18 45.493 18.912 45.541 ;
     RECT  24 41.123 24.312 45.541 ;
     RECT  28.176 44.339 29.712 45.541 ;
     RECT  7.632 29.221 8.112 45.589 ;
     RECT  14.688 42.325 14.712 45.589 ;
     RECT  15.84 45.541 16.008 45.589 ;
     RECT  43.152 45.059 46.152 45.635 ;
     RECT  27.792 45.541 29.976 45.685 ;
     RECT  18 45.541 19.896 45.877 ;
     RECT  13.2 41.797 13.656 46.021 ;
     RECT  38.16 45.493 41.64 46.069 ;
     RECT  7.632 45.589 8.808 46.117 ;
     RECT  33.408 45.541 33.432 46.117 ;
     RECT  34.8 45.397 36.456 46.117 ;
     RECT  27.168 45.685 29.976 46.259 ;
     RECT  7.44 46.117 8.808 46.693 ;
     RECT  14.688 45.589 16.008 46.787 ;
     RECT  24 45.541 25.08 47.027 ;
     RECT  17.376 45.877 19.896 47.075 ;
     RECT  7.44 46.693 8.904 47.317 ;
     RECT  17.616 47.075 19.896 47.555 ;
     RECT  2.4 2.151 2.712 47.749 ;
     RECT  6.48 47.317 8.904 47.893 ;
     RECT  43.152 45.635 46.056 47.893 ;
     RECT  42.768 47.893 46.056 47.939 ;
     RECT  6.48 47.893 9.24 48.371 ;
     RECT  7.632 48.371 9.24 48.469 ;
     RECT  24 47.027 24.504 48.517 ;
     RECT  33.408 46.117 36.456 48.709 ;
     RECT  37.584 46.069 41.64 48.709 ;
     RECT  6.48 48.371 6.648 48.853 ;
     RECT  14.688 46.787 15.96 48.853 ;
     RECT  20.88 45.589 20.904 48.901 ;
     RECT  22.416 48.421 22.44 48.901 ;
     RECT  31.248 48.853 31.272 48.949 ;
     RECT  32.256 48.805 32.28 48.949 ;
     RECT  5.904 48.853 6.648 48.997 ;
     RECT  13.104 46.021 13.656 48.997 ;
     RECT  17.712 47.555 19.896 48.997 ;
     RECT  24 48.517 24.792 48.997 ;
     RECT  26.208 47.893 26.232 48.997 ;
     RECT  27.792 46.259 29.976 48.997 ;
     RECT  31.248 48.949 32.28 48.997 ;
     RECT  33.408 48.709 41.64 48.997 ;
     RECT  42.768 47.939 44.52 48.997 ;
     RECT  2.4 47.749 3.432 49.043 ;
     RECT  20.88 48.901 22.44 49.043 ;
     RECT  14.688 48.853 16.44 49.045 ;
     RECT  17.424 48.997 19.896 49.045 ;
     RECT  27.792 48.997 44.52 49.093 ;
     RECT  45.6 47.939 46.056 49.093 ;
     RECT  10.512 45.541 11.112 49.141 ;
     RECT  27.792 49.093 46.056 49.189 ;
     RECT  27.792 49.189 46.104 49.237 ;
     RECT  27.648 49.237 46.104 49.333 ;
     RECT  5.184 48.997 6.648 49.381 ;
     RECT  7.632 48.469 9.528 49.381 ;
     RECT  14.688 49.045 19.896 49.381 ;
     RECT  20.88 49.043 22.2 49.381 ;
     RECT  23.904 48.997 25.08 49.381 ;
     RECT  26.064 48.997 26.232 49.381 ;
     RECT  27.648 49.333 46.392 49.381 ;
     RECT  5.184 49.381 9.528 49.429 ;
     RECT  10.512 49.141 11.256 49.429 ;
     RECT  23.904 49.381 26.232 49.429 ;
     RECT  27.216 49.381 46.392 49.429 ;
     RECT  5.184 49.429 11.256 49.477 ;
     RECT  12.384 48.997 13.656 49.477 ;
     RECT  5.04 49.477 13.656 49.525 ;
     RECT  14.688 49.381 22.2 49.525 ;
     RECT  2.4 49.043 2.712 49.689 ;
     RECT  2.4 49.689 2.52 49.703 ;
     RECT  5.04 49.525 22.2 50.149 ;
     RECT  23.904 49.429 46.392 50.149 ;
     RECT  3.888 50.149 22.2 51.756 ;
     RECT  3.912 51.756 4.032 51.792 ;
     RECT  4.056 51.756 4.176 51.792 ;
     RECT  4.2 51.756 4.32 51.792 ;
     RECT  4.344 51.756 4.464 51.792 ;
     RECT  4.488 51.756 4.608 51.792 ;
     RECT  4.632 51.756 4.752 51.792 ;
     RECT  4.776 51.756 4.896 51.792 ;
     RECT  4.92 51.756 5.04 51.792 ;
     RECT  5.064 51.756 5.184 51.792 ;
     RECT  5.208 51.756 5.328 51.792 ;
     RECT  5.352 51.756 5.472 51.792 ;
     RECT  5.496 51.756 5.616 51.792 ;
     RECT  5.64 51.756 5.76 51.792 ;
     RECT  5.784 51.756 5.904 51.792 ;
     RECT  5.928 51.756 6.048 51.792 ;
     RECT  6.072 51.756 6.192 51.792 ;
     RECT  6.216 51.756 6.336 51.792 ;
     RECT  6.36 51.756 6.48 51.792 ;
     RECT  6.504 51.756 6.624 51.792 ;
     RECT  6.648 51.756 6.768 51.792 ;
     RECT  6.792 51.756 6.912 51.792 ;
     RECT  6.936 51.756 7.056 51.792 ;
     RECT  7.08 51.756 7.2 51.792 ;
     RECT  7.224 51.756 7.344 51.792 ;
     RECT  7.368 51.756 7.488 51.792 ;
     RECT  7.512 51.756 7.632 51.792 ;
     RECT  7.656 51.756 7.776 51.792 ;
     RECT  7.8 51.756 7.92 51.792 ;
     RECT  7.944 51.756 8.064 51.792 ;
     RECT  8.088 51.756 8.208 51.792 ;
     RECT  8.232 51.756 8.352 51.792 ;
     RECT  8.376 51.756 8.496 51.792 ;
     RECT  8.52 51.756 8.64 51.792 ;
     RECT  8.664 51.756 8.784 51.792 ;
     RECT  8.808 51.756 8.928 51.792 ;
     RECT  8.952 51.756 9.072 51.792 ;
     RECT  9.096 51.756 9.216 51.792 ;
     RECT  9.24 51.756 9.36 51.792 ;
     RECT  9.384 51.756 9.504 51.792 ;
     RECT  9.528 51.756 9.648 51.792 ;
     RECT  9.672 51.756 9.792 51.792 ;
     RECT  9.816 51.756 9.936 51.792 ;
     RECT  9.96 51.756 10.08 51.792 ;
     RECT  10.104 51.756 10.224 51.792 ;
     RECT  10.248 51.756 10.368 51.792 ;
     RECT  10.392 51.756 10.512 51.792 ;
     RECT  10.536 51.756 10.656 51.792 ;
     RECT  10.68 51.756 10.8 51.792 ;
     RECT  10.824 51.756 10.944 51.792 ;
     RECT  10.968 51.756 11.088 51.792 ;
     RECT  11.112 51.756 11.232 51.792 ;
     RECT  11.256 51.756 11.376 51.792 ;
     RECT  11.4 51.756 11.52 51.792 ;
     RECT  11.544 51.756 11.664 51.792 ;
     RECT  11.688 51.756 11.808 51.792 ;
     RECT  11.832 51.756 11.952 51.792 ;
     RECT  11.976 51.756 12.096 51.792 ;
     RECT  12.12 51.756 12.24 51.792 ;
     RECT  12.264 51.756 12.384 51.792 ;
     RECT  12.408 51.756 12.528 51.792 ;
     RECT  12.552 51.756 12.672 51.792 ;
     RECT  12.696 51.756 12.816 51.792 ;
     RECT  12.84 51.756 12.96 51.792 ;
     RECT  12.984 51.756 13.104 51.792 ;
     RECT  13.128 51.756 13.248 51.792 ;
     RECT  13.272 51.756 13.392 51.792 ;
     RECT  13.416 51.756 13.536 51.792 ;
     RECT  13.56 51.756 13.68 51.792 ;
     RECT  13.704 51.756 13.824 51.792 ;
     RECT  13.848 51.756 13.968 51.792 ;
     RECT  13.992 51.756 14.112 51.792 ;
     RECT  14.136 51.756 14.256 51.792 ;
     RECT  14.28 51.756 14.4 51.792 ;
     RECT  14.424 51.756 14.544 51.792 ;
     RECT  14.568 51.756 14.688 51.792 ;
     RECT  14.712 51.756 14.832 51.792 ;
     RECT  14.856 51.756 14.976 51.792 ;
     RECT  15 51.756 15.12 51.792 ;
     RECT  15.144 51.756 15.264 51.792 ;
     RECT  15.288 51.756 15.408 51.792 ;
     RECT  15.432 51.756 15.552 51.792 ;
     RECT  15.576 51.756 15.696 51.792 ;
     RECT  15.72 51.756 15.84 51.792 ;
     RECT  15.864 51.756 15.984 51.792 ;
     RECT  16.008 51.756 16.128 51.792 ;
     RECT  16.152 51.756 16.272 51.792 ;
     RECT  16.296 51.756 16.416 51.792 ;
     RECT  16.44 51.756 16.56 51.792 ;
     RECT  16.584 51.756 16.704 51.792 ;
     RECT  16.728 51.756 16.848 51.792 ;
     RECT  16.872 51.756 16.992 51.792 ;
     RECT  17.016 51.756 17.136 51.792 ;
     RECT  17.16 51.756 17.28 51.792 ;
     RECT  17.304 51.756 17.424 51.792 ;
     RECT  17.448 51.756 17.568 51.792 ;
     RECT  17.592 51.756 17.712 51.792 ;
     RECT  17.736 51.756 17.856 51.792 ;
     RECT  17.88 51.756 18 51.792 ;
     RECT  18.024 51.756 18.144 51.792 ;
     RECT  18.168 51.756 18.288 51.792 ;
     RECT  18.312 51.756 18.432 51.792 ;
     RECT  18.456 51.756 18.576 51.792 ;
     RECT  18.6 51.756 18.72 51.792 ;
     RECT  18.744 51.756 18.864 51.792 ;
     RECT  18.888 51.756 19.008 51.792 ;
     RECT  19.032 51.756 19.152 51.792 ;
     RECT  19.176 51.756 19.296 51.792 ;
     RECT  19.32 51.756 19.44 51.792 ;
     RECT  19.464 51.756 19.584 51.792 ;
     RECT  19.608 51.756 19.728 51.792 ;
     RECT  19.752 51.756 19.872 51.792 ;
     RECT  19.896 51.756 20.016 51.792 ;
     RECT  20.04 51.756 20.16 51.792 ;
     RECT  20.184 51.756 20.304 51.792 ;
     RECT  20.328 51.756 20.448 51.792 ;
     RECT  20.472 51.756 20.592 51.792 ;
     RECT  20.616 51.756 20.736 51.792 ;
     RECT  20.76 51.756 20.88 51.792 ;
     RECT  20.904 51.756 21.024 51.792 ;
     RECT  21.048 51.756 21.168 51.792 ;
     RECT  21.192 51.756 21.312 51.792 ;
     RECT  21.336 51.756 21.456 51.792 ;
     RECT  21.48 51.756 21.6 51.792 ;
     RECT  21.624 51.756 21.744 51.792 ;
     RECT  21.768 51.756 21.888 51.792 ;
     RECT  21.912 51.756 22.032 51.792 ;
     RECT  22.056 51.756 22.176 51.792 ;
     RECT  23.472 50.149 46.392 51.756 ;
     RECT  23.496 51.756 23.616 51.792 ;
     RECT  23.64 51.756 23.76 51.792 ;
     RECT  23.784 51.756 23.904 51.792 ;
     RECT  23.928 51.756 24.048 51.792 ;
     RECT  24.072 51.756 24.192 51.792 ;
     RECT  24.216 51.756 24.336 51.792 ;
     RECT  24.36 51.756 24.48 51.792 ;
     RECT  24.504 51.756 24.624 51.792 ;
     RECT  24.648 51.756 24.768 51.792 ;
     RECT  24.792 51.756 24.912 51.792 ;
     RECT  24.936 51.756 25.056 51.792 ;
     RECT  25.08 51.756 25.2 51.792 ;
     RECT  25.224 51.756 25.344 51.792 ;
     RECT  25.368 51.756 25.488 51.792 ;
     RECT  25.512 51.756 25.632 51.792 ;
     RECT  25.656 51.756 25.776 51.792 ;
     RECT  25.8 51.756 25.92 51.792 ;
     RECT  25.944 51.756 26.064 51.792 ;
     RECT  26.088 51.756 26.208 51.792 ;
     RECT  26.232 51.756 26.352 51.792 ;
     RECT  26.376 51.756 26.496 51.792 ;
     RECT  26.52 51.756 26.64 51.792 ;
     RECT  26.664 51.756 26.784 51.792 ;
     RECT  26.808 51.756 26.928 51.792 ;
     RECT  26.952 51.756 27.072 51.792 ;
     RECT  27.096 51.756 27.216 51.792 ;
     RECT  27.24 51.756 27.36 51.792 ;
     RECT  27.384 51.756 27.504 51.792 ;
     RECT  27.528 51.756 27.648 51.792 ;
     RECT  27.672 51.756 27.792 51.792 ;
     RECT  27.816 51.756 27.936 51.792 ;
     RECT  27.96 51.756 28.512 51.792 ;
     RECT  28.536 51.756 28.656 51.792 ;
     RECT  28.68 51.756 28.8 51.792 ;
     RECT  28.824 51.756 28.944 51.792 ;
     RECT  28.968 51.756 29.088 51.792 ;
     RECT  29.112 51.756 29.232 51.792 ;
     RECT  29.256 51.756 29.376 51.792 ;
     RECT  29.4 51.756 29.52 51.792 ;
     RECT  29.544 51.756 29.664 51.792 ;
     RECT  29.688 51.756 29.808 51.792 ;
     RECT  29.832 51.756 29.952 51.792 ;
     RECT  29.976 51.756 30.096 51.792 ;
     RECT  30.12 51.756 30.24 51.792 ;
     RECT  30.264 51.756 30.384 51.792 ;
     RECT  30.408 51.756 30.528 51.792 ;
     RECT  30.552 51.756 30.672 51.792 ;
     RECT  30.696 51.756 30.816 51.792 ;
     RECT  30.84 51.756 30.96 51.792 ;
     RECT  30.984 51.756 31.104 51.792 ;
     RECT  31.128 51.756 31.248 51.792 ;
     RECT  31.272 51.756 31.392 51.792 ;
     RECT  31.416 51.756 31.536 51.792 ;
     RECT  31.56 51.756 31.68 51.792 ;
     RECT  31.704 51.756 31.824 51.792 ;
     RECT  31.848 51.756 31.968 51.792 ;
     RECT  31.992 51.756 32.112 51.792 ;
     RECT  32.136 51.756 32.256 51.792 ;
     RECT  32.28 51.756 32.4 51.792 ;
     RECT  32.424 51.756 32.544 51.792 ;
     RECT  32.568 51.756 32.688 51.792 ;
     RECT  32.712 51.756 32.832 51.792 ;
     RECT  32.856 51.756 32.976 51.792 ;
     RECT  33 51.756 33.12 51.792 ;
     RECT  33.144 51.756 33.264 51.792 ;
     RECT  33.288 51.756 33.408 51.792 ;
     RECT  33.432 51.756 33.552 51.792 ;
     RECT  33.576 51.756 33.696 51.792 ;
     RECT  33.72 51.756 33.84 51.792 ;
     RECT  33.864 51.756 33.984 51.792 ;
     RECT  34.008 51.756 34.128 51.792 ;
     RECT  34.152 51.756 34.272 51.792 ;
     RECT  34.296 51.756 34.416 51.792 ;
     RECT  34.44 51.756 34.56 51.792 ;
     RECT  34.584 51.756 34.704 51.792 ;
     RECT  34.728 51.756 34.848 51.792 ;
     RECT  34.872 51.756 34.992 51.792 ;
     RECT  35.016 51.756 35.136 51.792 ;
     RECT  35.16 51.756 35.28 51.792 ;
     RECT  35.304 51.756 35.424 51.792 ;
     RECT  35.448 51.756 35.568 51.792 ;
     RECT  35.592 51.756 35.712 51.792 ;
     RECT  35.736 51.756 35.856 51.792 ;
     RECT  35.88 51.756 36 51.792 ;
     RECT  36.024 51.756 36.144 51.792 ;
     RECT  36.168 51.756 36.288 51.792 ;
     RECT  36.312 51.756 36.432 51.792 ;
     RECT  36.456 51.756 36.576 51.792 ;
     RECT  36.6 51.756 36.72 51.792 ;
     RECT  36.744 51.756 36.864 51.792 ;
     RECT  36.888 51.756 37.008 51.792 ;
     RECT  37.032 51.756 37.152 51.792 ;
     RECT  37.176 51.756 37.296 51.792 ;
     RECT  37.32 51.756 37.44 51.792 ;
     RECT  37.464 51.756 37.584 51.792 ;
     RECT  37.608 51.756 37.728 51.792 ;
     RECT  37.752 51.756 37.872 51.792 ;
     RECT  37.896 51.756 38.016 51.792 ;
     RECT  38.04 51.756 38.16 51.792 ;
     RECT  38.184 51.756 38.304 51.792 ;
     RECT  38.328 51.756 38.448 51.792 ;
     RECT  38.472 51.756 38.592 51.792 ;
     RECT  38.616 51.756 38.736 51.792 ;
     RECT  38.76 51.756 38.88 51.792 ;
     RECT  38.904 51.756 39.024 51.792 ;
     RECT  39.048 51.756 39.168 51.792 ;
     RECT  39.192 51.756 39.312 51.792 ;
     RECT  39.336 51.756 39.456 51.792 ;
     RECT  39.48 51.756 39.6 51.792 ;
     RECT  39.624 51.756 39.744 51.792 ;
     RECT  39.768 51.756 39.888 51.792 ;
     RECT  39.912 51.756 40.032 51.792 ;
     RECT  40.056 51.756 40.176 51.792 ;
     RECT  40.2 51.756 40.32 51.792 ;
     RECT  40.344 51.756 40.464 51.792 ;
     RECT  40.488 51.756 40.608 51.792 ;
     RECT  40.632 51.756 40.752 51.792 ;
     RECT  40.776 51.756 40.896 51.792 ;
     RECT  40.92 51.756 41.04 51.792 ;
     RECT  41.064 51.756 41.184 51.792 ;
     RECT  41.208 51.756 41.328 51.792 ;
     RECT  41.352 51.756 41.472 51.792 ;
     RECT  41.496 51.756 41.616 51.792 ;
     RECT  41.64 51.756 41.76 51.792 ;
     RECT  41.784 51.756 41.904 51.792 ;
     RECT  41.928 51.756 42.048 51.792 ;
     RECT  42.072 51.756 42.192 51.792 ;
     RECT  42.216 51.756 42.336 51.792 ;
     RECT  42.36 51.756 42.48 51.792 ;
     RECT  42.504 51.756 42.624 51.792 ;
     RECT  42.648 51.756 42.768 51.792 ;
     RECT  42.792 51.756 42.912 51.792 ;
     RECT  42.936 51.756 43.056 51.792 ;
     RECT  43.08 51.756 43.2 51.792 ;
     RECT  43.224 51.756 43.344 51.792 ;
     RECT  43.368 51.756 43.488 51.792 ;
     RECT  43.512 51.756 43.632 51.792 ;
     RECT  43.656 51.756 43.776 51.792 ;
     RECT  43.8 51.756 43.92 51.792 ;
     RECT  43.944 51.756 44.064 51.792 ;
     RECT  44.088 51.756 44.208 51.792 ;
     RECT  44.232 51.756 44.352 51.792 ;
     RECT  44.376 51.756 44.496 51.792 ;
     RECT  44.52 51.756 44.64 51.792 ;
     RECT  44.664 51.756 44.784 51.792 ;
     RECT  44.808 51.756 44.928 51.792 ;
     RECT  44.952 51.756 45.072 51.792 ;
     RECT  45.096 51.756 45.216 51.792 ;
     RECT  45.24 51.756 45.36 51.792 ;
     RECT  45.384 51.756 45.504 51.792 ;
     RECT  45.528 51.756 45.648 51.792 ;
     RECT  45.672 51.756 45.792 51.792 ;
     RECT  45.816 51.756 45.936 51.792 ;
     RECT  45.96 51.756 46.08 51.792 ;
     RECT  46.104 51.756 46.224 51.792 ;
     RECT  46.248 51.756 46.368 51.792 ;
     RECT  28.296 0.016 29.472 0.132 ;
     RECT  28.248 0.132 29.52 1.859 ;
     RECT  20.616 1.763 21.888 2.291 ;
     RECT  36.888 1.763 38.016 1.811 ;
     RECT  8.112 1.811 9.504 1.859 ;
     RECT  24.792 1.811 26.064 1.859 ;
     RECT  30.552 1.811 32.256 2.291 ;
     RECT  39.192 1.811 40.176 1.859 ;
     RECT  46.968 1.811 48.384 1.859 ;
     RECT  10.392 1.859 11.376 2.339 ;
     RECT  13.512 1.859 14.544 2.291 ;
     RECT  22.488 1.859 24 2.867 ;
     RECT  26.496 1.859 26.64 1.907 ;
     RECT  29.4 1.859 29.52 2.137 ;
     RECT  46.968 1.859 47.928 2.291 ;
     RECT  11.544 1.907 12.528 2.291 ;
     RECT  17.304 1.907 18.6 2.291 ;
     RECT  26.496 1.907 26.52 3.157 ;
     RECT  45.912 1.907 46.944 2.291 ;
     RECT  43.656 2.243 44.64 2.291 ;
     RECT  11.4 2.291 12.528 2.339 ;
     RECT  16.008 2.291 17.136 2.867 ;
     RECT  17.16 2.291 18.6 2.867 ;
     RECT  31.872 2.291 32.256 2.821 ;
     RECT  35.112 2.291 35.208 3.541 ;
     RECT  40.68 2.291 41.952 3.397 ;
     RECT  47.904 2.291 47.928 2.821 ;
     RECT  17.616 2.867 18.6 3.301 ;
     RECT  40.68 3.397 41.904 5.077 ;
     RECT  16.584 5.029 17.616 5.747 ;
     RECT  33.624 5.029 34.8 5.077 ;
     RECT  35.208 5.173 36.72 5.893 ;
     RECT  8.112 5.747 9.096 6.805 ;
     RECT  40.68 5.747 41.904 6.805 ;
     RECT  35.208 5.893 36.432 6.899 ;
     RECT  11.4 6.229 12.528 6.275 ;
     RECT  24.408 6.229 25.92 7.475 ;
     RECT  8.112 6.805 9.6 7.427 ;
     RECT  27.912 6.805 29.4 8.579 ;
     RECT  40.872 6.805 41.904 7.235 ;
     RECT  35.208 6.899 36.72 8.437 ;
     RECT  39.36 7.043 39.84 7.717 ;
     RECT  40.872 7.235 42.144 8.915 ;
     RECT  24.408 7.475 24.552 7.957 ;
     RECT  38.376 7.717 39.84 8.675 ;
     RECT  28.224 8.579 29.4 9.829 ;
     RECT  12.12 8.581 13.2 8.965 ;
     RECT  38.376 8.675 40.2 9.253 ;
     RECT  40.872 8.915 41.688 9.109 ;
     RECT  12.12 8.965 13.104 16.835 ;
     RECT  32.856 9.203 33.84 10.883 ;
     RECT  39.096 9.253 40.2 15.349 ;
     RECT  28.248 9.829 29.4 12.659 ;
     RECT  17.448 9.973 18.432 12.325 ;
     RECT  16.104 10.261 17.424 11.171 ;
     RECT  13.656 10.307 14.28 11.413 ;
     RECT  35.304 10.451 36.48 11.413 ;
     RECT  19.32 10.597 20.544 13.667 ;
     RECT  32.856 10.883 34.224 12.707 ;
     RECT  37.32 10.931 38.4 11.459 ;
     RECT  44.28 11.125 45.6 18.227 ;
     RECT  45.912 11.171 46.2 12.517 ;
     RECT  10.872 11.413 12.096 12.755 ;
     RECT  27.936 11.555 28.224 11.941 ;
     RECT  26.808 11.941 28.224 12.659 ;
     RECT  30.648 11.941 31.92 12.085 ;
     RECT  23.184 12.179 24 12.181 ;
     RECT  35.688 12.179 36.816 12.755 ;
     RECT  21.384 12.181 22.8 12.227 ;
     RECT  22.824 12.181 24 14.339 ;
     RECT  30.84 12.227 31.872 12.803 ;
     RECT  26.808 12.659 29.4 13.139 ;
     RECT  32.712 12.707 34.224 14.773 ;
     RECT  35.304 12.755 36.816 13.621 ;
     RECT  30.648 12.803 31.872 13.139 ;
     RECT  26.928 13.139 29.4 13.573 ;
     RECT  26.928 13.573 28.416 13.621 ;
     RECT  26.952 13.621 28.416 15.397 ;
     RECT  35.304 13.621 36.768 14.627 ;
     RECT  19.032 13.667 20.544 13.811 ;
     RECT  37.032 13.861 38.016 14.821 ;
     RECT  38.04 13.861 39.072 15.589 ;
     RECT  23.376 14.339 24 15.301 ;
     RECT  35.304 14.627 36.816 16.501 ;
     RECT  33.048 14.773 34.224 17.123 ;
     RECT  24.312 15.349 25.68 17.315 ;
     RECT  25.704 15.349 26.928 17.315 ;
     RECT  26.952 15.397 27.984 16.787 ;
     RECT  28.008 15.443 29.28 16.787 ;
     RECT  31.368 15.829 32.688 17.075 ;
     RECT  35.304 16.501 36.768 17.123 ;
     RECT  26.952 16.787 27.528 18.181 ;
     RECT  12.12 16.835 13.2 17.989 ;
     RECT  10.728 17.029 12.096 18.035 ;
     RECT  31.728 17.075 32.688 17.605 ;
     RECT  32.712 17.123 34.224 18.709 ;
     RECT  35.208 17.123 36.768 17.269 ;
     RECT  35.208 17.269 36.72 19.237 ;
     RECT  12.12 18.419 13.2 19.957 ;
     RECT  33.096 18.709 34.224 19.237 ;
     RECT  31.728 18.755 32.688 19.333 ;
     RECT  33.24 19.237 34.224 20.099 ;
     RECT  31.32 19.333 32.688 21.203 ;
     RECT  25.368 19.957 26.496 24.659 ;
     RECT  24.312 20.099 25.344 23.269 ;
     RECT  32.712 20.099 34.224 27.061 ;
     RECT  12.12 20.579 13.2 42.803 ;
     RECT  46.008 21.109 47.424 22.163 ;
     RECT  32.496 21.203 32.688 22.405 ;
     RECT  42.48 21.203 42.504 21.925 ;
     RECT  42.48 21.925 42.72 22.261 ;
     RECT  26.52 22.117 27.744 23.555 ;
     RECT  27.768 22.117 29.088 23.555 ;
     RECT  8.112 22.165 9.408 23.411 ;
     RECT  43.656 22.165 44.832 22.307 ;
     RECT  42.456 22.499 43.632 23.075 ;
     RECT  32.496 22.547 32.688 23.941 ;
     RECT  40.872 23.029 42.336 23.987 ;
     RECT  42.36 23.075 43.632 23.267 ;
     RECT  26.52 23.555 29.088 24.659 ;
     RECT  24.312 24.131 25.344 27.301 ;
     RECT  27.888 24.659 29.088 25.045 ;
     RECT  27.912 25.045 29.088 26.243 ;
     RECT  27.912 26.243 29.28 26.531 ;
     RECT  29.088 26.531 29.28 27.205 ;
     RECT  41.592 26.725 42.912 28.453 ;
     RECT  45.912 26.773 47.088 26.915 ;
     RECT  32.808 27.061 34.224 27.347 ;
     RECT  41.88 28.453 42.912 30.323 ;
     RECT  40.872 29.075 41.856 30.757 ;
     RECT  41.88 30.323 43.2 35.365 ;
     RECT  40.872 31.955 41.856 33.013 ;
     RECT  40.872 33.155 41.856 35.411 ;
     RECT  41.976 35.365 43.2 36.037 ;
     RECT  44.184 35.365 45.408 35.939 ;
     RECT  40.872 35.411 41.952 38.101 ;
     RECT  45.408 37.091 45.504 37.573 ;
     RECT  44.184 37.573 45.504 38.149 ;
     RECT  40.968 38.675 41.952 39.155 ;
     RECT  40.872 39.155 41.952 39.443 ;
     RECT  13.656 42.325 14.688 49.525 ;
     RECT  14.712 42.325 15.84 45.589 ;
     RECT  36.168 42.851 37.248 43.955 ;
     RECT  41.016 43.861 42.432 44.245 ;
     RECT  35.304 43.955 37.248 44.147 ;
     RECT  35.304 44.147 38.592 44.245 ;
     RECT  35.304 44.245 37.056 44.435 ;
     RECT  37.08 44.245 38.592 44.435 ;
     RECT  41.352 44.245 42.432 45.059 ;
     RECT  29.712 44.339 29.976 45.541 ;
     RECT  35.304 44.435 36.456 45.301 ;
     RECT  38.16 44.435 38.592 45.493 ;
     RECT  41.352 45.059 43.152 45.301 ;
     RECT  35.304 45.301 36.432 45.397 ;
     RECT  41.64 45.301 43.152 47.893 ;
     RECT  33.432 45.541 34.8 46.117 ;
     RECT  19.896 45.589 20.88 49.381 ;
     RECT  16.008 45.877 17.376 46.787 ;
     RECT  36.456 46.069 37.584 48.709 ;
     RECT  15.96 46.787 17.376 47.075 ;
     RECT  24.504 47.027 25.08 47.893 ;
     RECT  17.616 47.555 17.712 48.853 ;
     RECT  9.24 47.893 10.512 48.469 ;
     RECT  24.504 47.893 26.208 48.517 ;
     RECT  41.64 47.893 42.768 48.997 ;
     RECT  44.52 47.939 45.6 49.093 ;
     RECT  6.648 48.371 7.632 49.381 ;
     RECT  20.904 48.421 22.416 48.901 ;
     RECT  9.528 48.469 10.512 49.429 ;
     RECT  24.792 48.517 26.208 48.997 ;
     RECT  32.28 48.805 33.408 48.997 ;
     RECT  16.44 48.853 17.712 48.997 ;
     RECT  29.976 48.853 31.248 48.997 ;
     RECT  31.272 48.853 32.256 48.949 ;
     RECT  11.112 48.997 12.384 49.141 ;
     RECT  16.44 48.997 17.424 49.045 ;
     RECT  22.44 48.997 23.904 49.043 ;
     RECT  25.08 48.997 26.064 49.381 ;
     RECT  22.2 49.043 23.904 50.149 ;
     RECT  11.256 49.141 12.384 49.477 ;
     RECT  26.232 49.237 27.648 49.381 ;
     RECT  26.232 49.381 27.216 49.429 ;
     RECT  22.2 50.149 23.472 51.708 ;
     RECT  22.248 51.708 23.424 51.792 ;
  END
END ot_hbm_static_cfg_collar
END LIBRARY
